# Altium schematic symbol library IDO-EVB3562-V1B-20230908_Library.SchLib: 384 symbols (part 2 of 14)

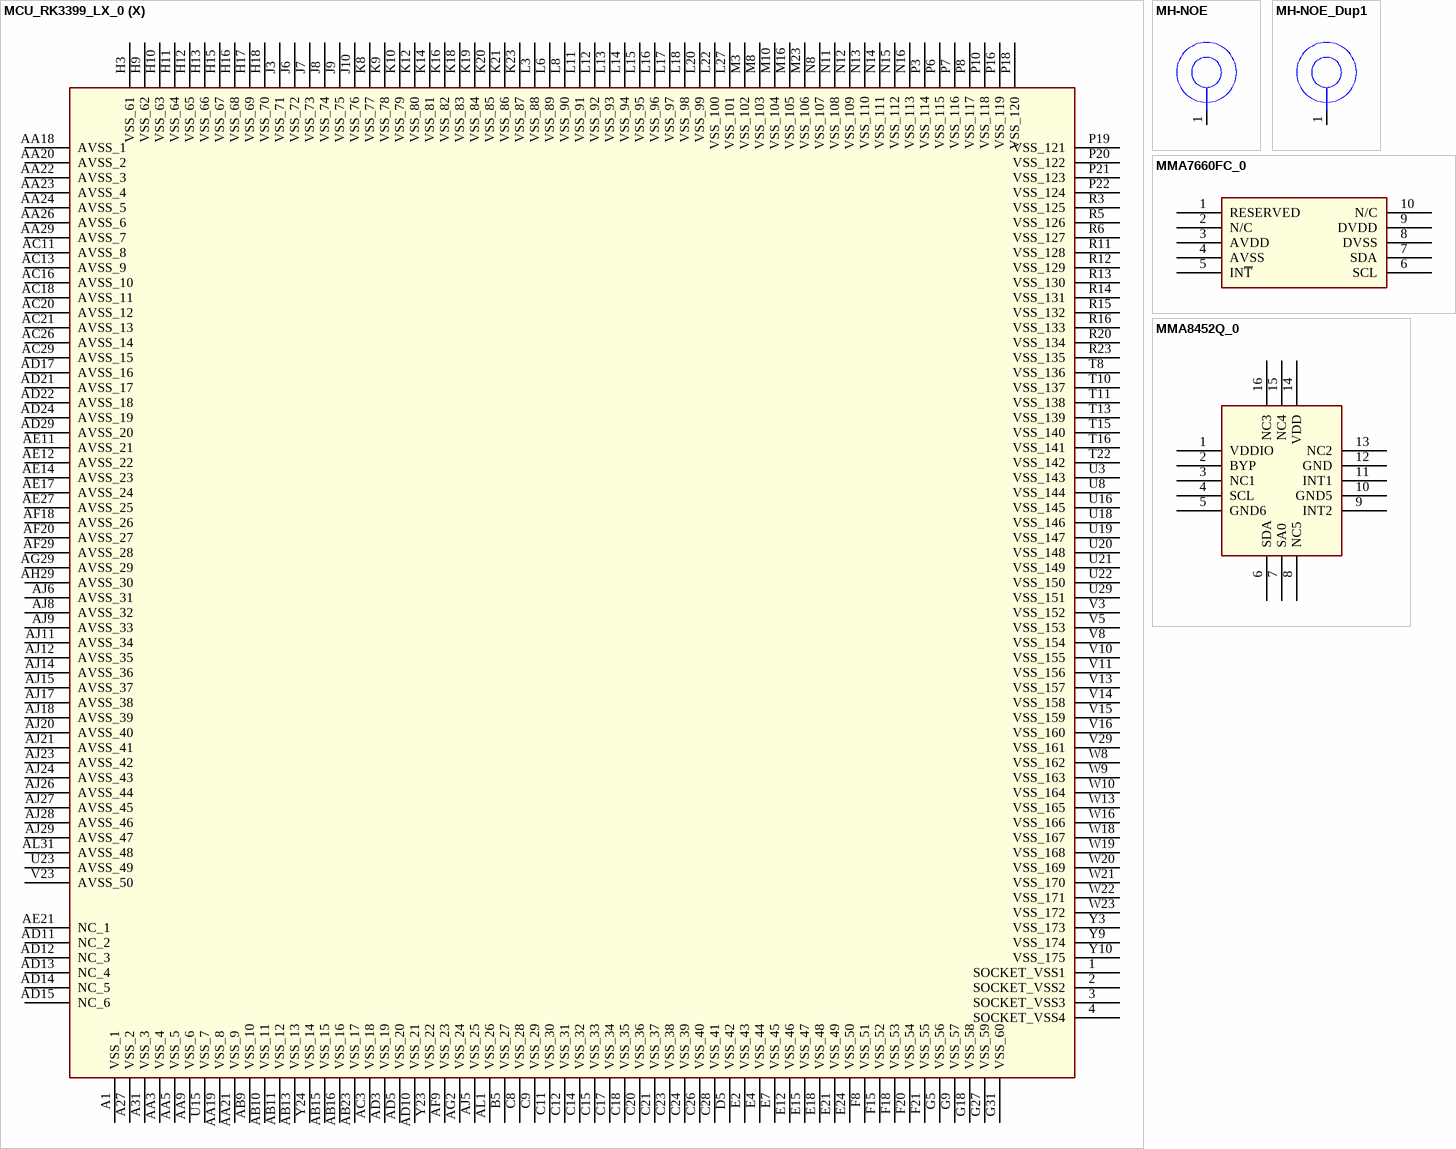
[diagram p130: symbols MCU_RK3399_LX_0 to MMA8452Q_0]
## MCU_RK3399_LX_0
designator U?
part A pins: A2 DDR0_CS1N, A3 DDR0_A12, A4 DDR0_A10, A5 DDR0_CKE0, A6 DDR0_A9, A7 DDR0_A7, A8 DDR0_A5, A9 DDR0_A3, A10 DDR0_A1, A11 DDR0_DQ10, A12 DDR0_DQ12, A13 DDR0_DQ13, A14 DDR0_DQ14, A15 DDR0_DQ1, A16 DDR0_DQ3, A17 DDR0_DQ5, A18 DDR0_DQ6, A19 DDR0_DQ16, A20 DDR0_DQ18, A21 DDR0_DQ20, A22 DDR0_DQ23, A23 DDR0_DQ24, A24 DDR0_DQ26, A25 DDR0_DQ27, A26 DDR0_DQ29, B2 DDR0_BA0, B3 DDR0_CS3N, B4 DDR0_A13, B6 DDR0_A8, B7 DDR0_A6, B8 DDR0_A4, B9 DDR0_A2, B10 DDR0_A0, B11 DDR0_DQ8, B12 DDR0_DQ9, B13 DDR0_DQ11, B14 DDR0_DQ15, B15 DDR0_DQ0, B16 DDR0_DQ2, B17 DDR0_DQ4, B18 DDR0_DQ7, B19 DDR0_DQ17, B20 DDR0_DQ19, B21 DDR0_DQ21, B22 DDR0_DQ22, B23 DDR0_DQ25, B24 DDR0_DQ28, B25 DDR0_DQ30, B26 DDR0_DQ31, C4 DDR0_A14, C5 DDR0_A11, C6 DDR0_RASN, D6 DDR0_BA1, D8 DDR0_CK0N, D9 DDR0_CK0P, D11 DDR0_ODT0, D12 DDR0_BA2, D14 DDR0_DQS1N, D15 DDR0_DQS1, D17 DDR0_DQS0N, D18 DDR0_DQS0, D20 DDR0_DQS2N, D21 DDR0_DQS2, D23 DDR0_DQS3N, D24 DDR0_DQS3, E6 DDR0_CKE1, E8 DDR0_CK1N, E9 DDR0_CK1P, E11 DDR0_ODT1, E14 DDR0_DM1, E17 DDR0_DM0, E20 DDR0_DM2, E23 DDR0_DM3, F7 DDR0_WEN, F9 DDR0_CASN, F11 DDR0_CS2N, F12 DDR0_CS0N, F14 DDR0_PLL_TESTOUT_P, F17 DDR0_ATB0, G8 DDR0_A15, G11 DDR0_RESET, G14 DDR0_PLL_TESTOUT_N, G15 DDR0_PZQ, G17 DDR0_ATB1, J11 DDR0_VDD_1, J12 DDR0_VDD_2, J13 DDR0_VDD_3, J14 DDR0_VDD_4, J15 DDR0_VDD_5, J16 DDR0_VDD_6, J17 DDR0_VDD_7, J18 DDR0_VDD_8, K11 DDR0_VDD_9, K13 DDR0_VDD_10, K15 DDR0_VDD_11, K17 DDR0_VDD_12, M7 DDR0_CLK_VDD, R8 DDR0PLL_AVDD_0V9
part B pins: AA1 DDR1_DQ3, AA2 DDR1_DQ2, AA4 DDR1_DQS0N, AB1 DDR1_DQ1, AB2 DDR1_DQ0, AC1 DDR1_DQ14, AC2 DDR1_DQ15, AC4 DDR1_DQS1, AC5 DDR1_DM1, AD1 DDR1_DQ13, AD2 DDR1_DQ11, AD4 DDR1_DQS1N, AE1 DDR1_DQ12, AE2 DDR1_DQ9, AF1 DDR1_DQ10, AF2 DDR1_DQ8, B1 DDR1_CS1N, C1 DDR1_A12, C2 DDR1_CSN3, C3 DDR1_BA0, D1 DDR1_A10, D2 DDR1_A13, D3 DDR1_A14, E1 DDR1_CKE0, E3 DDR1_A11, F1 DDR1_A1, F2 DDR1_A0, F3 DDR1_RASN, F4 DDR1_BA1, F5 DDR1_CKE1, G1 DDR1_A2, G2 DDR1_A3, G6 DDR1_WEN, G12 DDR1_CLK_VDD, H1 DDR1_A5, H2 DDR1_A4, H4 DDR1_CK0P, H5 DDR1_CK1P, H6 DDR1_CASN, H7 DDR1_A15, H14 DDR1PLL_AVDD_0V9, J1 DDR1_A6, J2 DDR1_A7, J4 DDR1_CK0N, J5 DDR1_CK1N, K1 DDR1_A9, K2 DDR1_A8, L1 DDR1_DQ29, L2 DDR1_DQ31, L4 DDR1_ODT0, L5 DDR1_ODT1, L7 DDR1_RESET, L9 DDR1_VDD_1, L10 DDR1_VDD_2, M1 DDR1_DQ27, M2 DDR1_DQ30, M4 DDR1_BA2, M5 DDR1_CSN2, M6 DDR1_CS0N, M9 DDR1_VDD_3, N1 DDR1_DQ26, N2 DDR1_DQ28, N9 DDR1_VDD_4, N10 DDR1_VDD_5, P1 DDR1_DQ24, P2 DDR1_DQ25, P4 DDR1_DQS3, P5 DDR1_DM3, P9 DDR1_VDD_6, R1 DDR1_DQ23, R2 DDR1_DQ22, R4 DDR1_DQS3N, R7 DDR1_PZQ, R9 DDR1_VDD_7, R10 DDR1_VDD_8, T1 DDR1_DQ20, T2 DDR1_DQ21, T9 DDR1_VDD_9, U1 DDR1_DQ18, U2 DDR1_DQ19, U4 DDR1_DQS2, U5 DDR1_DM2, U6 DDR1_ATB1, U7 DDR1_ATB0, U9 DDR1_VDD_10, U10 DDR1_VDD_11, V1 DDR1_DQ16, V2 DDR1_DQ17, V4 DDR1_DQS2N, V6 DDR1_PLL_TESTOUT_P, V7 DDR1_PLL_TESTOUT_N, V9 DDR1_VDD_12, W1 DDR1_DQ6, W2 DDR1_DQ7, Y1 DDR1_DQ5, Y2 DDR1_DQ4, Y4 DDR1_DQS0, Y5 DDR1_DM0
part C pins: AA16 PLL_AVDD_1V8, AA17 PLL_AVDD_0V9, AD23 EFUSE_VQPS, R24 PMUIO1_VDDPST, R25 GPIO0_B5/TCPD_VBUS_FDIS/TCPD_VBUS_SOURCE3_d, T24 PMU_VDD_0V9, T30 GPIO0_A2/WIFI_26MHZ_d, T31 GPIO0_A6/PWMA3_IR_d, U26 GPIO0_B0/SDMMC0_WRPRT/TEST_CLKOUT2_u, U27 GPIO0_A1/DDRIO_PWROFF/TCPD_CCDB_EN_u, U28 NPOR_u, U30 GPIO0_B3_d, U31 GPIO0_A0/TEST_CLKOUT0/CLK32K_IN_u, V24 PMU_VDD_1V8, V26 GPIO0_B4/TCPD_VBUS_BDIS_d, V27 GPIO0_A5/EMMC_PWRON_u, V28 GPIO0_A7/SDMMC0_DET_u, V30 GPIO0_B1/PMUIO2_VOLSEL_d, V31 GPIO0_A3/SDIO0_WRPT_d, W24 PMUIO1_VDD, W30 GPIO0_A4/SDIO0_INTN_d, W31 GPIO0_B2_d, Y16 PLL_AVSS, Y29 OSC_AVSS, Y30 XOUT_OSC, Y31 XIN_OSC
part D pins: AA25 USB_AVDD_3V3, AA30 TYPEC1_DP, AA31 TYPEC1_DM, AB30 HOST1_DP, AB31 HOST1_DM, AC25 USB_AVDD_0V9, AC30 TYPEC0_DP, AC31 TYPEC0_DM, AD25 USB_AVDD_1V8, AD26 TYPEC1_USB2.0_VBUSDET, AD30 HOST0_DP, AD31 HOST0_DM, AE26 TYPEC1_ID, AF25 TYPEC0_USB2.0_VBUSDET, AG26 USB1_RBIAS, AG28 TYPEC0_ID, AH27 USB0_RBIAS0
part E pins: L30 GPIO1_D0/TCPD_VBUS_SOURCE2_d, L31 GPIO1_C6/TCPD_VBUS_SOURCE0_d, M24 GPIO1_C1/SPI3_CLK_d, M25 GPIO1_C7/TCPD_VBUS_SOURCE1_d, M26 GPIO1_C5/I2C8_SCL_u, M27 GPIO1_C3/PWM2_d, M28 GPIO1_C4/I2C8_SDA_u, M29 GPIO1_C2/SPI3_CSN0_u, M30 GPIO1_B6/PWM3_IR_d, M31 GPIO1_C0/SPI3_TXD/I2C0_SCL_u, N23 PMUIO2_VDDPST, N24 GPIO1_B4/I2C4_SCL_u, N30 GPIO1_B5_d, N31 GPIO1_B7/SPI3_RXD/I2C0_SDA_u, P23 PMUIO2_VDD, P24 GPIO1_A1/ISP0_SHUTTER_TRIG/ISP1_SHUTTER_TRIG/TCPD_CC0_VCONN_EN_d, P25 GPIO1_A2/ISP0_FLASHTRIGIN/ISP1_FLASHTRIGIN/TCPD_CC1_VCONN_EN_d, P26 GPIO1_A5/AP_PWROFF_d, P27 GPIO1_A7/SPI1_RXD/UART4_RX_u, P28 GPIO1_B1/SPI1_CLK/PMCU_JTAG_TCK_u, P29 GPIO1_B0/SPI1_TXD/UART4_TX_u, P30 GPIO1_B2/SPI1_CSN0/PMCU_JTAG_TMS_u, P31 GPIO1_B3/I2C4_SDA_u, R26 DFTJTAG_TRSTN_d, R27 DFTJTAG_TMS_u, R28 GPIO1_A3/ISP0_FLASHTRIGOUT/ISP1_FLASHTRIGOUT_d, R29 GPIO1_A0/ISP0_SHUTTER_EN/ISP1_SHUTTER_EN/TCPD_VBUS_SINK_EN_d, R30 GPIO1_A4/ISP0_PRELIGHT_TRIG/ISP1_PRELIGHT_TRIG_d, R31 GPIO1_A6/TSADC_INT_d
part F pins: T23 SDMMC0_VDD, U24 SDMMC0_VDDPST, U25 GPIO4_B3/SDMMC0_D3_u, V25 GPIO4_B5/SDMMC0_CMD/MCUJTAG_TMS_u, Y25 GPIO4_B1/SDMMC0_D1/UART2A_TX_u, Y26 GPIO4_B0/SDMMC0_D0/UART2A_RX_u, Y27 GPIO4_B2/SDMMC0_D2_u, Y28 GPIO4_B4/SDMMC0_CLKO/MUCJTAG_TCK_d
part G pins: AB8 APIO3_VDDPST, AD7 GPIO2_C7/SDIO0_D3/SPI5_CSN0_u, AE6 GPIO2_C6/SDIO0_D2/SPI5_CLK_u, AG4 GPIO2_D2/SDIO0_DETN/PCIE_CLKREQN_u, AH3 GPIO2_D1/SDIO0_CLKOUT/TEST_CLKOUT1_u, AH5 GPIO2_C1/UART0_TX_u, AJ3 GPIO2_C3/UART0_RTSN_u, AJ4 GPIO2_D3/SDIO0_PWREN_d, AK1 GPIO2_D0/SDIO0_CMD_u, AK2 GPIO2_C5/SDIO0_D1/SPI5_TXD_u, AK3 GPIO2_C2/UART0_CTSN_u, AK4 GPIO2_C0/UART0_RX_u, AL2 GPIO2_C4/SDIO0_D0/SPI5_RXD_u, AL3 GPIO2_D4/SDIO0_BKPWR_d
part H pins: A28 EMMC_D0, A29 EMMC_D1, A30 EMMC_D2, B27 EMMC_D5, B28 EMMC_D4, B29 EMMC_D3, C27 EMMC_D7, D26 EMMC_CMD, D27 EMMC_D6, E25 EMMC_CALIO, E26 EMMC_CLK, F25 EMMC_STRB, G20 EMMC_TP, H19 EMMC_VDD_1V8_1, H20 EMMC_COREDLL_0V9, J19 EMMC_VDD_1V8_2
part I pins: H28 GPIO3_A4/MAC_TXD0/SPI0_RXD_d, H29 GPIO3_B1/MAC_RXDV_d, H30 GPIO3_A3/MAC_RXD3/SPI4_CSN0_u, H31 GPIO3_B7/MAC_CRS/CIF_CLKOUTB/UART3_RX_u, J23 APIO1_VDD, J24 APIO1_VDDPST, J26 GPIO3_B2/MAC_RXER/I2C5_SDA_u, J27 GPIO3_A6/MAC_RXD0/SPI0_CLK_u, J28 GPIO3_B6/MAC_RXCLK/UART3_RX_u, J29 GPIO3_A0/MAC_TXD2/SPI4_RXD_d, J30 GPIO3_A5/MAC_TXD1/SPI0_TXD_d, J31 GPIO3_B3/MAC_CLK/I2C5_SCL_u, K24 GPIO3_C0/MAC_COL/UART3_CTSN/SPDIF_TX_u, K30 GPIO3_B4/MAC_TXEN/UART1_RX_u, K31 GPIO3_C1/MAC_TXCLK/UART3_RTSN_u, L24 GPIO3_A1/MAC_TXD3/SPI4_TXD_d, L25 GPIO3_A7/MAC_RXD1/SPI0_CSN0_u, L26 GPIO3_B5/MAC_MDIO/UART1_TX_u, L28 GPIO3_B0/MAC_MDC/SPI0_CSN1_u, L29 GPIO3_A2/MAC_RXD2/SPI4_CLK_u
part J pins: AA6 GPIO3_D5/I2S0_SDI2SDO2_d, AA7 GPIO4_A4/I2S1_LRCK_RX_d, AA8 APIO5_VDDPST, AC6 GPIO4_A7/I2S1_SDO0_d, AC7 GPIO4_A0/I2S_CLK_d, AD6 GPIO4_A6/I2S1_SDI0_d, AE5 GPIO3_D4/I2S0_SDI1SDO3_d, AF3 GPIO4_A3/I2S1_SCLK_d, AF4 GPIO3_D1/I2S0_LRCK_RX_d, AG1 GPIO4_A1/I2C1_SDA_u, AG3 GPIO3_D0/I2S0_SCLK_d, AH1 GPIO3_D7/I2S0_SDO0_d, AH2 GPIO3_D6/I2S0_SDI3SDO1_d, AJ1 GPIO4_A5/I2S1_LRCK_TX_d, AJ2 GPIO3_D2/I2S0_LRCK_TX_d, Y6 GPIO4_A2/I2C1_SCL_u, Y7 GPIO3_D3/I2S0_SDI0_d, Y8 APIO5_VDD
part K pins: AC8 APIO4_VDDPST, AC9 APIO4_VDD, AD8 GPIO4_D3_d, AD9 GPIO4_D4_d, AE8 GPIO4_C4/UART2C_TX_u, AE9 GPIO4_C0/I2C3_SDA/UART2B_RX_u, AF5 GPIO4_D2_d, AF7 GPIO4_C7/HDMI_CECINOUT/EDP_HOTPLUG_u, AF8 GPIO4_C2/PWM0/VOP0_PWM/VOP1_PWM_d, AG6 GPIO4_C5/SPDIF_TX_d, AG7 GPIO4_C1/I2C3_SCL/UART2B_TX_u, AG8 GPIO4_C6/PWM1_d, AH6 GPIO4_D5_d, AH8 GPIO4_D1/DP_HOTPLUG_d, AK5 GPIO4_D6_d, AL4 GPIO4_D0/PCIE_CLKREQNB_u, AL5 GPIO4_C3/UART2C_RX_u
part L pins: E28 GPIO2_A0/VOP_D0/CIF_D0/I2C2_SDA_u, F27 GPIO2_A5/VOP_D5/CIF_D5_d, F28 GPIO2_A7/VOP_D7/CIF_D7/I2C7_SDA_u, G24 GPIO2_B4/SPI2_CSN0_u, G26 GPIO2_B3/SPI2_CLK/VOP_DEN/CIF_CLKOUT_u, G30 GPIO2_B2/SPI2_TXD/CIF_CLKIN/I2C6_SCL_u, H22 GPIO2_A3/VOP_D3/CIF_D3_d, H23 GPIO2_B1/SPI2_RXD/CIF_HREF/I2C6_SDA_u, H24 GPIO2_A2/VOP_D2/CIF_D2_d, H25 GPIO2_A4/VOP_D4/CIF_D4_d, H26 GPIO2_B0/VOP_CLK/CIF_VSYNC/I2C7_SCL_u, H27 GPIO2_A1/VOP_D1/CIF_D1/I2C2_SCL_u, J22 APIO2_VDDPST, J25 GPIO2_A6/VOP_D6/CIF_D6_d, L23 APIO2_VDD
part M pins: B30 EDP_AUXP, B31 EDP_AUXN, C29 EDP_AVSS_1, C30 EDP_TX0P, C31 EDP_TX0N, D29 EDP_AVSS_2, D30 EDP_TX1P, D31 EDP_TX1N, E29 EDP_AVSS_3, E30 EDP_TX2P, E31 EDP_TX2N, F23 EDP_REXT, F24 EDP_CLK24M_IN, F29 EDP_AVSS_4, F30 EDP_TX3P, F31 EDP_TX3N, G21 EDP_DC_TP, G23 EDP_AVDD_0V9, H21 EDP_AVDD_1V8_1, J20 EDP_AVDD_1V8_2, J21 EDP_AVSS_5, K22 EDP_AVSS_6
part N pins: AC15 HDMI_AVDD_0V9_1, AD16 HDMI_AVDD_0V9_2, AE15 HDMI_HPD, AF15 HDMI_REXT, AF17 HDMI_AVDD_1V8, AK16 HDMI_TCP, AK17 HDMI_TX0P, AK18 HDMI_TX1P, AK19 HDMI_TX2P, AL16 HDMI_TCN, AL17 HDMI_TX0N, AL18 HDMI_TX1N, AL19 HDMI_TX2N
part O pins: AA27 PCIE_RX0_P, AA28 PCIE_RX0_N, AB24 PCIE_AVDD_0V9, AC24 PCIE_AVDD_1V8, AC27 PCIE_RX1_P, AC28 PCIE_RX1_N, AD27 PCIE_RX2_P, AD28 PCIE_RX2_N, AE30 PCIE_RCLK_100M_N, AE31 PCIE_RCLK_100M_P, AF27 PCIE_RX3_P, AF28 PCIE_RX3_N, AF30 PCIE_TX0_P, AF31 PCIE_TX0_N, AG30 PCIE_TX1_P, AG31 PCIE_TX1_N, AH30 PCIE_TX2_P, AH31 PCIE_TX2_N, AJ30 PCIE_TX3_P, AJ31 PCIE_TX3_N
part P pins: AC10 MIPI_TX1/RX1_AVDD_1V8, AF11 MIPI_TX1/RX1_REXT, AK6 MIPI_TX1/RX1_D0P, AK7 MIPI_TX1/RX1_D1P, AK8 MIPI_TX1/RX1_CLKP, AK9 MIPI_TX1/RX1_D2P, AK10 MIPI_TX1/RX1_D3P, AL6 MIPI_TX1/RX1_D0N, AL7 MIPI_TX1/RX1_D1N, AL8 MIPI_TX1/RX1_CLKN, AL9 MIPI_TX1/RX1_D2N, AL10 MIPI_TX1/RX1_D3N
part Q pins: AC12 MIPI_TX0_AVDD_1V8, AF12 MIPI_TX0_REXT, AG9 MIPI_TX0_D3P, AG11 MIPI_TX0_D2P, AG12 MIPI_TX0_CLKP, AG14 MIPI_TX0_D1P, AG15 MIPI_TX0_D0P, AH9 MIPI_TX0_D3N, AH11 MIPI_TX0_D2N, AH12 MIPI_TX0_CLKN, AH14 MIPI_TX0_D1N, AH15 MIPI_TX0_D0N
part R pins: AC14 MIPI_RX0_AVDD_1V8, AF14 MIPI_RX0_REXT, AK11 MIPI_RX0_D3P, AK12 MIPI_RX0_D2P, AK13 MIPI_RX0_CLKP, AK14 MIPI_RX0_D1P, AK15 MIPI_RX0_D0P, AL11 MIPI_RX0_D3N, AL12 MIPI_RX0_D2N, AL13 MIPI_RX0_CLKN, AL14 MIPI_RX0_D1N, AL15 MIPI_RX0_D0N
part S pins: AB17 TYPEC0_PHY_0V9_2, AB18 TYPEC0_AVDD_1V8, AB19 TYPEC0_PHY_0V9_1, AC17 TYPEC0_AVDD_3V3, AD18 TYPEC0_RCLKM, AD19 TYPEC0_USB3.0_VBUSDET, AE18 TYPEC0_RCLKP, AG17 TYPEC0_AUXM/PU_PD, AG18 TYPEC0_REXT, AG20 TYPEC0_REXT_CC, AH17 TYPEC0_AUXP/PD_PU, AH18 TYPEC0_CC1, AH20 TYPEC0_CC2, AK20 TYPEC0_AUXP, AK21 TYPEC0_RX1P, AK22 TYPEC0_TX1M, AK23 TYPEC0_RX2P, AK24 TYPEC0_TX2M, AL20 TYPEC0_AUXM, AL21 TYPEC0_RX1M, AL22 TYPEC0_TX1P, AL23 TYPEC0_RX2M, AL24 TYPEC0_TX2P
part T pins: AB20 TYPEC1_AVDD_0V9_1, AB21 TYPEC1_AVDD_1V8, AB22 TYPEC1_AVDD_0V9_2, AC19 TYPEC1_USB3.0_VBUSDET, AC22 TYPEC1_AVDD_3V3, AD20 TYPEC1_RCLKM, AE20 TYPEC1_RCLKP, AF21 TYPEC1_CC2, AG21 TYPEC1_REXT_CC, AG23 TYPEC1_AUXP/PD_PU, AH21 TYPEC1_CC1, AH23 TYPEC1_REXT, AH24 TYPEC1_AUXM/PU_PD, AK25 TYPEC1_RX1P, AK26 TYPEC1_TX1M, AK27 TYPEC1_RX2P, AK28 TYPEC1_TX2M, AK29 TYPEC1_AUXP, AL25 TYPEC1_RX1M, AL26 TYPEC1_TX1P, AL27 TYPEC1_RX2M, AL28 TYPEC1_TX2P, AL29 TYPEC1_AUXM
part U pins: AE23 USIC_AVDD_0V9, AF23 USIC_AVDD_1V2, AK30 USIC_STROBE, AK31 USIC_DATA
part V pins: AC23 ADC_AVDD, AE24 ADC_IN0, AF24 ADC_IN2, AG24 ADC_IN1, AG25 ADC_IN5, AH26 ADC_IN4, AL30 ADC_IN3
part W pins: AA10 GPU_VDD_1, AA11 GPU_VDD_2, AA12 GPU_VDD_3, AA13 GPU_VDD_4, AA14 GPU_VDD_5, AA15 GPU_VDD_6, AB12 GPU_VDD_8, AB14 LOGIC_VDD_20, L19 BIGCPU_VDD_1, L21 BIGCPU_VDD_2, M11 CENTERLOGIC_VDD_1, M12 CENTERLOGIC_VDD_2, M13 CENTERLOGIC_VDD_3, M14 CENTERLOGIC_VDD_4, M15 CENTERLOGIC_VDD_5, M17 LOGIC_VDD_1, M18 BIGCPU_VDD_3, M19 BIGCPU_VDD_4, M20 BIGCPU_VDD_5, M21 BIGCPU_VDD_6, M22 BIGCPU_VDD_7, N17 LOGIC_VDD_2, N18 BIGCPU_VDD_COM, N19 BIGCPU_VDD_9, N20 BIGCPU_VDD_10, N21 BIGCPU_VDD_11, N22 BIGCPU_VDD_8, P11 CENTERLOGIC_VDD_6, P12 CENTERLOGIC_VDD_7, P13 CENTERLOGIC_VDD_8, P14 CENTERLOGIC_VDD_9, P15 CENTERLOGIC_VDD_10, P17 LOGIC_VDD_3, R17 LOGIC_VDD_4, R18 LITCPU_VDD_1, R19 LITCPU_VDD_2, R21 LITCPU_VDD_3, R22 LITCPU_VDD_4, T12 GPU_VDD_9, T14 GPU_VDD_COM, T17 LOGIC_VDD_5, T18 LITCPU_VDD_5, T19 LITCPU_VDD_6, T20 LITCPU_VDD_7, T21 LITCPU_VDD_8, U11 GPU_VDD_10, U12 GPU_VDD_11, U13 GPU_VDD_22, U14 GPU_VDD_7, U17 LOGIC_VDD_6, V12 GPU_VDD_13, V17 LOGIC_VDD_7, V18 LOGIC_VDD_8, V19 LOGIC_VDD_9, V20 LOGIC_VDD_10, V21 LOGIC_VDD_11, V22 LOGIC_VDD_12, W11 GPU_VDD_14, W12 GPU_VDD_15, W14 GPU_VDD_16, W15 GPU_VDD_17, W17 LOGIC_VDD_13, Y11 GPU_VDD_18, Y12 GPU_VDD_19, Y13 GPU_VDD_20, Y14 GPU_VDD_21, Y15 GPU_VDD_12, Y17 LOGIC_VDD_14, Y18 LOGIC_VDD_15, Y19 LOGIC_VDD_16, Y20 LOGIC_VDD_17, Y21 LOGIC_VDD_18, Y22 LOGIC_VDD_19
part X pins: 1 SOCKET_VSS1, 2 SOCKET_VSS2, 3 SOCKET_VSS3, 4 SOCKET_VSS4, A1 VSS_1, A27 VSS_2, A31 VSS_3, AA3 VSS_4, AA5 VSS_5, AA9 VSS_6, AA18 AVSS_1, AA19 VSS_8, AA20 AVSS_2, AA21 VSS_9, AA22 AVSS_3, AA23 AVSS_4, AA24 AVSS_5, AA26 AVSS_6, AA29 AVSS_7, AB9 VSS_10, AB10 VSS_11, AB11 VSS_12, AB13 VSS_13, AB15 VSS_15, AB16 VSS_16, AB23 VSS_17, AC3 VSS_18, AC11 AVSS_8, AC13 AVSS_9, AC16 AVSS_10, AC18 AVSS_11, AC20 AVSS_12, AC21 AVSS_13, AC26 AVSS_14, AC29 AVSS_15, AD3 VSS_19, AD5 VSS_20, AD10 VSS_21, AD11 NC_2, AD12 NC_3, AD13 NC_4, AD14 NC_5, AD15 NC_6, AD17 AVSS_16, AD21 AVSS_17, AD22 AVSS_18, AD24 AVSS_19, AD29 AVSS_20, AE11 AVSS_21, AE12 AVSS_22, AE14 AVSS_23, AE17 AVSS_24, AE21 NC_1, AE27 AVSS_25, AF9 VSS_23, AF18 AVSS_26, AF20 AVSS_27, AF29 AVSS_28, AG2 VSS_24, AG29 AVSS_29, AH29 AVSS_30, AJ5 VSS_25, AJ6 AVSS_31, AJ8 AVSS_32, AJ9 AVSS_33, AJ11 AVSS_34, AJ12 AVSS_35, AJ14 AVSS_36, AJ15 AVSS_37, AJ17 AVSS_38, AJ18 AVSS_39, AJ20 AVSS_40, AJ21 AVSS_41, AJ23 AVSS_42, AJ24 AVSS_43, AJ26 AVSS_44, AJ27 AVSS_45, AJ28 AVSS_46, AJ29 AVSS_47, AL1 VSS_26, AL31 AVSS_48, B5 VSS_27, C8 VSS_28, C9 VSS_29, C11 VSS_30, C12 VSS_31, C14 VSS_32, C15 VSS_33, C17 VSS_34, C18 VSS_35, C20 VSS_36, C21 VSS_37, C23 VSS_38, C24 VSS_39, C26 VSS_40, C28 VSS_41, D5 VSS_42, E2 VSS_43, E4 VSS_44, E7 VSS_45, E12 VSS_46, E15 VSS_47, E18 VSS_48, E21 VSS_49, E24 VSS_50, F8 VSS_51, F15 VSS_52, F18 VSS_53, F20 VSS_54, F21 VSS_55, G5 VSS_56, G9 VSS_57, G18 VSS_58, G27 VSS_59, G31 VSS_60, H3 VSS_61, H9 VSS_62, H10 VSS_63, H11 VSS_64, H12 VSS_65, H13 VSS_66, H15 VSS_67, H16 VSS_68, H17 VSS_69, H18 VSS_70, J3 VSS_71, J6 VSS_72, J7 VSS_73, J8 VSS_74, J9 VSS_75, J10 VSS_76, K8 VSS_77, K9 VSS_78, K10 VSS_79, K12 VSS_80, K14 VSS_81, K16 VSS_82, K18 VSS_83, K19 VSS_84, K20 VSS_85, K21 VSS_86, K23 VSS_87, L3 VSS_88, L6 VSS_89, L8 VSS_90, L11 VSS_91, L12 VSS_92, L13 VSS_93, L14 VSS_94, L15 VSS_95, L16 VSS_96, L17 VSS_97, L18 VSS_98, L20 VSS_99, L22 VSS_100, L27 VSS_101, M3 VSS_102, M8 VSS_103, M10 VSS_104, M16 VSS_105, M23 VSS_106, N8 VSS_107, N11 VSS_108, N12 VSS_109, N13 VSS_110, N14 VSS_111, N15 VSS_112, N16 VSS_113, P3 VSS_114, P6 VSS_115, P7 VSS_116, P8 VSS_117, P10 VSS_118, P16 VSS_119, P18 VSS_120, P19 VSS_121, P20 VSS_122, P21 VSS_123, P22 VSS_124, R3 VSS_125, R5 VSS_126, R6 VSS_127, R11 VSS_128, R12 VSS_129, R13 VSS_130, R14 VSS_131, R15 VSS_132, R16 VSS_133, R20 VSS_134, R23 VSS_135, T8 VSS_136, T10 VSS_137, T11 VSS_138, T13 VSS_139, T15 VSS_140, T16 VSS_141, T22 VSS_142, U3 VSS_143, U8 VSS_144, U15 VSS_7, U16 VSS_145, U18 VSS_146, U19 VSS_147, U20 VSS_148, U21 VSS_149, U22 VSS_150, U23 AVSS_49, U29 VSS_151, V3 VSS_152, V5 VSS_153, V8 VSS_154, V10 VSS_155, V11 VSS_156, V13 VSS_157, V14 VSS_158, V15 VSS_159, V16 VSS_160, V23 AVSS_50, V29 VSS_161, W8 VSS_162, W9 VSS_163, W10 VSS_164, W13 VSS_165, W16 VSS_166, W18 VSS_167, W19 VSS_168, W20 VSS_169, W21 VSS_170, W22 VSS_171, W23 VSS_172, Y3 VSS_173, Y9 VSS_174, Y10 VSS_175, Y23 VSS_22, Y24 VSS_14

## MH-NOE
designator MH?
Part Number: CAD
footprint MH276_091
pins: 1

## MH-NOE_Dup1
designator MH?
Part Number: CAD
footprint MH276_091
pins: 1

## MMA7660FC_0
designator U?
pins: 1 RESERVED, 2 N/C, 3 AVDD, 4 AVSS, 5 IN~{T}, 6 SCL, 7 SDA, 8 DVSS, 9 DVDD, 10 N/C

## MMA8452Q_0
designator U?
footprint QFN16_COL
pins: 1 VDDIO, 2 BYP, 3 NC1, 4 SCL, 5 GND6, 6 SDA, 7 SA0, 8 NC5, 9 INT2, 10 GND5, 11 INT1, 12 GND, 13 NC2, 14 VDD, 15 NC4, 16 NC3


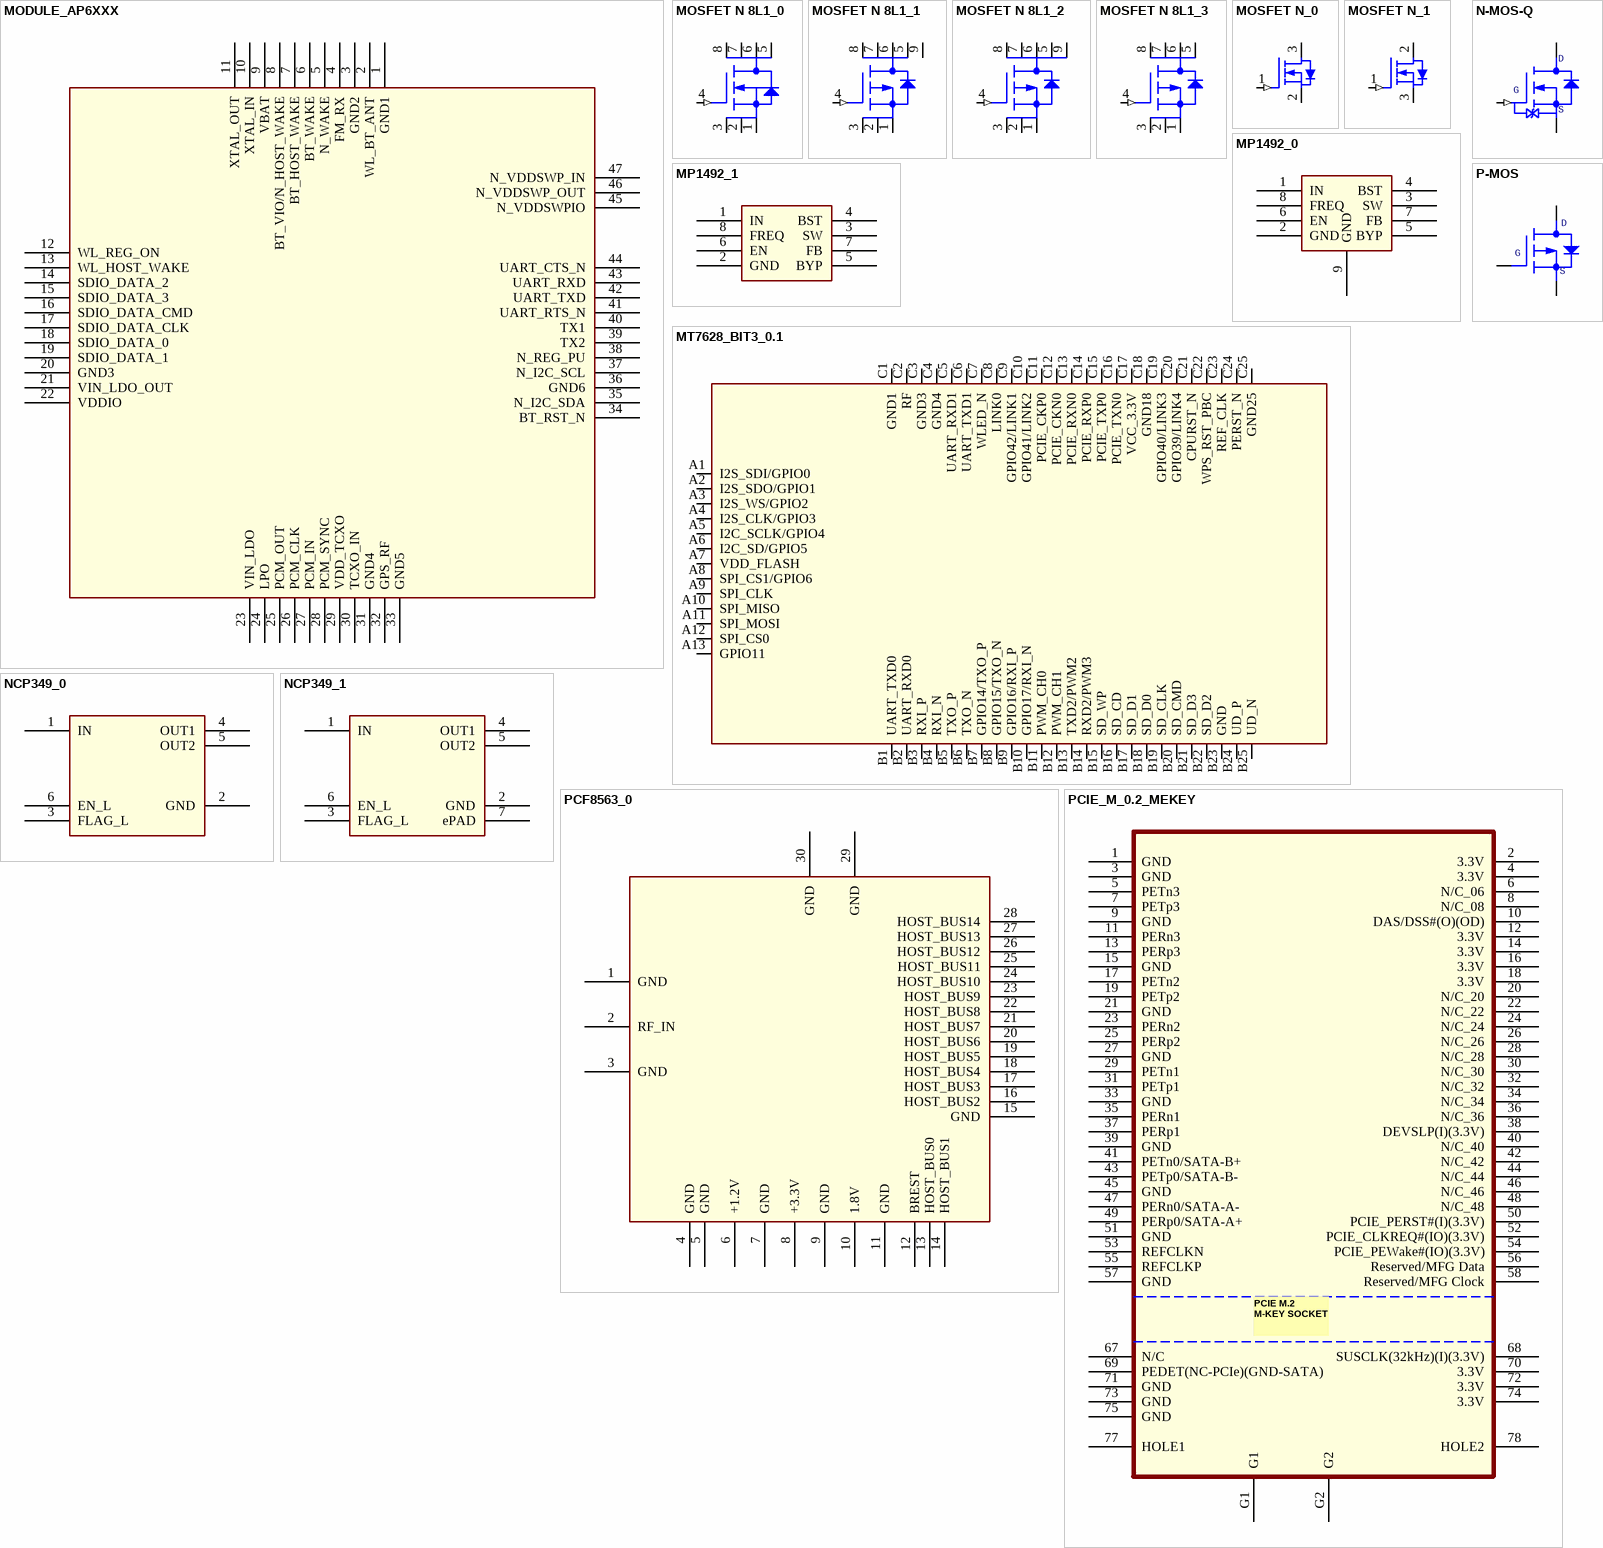
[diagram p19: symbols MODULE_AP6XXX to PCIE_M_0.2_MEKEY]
## MODULE_AP6XXX
designator U?
pins: 1 GND1, 2 WL_BT_ANT, 3 GND2, 4 FM_RX, 5 N_WAKE, 6 BT_WAKE, 7 BT_HOST_WAKE, 8 BT_VIO/N_HOST_WAKE, 9 VBAT, 10 XTAL_IN, 11 XTAL_OUT, 12 WL_REG_ON, 13 WL_HOST_WAKE, 14 SDIO_DATA_2, 15 SDIO_DATA_3, 16 SDIO_DATA_CMD, 17 SDIO_DATA_CLK, 18 SDIO_DATA_0, 19 SDIO_DATA_1, 20 GND3, 21 VIN_LDO_OUT, 22 VDDIO, 23 VIN_LDO, 24 LPO, 25 PCM_OUT, 26 PCM_CLK, 27 PCM_IN, 28 PCM_SYNC, 29 VDD_TCXO, 30 TCXO_IN, 31 GND4, 32 GPS_RF, 33 GND5, 34 BT_RST_N, 35 N_I2C_SDA, 36 GND6, 37 N_I2C_SCL, 38 N_REG_PU, 39 TX2, 40 TX1, 41 UART_RTS_N, 42 UART_TXD, 43 UART_RXD, 44 UART_CTS_N, 45 N_VDDSWPIO, 46 N_VDDSWP_OUT, 47 N_VDDSWP_IN

## MOSFET N 8L1_0
designator Q?
pins: 1 SOURCE1, 2 SOURCE2, 3 SOURCE3, 4 GATE (in), 5 DRAIN5, 6 DRAIN6, 7 DRAIN7, 8 DRAIN8

## MOSFET N 8L1_1
designator Q?
pins: 1 SOURCE1, 2 SOURCE2, 3 SOURCE3, 4 GATE (in), 5 DRAIN5, 6 DRAIN6, 7 DRAIN7, 8 DRAIN8, 9 DRAIN9

## MOSFET N 8L1_2
designator Q?
pins: 1 SOURCE1, 2 SOURCE2, 3 SOURCE3, 4 GATE (in), 5 DRAIN5, 6 DRAIN6, 7 DRAIN7, 8 DRAIN8, 9 DRAIN9

## MOSFET N 8L1_3
designator Q?
pins: 1 SOURCE1, 2 SOURCE2, 3 SOURCE3, 4 GATE (in), 5 DRAIN5, 6 DRAIN6, 7 DRAIN7, 8 DRAIN8

## MOSFET N_0
designator Q?
pins: 1 GATE (in), 2 SOURCE, 3 DRAIN

## MOSFET N_1
designator Q?
pins: 1 GATE (in), 2 DRAIN, 3 SOURCE

## MP1492_0
designator U?
footprint SOP8A
pins: 1 IN, 2 GND, 3 SW, 4 BST, 5 BYP, 6 EN, 7 FB, 8 FREQ, 9 GND

## MP1492_1
designator U?
footprint SOP8A
pins: 1 IN, 2 GND, 3 SW, 4 BST, 5 BYP, 6 EN, 7 FB, 8 FREQ

## MT7628_BIT3_0.1
designator U?
footprint MT7628_BIT3.1
pins: A1 I2S_SDI/GPIO0, A2 I2S_SDO/GPIO1, A3 I2S_WS/GPIO2, A4 I2S_CLK/GPIO3, A5 I2C_SCLK/GPIO4, A6 I2C_SD/GPIO5, A7 VDD_FLASH, A8 SPI_CS1/GPIO6, A9 SPI_CLK, A10 SPI_MISO, A11 SPI_MOSI, A12 SPI_CS0, A13 GPIO11, B1 UART_TXD0, B2 UART_RXD0, B3 RXI_P, B4 RXI_N, B5 TXO_P, B6 TXO_N, B7 GPIO14/TXO_P, B8 GPIO15/TXO_N, B9 GPIO16/RXI_P, B10 GPIO17/RXI_N, B11 PWM_CH0, B12 PWM_CH1, B13 TXD2/PWM2, B14 RXD2/PWM3, B15 SD_WP, B16 SD_CD, B17 SD_D1, B18 SD_D0, B19 SD_CLK, B20 SD_CMD, B21 SD_D3, B22 SD_D2, B23 GND, B24 UD_P, B25 UD_N, C1 GND1, C2 RF, C3 GND3, C4 GND4, C5 UART_RXD1, C6 UART_TXD1, C7 WLED_N, C8 LINK0, C9 GPIO42/LINK1, C10 GPIO41/LINK2, C11 PCIE_CKP0, C12 PCIE_CKN0, C13 PCIE_RXN0, C14 PCIE_RXP0, C15 PCIE_TXP0, C16 PCIE_TXN0, C17 VCC_3.3V, C18 GND18, C19 GPIO40/LINK3, C20 GPIO39/LINK4, C21 CPURST_N, C22 WPS_RST_PBC, C23 REF_CLK, C24 PERST_N, C25 GND25

## N-MOS-Q
designator Q?
pins: 1 GATE (in), 2 SOURCE, 3 DRAIN

## NCP349_0
designator U?
pins: 1 IN, 2 GND, 3 FLAG_L, 4 OUT1, 5 OUT2, 6 EN_L

## NCP349_1
designator U?
pins: 1 IN, 2 GND, 3 FLAG_L, 4 OUT1, 5 OUT2, 6 EN_L, 7 ePAD

## P-MOS
designator Q?
pins: 1 GATE, 2 SOURCE, 3 DRAIN

## PCF8563_0
designator U?
footprint SOP-8
pins: 1 GND, 2 RF_IN, 3 GND, 4 GND, 5 GND, 6 +1.2V, 7 GND, 8 +3.3V, 9 GND, 10 1.8V, 11 GND, 12 BREST, 13 HOST_BUS0, 14 HOST_BUS1, 15 GND, 16 HOST_BUS2, 17 HOST_BUS3, 18 HOST_BUS4, 19 HOST_BUS5, 20 HOST_BUS6, 21 HOST_BUS7, 22 HOST_BUS8, 23 HOST_BUS9, 24 HOST_BUS10, 25 HOST_BUS11, 26 HOST_BUS12, 27 HOST_BUS13, 28 HOST_BUS14, 29 GND, 30 GND
1 alternate drawing of the same symbol

## PCIE_M_0.2_MEKEY
designator J?
pins: 1 GND (power), 2 3.3V (power), 3 GND (power), 4 3.3V (power), 5 PETn3, 6 N/C_06, 7 PETp3, 8 N/C_08, 9 GND (power), 10 DAS/DSS#(O)(OD), 11 PERn3, 12 3.3V (power), 13 PERp3, 14 3.3V (power), 15 GND (power), 16 3.3V (power), 17 PETn2, 18 3.3V (power), 19 PETp2, 20 N/C_20, 21 GND (power), 22 N/C_22, 23 PERn2, 24 N/C_24, 25 PERp2, 26 N/C_26, 27 GND (power), 28 N/C_28, 29 PETn1, 30 N/C_30, 31 PETp1, 32 N/C_32, 33 GND (power), 34 N/C_34, 35 PERn1, 36 N/C_36, 37 PERp1, 38 DEVSLP(I)(3.3V), 39 GND (power), 40 N/C_40, 41 PETn0/SATA-B+, 42 N/C_42, 43 PETp0/SATA-B-, 44 N/C_44, 45 GND (power), 46 N/C_46, 47 PERn0/SATA-A-, 48 N/C_48, 49 PERp0/SATA-A+, 50 PCIE_PERST#(I)(3.3V), 51 GND (power), 52 PCIE_CLKREQ#(IO)(3.3V), 53 REFCLKN, 54 PCIE_PEWake#(IO)(3.3V), 55 REFCLKP, 56 Reserved/MFG Data, 57 GND (power), 58 Reserved/MFG Clock, 67 N/C, 68 SUSCLK(32kHz)(I)(3.3V), 69 PEDET(NC-PCIe)(GND-SATA), 70 3.3V (power), 71 GND (power), 72 3.3V (power), 73 GND (power), 74 3.3V (power), 75 GND (power), 77 HOLE1 (power), 78 HOLE2 (power), G1, G2


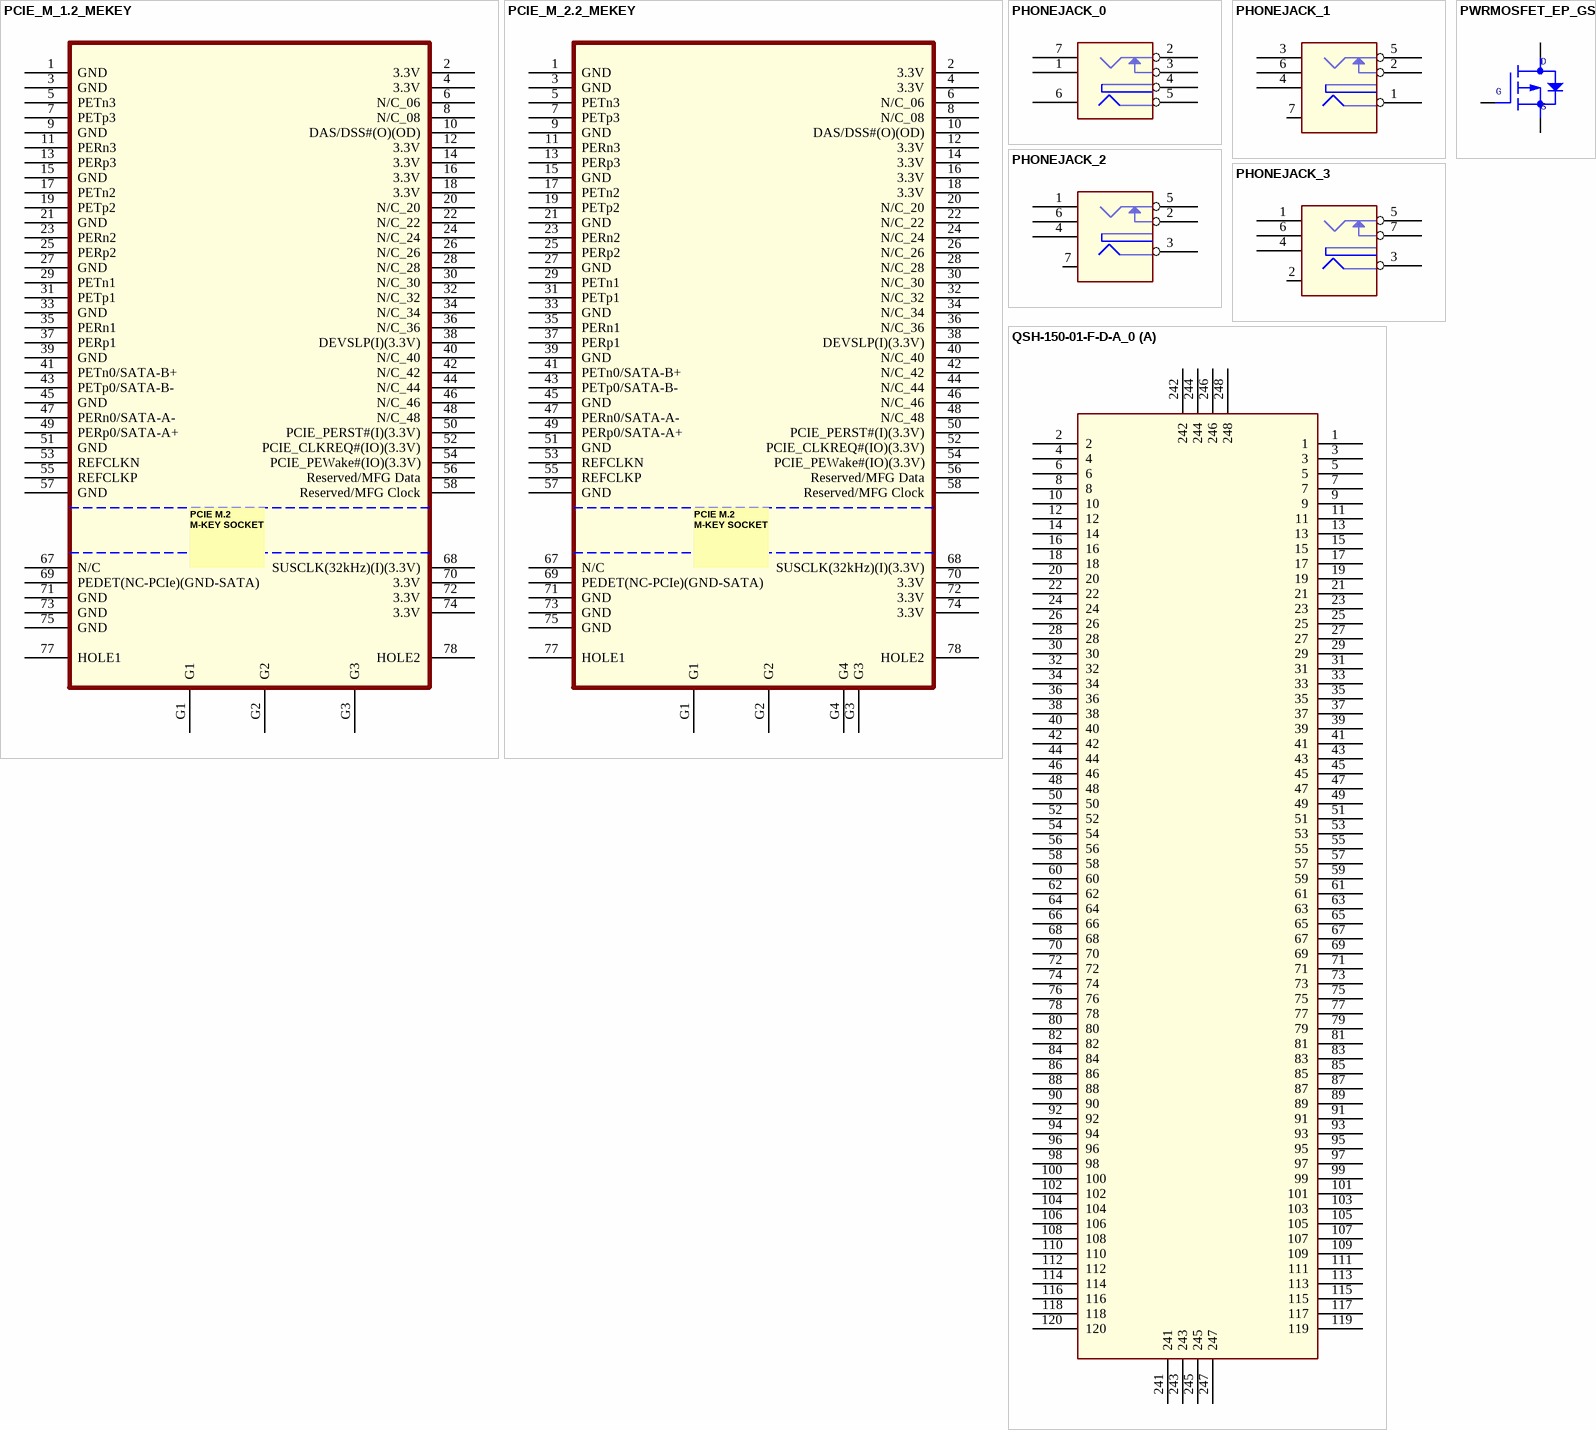
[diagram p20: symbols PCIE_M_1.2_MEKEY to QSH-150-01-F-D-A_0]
## PCIE_M_1.2_MEKEY
designator J?
pins: 1 GND (power), 2 3.3V (power), 3 GND (power), 4 3.3V (power), 5 PETn3, 6 N/C_06, 7 PETp3, 8 N/C_08, 9 GND (power), 10 DAS/DSS#(O)(OD), 11 PERn3, 12 3.3V (power), 13 PERp3, 14 3.3V (power), 15 GND (power), 16 3.3V (power), 17 PETn2, 18 3.3V (power), 19 PETp2, 20 N/C_20, 21 GND (power), 22 N/C_22, 23 PERn2, 24 N/C_24, 25 PERp2, 26 N/C_26, 27 GND (power), 28 N/C_28, 29 PETn1, 30 N/C_30, 31 PETp1, 32 N/C_32, 33 GND (power), 34 N/C_34, 35 PERn1, 36 N/C_36, 37 PERp1, 38 DEVSLP(I)(3.3V), 39 GND (power), 40 N/C_40, 41 PETn0/SATA-B+, 42 N/C_42, 43 PETp0/SATA-B-, 44 N/C_44, 45 GND (power), 46 N/C_46, 47 PERn0/SATA-A-, 48 N/C_48, 49 PERp0/SATA-A+, 50 PCIE_PERST#(I)(3.3V), 51 GND (power), 52 PCIE_CLKREQ#(IO)(3.3V), 53 REFCLKN, 54 PCIE_PEWake#(IO)(3.3V), 55 REFCLKP, 56 Reserved/MFG Data, 57 GND (power), 58 Reserved/MFG Clock, 67 N/C, 68 SUSCLK(32kHz)(I)(3.3V), 69 PEDET(NC-PCIe)(GND-SATA), 70 3.3V (power), 71 GND (power), 72 3.3V (power), 73 GND (power), 74 3.3V (power), 75 GND (power), 77 HOLE1 (power), 78 HOLE2 (power), G1, G2, G3

## PCIE_M_2.2_MEKEY
designator J?
pins: 1 GND (power), 2 3.3V (power), 3 GND (power), 4 3.3V (power), 5 PETn3, 6 N/C_06, 7 PETp3, 8 N/C_08, 9 GND (power), 10 DAS/DSS#(O)(OD), 11 PERn3, 12 3.3V (power), 13 PERp3, 14 3.3V (power), 15 GND (power), 16 3.3V (power), 17 PETn2, 18 3.3V (power), 19 PETp2, 20 N/C_20, 21 GND (power), 22 N/C_22, 23 PERn2, 24 N/C_24, 25 PERp2, 26 N/C_26, 27 GND (power), 28 N/C_28, 29 PETn1, 30 N/C_30, 31 PETp1, 32 N/C_32, 33 GND (power), 34 N/C_34, 35 PERn1, 36 N/C_36, 37 PERp1, 38 DEVSLP(I)(3.3V), 39 GND (power), 40 N/C_40, 41 PETn0/SATA-B+, 42 N/C_42, 43 PETp0/SATA-B-, 44 N/C_44, 45 GND (power), 46 N/C_46, 47 PERn0/SATA-A-, 48 N/C_48, 49 PERp0/SATA-A+, 50 PCIE_PERST#(I)(3.3V), 51 GND (power), 52 PCIE_CLKREQ#(IO)(3.3V), 53 REFCLKN, 54 PCIE_PEWake#(IO)(3.3V), 55 REFCLKP, 56 Reserved/MFG Data, 57 GND (power), 58 Reserved/MFG Clock, 67 N/C, 68 SUSCLK(32kHz)(I)(3.3V), 69 PEDET(NC-PCIe)(GND-SATA), 70 3.3V (power), 71 GND (power), 72 3.3V (power), 73 GND (power), 74 3.3V (power), 75 GND (power), 77 HOLE1 (power), 78 HOLE2 (power), G1, G2, G3, G4

## PHONEJACK_0
designator J?
pins: 1, 2, 3, 4, 5, 6, 7

## PHONEJACK_1
designator J?
pins: 1, 2, 3, 4, 5, 6, 7

## PHONEJACK_2
designator J?
pins: 1, 2, 3, 4, 5, 6, 7

## PHONEJACK_3
designator J?
pins: 1, 2, 3, 4, 5, 6, 7

## PWRMOSFET_EP_GSD_0
designator Q?
pins: 1 GATE, 2 SOURCE, 3 DRAIN


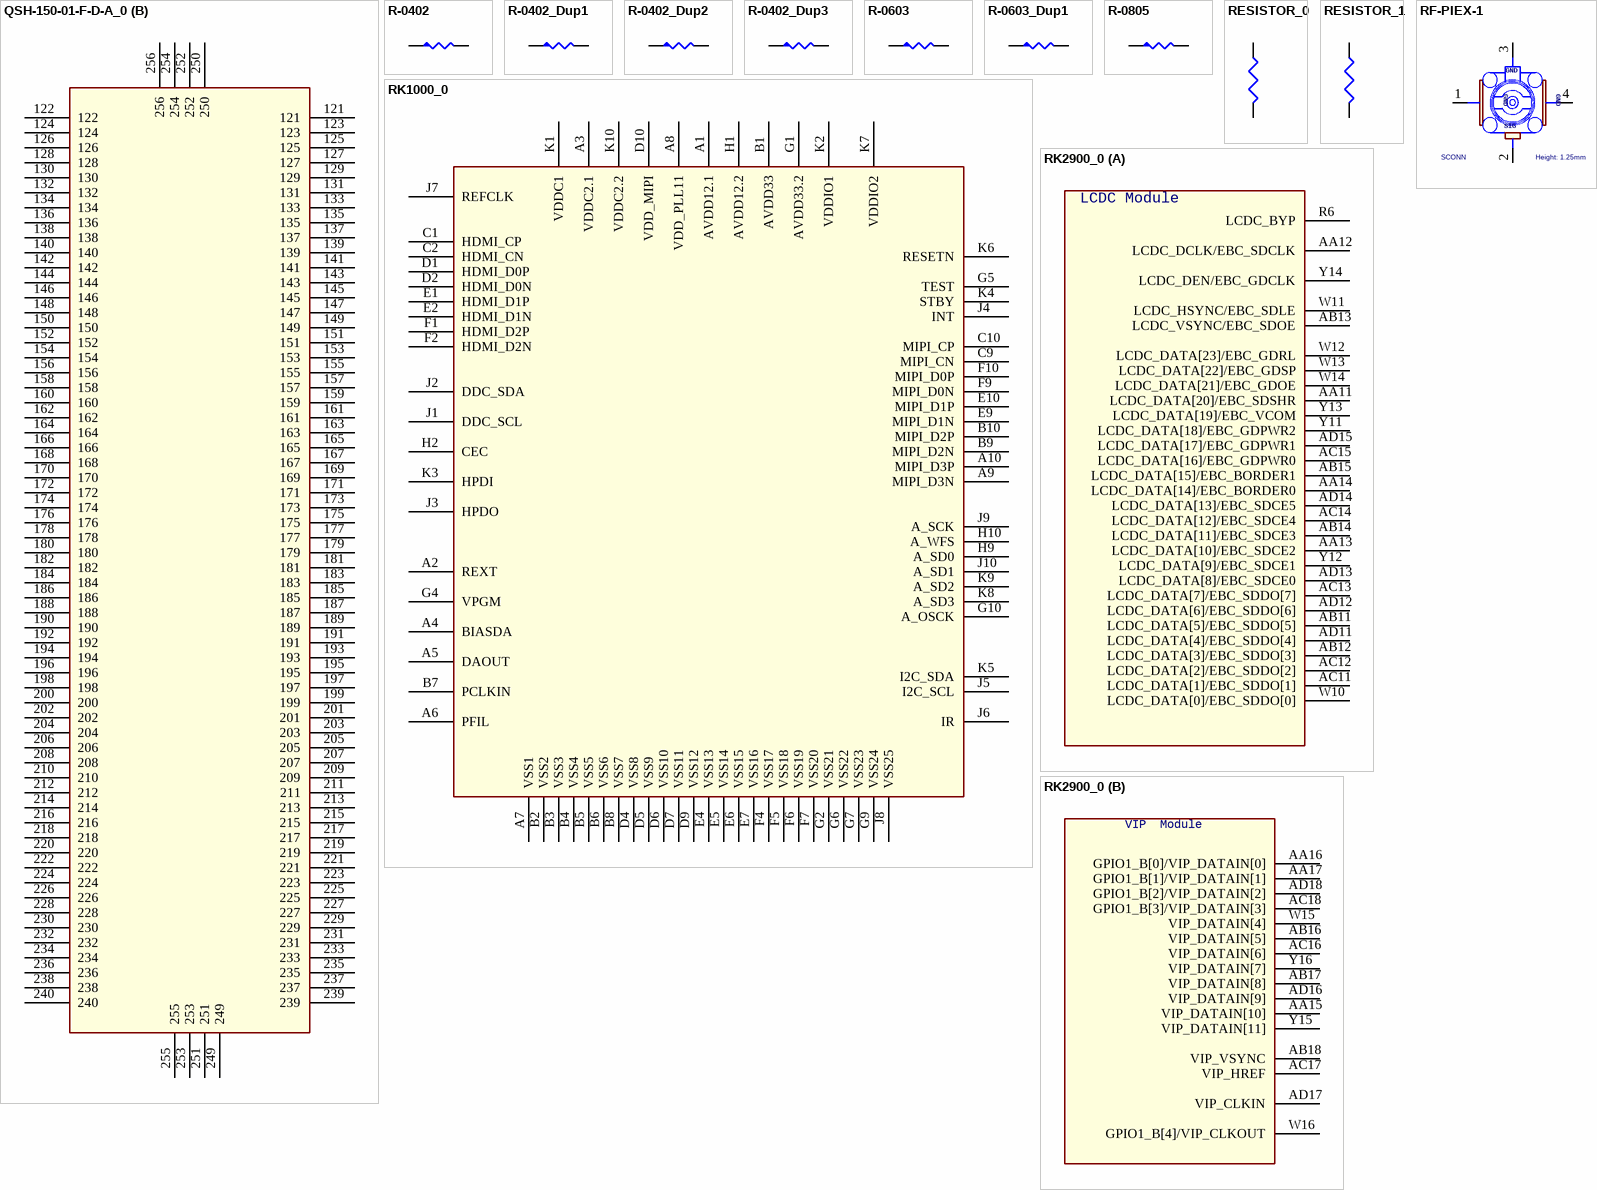
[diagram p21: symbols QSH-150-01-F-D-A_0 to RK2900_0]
## QSH-150-01-F-D-A_0
designator J?
footprint CON320
part A pins: 1, 2, 3, 4, 5, 6, 7, 8, 9, 10, 11, 12, 13, 14, 15, 16, 17, 18, 19, 20, 21, 22, 23, 24, 25, 26, 27, 28, 29, 30, 31, 32, 33, 34, 35, 36, 37, 38, 39, 40, 41, 42, 43, 44, 45, 46, 47, 48, 49, 50, 51, 52, 53, 54, 55, 56, 57, 58, 59, 60, 61, 62, 63, 64, 65, 66, 67, 68, 69, 70, 71, 72, 73, 74, 75, 76, 77, 78, 79, 80, 81, 82, 83, 84, 85, 86, 87, 88, 89, 90, 91, 92, 93, 94, 95, 96, 97, 98, 99, 100, 101, 102, 103, 104, 105, 106, 107, 108, 109, 110, 111, 112, 113, 114, 115, 116, 117, 118, 119, 120, 241, 242, 243, 244, 245, 246, 247, 248
part B pins: 121, 122, 123, 124, 125, 126, 127, 128, 129, 130, 131, 132, 133, 134, 135, 136, 137, 138, 139, 140, 141, 142, 143, 144, 145, 146, 147, 148, 149, 150, 151, 152, 153, 154, 155, 156, 157, 158, 159, 160, 161, 162, 163, 164, 165, 166, 167, 168, 169, 170, 171, 172, 173, 174, 175, 176, 177, 178, 179, 180, 181, 182, 183, 184, 185, 186, 187, 188, 189, 190, 191, 192, 193, 194, 195, 196, 197, 198, 199, 200, 201, 202, 203, 204, 205, 206, 207, 208, 209, 210, 211, 212, 213, 214, 215, 216, 217, 218, 219, 220, 221, 222, 223, 224, 225, 226, 227, 228, 229, 230, 231, 232, 233, 234, 235, 236, 237, 238, 239, 240, 249, 250, 251, 252, 253, 254, 255, 256

## R-0402
designator R?
pins: 1, 2

## R-0402_Dup1
designator R?
pins: 1, 2

## R-0402_Dup2
designator R?
pins: 1, 2

## R-0402_Dup3
designator R?
pins: 1, 2

## R-0603
designator R?
pins: 1, 2

## R-0603_Dup1
designator R?
pins: 1, 2

## R-0805
designator R?
pins: 1, 2

## RESISTOR_0
designator R?
pins: 1, 2

## RESISTOR_1
designator R?
pins: 1, 2

## RF-PIEX-1
designator IPEX?  Height: 1.25mm  Material: SCONN
SMD micro Coaxial Connector Receptacle vertial; Part_Name: MHF-20279
pins: 1 GND1, 2 SIG, 3 GND2, 4 GND3

## RK1000_0
designator U?
footprint LQFP128
pins: A1 AVDD12.1, A2 REXT, A3 VDDC2.1, A4 BIASDA, A5 DAOUT, A6 PFIL, A7 VSS1, A8 VDD_PLL11, A9 MIPI_D3N, A10 MIPI_D3P, B1 AVDD33, B2 VSS2, B3 VSS3, B4 VSS4, B5 VSS5, B6 VSS6, B7 PCLKIN, B8 VSS7, B9 MIPI_D2N, B10 MIPI_D2P, C1 HDMI_CP, C2 HDMI_CN, C9 MIPI_CN, C10 MIPI_CP, D1 HDMI_D0P, D2 HDMI_D0N, D4 VSS8, D5 VSS9, D6 VSS10, D7 VSS11, D9 VSS12, D10 VDD_MIPI, E1 HDMI_D1P, E2 HDMI_D1N, E4 VSS13, E5 VSS14, E6 VSS15, E7 VSS16, E9 MIPI_D1N, E10 MIPI_D1P, F1 HDMI_D2P, F2 HDMI_D2N, F4 VSS17, F5 VSS18, F6 VSS19, F7 VSS20, F9 MIPI_D0N, F10 MIPI_D0P, G1 AVDD33.2, G2 VSS21, G4 VPGM, G5 TEST, G6 VSS22, G7 VSS23, G9 VSS24, G10 A_OSCK, H1 AVDD12.2, H2 CEC, H9 A_SD0, H10 A_WFS, J1 DDC_SCL, J2 DDC_SDA, J3 HPDO, J4 INT, J5 I2C_SCL, J6 IR, J7 REFCLK, J8 VSS25, J9 A_SCK, J10 A_SD1, K1 VDDC1, K2 VDDIO1, K3 HPDI, K4 STBY, K5 I2C_SDA, K6 RESETN, K7 VDDIO2, K8 A_SD3, K9 A_SD2, K10 VDDC2.2




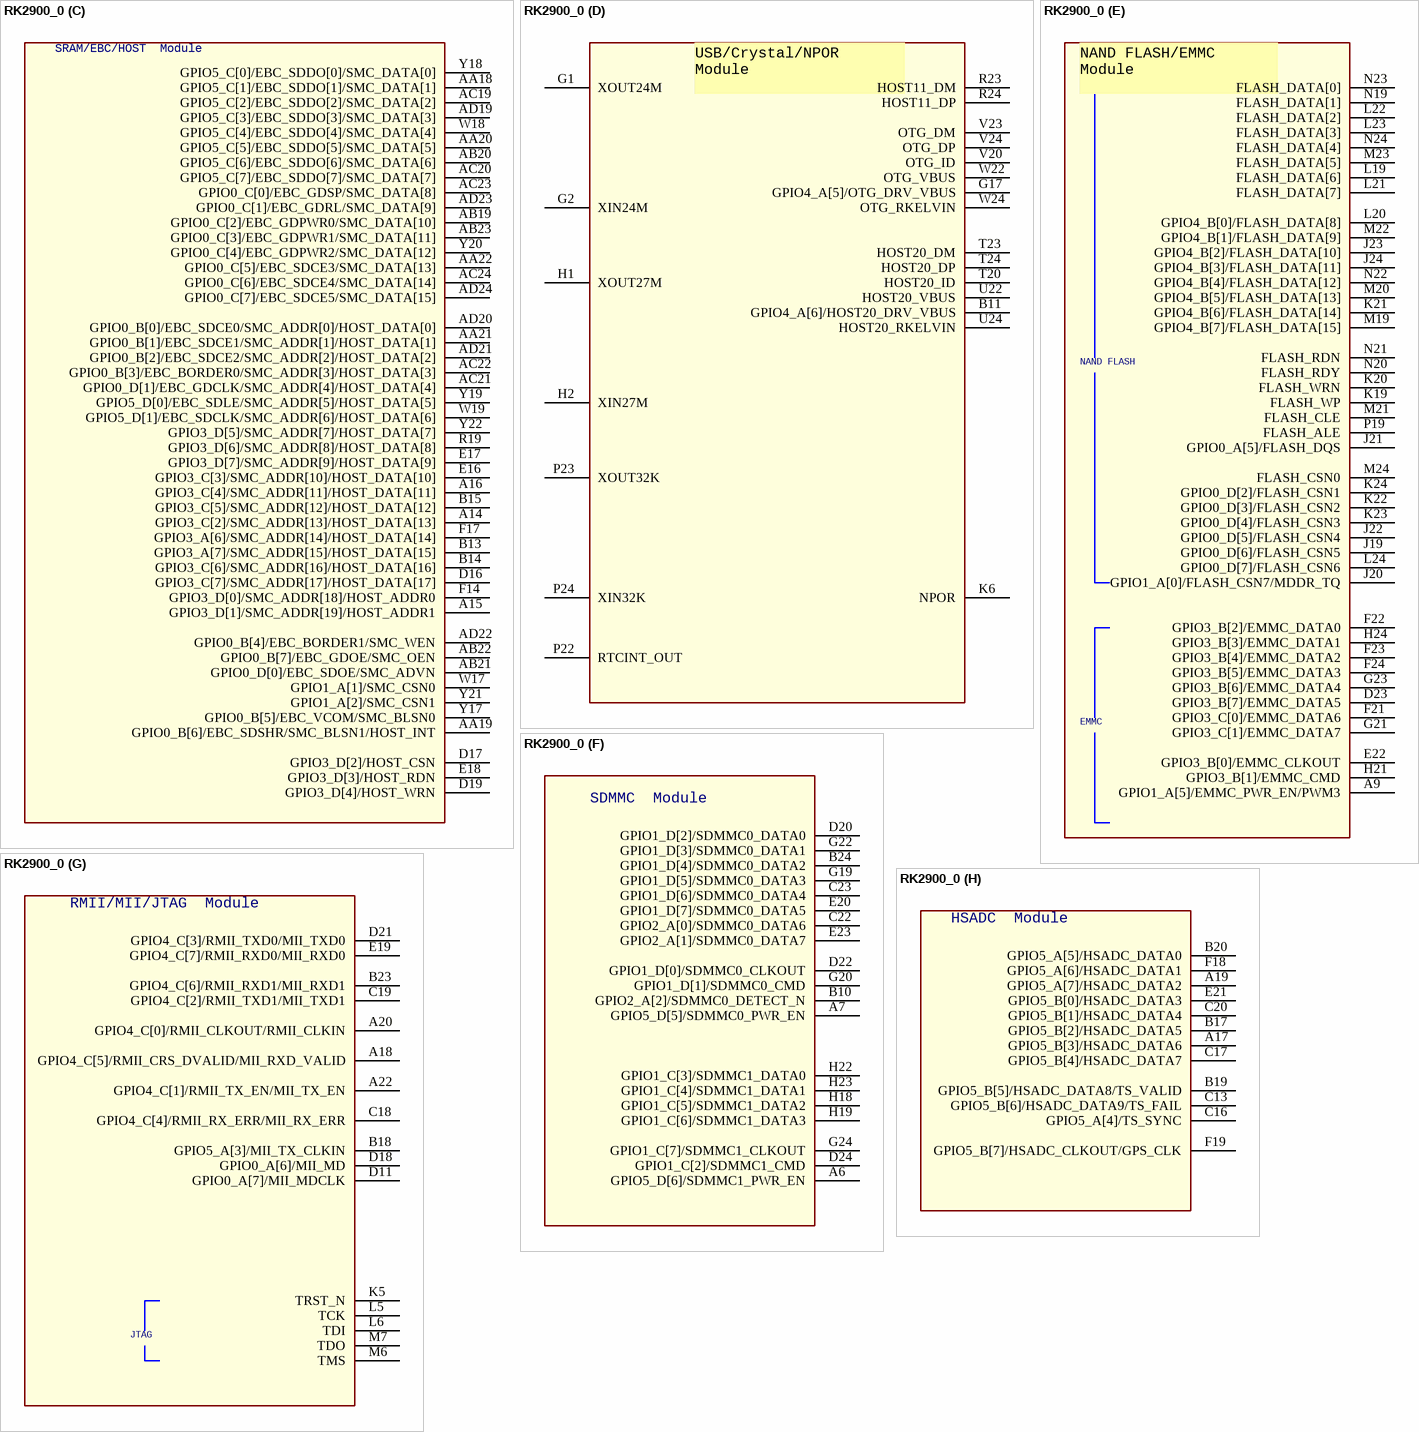
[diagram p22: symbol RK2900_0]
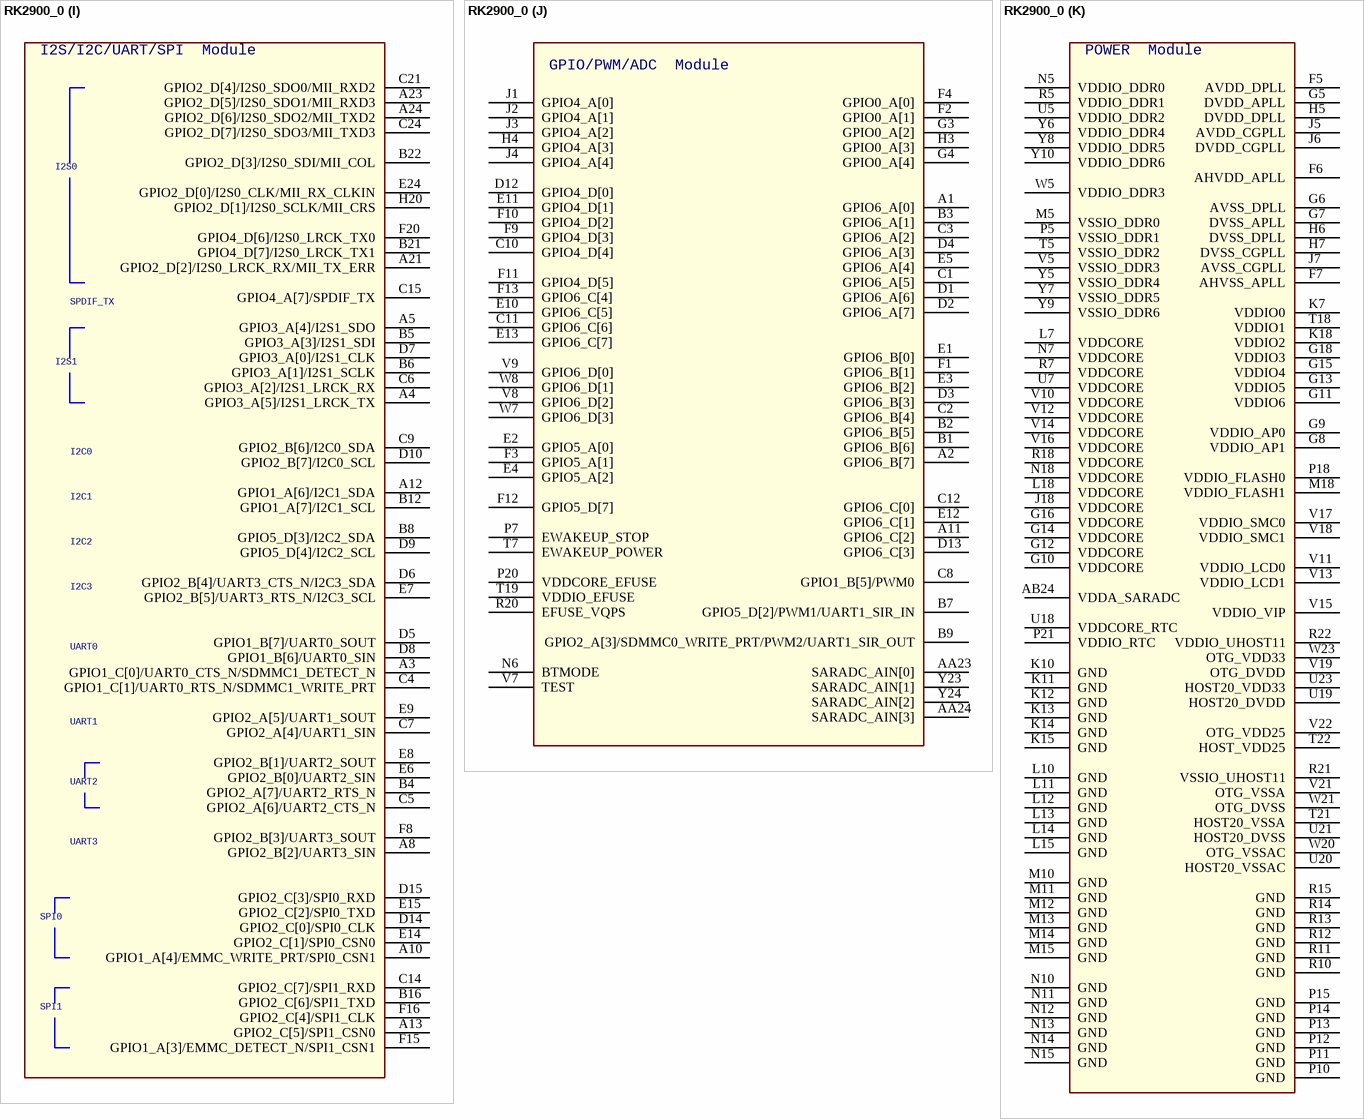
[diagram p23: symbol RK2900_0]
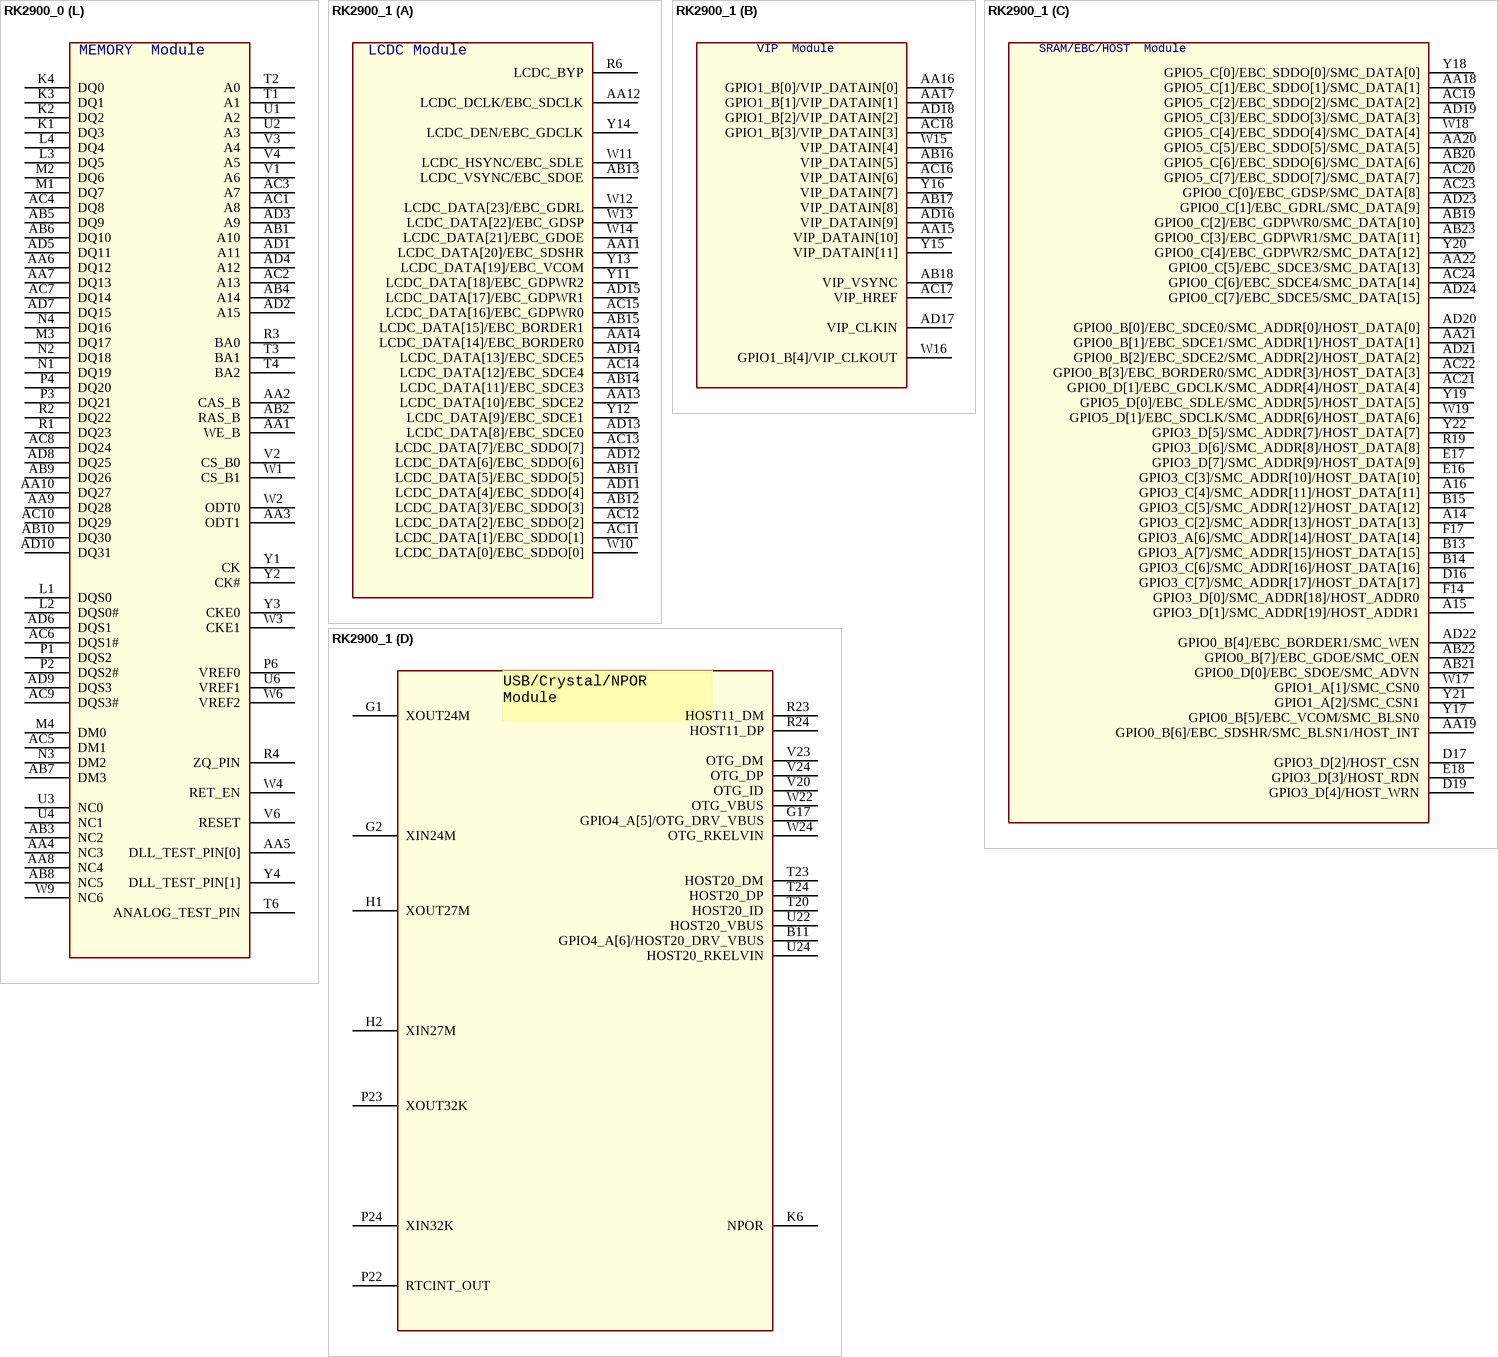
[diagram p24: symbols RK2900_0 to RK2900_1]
## RK2900_0
designator U?
footprint BGA512
part A pins: AA11 LCDC_DATA[20]/EBC_SDSHR, AA12 LCDC_DCLK/EBC_SDCLK, AA13 LCDC_DATA[10]/EBC_SDCE2, AA14 LCDC_DATA[14]/EBC_BORDER0, AB11 LCDC_DATA[5]/EBC_SDDO[5], AB12 LCDC_DATA[3]/EBC_SDDO[3], AB13 LCDC_VSYNC/EBC_SDOE, AB14 LCDC_DATA[11]/EBC_SDCE3, AB15 LCDC_DATA[15]/EBC_BORDER1, AC11 LCDC_DATA[1]/EBC_SDDO[1], AC12 LCDC_DATA[2]/EBC_SDDO[2], AC13 LCDC_DATA[7]/EBC_SDDO[7], AC14 LCDC_DATA[12]/EBC_SDCE4, AC15 LCDC_DATA[16]/EBC_GDPWR0, AD11 LCDC_DATA[4]/EBC_SDDO[4], AD12 LCDC_DATA[6]/EBC_SDDO[6], AD13 LCDC_DATA[8]/EBC_SDCE0, AD14 LCDC_DATA[13]/EBC_SDCE5, AD15 LCDC_DATA[17]/EBC_GDPWR1, R6 LCDC_BYP, W10 LCDC_DATA[0]/EBC_SDDO[0], W11 LCDC_HSYNC/EBC_SDLE, W12 LCDC_DATA[23]/EBC_GDRL, W13 LCDC_DATA[22]/EBC_GDSP, W14 LCDC_DATA[21]/EBC_GDOE, Y11 LCDC_DATA[18]/EBC_GDPWR2, Y12 LCDC_DATA[9]/EBC_SDCE1, Y13 LCDC_DATA[19]/EBC_VCOM, Y14 LCDC_DEN/EBC_GDCLK
part B pins: AA15 VIP_DATAIN[10], AA16 GPIO1_B[0]/VIP_DATAIN[0], AA17 GPIO1_B[1]/VIP_DATAIN[1], AB16 VIP_DATAIN[5], AB17 VIP_DATAIN[8], AB18 VIP_VSYNC, AC16 VIP_DATAIN[6], AC17 VIP_HREF, AC18 GPIO1_B[3]/VIP_DATAIN[3], AD16 VIP_DATAIN[9], AD17 VIP_CLKIN, AD18 GPIO1_B[2]/VIP_DATAIN[2], W15 VIP_DATAIN[4], W16 GPIO1_B[4]/VIP_CLKOUT, Y15 VIP_DATAIN[11], Y16 VIP_DATAIN[7]
part C pins: A14 GPIO3_C[2]/SMC_ADDR[13]/HOST_DATA[13], A15 GPIO3_D[1]/SMC_ADDR[19]/HOST_ADDR1, A16 GPIO3_C[4]/SMC_ADDR[11]/HOST_DATA[11], AA18 GPIO5_C[1]/EBC_SDDO[1]/SMC_DATA[1], AA19 GPIO0_B[6]/EBC_SDSHR/SMC_BLSN1/HOST_INT, AA20 GPIO5_C[5]/EBC_SDDO[5]/SMC_DATA[5], AA21 GPIO0_B[1]/EBC_SDCE1/SMC_ADDR[1]/HOST_DATA[1], AA22 GPIO0_C[5]/EBC_SDCE3/SMC_DATA[13], AB19 GPIO0_C[2]/EBC_GDPWR0/SMC_DATA[10], AB20 GPIO5_C[6]/EBC_SDDO[6]/SMC_DATA[6], AB21 GPIO0_D[0]/EBC_SDOE/SMC_ADVN, AB22 GPIO0_B[7]/EBC_GDOE/SMC_OEN, AB23 GPIO0_C[3]/EBC_GDPWR1/SMC_DATA[11], AC19 GPIO5_C[2]/EBC_SDDO[2]/SMC_DATA[2], AC20 GPIO5_C[7]/EBC_SDDO[7]/SMC_DATA[7], AC21 GPIO0_D[1]/EBC_GDCLK/SMC_ADDR[4]/HOST_DATA[4], AC22 GPIO0_B[3]/EBC_BORDER0/SMC_ADDR[3]/HOST_DATA[3], AC23 GPIO0_C[0]/EBC_GDSP/SMC_DATA[8], AC24 GPIO0_C[6]/EBC_SDCE4/SMC_DATA[14], AD19 GPIO5_C[3]/EBC_SDDO[3]/SMC_DATA[3], AD20 GPIO0_B[0]/EBC_SDCE0/SMC_ADDR[0]/HOST_DATA[0], AD21 GPIO0_B[2]/EBC_SDCE2/SMC_ADDR[2]/HOST_DATA[2], AD22 GPIO0_B[4]/EBC_BORDER1/SMC_WEN, AD23 GPIO0_C[1]/EBC_GDRL/SMC_DATA[9], AD24 GPIO0_C[7]/EBC_SDCE5/SMC_DATA[15], B13 GPIO3_A[7]/SMC_ADDR[15]/HOST_DATA[15], B14 GPIO3_C[6]/SMC_ADDR[16]/HOST_DATA[16], B15 GPIO3_C[5]/SMC_ADDR[12]/HOST_DATA[12], D16 GPIO3_C[7]/SMC_ADDR[17]/HOST_DATA[17], D17 GPIO3_D[2]/HOST_CSN, D19 GPIO3_D[4]/HOST_WRN, E16 GPIO3_C[3]/SMC_ADDR[10]/HOST_DATA[10], E17 GPIO3_D[7]/SMC_ADDR[9]/HOST_DATA[9], E18 GPIO3_D[3]/HOST_RDN, F14 GPIO3_D[0]/SMC_ADDR[18]/HOST_ADDR0, F17 GPIO3_A[6]/SMC_ADDR[14]/HOST_DATA[14], R19 GPIO3_D[6]/SMC_ADDR[8]/HOST_DATA[8], W17 GPIO1_A[1]/SMC_CSN0, W18 GPIO5_C[4]/EBC_SDDO[4]/SMC_DATA[4], W19 GPIO5_D[1]/EBC_SDCLK/SMC_ADDR[6]/HOST_DATA[6], Y17 GPIO0_B[5]/EBC_VCOM/SMC_BLSN0, Y18 GPIO5_C[0]/EBC_SDDO[0]/SMC_DATA[0], Y19 GPIO5_D[0]/EBC_SDLE/SMC_ADDR[5]/HOST_DATA[5], Y20 GPIO0_C[4]/EBC_GDPWR2/SMC_DATA[12], Y21 GPIO1_A[2]/SMC_CSN1, Y22 GPIO3_D[5]/SMC_ADDR[7]/HOST_DATA[7]
part D pins: B11 GPIO4_A[6]/HOST20_DRV_VBUS, G1 XOUT24M, G2 XIN24M, G17 GPIO4_A[5]/OTG_DRV_VBUS, H1 XOUT27M, H2 XIN27M, K6 NPOR, P22 RTCINT_OUT, P23 XOUT32K, P24 XIN32K, R23 HOST11_DM, R24 HOST11_DP, T20 HOST20_ID, T23 HOST20_DM, T24 HOST20_DP, U22 HOST20_VBUS, U24 HOST20_RKELVIN, V20 OTG_ID, V23 OTG_DM, V24 OTG_DP, W22 OTG_VBUS, W24 OTG_RKELVIN
part E pins: A9 GPIO1_A[5]/EMMC_PWR_EN/PWM3, D23 GPIO3_B[7]/EMMC_DATA5, E22 GPIO3_B[0]/EMMC_CLKOUT, F21 GPIO3_C[0]/EMMC_DATA6, F22 GPIO3_B[2]/EMMC_DATA0, F23 GPIO3_B[4]/EMMC_DATA2, F24 GPIO3_B[5]/EMMC_DATA3, G21 GPIO3_C[1]/EMMC_DATA7, G23 GPIO3_B[6]/EMMC_DATA4, H21 GPIO3_B[1]/EMMC_CMD, H24 GPIO3_B[3]/EMMC_DATA1, J19 GPIO0_D[6]/FLASH_CSN5, J20 GPIO1_A[0]/FLASH_CSN7/MDDR_TQ, J21 GPIO0_A[5]/FLASH_DQS, J22 GPIO0_D[5]/FLASH_CSN4, J23 GPIO4_B[2]/FLASH_DATA[10], J24 GPIO4_B[3]/FLASH_DATA[11], K19 FLASH_WP, K20 FLASH_WRN, K21 GPIO4_B[6]/FLASH_DATA[14], K22 GPIO0_D[3]/FLASH_CSN2, K23 GPIO0_D[4]/FLASH_CSN3, K24 GPIO0_D[2]/FLASH_CSN1, L19 FLASH_DATA[6], L20 GPIO4_B[0]/FLASH_DATA[8], L21 FLASH_DATA[7], L22 FLASH_DATA[2], L23 FLASH_DATA[3], L24 GPIO0_D[7]/FLASH_CSN6, M19 GPIO4_B[7]/FLASH_DATA[15], M20 GPIO4_B[5]/FLASH_DATA[13], M21 FLASH_CLE, M22 GPIO4_B[1]/FLASH_DATA[9], M23 FLASH_DATA[5], M24 FLASH_CSN0, N19 FLASH_DATA[1], N20 FLASH_RDY, N21 FLASH_RDN, N22 GPIO4_B[4]/FLASH_DATA[12], N23 FLASH_DATA[0], N24 FLASH_DATA[4], P19 FLASH_ALE
part F pins: A6 GPIO5_D[6]/SDMMC1_PWR_EN, A7 GPIO5_D[5]/SDMMC0_PWR_EN, B10 GPIO2_A[2]/SDMMC0_DETECT_N, B24 GPIO1_D[4]/SDMMC0_DATA2, C22 GPIO2_A[0]/SDMMC0_DATA6, C23 GPIO1_D[6]/SDMMC0_DATA4, D20 GPIO1_D[2]/SDMMC0_DATA0, D22 GPIO1_D[0]/SDMMC0_CLKOUT, D24 GPIO1_C[2]/SDMMC1_CMD, E20 GPIO1_D[7]/SDMMC0_DATA5, E23 GPIO2_A[1]/SDMMC0_DATA7, G19 GPIO1_D[5]/SDMMC0_DATA3, G20 GPIO1_D[1]/SDMMC0_CMD, G22 GPIO1_D[3]/SDMMC0_DATA1, G24 GPIO1_C[7]/SDMMC1_CLKOUT, H18 GPIO1_C[5]/SDMMC1_DATA2, H19 GPIO1_C[6]/SDMMC1_DATA3, H22 GPIO1_C[3]/SDMMC1_DATA0, H23 GPIO1_C[4]/SDMMC1_DATA1
part G pins: A18 GPIO4_C[5]/RMII_CRS_DVALID/MII_RXD_VALID, A20 GPIO4_C[0]/RMII_CLKOUT/RMII_CLKIN, A22 GPIO4_C[1]/RMII_TX_EN/MII_TX_EN, B18 GPIO5_A[3]/MII_TX_CLKIN, B23 GPIO4_C[6]/RMII_RXD1/MII_RXD1, C18 GPIO4_C[4]/RMII_RX_ERR/MII_RX_ERR, C19 GPIO4_C[2]/RMII_TXD1/MII_TXD1, D11 GPIO0_A[7]/MII_MDCLK, D18 GPIO0_A[6]/MII_MD, D21 GPIO4_C[3]/RMII_TXD0/MII_TXD0, E19 GPIO4_C[7]/RMII_RXD0/MII_RXD0, K5 TRST_N, L5 TCK, L6 TDI, M6 TMS, M7 TDO
part H pins: A17 GPIO5_B[3]/HSADC_DATA6, A19 GPIO5_A[7]/HSADC_DATA2, B17 GPIO5_B[2]/HSADC_DATA5, B19 GPIO5_B[5]/HSADC_DATA8/TS_VALID, B20 GPIO5_A[5]/HSADC_DATA0, C13 GPIO5_B[6]/HSADC_DATA9/TS_FAIL, C16 GPIO5_A[4]/TS_SYNC, C17 GPIO5_B[4]/HSADC_DATA7, C20 GPIO5_B[1]/HSADC_DATA4, E21 GPIO5_B[0]/HSADC_DATA3, F18 GPIO5_A[6]/HSADC_DATA1, F19 GPIO5_B[7]/HSADC_CLKOUT/GPS_CLK
part I pins: A3 GPIO1_C[0]/UART0_CTS_N/SDMMC1_DETECT_N, A4 GPIO3_A[5]/I2S1_LRCK_TX, A5 GPIO3_A[4]/I2S1_SDO, A8 GPIO2_B[2]/UART3_SIN, A10 GPIO1_A[4]/EMMC_WRITE_PRT/SPI0_CSN1, A12 GPIO1_A[6]/I2C1_SDA, A13 GPIO2_C[5]/SPI1_CSN0, A21 GPIO2_D[2]/I2S0_LRCK_RX/MII_TX_ERR, A23 GPIO2_D[5]/I2S0_SDO1/MII_RXD3, A24 GPIO2_D[6]/I2S0_SDO2/MII_TXD2, B4 GPIO2_A[7]/UART2_RTS_N, B5 GPIO3_A[3]/I2S1_SDI, B6 GPIO3_A[1]/I2S1_SCLK, B8 GPIO5_D[3]/I2C2_SDA, B12 GPIO1_A[7]/I2C1_SCL, B16 GPIO2_C[6]/SPI1_TXD, B21 GPIO4_D[7]/I2S0_LRCK_TX1, B22 GPIO2_D[3]/I2S0_SDI/MII_COL, C4 GPIO1_C[1]/UART0_RTS_N/SDMMC1_WRITE_PRT, C5 GPIO2_A[6]/UART2_CTS_N, C6 GPIO3_A[2]/I2S1_LRCK_RX, C7 GPIO2_A[4]/UART1_SIN, C9 GPIO2_B[6]/I2C0_SDA, C14 GPIO2_C[7]/SPI1_RXD, C15 GPIO4_A[7]/SPDIF_TX, C21 GPIO2_D[4]/I2S0_SDO0/MII_RXD2, C24 GPIO2_D[7]/I2S0_SDO3/MII_TXD3, D5 GPIO1_B[7]/UART0_SOUT, D6 GPIO2_B[4]/UART3_CTS_N/I2C3_SDA, D7 GPIO3_A[0]/I2S1_CLK, D8 GPIO1_B[6]/UART0_SIN, D9 GPIO5_D[4]/I2C2_SCL, D10 GPIO2_B[7]/I2C0_SCL, D14 GPIO2_C[0]/SPI0_CLK, D15 GPIO2_C[3]/SPI0_RXD, E6 GPIO2_B[0]/UART2_SIN, E7 GPIO2_B[5]/UART3_RTS_N/I2C3_SCL, E8 GPIO2_B[1]/UART2_SOUT, E9 GPIO2_A[5]/UART1_SOUT, E14 GPIO2_C[1]/SPI0_CSN0, E15 GPIO2_C[2]/SPI0_TXD, E24 GPIO2_D[0]/I2S0_CLK/MII_RX_CLKIN, F8 GPIO2_B[3]/UART3_SOUT, F15 GPIO1_A[3]/EMMC_DETECT_N/SPI1_CSN1, F16 GPIO2_C[4]/SPI1_CLK, F20 GPIO4_D[6]/I2S0_LRCK_TX0, H20 GPIO2_D[1]/I2S0_SCLK/MII_CRS
part J pins: A1 GPIO6_A[0], A2 GPIO6_B[7], A11 GPIO6_C[2], AA23 SARADC_AIN[0], AA24 SARADC_AIN[3], B1 GPIO6_B[6], B2 GPIO6_B[5], B3 GPIO6_A[1], B7 GPIO5_D[2]/PWM1/UART1_SIR_IN, B9 GPIO2_A[3]/SDMMC0_WRITE_PRT/PWM2/UART1_SIR_OUT, C1 GPIO6_A[5], C2 GPIO6_B[4], C3 GPIO6_A[2], C8 GPIO1_B[5]/PWM0, C10 GPIO4_D[4], C11 GPIO6_C[6], C12 GPIO6_C[0], D1 GPIO6_A[6], D2 GPIO6_A[7], D3 GPIO6_B[3], D4 GPIO6_A[3], D12 GPIO4_D[0], D13 GPIO6_C[3], E1 GPIO6_B[0], E2 GPIO5_A[0], E3 GPIO6_B[2], E4 GPIO5_A[2], E5 GPIO6_A[4], E10 GPIO6_C[5], E11 GPIO4_D[1], E12 GPIO6_C[1], E13 GPIO6_C[7], F1 GPIO6_B[1], F2 GPIO0_A[1], F3 GPIO5_A[1], F4 GPIO0_A[0], F9 GPIO4_D[3], F10 GPIO4_D[2], F11 GPIO4_D[5], F12 GPIO5_D[7], F13 GPIO6_C[4], G3 GPIO0_A[2], G4 GPIO0_A[4], H3 GPIO0_A[3], H4 GPIO4_A[3], J1 GPIO4_A[0], J2 GPIO4_A[1], J3 GPIO4_A[2], J4 GPIO4_A[4], N6 BTMODE, P7 EWAKEUP_STOP, P20 VDDCORE_EFUSE, R20 EFUSE_VQPS, T7 EWAKEUP_POWER, T19 VDDIO_EFUSE, V7 TEST, V8 GPIO6_D[2], V9 GPIO6_D[0], W7 GPIO6_D[3], W8 GPIO6_D[1], Y23 SARADC_AIN[1], Y24 SARADC_AIN[2]
part K pins: AB24 VDDA_SARADC, F5 AVDD_DPLL, F6 AHVDD_APLL, F7 AHVSS_APLL, G5 DVDD_APLL, G6 AVSS_DPLL, G7 DVSS_APLL, G8 VDDIO_AP1, G9 VDDIO_AP0, G10 VDDCORE, G11 VDDIO6, G12 VDDCORE, G13 VDDIO5, G14 VDDCORE, G15 VDDIO4, G16 VDDCORE, G18 VDDIO3, H5 DVDD_DPLL, H6 DVSS_DPLL, H7 DVSS_CGPLL, J5 AVDD_CGPLL, J6 DVDD_CGPLL, J7 AVSS_CGPLL, J18 VDDCORE, K7 VDDIO0, K10 GND, K11 GND, K12 GND, K13 GND, K14 GND, K15 GND, K18 VDDIO2, L7 VDDCORE, L10 GND, L11 GND, L12 GND, L13 GND, L14 GND, L15 GND, L18 VDDCORE, M5 VSSIO_DDR0, M10 GND, M11 GND, M12 GND, M13 GND, M14 GND, M15 GND, M18 VDDIO_FLASH1, N5 VDDIO_DDR0, N7 VDDCORE, N10 GND, N11 GND, N12 GND, N13 GND, N14 GND, N15 GND, N18 VDDCORE, P5 VSSIO_DDR1, P10 GND, P11 GND, P12 GND, P13 GND, P14 GND, P15 GND, P18 VDDIO_FLASH0, P21 VDDIO_RTC, R5 VDDIO_DDR1, R7 VDDCORE, R10 GND, R11 GND, R12 GND, R13 GND, R14 GND, R15 GND, R18 VDDCORE, R21 VSSIO_UHOST11, R22 VDDIO_UHOST11, T5 VSSIO_DDR2, T18 VDDIO1, T21 HOST20_VSSA, T22 HOST_VDD25, U5 VDDIO_DDR2, U7 VDDCORE, U18 VDDCORE_RTC, U19 HOST20_DVDD, U20 HOST20_VSSAC, U21 HOST20_DVSS, U23 HOST20_VDD33, V5 VSSIO_DDR3, V10 VDDCORE, V11 VDDIO_LCD0, V12 VDDCORE, V13 VDDIO_LCD1, V14 VDDCORE, V15 VDDIO_VIP, V16 VDDCORE, V17 VDDIO_SMC0, V18 VDDIO_SMC1, V19 OTG_DVDD, V21 OTG_VSSA, V22 OTG_VDD25, W5 VDDIO_DDR3, W20 OTG_VSSAC, W21 OTG_DVSS, W23 OTG_VDD33, Y5 VSSIO_DDR4, Y6 VDDIO_DDR4, Y7 VSSIO_DDR5, Y8 VDDIO_DDR5, Y9 VSSIO_DDR6, Y10 VDDIO_DDR6
part L pins: AA1 WE_B, AA2 CAS_B, AA3 ODT1, AA4 NC3, AA5 DLL_TEST_PIN[0], AA6 DQ12, AA7 DQ13, AA8 NC4, AA9 DQ28, AA10 DQ27, AB1 A10, AB2 RAS_B, AB3 NC2, AB4 A14, AB5 DQ9, AB6 DQ10, AB7 DM3, AB8 NC5, AB9 DQ26, AB10 DQ30, AC1 A8, AC2 A13, AC3 A7, AC4 DQ8, AC5 DM1, AC6 DQS1#, AC7 DQ14, AC8 DQ24, AC9 DQS3#, AC10 DQ29, AD1 A11, AD2 A15, AD3 A9, AD4 A12, AD5 DQ11, AD6 DQS1, AD7 DQ15, AD8 DQ25, AD9 DQS3, AD10 DQ31, K1 DQ3, K2 DQ2, K3 DQ1, K4 DQ0, L1 DQS0, L2 DQS0#, L3 DQ5, L4 DQ4, M1 DQ7, M2 DQ6, M3 DQ17, M4 DM0, N1 DQ19, N2 DQ18, N3 DM2, N4 DQ16, P1 DQS2, P2 DQS2#, P3 DQ21, P4 DQ20, P6 VREF0, R1 DQ23, R2 DQ22, R3 BA0, R4 ZQ_PIN, T1 A1, T2 A0, T3 BA1, T4 BA2, T6 ANALOG_TEST_PIN, U1 A2, U2 A3, U3 NC0, U4 NC1, U6 VREF1, V1 A6, V2 CS_B0, V3 A4, V4 A5, V6 RESET, W1 CS_B1, W2 ODT0, W3 CKE1, W4 RET_EN, W6 VREF2, W9 NC6, Y1 CK, Y2 CK#, Y3 CKE0, Y4 DLL_TEST_PIN[1]




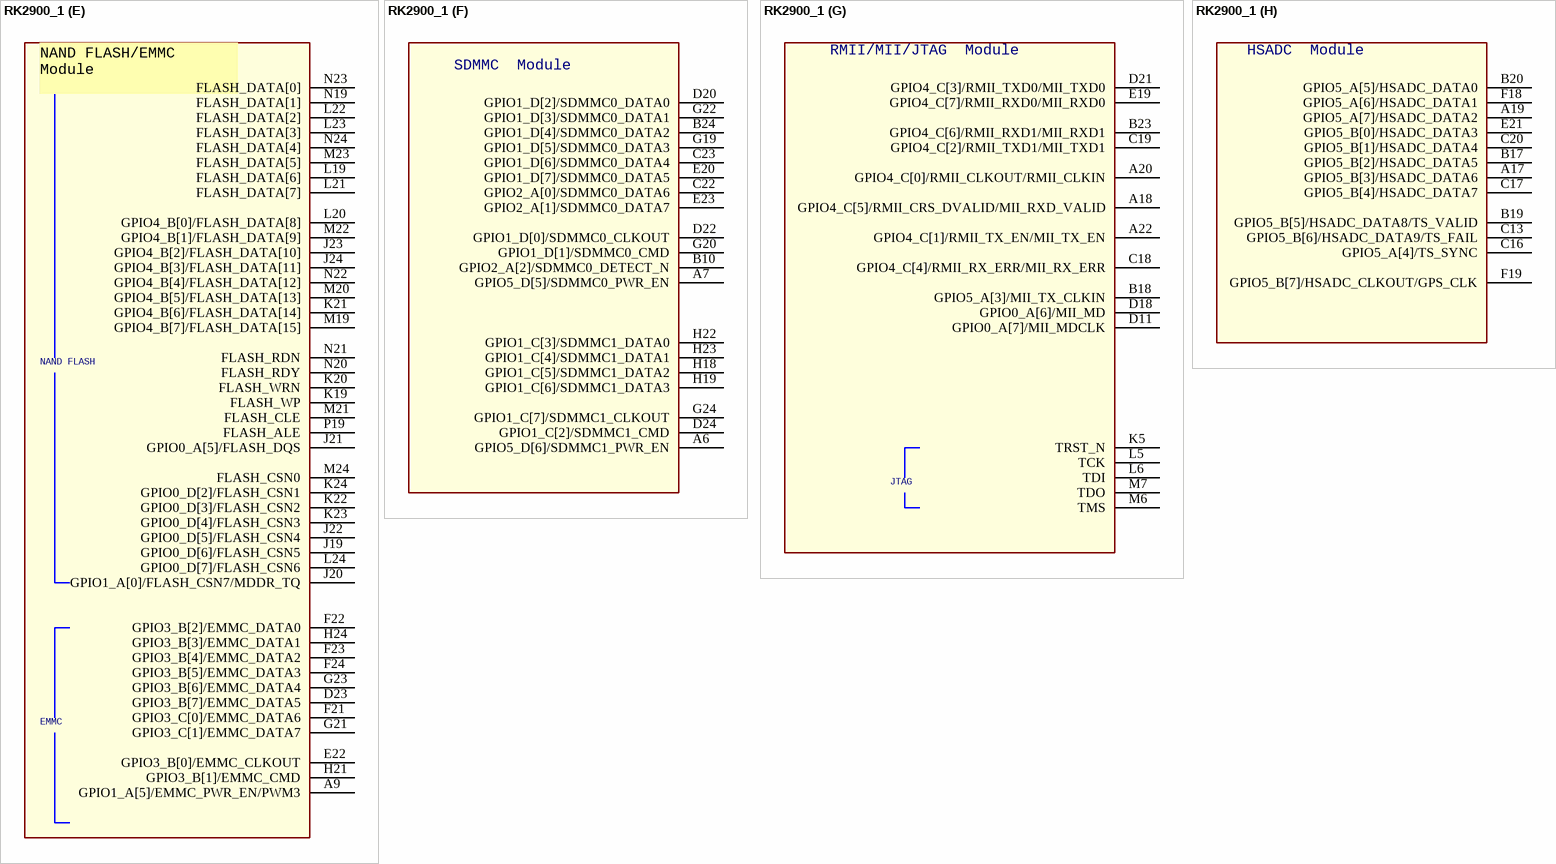
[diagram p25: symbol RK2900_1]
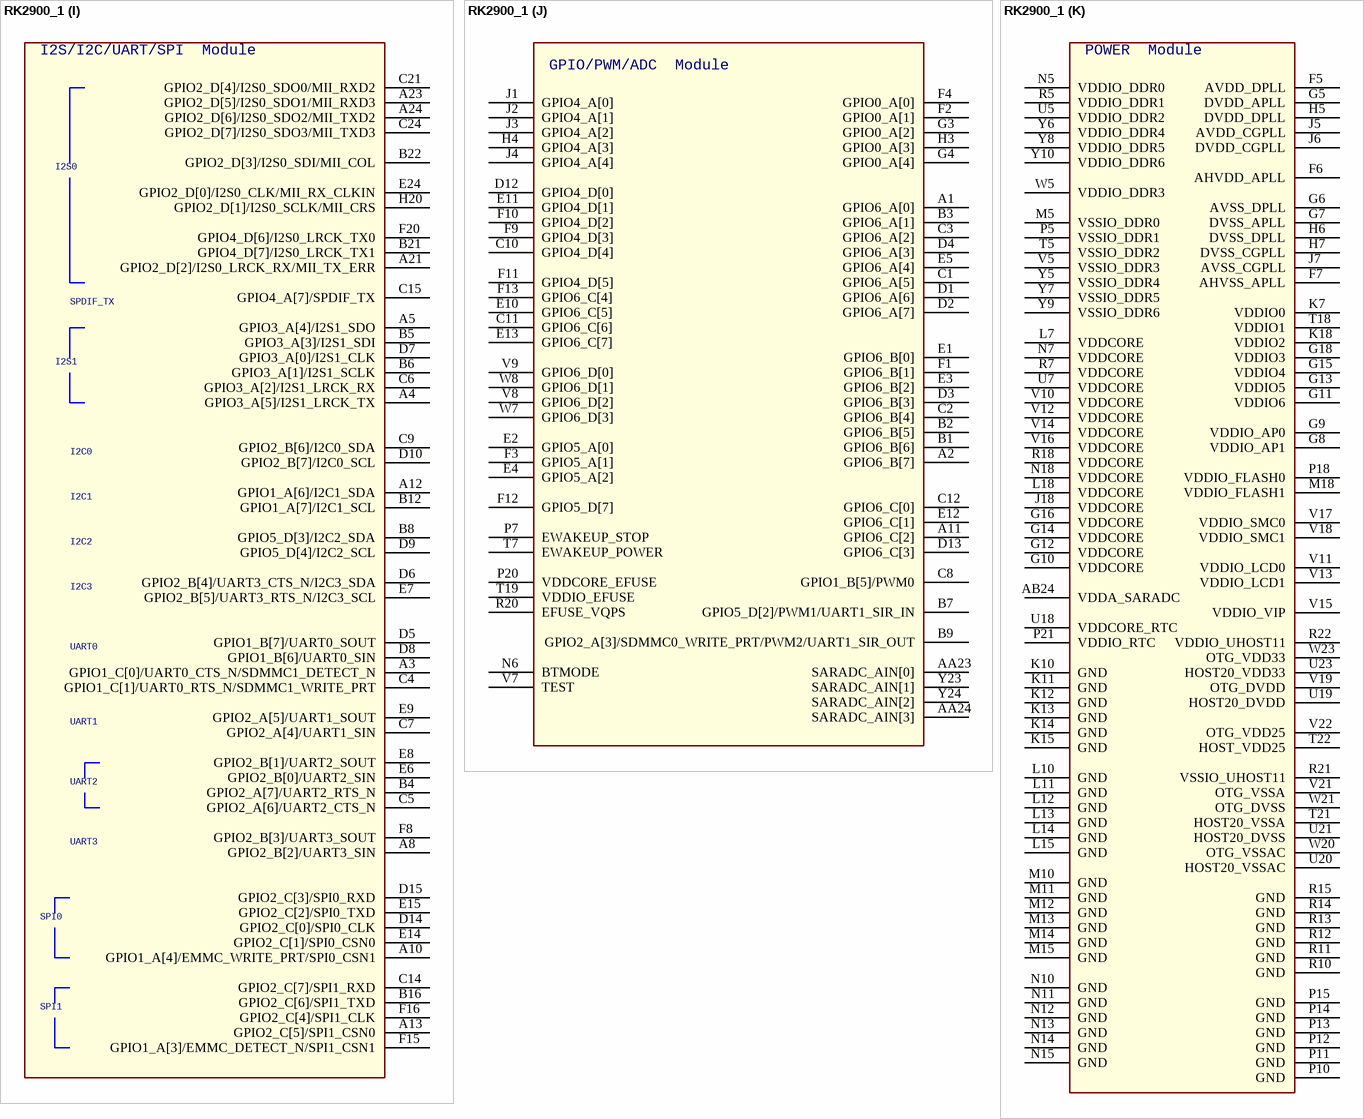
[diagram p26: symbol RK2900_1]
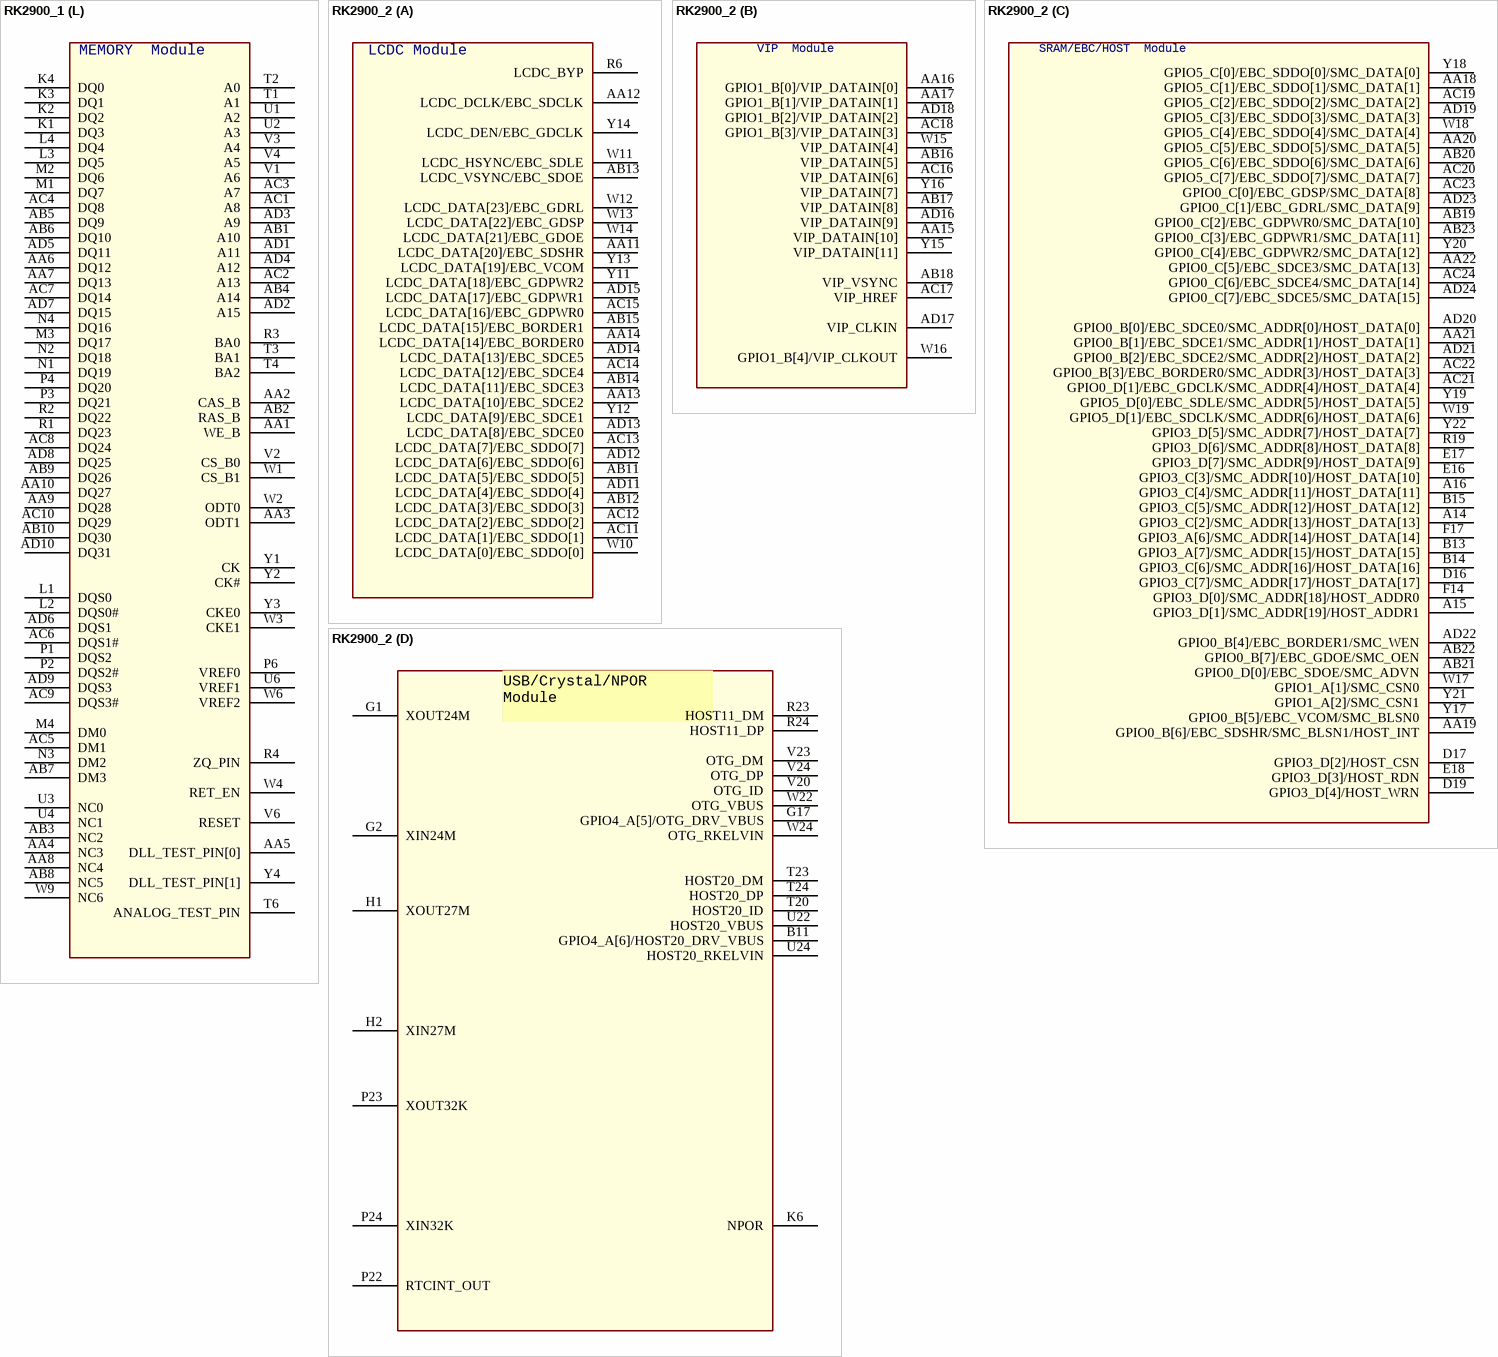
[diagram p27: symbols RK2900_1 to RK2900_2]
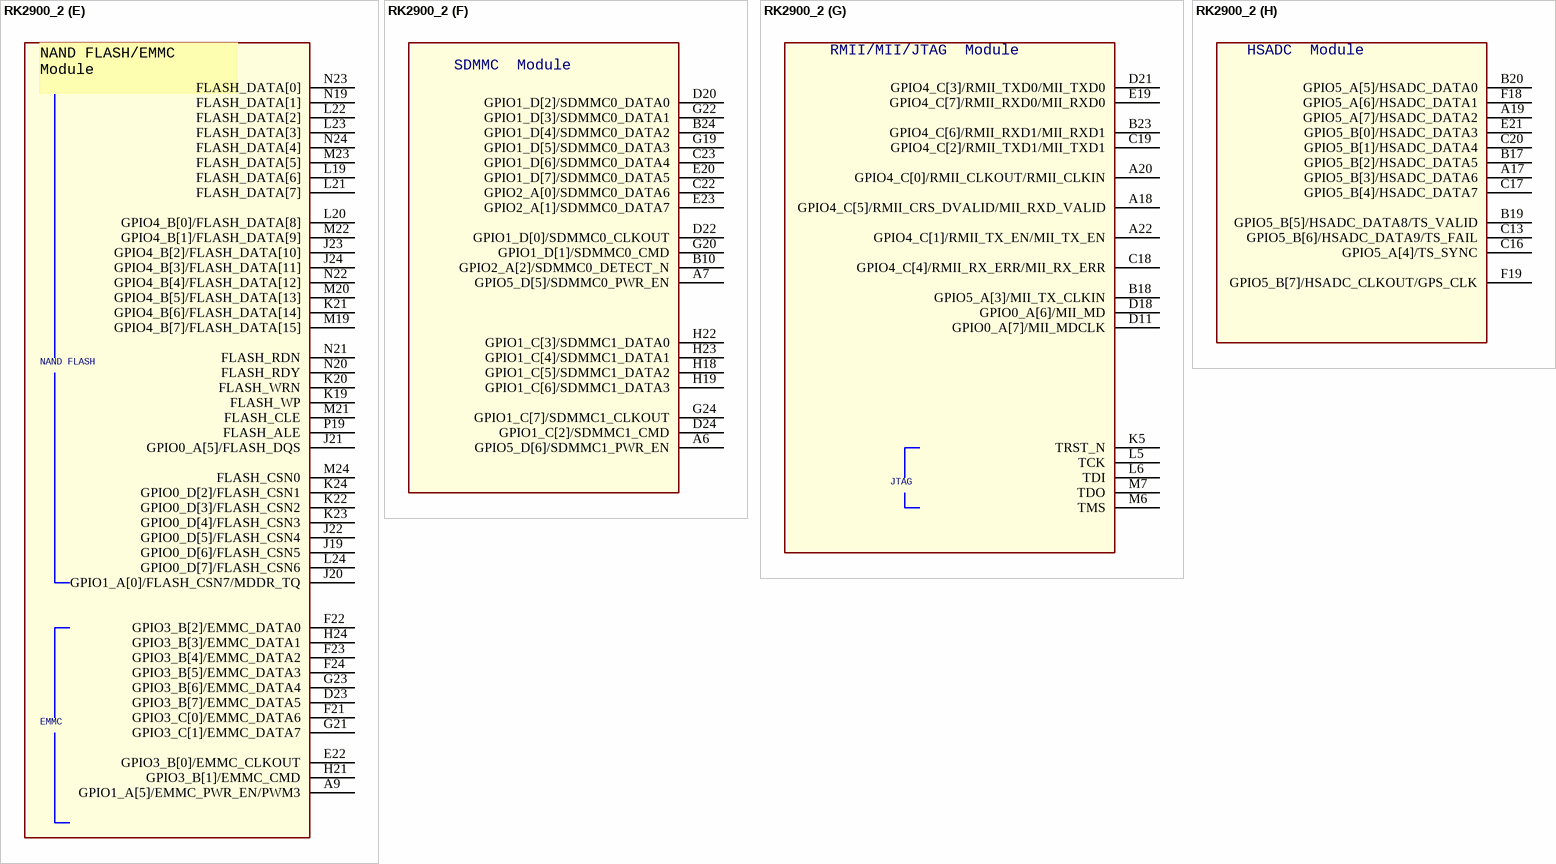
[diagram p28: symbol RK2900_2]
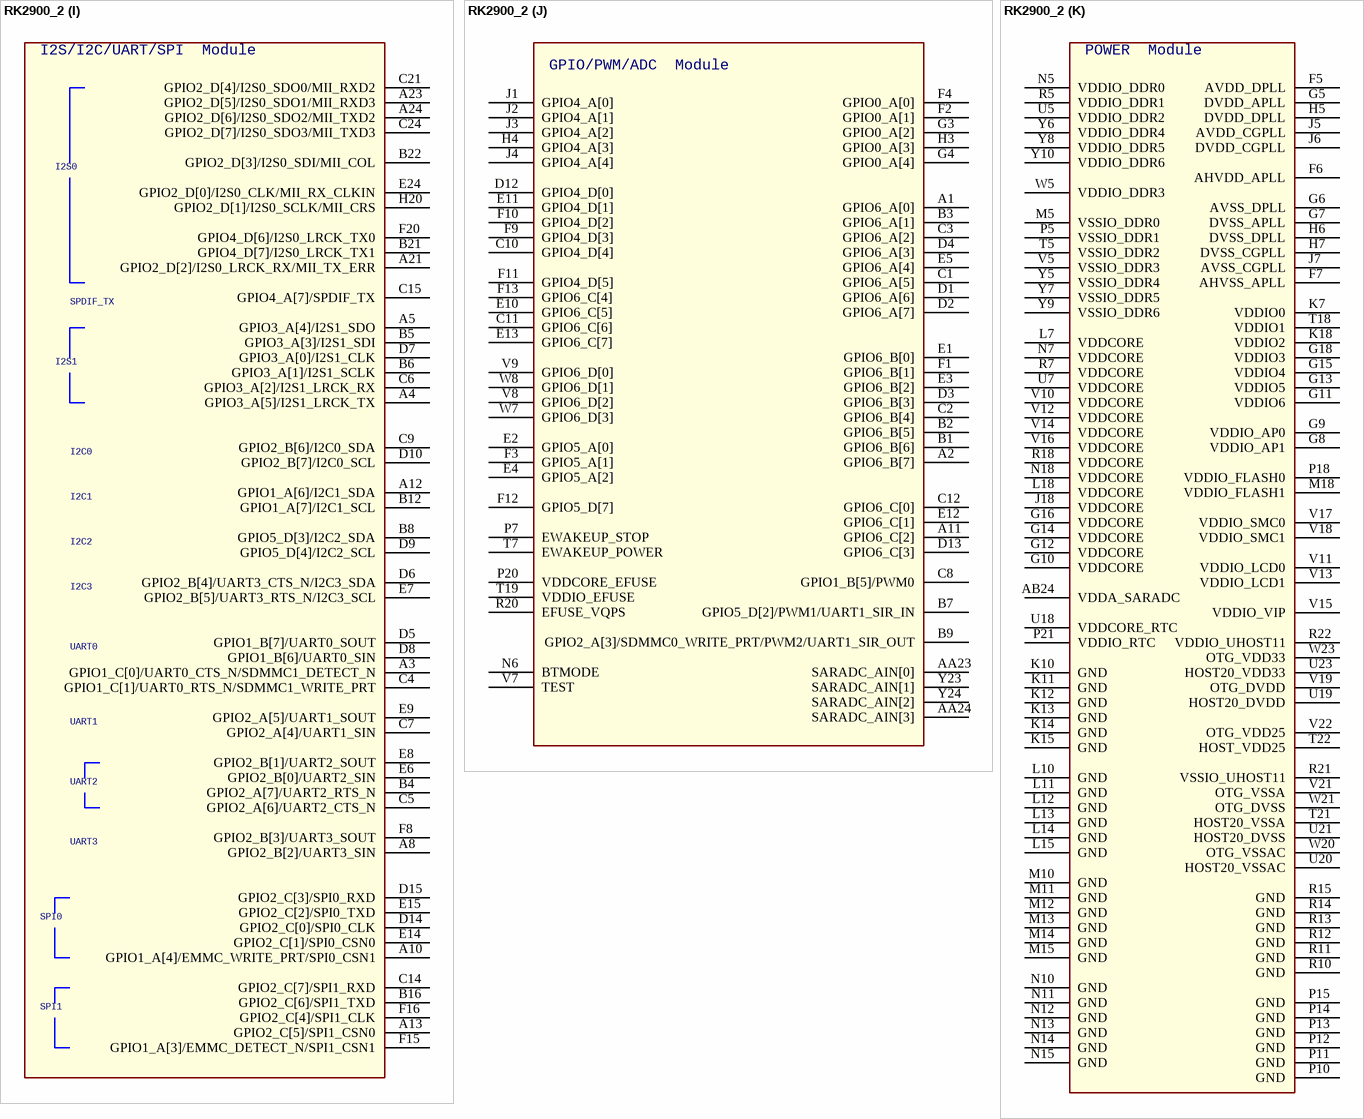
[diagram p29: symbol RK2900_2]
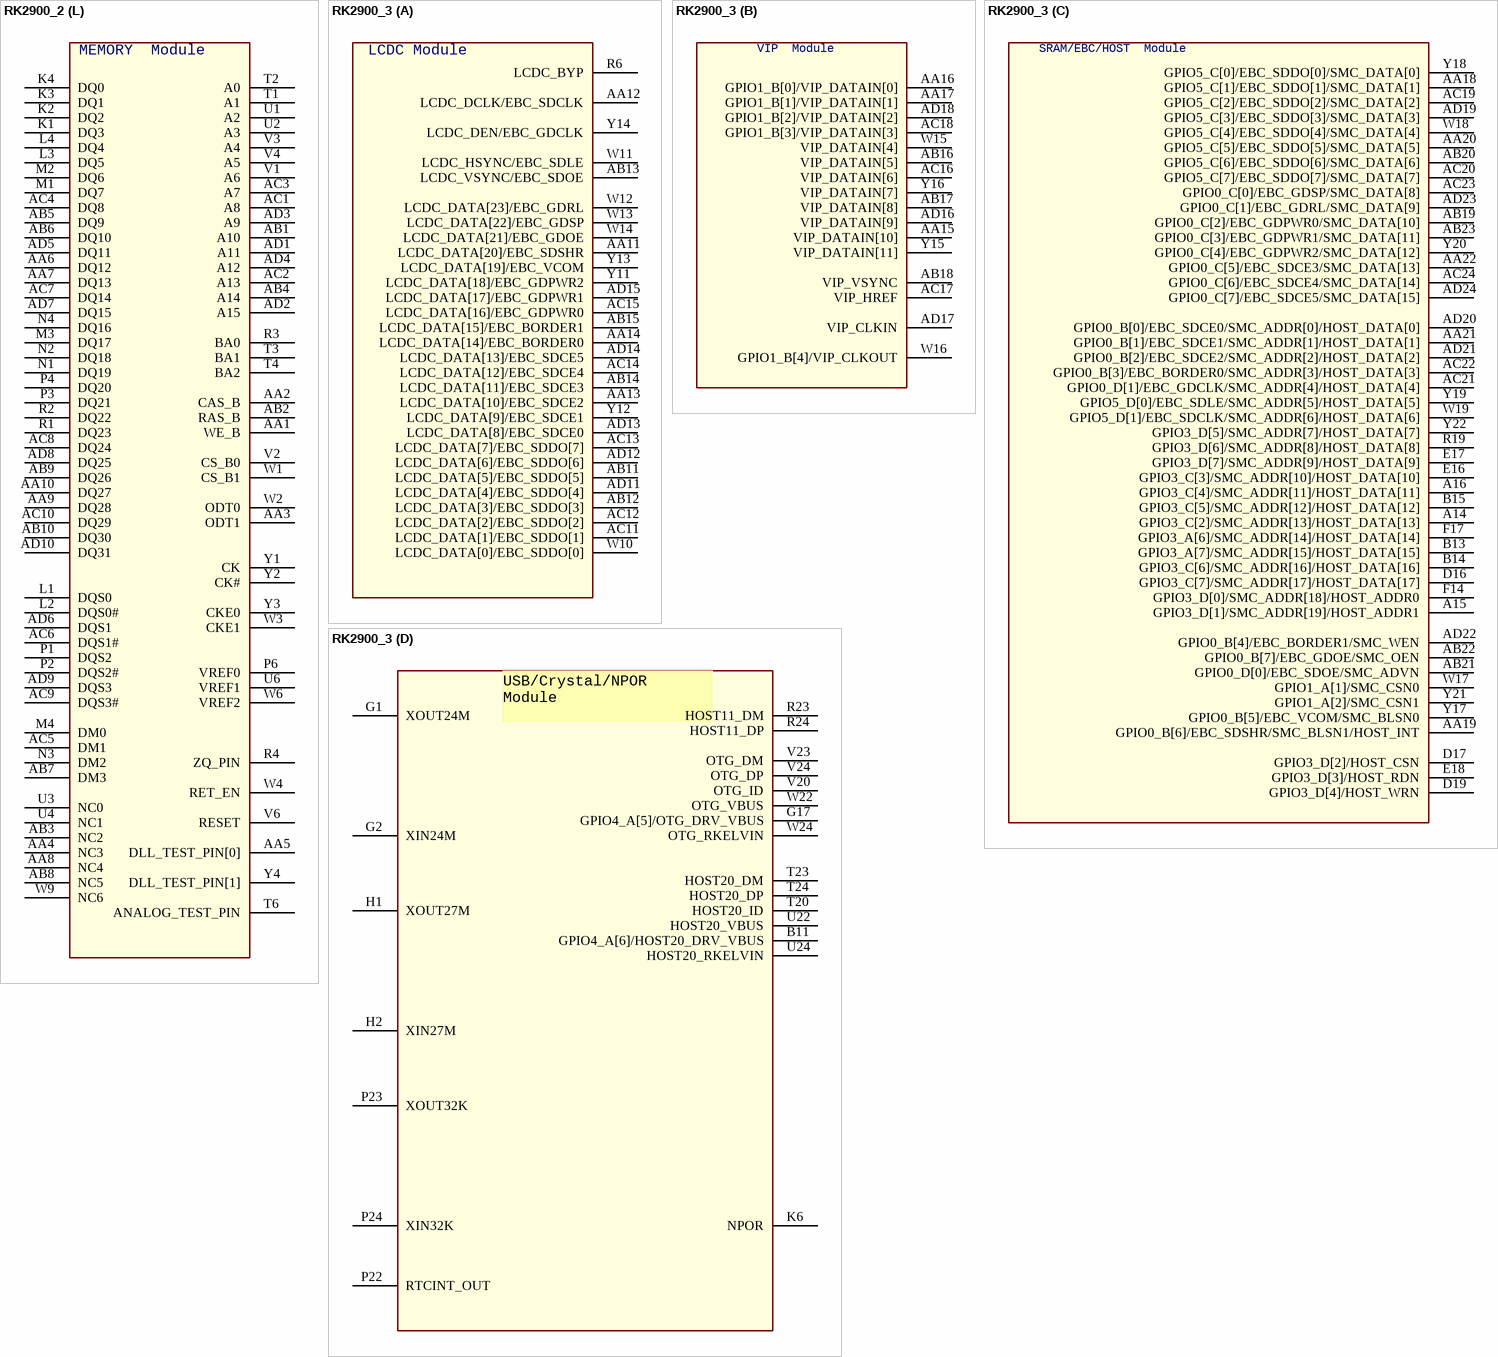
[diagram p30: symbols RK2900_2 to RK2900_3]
## RK2900_1
designator U?
footprint BGA512
part A pins: AA11 LCDC_DATA[20]/EBC_SDSHR, AA12 LCDC_DCLK/EBC_SDCLK, AA13 LCDC_DATA[10]/EBC_SDCE2, AA14 LCDC_DATA[14]/EBC_BORDER0, AB11 LCDC_DATA[5]/EBC_SDDO[5], AB12 LCDC_DATA[3]/EBC_SDDO[3], AB13 LCDC_VSYNC/EBC_SDOE, AB14 LCDC_DATA[11]/EBC_SDCE3, AB15 LCDC_DATA[15]/EBC_BORDER1, AC11 LCDC_DATA[1]/EBC_SDDO[1], AC12 LCDC_DATA[2]/EBC_SDDO[2], AC13 LCDC_DATA[7]/EBC_SDDO[7], AC14 LCDC_DATA[12]/EBC_SDCE4, AC15 LCDC_DATA[16]/EBC_GDPWR0, AD11 LCDC_DATA[4]/EBC_SDDO[4], AD12 LCDC_DATA[6]/EBC_SDDO[6], AD13 LCDC_DATA[8]/EBC_SDCE0, AD14 LCDC_DATA[13]/EBC_SDCE5, AD15 LCDC_DATA[17]/EBC_GDPWR1, R6 LCDC_BYP, W10 LCDC_DATA[0]/EBC_SDDO[0], W11 LCDC_HSYNC/EBC_SDLE, W12 LCDC_DATA[23]/EBC_GDRL, W13 LCDC_DATA[22]/EBC_GDSP, W14 LCDC_DATA[21]/EBC_GDOE, Y11 LCDC_DATA[18]/EBC_GDPWR2, Y12 LCDC_DATA[9]/EBC_SDCE1, Y13 LCDC_DATA[19]/EBC_VCOM, Y14 LCDC_DEN/EBC_GDCLK
part B pins: AA15 VIP_DATAIN[10], AA16 GPIO1_B[0]/VIP_DATAIN[0], AA17 GPIO1_B[1]/VIP_DATAIN[1], AB16 VIP_DATAIN[5], AB17 VIP_DATAIN[8], AB18 VIP_VSYNC, AC16 VIP_DATAIN[6], AC17 VIP_HREF, AC18 GPIO1_B[3]/VIP_DATAIN[3], AD16 VIP_DATAIN[9], AD17 VIP_CLKIN, AD18 GPIO1_B[2]/VIP_DATAIN[2], W15 VIP_DATAIN[4], W16 GPIO1_B[4]/VIP_CLKOUT, Y15 VIP_DATAIN[11], Y16 VIP_DATAIN[7]
part C pins: A14 GPIO3_C[2]/SMC_ADDR[13]/HOST_DATA[13], A15 GPIO3_D[1]/SMC_ADDR[19]/HOST_ADDR1, A16 GPIO3_C[4]/SMC_ADDR[11]/HOST_DATA[11], AA18 GPIO5_C[1]/EBC_SDDO[1]/SMC_DATA[1], AA19 GPIO0_B[6]/EBC_SDSHR/SMC_BLSN1/HOST_INT, AA20 GPIO5_C[5]/EBC_SDDO[5]/SMC_DATA[5], AA21 GPIO0_B[1]/EBC_SDCE1/SMC_ADDR[1]/HOST_DATA[1], AA22 GPIO0_C[5]/EBC_SDCE3/SMC_DATA[13], AB19 GPIO0_C[2]/EBC_GDPWR0/SMC_DATA[10], AB20 GPIO5_C[6]/EBC_SDDO[6]/SMC_DATA[6], AB21 GPIO0_D[0]/EBC_SDOE/SMC_ADVN, AB22 GPIO0_B[7]/EBC_GDOE/SMC_OEN, AB23 GPIO0_C[3]/EBC_GDPWR1/SMC_DATA[11], AC19 GPIO5_C[2]/EBC_SDDO[2]/SMC_DATA[2], AC20 GPIO5_C[7]/EBC_SDDO[7]/SMC_DATA[7], AC21 GPIO0_D[1]/EBC_GDCLK/SMC_ADDR[4]/HOST_DATA[4], AC22 GPIO0_B[3]/EBC_BORDER0/SMC_ADDR[3]/HOST_DATA[3], AC23 GPIO0_C[0]/EBC_GDSP/SMC_DATA[8], AC24 GPIO0_C[6]/EBC_SDCE4/SMC_DATA[14], AD19 GPIO5_C[3]/EBC_SDDO[3]/SMC_DATA[3], AD20 GPIO0_B[0]/EBC_SDCE0/SMC_ADDR[0]/HOST_DATA[0], AD21 GPIO0_B[2]/EBC_SDCE2/SMC_ADDR[2]/HOST_DATA[2], AD22 GPIO0_B[4]/EBC_BORDER1/SMC_WEN, AD23 GPIO0_C[1]/EBC_GDRL/SMC_DATA[9], AD24 GPIO0_C[7]/EBC_SDCE5/SMC_DATA[15], B13 GPIO3_A[7]/SMC_ADDR[15]/HOST_DATA[15], B14 GPIO3_C[6]/SMC_ADDR[16]/HOST_DATA[16], B15 GPIO3_C[5]/SMC_ADDR[12]/HOST_DATA[12], D16 GPIO3_C[7]/SMC_ADDR[17]/HOST_DATA[17], D17 GPIO3_D[2]/HOST_CSN, D19 GPIO3_D[4]/HOST_WRN, E16 GPIO3_C[3]/SMC_ADDR[10]/HOST_DATA[10], E17 GPIO3_D[7]/SMC_ADDR[9]/HOST_DATA[9], E18 GPIO3_D[3]/HOST_RDN, F14 GPIO3_D[0]/SMC_ADDR[18]/HOST_ADDR0, F17 GPIO3_A[6]/SMC_ADDR[14]/HOST_DATA[14], R19 GPIO3_D[6]/SMC_ADDR[8]/HOST_DATA[8], W17 GPIO1_A[1]/SMC_CSN0, W18 GPIO5_C[4]/EBC_SDDO[4]/SMC_DATA[4], W19 GPIO5_D[1]/EBC_SDCLK/SMC_ADDR[6]/HOST_DATA[6], Y17 GPIO0_B[5]/EBC_VCOM/SMC_BLSN0, Y18 GPIO5_C[0]/EBC_SDDO[0]/SMC_DATA[0], Y19 GPIO5_D[0]/EBC_SDLE/SMC_ADDR[5]/HOST_DATA[5], Y20 GPIO0_C[4]/EBC_GDPWR2/SMC_DATA[12], Y21 GPIO1_A[2]/SMC_CSN1, Y22 GPIO3_D[5]/SMC_ADDR[7]/HOST_DATA[7]
part D pins: B11 GPIO4_A[6]/HOST20_DRV_VBUS, G1 XOUT24M, G2 XIN24M, G17 GPIO4_A[5]/OTG_DRV_VBUS, H1 XOUT27M, H2 XIN27M, K6 NPOR, P22 RTCINT_OUT, P23 XOUT32K, P24 XIN32K, R23 HOST11_DM, R24 HOST11_DP, T20 HOST20_ID, T23 HOST20_DM, T24 HOST20_DP, U22 HOST20_VBUS, U24 HOST20_RKELVIN, V20 OTG_ID, V23 OTG_DM, V24 OTG_DP, W22 OTG_VBUS, W24 OTG_RKELVIN
part E pins: A9 GPIO1_A[5]/EMMC_PWR_EN/PWM3, D23 GPIO3_B[7]/EMMC_DATA5, E22 GPIO3_B[0]/EMMC_CLKOUT, F21 GPIO3_C[0]/EMMC_DATA6, F22 GPIO3_B[2]/EMMC_DATA0, F23 GPIO3_B[4]/EMMC_DATA2, F24 GPIO3_B[5]/EMMC_DATA3, G21 GPIO3_C[1]/EMMC_DATA7, G23 GPIO3_B[6]/EMMC_DATA4, H21 GPIO3_B[1]/EMMC_CMD, H24 GPIO3_B[3]/EMMC_DATA1, J19 GPIO0_D[6]/FLASH_CSN5, J20 GPIO1_A[0]/FLASH_CSN7/MDDR_TQ, J21 GPIO0_A[5]/FLASH_DQS, J22 GPIO0_D[5]/FLASH_CSN4, J23 GPIO4_B[2]/FLASH_DATA[10], J24 GPIO4_B[3]/FLASH_DATA[11], K19 FLASH_WP, K20 FLASH_WRN, K21 GPIO4_B[6]/FLASH_DATA[14], K22 GPIO0_D[3]/FLASH_CSN2, K23 GPIO0_D[4]/FLASH_CSN3, K24 GPIO0_D[2]/FLASH_CSN1, L19 FLASH_DATA[6], L20 GPIO4_B[0]/FLASH_DATA[8], L21 FLASH_DATA[7], L22 FLASH_DATA[2], L23 FLASH_DATA[3], L24 GPIO0_D[7]/FLASH_CSN6, M19 GPIO4_B[7]/FLASH_DATA[15], M20 GPIO4_B[5]/FLASH_DATA[13], M21 FLASH_CLE, M22 GPIO4_B[1]/FLASH_DATA[9], M23 FLASH_DATA[5], M24 FLASH_CSN0, N19 FLASH_DATA[1], N20 FLASH_RDY, N21 FLASH_RDN, N22 GPIO4_B[4]/FLASH_DATA[12], N23 FLASH_DATA[0], N24 FLASH_DATA[4], P19 FLASH_ALE
part F pins: A6 GPIO5_D[6]/SDMMC1_PWR_EN, A7 GPIO5_D[5]/SDMMC0_PWR_EN, B10 GPIO2_A[2]/SDMMC0_DETECT_N, B24 GPIO1_D[4]/SDMMC0_DATA2, C22 GPIO2_A[0]/SDMMC0_DATA6, C23 GPIO1_D[6]/SDMMC0_DATA4, D20 GPIO1_D[2]/SDMMC0_DATA0, D22 GPIO1_D[0]/SDMMC0_CLKOUT, D24 GPIO1_C[2]/SDMMC1_CMD, E20 GPIO1_D[7]/SDMMC0_DATA5, E23 GPIO2_A[1]/SDMMC0_DATA7, G19 GPIO1_D[5]/SDMMC0_DATA3, G20 GPIO1_D[1]/SDMMC0_CMD, G22 GPIO1_D[3]/SDMMC0_DATA1, G24 GPIO1_C[7]/SDMMC1_CLKOUT, H18 GPIO1_C[5]/SDMMC1_DATA2, H19 GPIO1_C[6]/SDMMC1_DATA3, H22 GPIO1_C[3]/SDMMC1_DATA0, H23 GPIO1_C[4]/SDMMC1_DATA1
part G pins: A18 GPIO4_C[5]/RMII_CRS_DVALID/MII_RXD_VALID, A20 GPIO4_C[0]/RMII_CLKOUT/RMII_CLKIN, A22 GPIO4_C[1]/RMII_TX_EN/MII_TX_EN, B18 GPIO5_A[3]/MII_TX_CLKIN, B23 GPIO4_C[6]/RMII_RXD1/MII_RXD1, C18 GPIO4_C[4]/RMII_RX_ERR/MII_RX_ERR, C19 GPIO4_C[2]/RMII_TXD1/MII_TXD1, D11 GPIO0_A[7]/MII_MDCLK, D18 GPIO0_A[6]/MII_MD, D21 GPIO4_C[3]/RMII_TXD0/MII_TXD0, E19 GPIO4_C[7]/RMII_RXD0/MII_RXD0, K5 TRST_N, L5 TCK, L6 TDI, M6 TMS, M7 TDO
part H pins: A17 GPIO5_B[3]/HSADC_DATA6, A19 GPIO5_A[7]/HSADC_DATA2, B17 GPIO5_B[2]/HSADC_DATA5, B19 GPIO5_B[5]/HSADC_DATA8/TS_VALID, B20 GPIO5_A[5]/HSADC_DATA0, C13 GPIO5_B[6]/HSADC_DATA9/TS_FAIL, C16 GPIO5_A[4]/TS_SYNC, C17 GPIO5_B[4]/HSADC_DATA7, C20 GPIO5_B[1]/HSADC_DATA4, E21 GPIO5_B[0]/HSADC_DATA3, F18 GPIO5_A[6]/HSADC_DATA1, F19 GPIO5_B[7]/HSADC_CLKOUT/GPS_CLK
part I pins: A3 GPIO1_C[0]/UART0_CTS_N/SDMMC1_DETECT_N, A4 GPIO3_A[5]/I2S1_LRCK_TX, A5 GPIO3_A[4]/I2S1_SDO, A8 GPIO2_B[2]/UART3_SIN, A10 GPIO1_A[4]/EMMC_WRITE_PRT/SPI0_CSN1, A12 GPIO1_A[6]/I2C1_SDA, A13 GPIO2_C[5]/SPI1_CSN0, A21 GPIO2_D[2]/I2S0_LRCK_RX/MII_TX_ERR, A23 GPIO2_D[5]/I2S0_SDO1/MII_RXD3, A24 GPIO2_D[6]/I2S0_SDO2/MII_TXD2, B4 GPIO2_A[7]/UART2_RTS_N, B5 GPIO3_A[3]/I2S1_SDI, B6 GPIO3_A[1]/I2S1_SCLK, B8 GPIO5_D[3]/I2C2_SDA, B12 GPIO1_A[7]/I2C1_SCL, B16 GPIO2_C[6]/SPI1_TXD, B21 GPIO4_D[7]/I2S0_LRCK_TX1, B22 GPIO2_D[3]/I2S0_SDI/MII_COL, C4 GPIO1_C[1]/UART0_RTS_N/SDMMC1_WRITE_PRT, C5 GPIO2_A[6]/UART2_CTS_N, C6 GPIO3_A[2]/I2S1_LRCK_RX, C7 GPIO2_A[4]/UART1_SIN, C9 GPIO2_B[6]/I2C0_SDA, C14 GPIO2_C[7]/SPI1_RXD, C15 GPIO4_A[7]/SPDIF_TX, C21 GPIO2_D[4]/I2S0_SDO0/MII_RXD2, C24 GPIO2_D[7]/I2S0_SDO3/MII_TXD3, D5 GPIO1_B[7]/UART0_SOUT, D6 GPIO2_B[4]/UART3_CTS_N/I2C3_SDA, D7 GPIO3_A[0]/I2S1_CLK, D8 GPIO1_B[6]/UART0_SIN, D9 GPIO5_D[4]/I2C2_SCL, D10 GPIO2_B[7]/I2C0_SCL, D14 GPIO2_C[0]/SPI0_CLK, D15 GPIO2_C[3]/SPI0_RXD, E6 GPIO2_B[0]/UART2_SIN, E7 GPIO2_B[5]/UART3_RTS_N/I2C3_SCL, E8 GPIO2_B[1]/UART2_SOUT, E9 GPIO2_A[5]/UART1_SOUT, E14 GPIO2_C[1]/SPI0_CSN0, E15 GPIO2_C[2]/SPI0_TXD, E24 GPIO2_D[0]/I2S0_CLK/MII_RX_CLKIN, F8 GPIO2_B[3]/UART3_SOUT, F15 GPIO1_A[3]/EMMC_DETECT_N/SPI1_CSN1, F16 GPIO2_C[4]/SPI1_CLK, F20 GPIO4_D[6]/I2S0_LRCK_TX0, H20 GPIO2_D[1]/I2S0_SCLK/MII_CRS
part J pins: A1 GPIO6_A[0], A2 GPIO6_B[7], A11 GPIO6_C[2], AA23 SARADC_AIN[0], AA24 SARADC_AIN[3], B1 GPIO6_B[6], B2 GPIO6_B[5], B3 GPIO6_A[1], B7 GPIO5_D[2]/PWM1/UART1_SIR_IN, B9 GPIO2_A[3]/SDMMC0_WRITE_PRT/PWM2/UART1_SIR_OUT, C1 GPIO6_A[5], C2 GPIO6_B[4], C3 GPIO6_A[2], C8 GPIO1_B[5]/PWM0, C10 GPIO4_D[4], C11 GPIO6_C[6], C12 GPIO6_C[0], D1 GPIO6_A[6], D2 GPIO6_A[7], D3 GPIO6_B[3], D4 GPIO6_A[3], D12 GPIO4_D[0], D13 GPIO6_C[3], E1 GPIO6_B[0], E2 GPIO5_A[0], E3 GPIO6_B[2], E4 GPIO5_A[2], E5 GPIO6_A[4], E10 GPIO6_C[5], E11 GPIO4_D[1], E12 GPIO6_C[1], E13 GPIO6_C[7], F1 GPIO6_B[1], F2 GPIO0_A[1], F3 GPIO5_A[1], F4 GPIO0_A[0], F9 GPIO4_D[3], F10 GPIO4_D[2], F11 GPIO4_D[5], F12 GPIO5_D[7], F13 GPIO6_C[4], G3 GPIO0_A[2], G4 GPIO0_A[4], H3 GPIO0_A[3], H4 GPIO4_A[3], J1 GPIO4_A[0], J2 GPIO4_A[1], J3 GPIO4_A[2], J4 GPIO4_A[4], N6 BTMODE, P7 EWAKEUP_STOP, P20 VDDCORE_EFUSE, R20 EFUSE_VQPS, T7 EWAKEUP_POWER, T19 VDDIO_EFUSE, V7 TEST, V8 GPIO6_D[2], V9 GPIO6_D[0], W7 GPIO6_D[3], W8 GPIO6_D[1], Y23 SARADC_AIN[1], Y24 SARADC_AIN[2]
part K pins: AB24 VDDA_SARADC, F5 AVDD_DPLL, F6 AHVDD_APLL, F7 AHVSS_APLL, G5 DVDD_APLL, G6 AVSS_DPLL, G7 DVSS_APLL, G8 VDDIO_AP1, G9 VDDIO_AP0, G10 VDDCORE, G11 VDDIO6, G12 VDDCORE, G13 VDDIO5, G14 VDDCORE, G15 VDDIO4, G16 VDDCORE, G18 VDDIO3, H5 DVDD_DPLL, H6 DVSS_DPLL, H7 DVSS_CGPLL, J5 AVDD_CGPLL, J6 DVDD_CGPLL, J7 AVSS_CGPLL, J18 VDDCORE, K7 VDDIO0, K10 GND, K11 GND, K12 GND, K13 GND, K14 GND, K15 GND, K18 VDDIO2, L7 VDDCORE, L10 GND, L11 GND, L12 GND, L13 GND, L14 GND, L15 GND, L18 VDDCORE, M5 VSSIO_DDR0, M10 GND, M11 GND, M12 GND, M13 GND, M14 GND, M15 GND, M18 VDDIO_FLASH1, N5 VDDIO_DDR0, N7 VDDCORE, N10 GND, N11 GND, N12 GND, N13 GND, N14 GND, N15 GND, N18 VDDCORE, P5 VSSIO_DDR1, P10 GND, P11 GND, P12 GND, P13 GND, P14 GND, P15 GND, P18 VDDIO_FLASH0, P21 VDDIO_RTC, R5 VDDIO_DDR1, R7 VDDCORE, R10 GND, R11 GND, R12 GND, R13 GND, R14 GND, R15 GND, R18 VDDCORE, R21 VSSIO_UHOST11, R22 VDDIO_UHOST11, T5 VSSIO_DDR2, T18 VDDIO1, T21 HOST20_VSSA, T22 HOST_VDD25, U5 VDDIO_DDR2, U7 VDDCORE, U18 VDDCORE_RTC, U19 HOST20_DVDD, U20 HOST20_VSSAC, U21 HOST20_DVSS, U23 HOST20_VDD33, V5 VSSIO_DDR3, V10 VDDCORE, V11 VDDIO_LCD0, V12 VDDCORE, V13 VDDIO_LCD1, V14 VDDCORE, V15 VDDIO_VIP, V16 VDDCORE, V17 VDDIO_SMC0, V18 VDDIO_SMC1, V19 OTG_DVDD, V21 OTG_VSSA, V22 OTG_VDD25, W5 VDDIO_DDR3, W20 OTG_VSSAC, W21 OTG_DVSS, W23 OTG_VDD33, Y5 VSSIO_DDR4, Y6 VDDIO_DDR4, Y7 VSSIO_DDR5, Y8 VDDIO_DDR5, Y9 VSSIO_DDR6, Y10 VDDIO_DDR6
part L pins: AA1 WE_B, AA2 CAS_B, AA3 ODT1, AA4 NC3, AA5 DLL_TEST_PIN[0], AA6 DQ12, AA7 DQ13, AA8 NC4, AA9 DQ28, AA10 DQ27, AB1 A10, AB2 RAS_B, AB3 NC2, AB4 A14, AB5 DQ9, AB6 DQ10, AB7 DM3, AB8 NC5, AB9 DQ26, AB10 DQ30, AC1 A8, AC2 A13, AC3 A7, AC4 DQ8, AC5 DM1, AC6 DQS1#, AC7 DQ14, AC8 DQ24, AC9 DQS3#, AC10 DQ29, AD1 A11, AD2 A15, AD3 A9, AD4 A12, AD5 DQ11, AD6 DQS1, AD7 DQ15, AD8 DQ25, AD9 DQS3, AD10 DQ31, K1 DQ3, K2 DQ2, K3 DQ1, K4 DQ0, L1 DQS0, L2 DQS0#, L3 DQ5, L4 DQ4, M1 DQ7, M2 DQ6, M3 DQ17, M4 DM0, N1 DQ19, N2 DQ18, N3 DM2, N4 DQ16, P1 DQS2, P2 DQS2#, P3 DQ21, P4 DQ20, P6 VREF0, R1 DQ23, R2 DQ22, R3 BA0, R4 ZQ_PIN, T1 A1, T2 A0, T3 BA1, T4 BA2, T6 ANALOG_TEST_PIN, U1 A2, U2 A3, U3 NC0, U4 NC1, U6 VREF1, V1 A6, V2 CS_B0, V3 A4, V4 A5, V6 RESET, W1 CS_B1, W2 ODT0, W3 CKE1, W4 RET_EN, W6 VREF2, W9 NC6, Y1 CK, Y2 CK#, Y3 CKE0, Y4 DLL_TEST_PIN[1]



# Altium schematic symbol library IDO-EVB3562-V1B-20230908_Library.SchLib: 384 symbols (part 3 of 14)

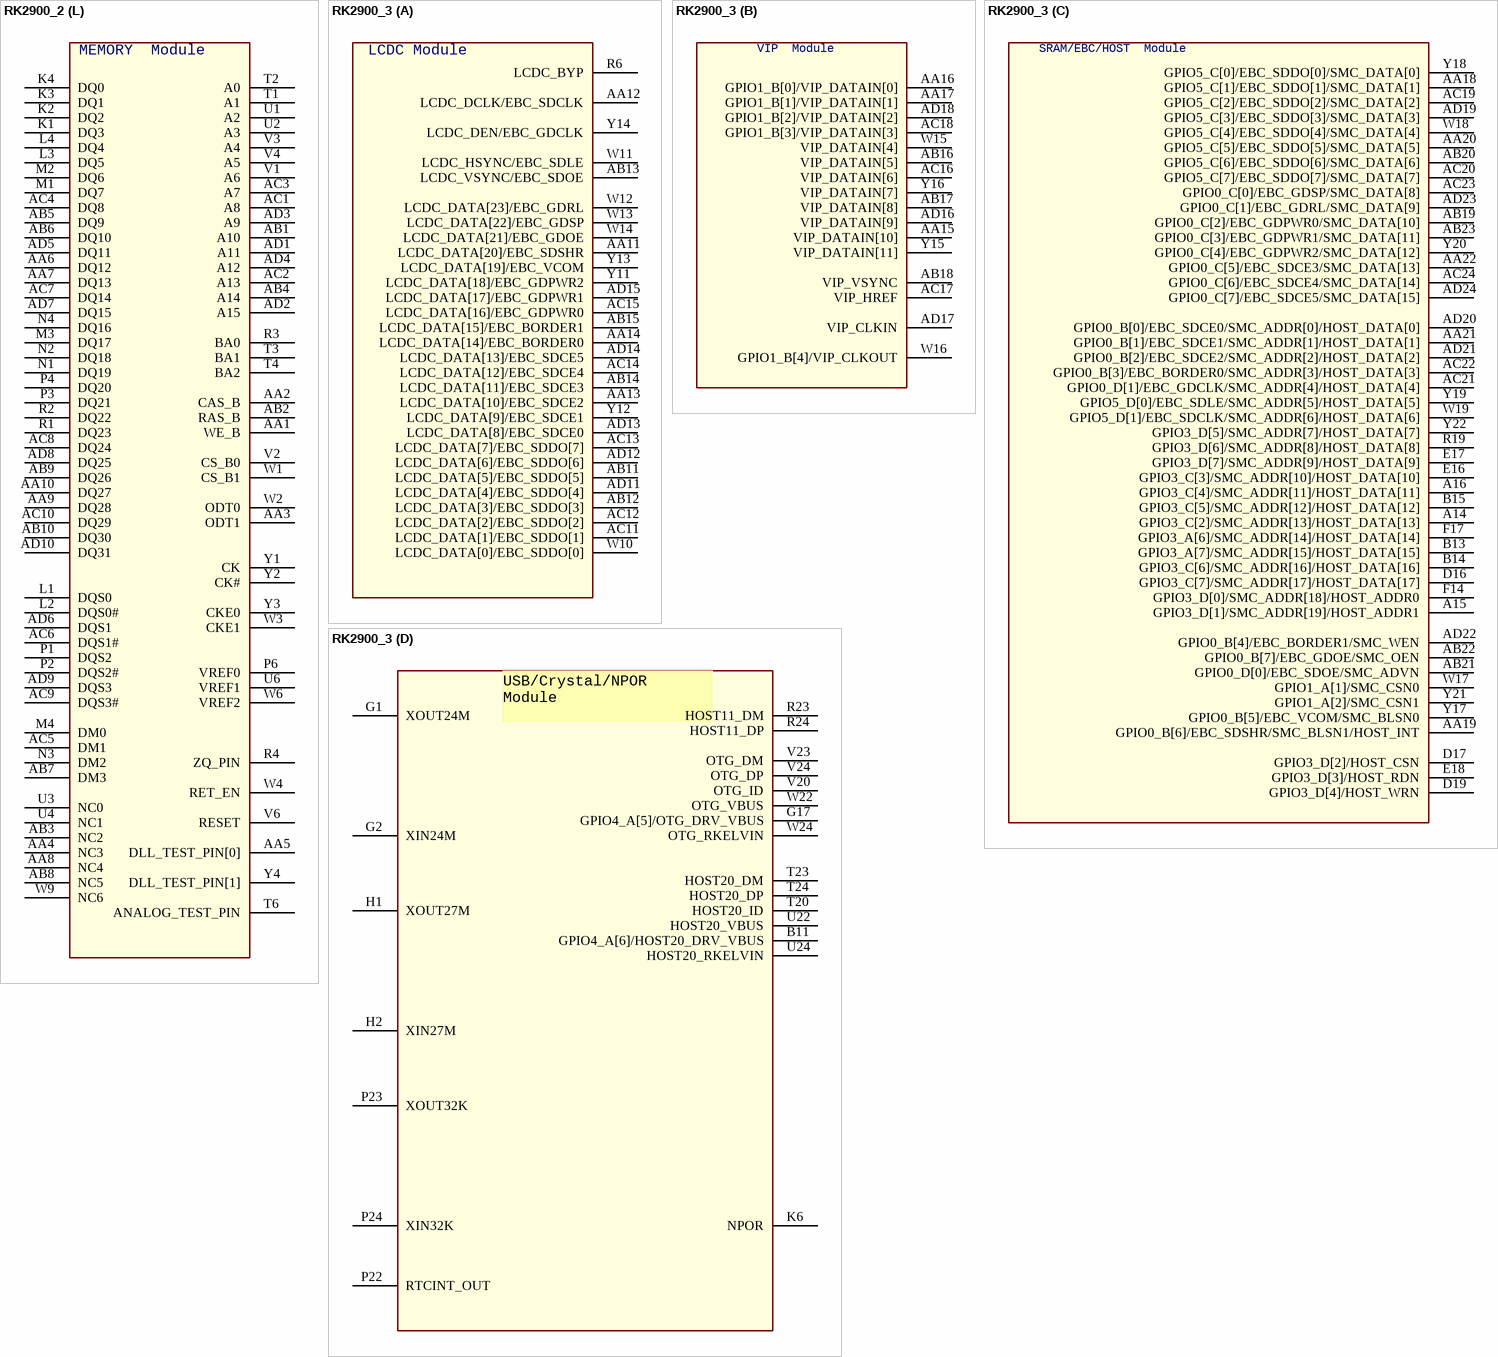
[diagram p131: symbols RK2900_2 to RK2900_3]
## RK2900_2
designator U?
footprint BGA512
part A pins: AA11 LCDC_DATA[20]/EBC_SDSHR, AA12 LCDC_DCLK/EBC_SDCLK, AA13 LCDC_DATA[10]/EBC_SDCE2, AA14 LCDC_DATA[14]/EBC_BORDER0, AB11 LCDC_DATA[5]/EBC_SDDO[5], AB12 LCDC_DATA[3]/EBC_SDDO[3], AB13 LCDC_VSYNC/EBC_SDOE, AB14 LCDC_DATA[11]/EBC_SDCE3, AB15 LCDC_DATA[15]/EBC_BORDER1, AC11 LCDC_DATA[1]/EBC_SDDO[1], AC12 LCDC_DATA[2]/EBC_SDDO[2], AC13 LCDC_DATA[7]/EBC_SDDO[7], AC14 LCDC_DATA[12]/EBC_SDCE4, AC15 LCDC_DATA[16]/EBC_GDPWR0, AD11 LCDC_DATA[4]/EBC_SDDO[4], AD12 LCDC_DATA[6]/EBC_SDDO[6], AD13 LCDC_DATA[8]/EBC_SDCE0, AD14 LCDC_DATA[13]/EBC_SDCE5, AD15 LCDC_DATA[17]/EBC_GDPWR1, R6 LCDC_BYP, W10 LCDC_DATA[0]/EBC_SDDO[0], W11 LCDC_HSYNC/EBC_SDLE, W12 LCDC_DATA[23]/EBC_GDRL, W13 LCDC_DATA[22]/EBC_GDSP, W14 LCDC_DATA[21]/EBC_GDOE, Y11 LCDC_DATA[18]/EBC_GDPWR2, Y12 LCDC_DATA[9]/EBC_SDCE1, Y13 LCDC_DATA[19]/EBC_VCOM, Y14 LCDC_DEN/EBC_GDCLK
part B pins: AA15 VIP_DATAIN[10], AA16 GPIO1_B[0]/VIP_DATAIN[0], AA17 GPIO1_B[1]/VIP_DATAIN[1], AB16 VIP_DATAIN[5], AB17 VIP_DATAIN[8], AB18 VIP_VSYNC, AC16 VIP_DATAIN[6], AC17 VIP_HREF, AC18 GPIO1_B[3]/VIP_DATAIN[3], AD16 VIP_DATAIN[9], AD17 VIP_CLKIN, AD18 GPIO1_B[2]/VIP_DATAIN[2], W15 VIP_DATAIN[4], W16 GPIO1_B[4]/VIP_CLKOUT, Y15 VIP_DATAIN[11], Y16 VIP_DATAIN[7]
part C pins: A14 GPIO3_C[2]/SMC_ADDR[13]/HOST_DATA[13], A15 GPIO3_D[1]/SMC_ADDR[19]/HOST_ADDR1, A16 GPIO3_C[4]/SMC_ADDR[11]/HOST_DATA[11], AA18 GPIO5_C[1]/EBC_SDDO[1]/SMC_DATA[1], AA19 GPIO0_B[6]/EBC_SDSHR/SMC_BLSN1/HOST_INT, AA20 GPIO5_C[5]/EBC_SDDO[5]/SMC_DATA[5], AA21 GPIO0_B[1]/EBC_SDCE1/SMC_ADDR[1]/HOST_DATA[1], AA22 GPIO0_C[5]/EBC_SDCE3/SMC_DATA[13], AB19 GPIO0_C[2]/EBC_GDPWR0/SMC_DATA[10], AB20 GPIO5_C[6]/EBC_SDDO[6]/SMC_DATA[6], AB21 GPIO0_D[0]/EBC_SDOE/SMC_ADVN, AB22 GPIO0_B[7]/EBC_GDOE/SMC_OEN, AB23 GPIO0_C[3]/EBC_GDPWR1/SMC_DATA[11], AC19 GPIO5_C[2]/EBC_SDDO[2]/SMC_DATA[2], AC20 GPIO5_C[7]/EBC_SDDO[7]/SMC_DATA[7], AC21 GPIO0_D[1]/EBC_GDCLK/SMC_ADDR[4]/HOST_DATA[4], AC22 GPIO0_B[3]/EBC_BORDER0/SMC_ADDR[3]/HOST_DATA[3], AC23 GPIO0_C[0]/EBC_GDSP/SMC_DATA[8], AC24 GPIO0_C[6]/EBC_SDCE4/SMC_DATA[14], AD19 GPIO5_C[3]/EBC_SDDO[3]/SMC_DATA[3], AD20 GPIO0_B[0]/EBC_SDCE0/SMC_ADDR[0]/HOST_DATA[0], AD21 GPIO0_B[2]/EBC_SDCE2/SMC_ADDR[2]/HOST_DATA[2], AD22 GPIO0_B[4]/EBC_BORDER1/SMC_WEN, AD23 GPIO0_C[1]/EBC_GDRL/SMC_DATA[9], AD24 GPIO0_C[7]/EBC_SDCE5/SMC_DATA[15], B13 GPIO3_A[7]/SMC_ADDR[15]/HOST_DATA[15], B14 GPIO3_C[6]/SMC_ADDR[16]/HOST_DATA[16], B15 GPIO3_C[5]/SMC_ADDR[12]/HOST_DATA[12], D16 GPIO3_C[7]/SMC_ADDR[17]/HOST_DATA[17], D17 GPIO3_D[2]/HOST_CSN, D19 GPIO3_D[4]/HOST_WRN, E16 GPIO3_C[3]/SMC_ADDR[10]/HOST_DATA[10], E17 GPIO3_D[7]/SMC_ADDR[9]/HOST_DATA[9], E18 GPIO3_D[3]/HOST_RDN, F14 GPIO3_D[0]/SMC_ADDR[18]/HOST_ADDR0, F17 GPIO3_A[6]/SMC_ADDR[14]/HOST_DATA[14], R19 GPIO3_D[6]/SMC_ADDR[8]/HOST_DATA[8], W17 GPIO1_A[1]/SMC_CSN0, W18 GPIO5_C[4]/EBC_SDDO[4]/SMC_DATA[4], W19 GPIO5_D[1]/EBC_SDCLK/SMC_ADDR[6]/HOST_DATA[6], Y17 GPIO0_B[5]/EBC_VCOM/SMC_BLSN0, Y18 GPIO5_C[0]/EBC_SDDO[0]/SMC_DATA[0], Y19 GPIO5_D[0]/EBC_SDLE/SMC_ADDR[5]/HOST_DATA[5], Y20 GPIO0_C[4]/EBC_GDPWR2/SMC_DATA[12], Y21 GPIO1_A[2]/SMC_CSN1, Y22 GPIO3_D[5]/SMC_ADDR[7]/HOST_DATA[7]
part D pins: B11 GPIO4_A[6]/HOST20_DRV_VBUS, G1 XOUT24M, G2 XIN24M, G17 GPIO4_A[5]/OTG_DRV_VBUS, H1 XOUT27M, H2 XIN27M, K6 NPOR, P22 RTCINT_OUT, P23 XOUT32K, P24 XIN32K, R23 HOST11_DM, R24 HOST11_DP, T20 HOST20_ID, T23 HOST20_DM, T24 HOST20_DP, U22 HOST20_VBUS, U24 HOST20_RKELVIN, V20 OTG_ID, V23 OTG_DM, V24 OTG_DP, W22 OTG_VBUS, W24 OTG_RKELVIN
part E pins: A9 GPIO1_A[5]/EMMC_PWR_EN/PWM3, D23 GPIO3_B[7]/EMMC_DATA5, E22 GPIO3_B[0]/EMMC_CLKOUT, F21 GPIO3_C[0]/EMMC_DATA6, F22 GPIO3_B[2]/EMMC_DATA0, F23 GPIO3_B[4]/EMMC_DATA2, F24 GPIO3_B[5]/EMMC_DATA3, G21 GPIO3_C[1]/EMMC_DATA7, G23 GPIO3_B[6]/EMMC_DATA4, H21 GPIO3_B[1]/EMMC_CMD, H24 GPIO3_B[3]/EMMC_DATA1, J19 GPIO0_D[6]/FLASH_CSN5, J20 GPIO1_A[0]/FLASH_CSN7/MDDR_TQ, J21 GPIO0_A[5]/FLASH_DQS, J22 GPIO0_D[5]/FLASH_CSN4, J23 GPIO4_B[2]/FLASH_DATA[10], J24 GPIO4_B[3]/FLASH_DATA[11], K19 FLASH_WP, K20 FLASH_WRN, K21 GPIO4_B[6]/FLASH_DATA[14], K22 GPIO0_D[3]/FLASH_CSN2, K23 GPIO0_D[4]/FLASH_CSN3, K24 GPIO0_D[2]/FLASH_CSN1, L19 FLASH_DATA[6], L20 GPIO4_B[0]/FLASH_DATA[8], L21 FLASH_DATA[7], L22 FLASH_DATA[2], L23 FLASH_DATA[3], L24 GPIO0_D[7]/FLASH_CSN6, M19 GPIO4_B[7]/FLASH_DATA[15], M20 GPIO4_B[5]/FLASH_DATA[13], M21 FLASH_CLE, M22 GPIO4_B[1]/FLASH_DATA[9], M23 FLASH_DATA[5], M24 FLASH_CSN0, N19 FLASH_DATA[1], N20 FLASH_RDY, N21 FLASH_RDN, N22 GPIO4_B[4]/FLASH_DATA[12], N23 FLASH_DATA[0], N24 FLASH_DATA[4], P19 FLASH_ALE
part F pins: A6 GPIO5_D[6]/SDMMC1_PWR_EN, A7 GPIO5_D[5]/SDMMC0_PWR_EN, B10 GPIO2_A[2]/SDMMC0_DETECT_N, B24 GPIO1_D[4]/SDMMC0_DATA2, C22 GPIO2_A[0]/SDMMC0_DATA6, C23 GPIO1_D[6]/SDMMC0_DATA4, D20 GPIO1_D[2]/SDMMC0_DATA0, D22 GPIO1_D[0]/SDMMC0_CLKOUT, D24 GPIO1_C[2]/SDMMC1_CMD, E20 GPIO1_D[7]/SDMMC0_DATA5, E23 GPIO2_A[1]/SDMMC0_DATA7, G19 GPIO1_D[5]/SDMMC0_DATA3, G20 GPIO1_D[1]/SDMMC0_CMD, G22 GPIO1_D[3]/SDMMC0_DATA1, G24 GPIO1_C[7]/SDMMC1_CLKOUT, H18 GPIO1_C[5]/SDMMC1_DATA2, H19 GPIO1_C[6]/SDMMC1_DATA3, H22 GPIO1_C[3]/SDMMC1_DATA0, H23 GPIO1_C[4]/SDMMC1_DATA1
part G pins: A18 GPIO4_C[5]/RMII_CRS_DVALID/MII_RXD_VALID, A20 GPIO4_C[0]/RMII_CLKOUT/RMII_CLKIN, A22 GPIO4_C[1]/RMII_TX_EN/MII_TX_EN, B18 GPIO5_A[3]/MII_TX_CLKIN, B23 GPIO4_C[6]/RMII_RXD1/MII_RXD1, C18 GPIO4_C[4]/RMII_RX_ERR/MII_RX_ERR, C19 GPIO4_C[2]/RMII_TXD1/MII_TXD1, D11 GPIO0_A[7]/MII_MDCLK, D18 GPIO0_A[6]/MII_MD, D21 GPIO4_C[3]/RMII_TXD0/MII_TXD0, E19 GPIO4_C[7]/RMII_RXD0/MII_RXD0, K5 TRST_N, L5 TCK, L6 TDI, M6 TMS, M7 TDO
part H pins: A17 GPIO5_B[3]/HSADC_DATA6, A19 GPIO5_A[7]/HSADC_DATA2, B17 GPIO5_B[2]/HSADC_DATA5, B19 GPIO5_B[5]/HSADC_DATA8/TS_VALID, B20 GPIO5_A[5]/HSADC_DATA0, C13 GPIO5_B[6]/HSADC_DATA9/TS_FAIL, C16 GPIO5_A[4]/TS_SYNC, C17 GPIO5_B[4]/HSADC_DATA7, C20 GPIO5_B[1]/HSADC_DATA4, E21 GPIO5_B[0]/HSADC_DATA3, F18 GPIO5_A[6]/HSADC_DATA1, F19 GPIO5_B[7]/HSADC_CLKOUT/GPS_CLK
part I pins: A3 GPIO1_C[0]/UART0_CTS_N/SDMMC1_DETECT_N, A4 GPIO3_A[5]/I2S1_LRCK_TX, A5 GPIO3_A[4]/I2S1_SDO, A8 GPIO2_B[2]/UART3_SIN, A10 GPIO1_A[4]/EMMC_WRITE_PRT/SPI0_CSN1, A12 GPIO1_A[6]/I2C1_SDA, A13 GPIO2_C[5]/SPI1_CSN0, A21 GPIO2_D[2]/I2S0_LRCK_RX/MII_TX_ERR, A23 GPIO2_D[5]/I2S0_SDO1/MII_RXD3, A24 GPIO2_D[6]/I2S0_SDO2/MII_TXD2, B4 GPIO2_A[7]/UART2_RTS_N, B5 GPIO3_A[3]/I2S1_SDI, B6 GPIO3_A[1]/I2S1_SCLK, B8 GPIO5_D[3]/I2C2_SDA, B12 GPIO1_A[7]/I2C1_SCL, B16 GPIO2_C[6]/SPI1_TXD, B21 GPIO4_D[7]/I2S0_LRCK_TX1, B22 GPIO2_D[3]/I2S0_SDI/MII_COL, C4 GPIO1_C[1]/UART0_RTS_N/SDMMC1_WRITE_PRT, C5 GPIO2_A[6]/UART2_CTS_N, C6 GPIO3_A[2]/I2S1_LRCK_RX, C7 GPIO2_A[4]/UART1_SIN, C9 GPIO2_B[6]/I2C0_SDA, C14 GPIO2_C[7]/SPI1_RXD, C15 GPIO4_A[7]/SPDIF_TX, C21 GPIO2_D[4]/I2S0_SDO0/MII_RXD2, C24 GPIO2_D[7]/I2S0_SDO3/MII_TXD3, D5 GPIO1_B[7]/UART0_SOUT, D6 GPIO2_B[4]/UART3_CTS_N/I2C3_SDA, D7 GPIO3_A[0]/I2S1_CLK, D8 GPIO1_B[6]/UART0_SIN, D9 GPIO5_D[4]/I2C2_SCL, D10 GPIO2_B[7]/I2C0_SCL, D14 GPIO2_C[0]/SPI0_CLK, D15 GPIO2_C[3]/SPI0_RXD, E6 GPIO2_B[0]/UART2_SIN, E7 GPIO2_B[5]/UART3_RTS_N/I2C3_SCL, E8 GPIO2_B[1]/UART2_SOUT, E9 GPIO2_A[5]/UART1_SOUT, E14 GPIO2_C[1]/SPI0_CSN0, E15 GPIO2_C[2]/SPI0_TXD, E24 GPIO2_D[0]/I2S0_CLK/MII_RX_CLKIN, F8 GPIO2_B[3]/UART3_SOUT, F15 GPIO1_A[3]/EMMC_DETECT_N/SPI1_CSN1, F16 GPIO2_C[4]/SPI1_CLK, F20 GPIO4_D[6]/I2S0_LRCK_TX0, H20 GPIO2_D[1]/I2S0_SCLK/MII_CRS
part J pins: A1 GPIO6_A[0], A2 GPIO6_B[7], A11 GPIO6_C[2], AA23 SARADC_AIN[0], AA24 SARADC_AIN[3], B1 GPIO6_B[6], B2 GPIO6_B[5], B3 GPIO6_A[1], B7 GPIO5_D[2]/PWM1/UART1_SIR_IN, B9 GPIO2_A[3]/SDMMC0_WRITE_PRT/PWM2/UART1_SIR_OUT, C1 GPIO6_A[5], C2 GPIO6_B[4], C3 GPIO6_A[2], C8 GPIO1_B[5]/PWM0, C10 GPIO4_D[4], C11 GPIO6_C[6], C12 GPIO6_C[0], D1 GPIO6_A[6], D2 GPIO6_A[7], D3 GPIO6_B[3], D4 GPIO6_A[3], D12 GPIO4_D[0], D13 GPIO6_C[3], E1 GPIO6_B[0], E2 GPIO5_A[0], E3 GPIO6_B[2], E4 GPIO5_A[2], E5 GPIO6_A[4], E10 GPIO6_C[5], E11 GPIO4_D[1], E12 GPIO6_C[1], E13 GPIO6_C[7], F1 GPIO6_B[1], F2 GPIO0_A[1], F3 GPIO5_A[1], F4 GPIO0_A[0], F9 GPIO4_D[3], F10 GPIO4_D[2], F11 GPIO4_D[5], F12 GPIO5_D[7], F13 GPIO6_C[4], G3 GPIO0_A[2], G4 GPIO0_A[4], H3 GPIO0_A[3], H4 GPIO4_A[3], J1 GPIO4_A[0], J2 GPIO4_A[1], J3 GPIO4_A[2], J4 GPIO4_A[4], N6 BTMODE, P7 EWAKEUP_STOP, P20 VDDCORE_EFUSE, R20 EFUSE_VQPS, T7 EWAKEUP_POWER, T19 VDDIO_EFUSE, V7 TEST, V8 GPIO6_D[2], V9 GPIO6_D[0], W7 GPIO6_D[3], W8 GPIO6_D[1], Y23 SARADC_AIN[1], Y24 SARADC_AIN[2]
part K pins: AB24 VDDA_SARADC, F5 AVDD_DPLL, F6 AHVDD_APLL, F7 AHVSS_APLL, G5 DVDD_APLL, G6 AVSS_DPLL, G7 DVSS_APLL, G8 VDDIO_AP1, G9 VDDIO_AP0, G10 VDDCORE, G11 VDDIO6, G12 VDDCORE, G13 VDDIO5, G14 VDDCORE, G15 VDDIO4, G16 VDDCORE, G18 VDDIO3, H5 DVDD_DPLL, H6 DVSS_DPLL, H7 DVSS_CGPLL, J5 AVDD_CGPLL, J6 DVDD_CGPLL, J7 AVSS_CGPLL, J18 VDDCORE, K7 VDDIO0, K10 GND, K11 GND, K12 GND, K13 GND, K14 GND, K15 GND, K18 VDDIO2, L7 VDDCORE, L10 GND, L11 GND, L12 GND, L13 GND, L14 GND, L15 GND, L18 VDDCORE, M5 VSSIO_DDR0, M10 GND, M11 GND, M12 GND, M13 GND, M14 GND, M15 GND, M18 VDDIO_FLASH1, N5 VDDIO_DDR0, N7 VDDCORE, N10 GND, N11 GND, N12 GND, N13 GND, N14 GND, N15 GND, N18 VDDCORE, P5 VSSIO_DDR1, P10 GND, P11 GND, P12 GND, P13 GND, P14 GND, P15 GND, P18 VDDIO_FLASH0, P21 VDDIO_RTC, R5 VDDIO_DDR1, R7 VDDCORE, R10 GND, R11 GND, R12 GND, R13 GND, R14 GND, R15 GND, R18 VDDCORE, R21 VSSIO_UHOST11, R22 VDDIO_UHOST11, T5 VSSIO_DDR2, T18 VDDIO1, T21 HOST20_VSSA, T22 HOST_VDD25, U5 VDDIO_DDR2, U7 VDDCORE, U18 VDDCORE_RTC, U19 HOST20_DVDD, U20 HOST20_VSSAC, U21 HOST20_DVSS, U23 HOST20_VDD33, V5 VSSIO_DDR3, V10 VDDCORE, V11 VDDIO_LCD0, V12 VDDCORE, V13 VDDIO_LCD1, V14 VDDCORE, V15 VDDIO_VIP, V16 VDDCORE, V17 VDDIO_SMC0, V18 VDDIO_SMC1, V19 OTG_DVDD, V21 OTG_VSSA, V22 OTG_VDD25, W5 VDDIO_DDR3, W20 OTG_VSSAC, W21 OTG_DVSS, W23 OTG_VDD33, Y5 VSSIO_DDR4, Y6 VDDIO_DDR4, Y7 VSSIO_DDR5, Y8 VDDIO_DDR5, Y9 VSSIO_DDR6, Y10 VDDIO_DDR6
part L pins: AA1 WE_B, AA2 CAS_B, AA3 ODT1, AA4 NC3, AA5 DLL_TEST_PIN[0], AA6 DQ12, AA7 DQ13, AA8 NC4, AA9 DQ28, AA10 DQ27, AB1 A10, AB2 RAS_B, AB3 NC2, AB4 A14, AB5 DQ9, AB6 DQ10, AB7 DM3, AB8 NC5, AB9 DQ26, AB10 DQ30, AC1 A8, AC2 A13, AC3 A7, AC4 DQ8, AC5 DM1, AC6 DQS1#, AC7 DQ14, AC8 DQ24, AC9 DQS3#, AC10 DQ29, AD1 A11, AD2 A15, AD3 A9, AD4 A12, AD5 DQ11, AD6 DQS1, AD7 DQ15, AD8 DQ25, AD9 DQS3, AD10 DQ31, K1 DQ3, K2 DQ2, K3 DQ1, K4 DQ0, L1 DQS0, L2 DQS0#, L3 DQ5, L4 DQ4, M1 DQ7, M2 DQ6, M3 DQ17, M4 DM0, N1 DQ19, N2 DQ18, N3 DM2, N4 DQ16, P1 DQS2, P2 DQS2#, P3 DQ21, P4 DQ20, P6 VREF0, R1 DQ23, R2 DQ22, R3 BA0, R4 ZQ_PIN, T1 A1, T2 A0, T3 BA1, T4 BA2, T6 ANALOG_TEST_PIN, U1 A2, U2 A3, U3 NC0, U4 NC1, U6 VREF1, V1 A6, V2 CS_B0, V3 A4, V4 A5, V6 RESET, W1 CS_B1, W2 ODT0, W3 CKE1, W4 RET_EN, W6 VREF2, W9 NC6, Y1 CK, Y2 CK#, Y3 CKE0, Y4 DLL_TEST_PIN[1]




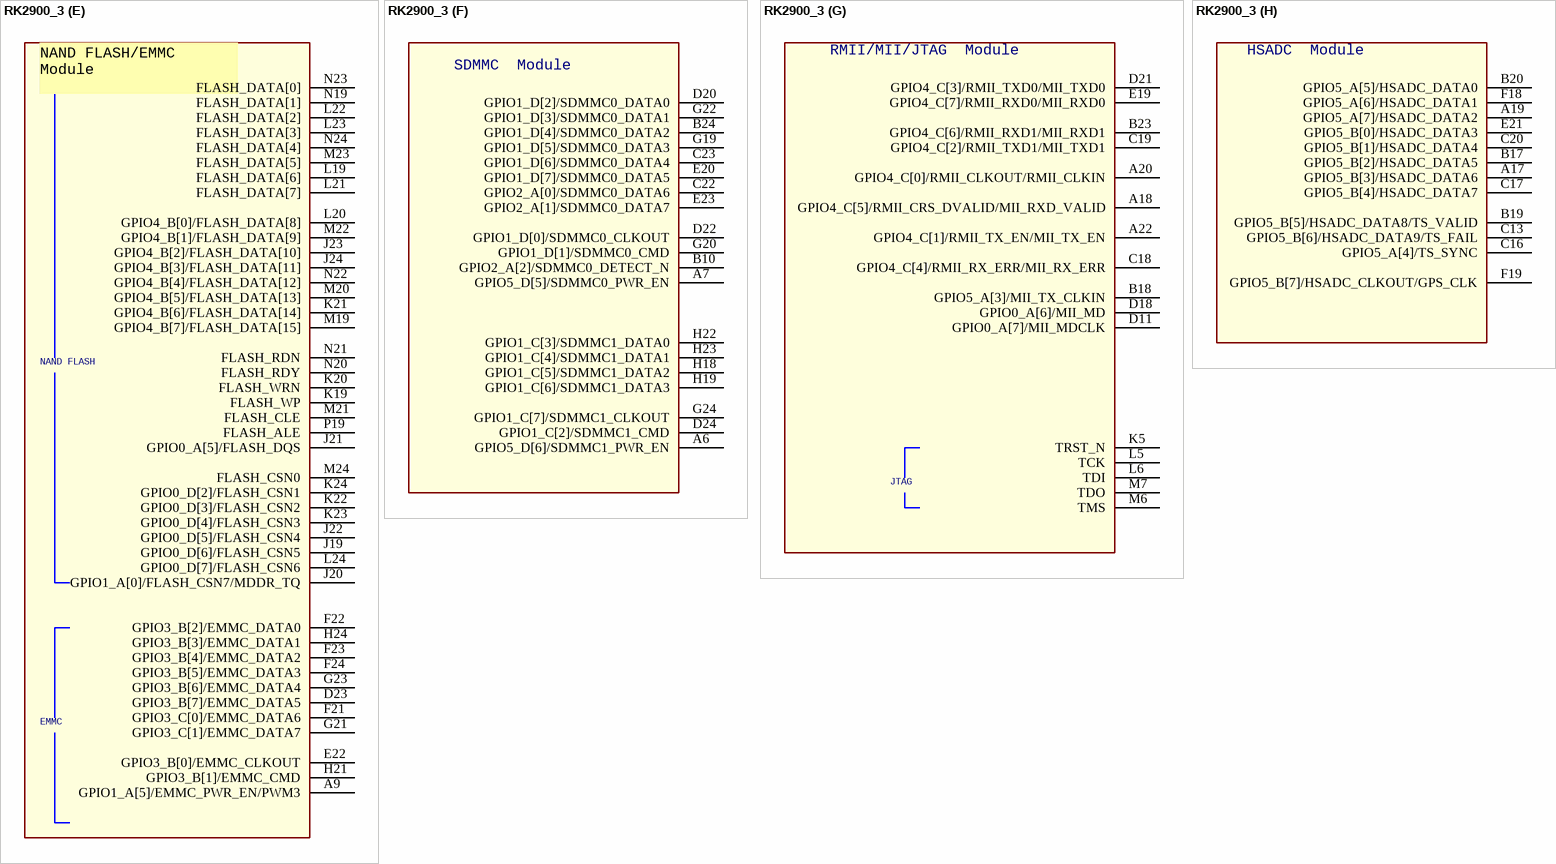
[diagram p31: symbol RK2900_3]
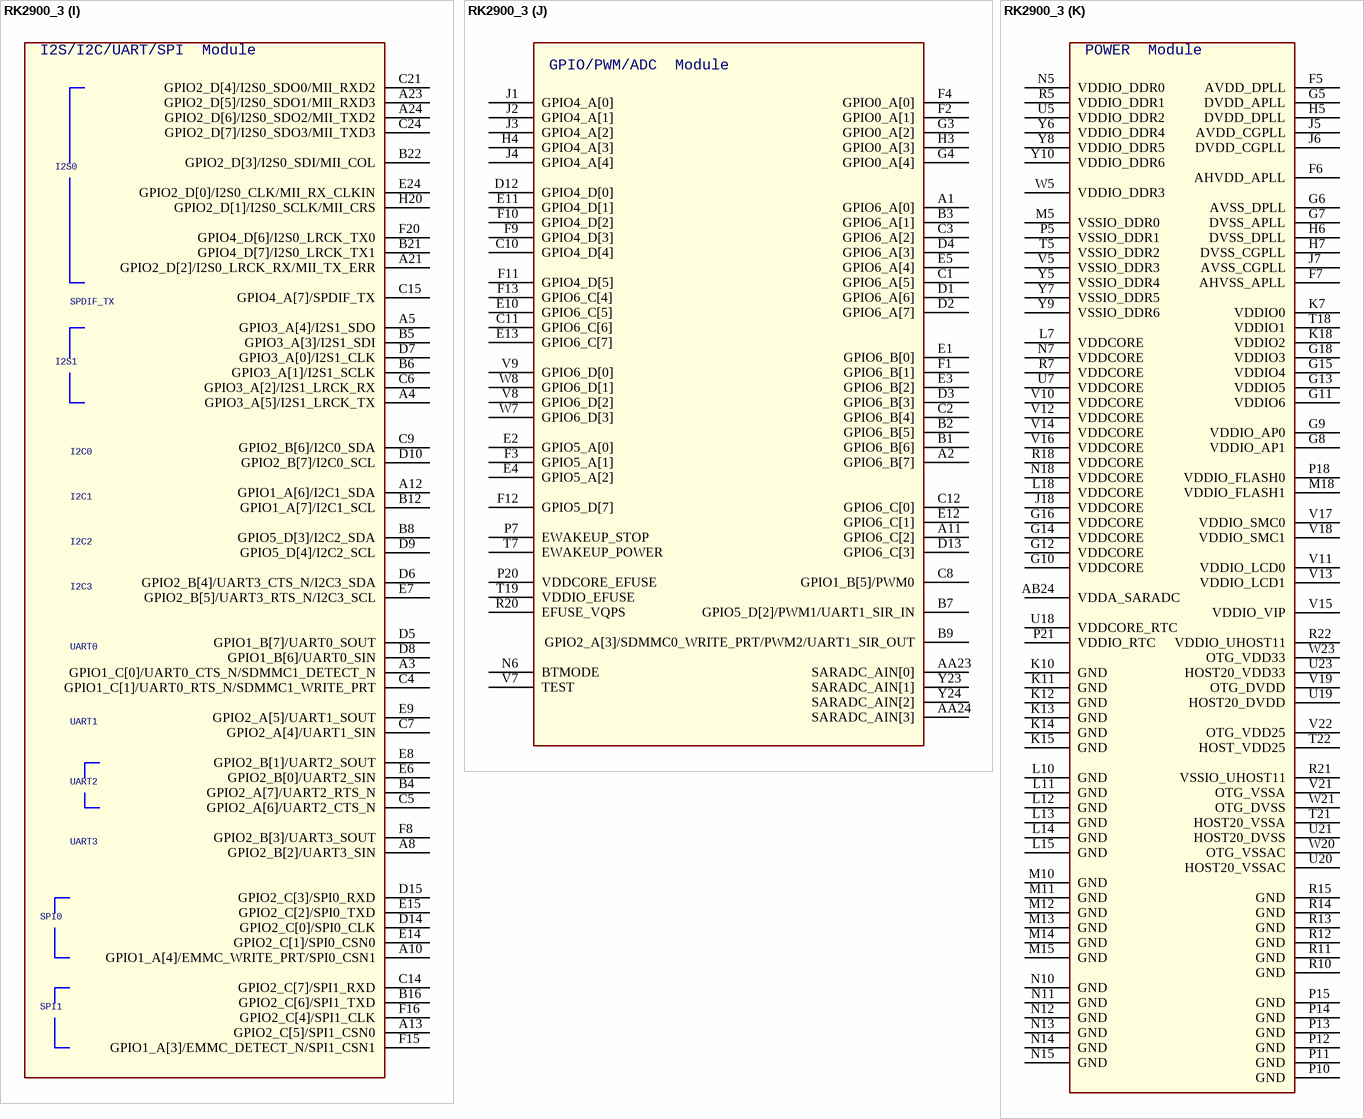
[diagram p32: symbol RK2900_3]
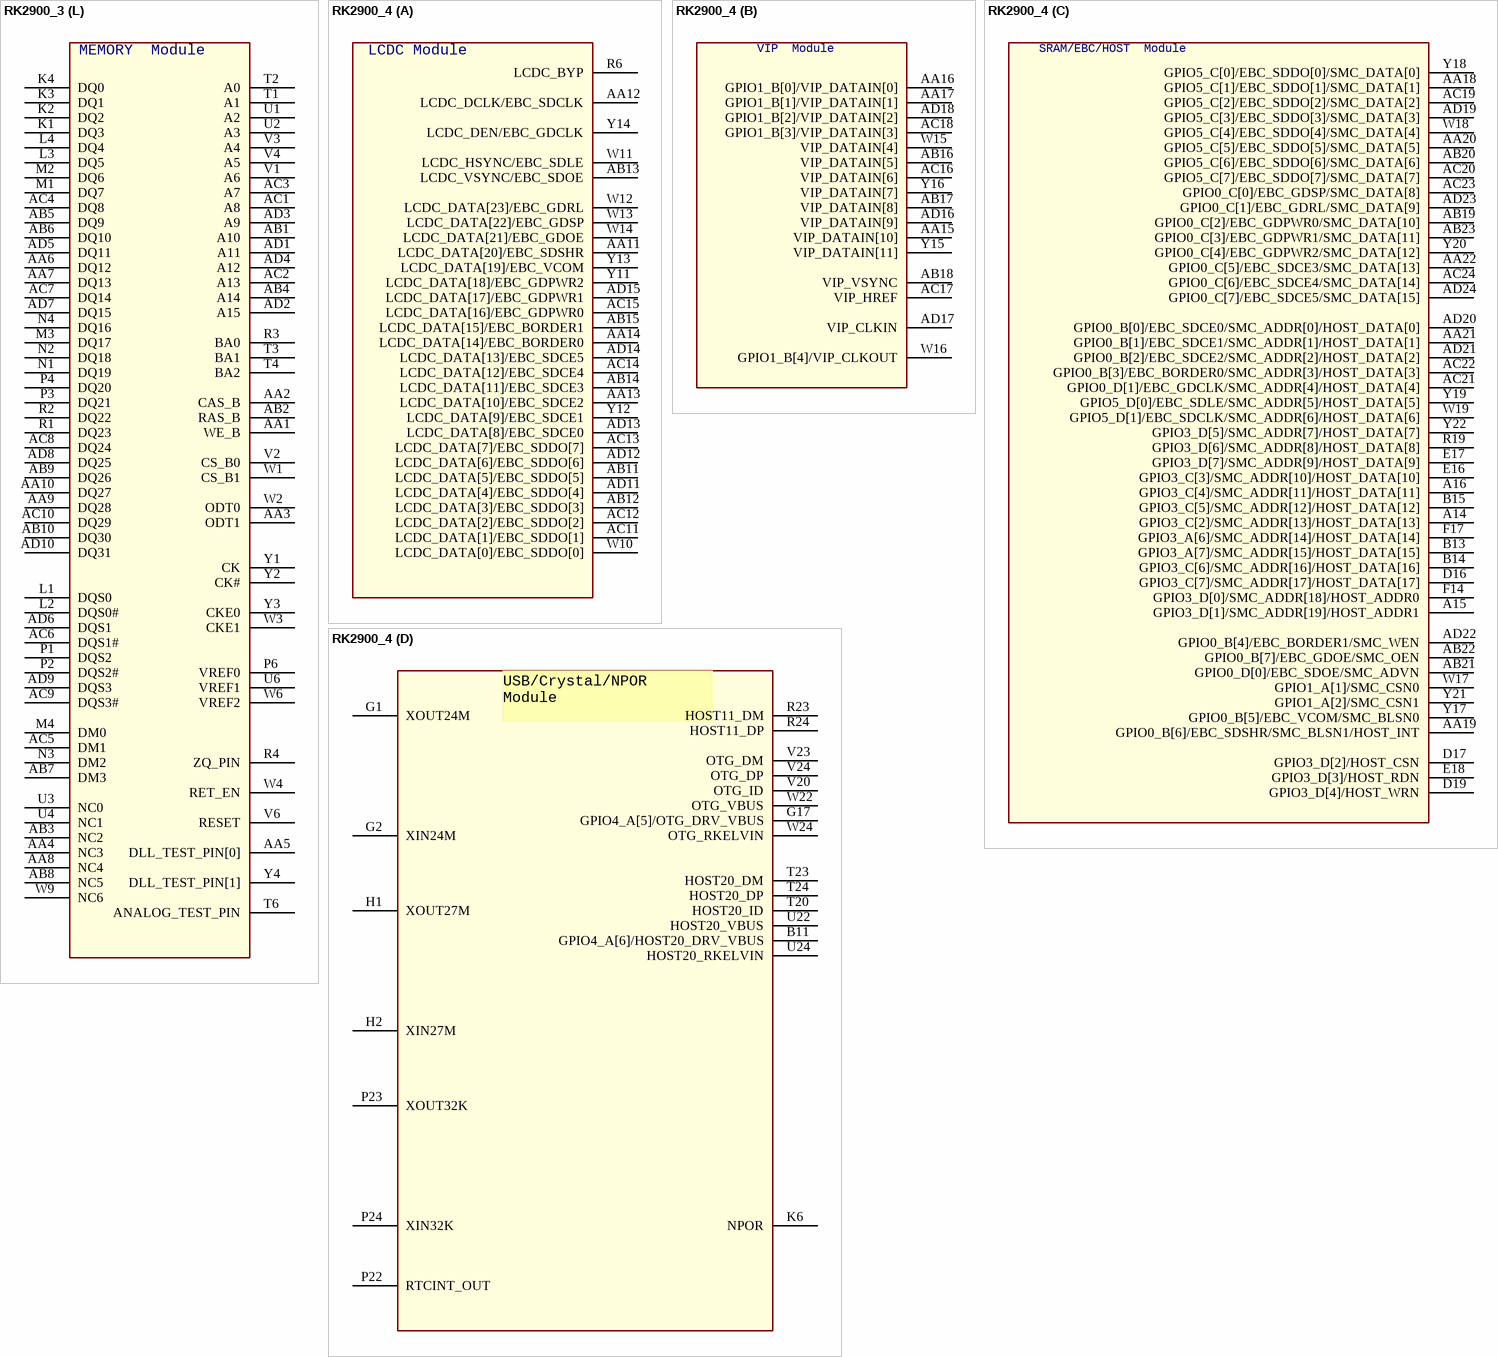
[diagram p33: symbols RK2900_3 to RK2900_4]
## RK2900_3
designator U?
footprint BGA512
part A pins: AA11 LCDC_DATA[20]/EBC_SDSHR, AA12 LCDC_DCLK/EBC_SDCLK, AA13 LCDC_DATA[10]/EBC_SDCE2, AA14 LCDC_DATA[14]/EBC_BORDER0, AB11 LCDC_DATA[5]/EBC_SDDO[5], AB12 LCDC_DATA[3]/EBC_SDDO[3], AB13 LCDC_VSYNC/EBC_SDOE, AB14 LCDC_DATA[11]/EBC_SDCE3, AB15 LCDC_DATA[15]/EBC_BORDER1, AC11 LCDC_DATA[1]/EBC_SDDO[1], AC12 LCDC_DATA[2]/EBC_SDDO[2], AC13 LCDC_DATA[7]/EBC_SDDO[7], AC14 LCDC_DATA[12]/EBC_SDCE4, AC15 LCDC_DATA[16]/EBC_GDPWR0, AD11 LCDC_DATA[4]/EBC_SDDO[4], AD12 LCDC_DATA[6]/EBC_SDDO[6], AD13 LCDC_DATA[8]/EBC_SDCE0, AD14 LCDC_DATA[13]/EBC_SDCE5, AD15 LCDC_DATA[17]/EBC_GDPWR1, R6 LCDC_BYP, W10 LCDC_DATA[0]/EBC_SDDO[0], W11 LCDC_HSYNC/EBC_SDLE, W12 LCDC_DATA[23]/EBC_GDRL, W13 LCDC_DATA[22]/EBC_GDSP, W14 LCDC_DATA[21]/EBC_GDOE, Y11 LCDC_DATA[18]/EBC_GDPWR2, Y12 LCDC_DATA[9]/EBC_SDCE1, Y13 LCDC_DATA[19]/EBC_VCOM, Y14 LCDC_DEN/EBC_GDCLK
part B pins: AA15 VIP_DATAIN[10], AA16 GPIO1_B[0]/VIP_DATAIN[0], AA17 GPIO1_B[1]/VIP_DATAIN[1], AB16 VIP_DATAIN[5], AB17 VIP_DATAIN[8], AB18 VIP_VSYNC, AC16 VIP_DATAIN[6], AC17 VIP_HREF, AC18 GPIO1_B[3]/VIP_DATAIN[3], AD16 VIP_DATAIN[9], AD17 VIP_CLKIN, AD18 GPIO1_B[2]/VIP_DATAIN[2], W15 VIP_DATAIN[4], W16 GPIO1_B[4]/VIP_CLKOUT, Y15 VIP_DATAIN[11], Y16 VIP_DATAIN[7]
part C pins: A14 GPIO3_C[2]/SMC_ADDR[13]/HOST_DATA[13], A15 GPIO3_D[1]/SMC_ADDR[19]/HOST_ADDR1, A16 GPIO3_C[4]/SMC_ADDR[11]/HOST_DATA[11], AA18 GPIO5_C[1]/EBC_SDDO[1]/SMC_DATA[1], AA19 GPIO0_B[6]/EBC_SDSHR/SMC_BLSN1/HOST_INT, AA20 GPIO5_C[5]/EBC_SDDO[5]/SMC_DATA[5], AA21 GPIO0_B[1]/EBC_SDCE1/SMC_ADDR[1]/HOST_DATA[1], AA22 GPIO0_C[5]/EBC_SDCE3/SMC_DATA[13], AB19 GPIO0_C[2]/EBC_GDPWR0/SMC_DATA[10], AB20 GPIO5_C[6]/EBC_SDDO[6]/SMC_DATA[6], AB21 GPIO0_D[0]/EBC_SDOE/SMC_ADVN, AB22 GPIO0_B[7]/EBC_GDOE/SMC_OEN, AB23 GPIO0_C[3]/EBC_GDPWR1/SMC_DATA[11], AC19 GPIO5_C[2]/EBC_SDDO[2]/SMC_DATA[2], AC20 GPIO5_C[7]/EBC_SDDO[7]/SMC_DATA[7], AC21 GPIO0_D[1]/EBC_GDCLK/SMC_ADDR[4]/HOST_DATA[4], AC22 GPIO0_B[3]/EBC_BORDER0/SMC_ADDR[3]/HOST_DATA[3], AC23 GPIO0_C[0]/EBC_GDSP/SMC_DATA[8], AC24 GPIO0_C[6]/EBC_SDCE4/SMC_DATA[14], AD19 GPIO5_C[3]/EBC_SDDO[3]/SMC_DATA[3], AD20 GPIO0_B[0]/EBC_SDCE0/SMC_ADDR[0]/HOST_DATA[0], AD21 GPIO0_B[2]/EBC_SDCE2/SMC_ADDR[2]/HOST_DATA[2], AD22 GPIO0_B[4]/EBC_BORDER1/SMC_WEN, AD23 GPIO0_C[1]/EBC_GDRL/SMC_DATA[9], AD24 GPIO0_C[7]/EBC_SDCE5/SMC_DATA[15], B13 GPIO3_A[7]/SMC_ADDR[15]/HOST_DATA[15], B14 GPIO3_C[6]/SMC_ADDR[16]/HOST_DATA[16], B15 GPIO3_C[5]/SMC_ADDR[12]/HOST_DATA[12], D16 GPIO3_C[7]/SMC_ADDR[17]/HOST_DATA[17], D17 GPIO3_D[2]/HOST_CSN, D19 GPIO3_D[4]/HOST_WRN, E16 GPIO3_C[3]/SMC_ADDR[10]/HOST_DATA[10], E17 GPIO3_D[7]/SMC_ADDR[9]/HOST_DATA[9], E18 GPIO3_D[3]/HOST_RDN, F14 GPIO3_D[0]/SMC_ADDR[18]/HOST_ADDR0, F17 GPIO3_A[6]/SMC_ADDR[14]/HOST_DATA[14], R19 GPIO3_D[6]/SMC_ADDR[8]/HOST_DATA[8], W17 GPIO1_A[1]/SMC_CSN0, W18 GPIO5_C[4]/EBC_SDDO[4]/SMC_DATA[4], W19 GPIO5_D[1]/EBC_SDCLK/SMC_ADDR[6]/HOST_DATA[6], Y17 GPIO0_B[5]/EBC_VCOM/SMC_BLSN0, Y18 GPIO5_C[0]/EBC_SDDO[0]/SMC_DATA[0], Y19 GPIO5_D[0]/EBC_SDLE/SMC_ADDR[5]/HOST_DATA[5], Y20 GPIO0_C[4]/EBC_GDPWR2/SMC_DATA[12], Y21 GPIO1_A[2]/SMC_CSN1, Y22 GPIO3_D[5]/SMC_ADDR[7]/HOST_DATA[7]
part D pins: B11 GPIO4_A[6]/HOST20_DRV_VBUS, G1 XOUT24M, G2 XIN24M, G17 GPIO4_A[5]/OTG_DRV_VBUS, H1 XOUT27M, H2 XIN27M, K6 NPOR, P22 RTCINT_OUT, P23 XOUT32K, P24 XIN32K, R23 HOST11_DM, R24 HOST11_DP, T20 HOST20_ID, T23 HOST20_DM, T24 HOST20_DP, U22 HOST20_VBUS, U24 HOST20_RKELVIN, V20 OTG_ID, V23 OTG_DM, V24 OTG_DP, W22 OTG_VBUS, W24 OTG_RKELVIN
part E pins: A9 GPIO1_A[5]/EMMC_PWR_EN/PWM3, D23 GPIO3_B[7]/EMMC_DATA5, E22 GPIO3_B[0]/EMMC_CLKOUT, F21 GPIO3_C[0]/EMMC_DATA6, F22 GPIO3_B[2]/EMMC_DATA0, F23 GPIO3_B[4]/EMMC_DATA2, F24 GPIO3_B[5]/EMMC_DATA3, G21 GPIO3_C[1]/EMMC_DATA7, G23 GPIO3_B[6]/EMMC_DATA4, H21 GPIO3_B[1]/EMMC_CMD, H24 GPIO3_B[3]/EMMC_DATA1, J19 GPIO0_D[6]/FLASH_CSN5, J20 GPIO1_A[0]/FLASH_CSN7/MDDR_TQ, J21 GPIO0_A[5]/FLASH_DQS, J22 GPIO0_D[5]/FLASH_CSN4, J23 GPIO4_B[2]/FLASH_DATA[10], J24 GPIO4_B[3]/FLASH_DATA[11], K19 FLASH_WP, K20 FLASH_WRN, K21 GPIO4_B[6]/FLASH_DATA[14], K22 GPIO0_D[3]/FLASH_CSN2, K23 GPIO0_D[4]/FLASH_CSN3, K24 GPIO0_D[2]/FLASH_CSN1, L19 FLASH_DATA[6], L20 GPIO4_B[0]/FLASH_DATA[8], L21 FLASH_DATA[7], L22 FLASH_DATA[2], L23 FLASH_DATA[3], L24 GPIO0_D[7]/FLASH_CSN6, M19 GPIO4_B[7]/FLASH_DATA[15], M20 GPIO4_B[5]/FLASH_DATA[13], M21 FLASH_CLE, M22 GPIO4_B[1]/FLASH_DATA[9], M23 FLASH_DATA[5], M24 FLASH_CSN0, N19 FLASH_DATA[1], N20 FLASH_RDY, N21 FLASH_RDN, N22 GPIO4_B[4]/FLASH_DATA[12], N23 FLASH_DATA[0], N24 FLASH_DATA[4], P19 FLASH_ALE
part F pins: A6 GPIO5_D[6]/SDMMC1_PWR_EN, A7 GPIO5_D[5]/SDMMC0_PWR_EN, B10 GPIO2_A[2]/SDMMC0_DETECT_N, B24 GPIO1_D[4]/SDMMC0_DATA2, C22 GPIO2_A[0]/SDMMC0_DATA6, C23 GPIO1_D[6]/SDMMC0_DATA4, D20 GPIO1_D[2]/SDMMC0_DATA0, D22 GPIO1_D[0]/SDMMC0_CLKOUT, D24 GPIO1_C[2]/SDMMC1_CMD, E20 GPIO1_D[7]/SDMMC0_DATA5, E23 GPIO2_A[1]/SDMMC0_DATA7, G19 GPIO1_D[5]/SDMMC0_DATA3, G20 GPIO1_D[1]/SDMMC0_CMD, G22 GPIO1_D[3]/SDMMC0_DATA1, G24 GPIO1_C[7]/SDMMC1_CLKOUT, H18 GPIO1_C[5]/SDMMC1_DATA2, H19 GPIO1_C[6]/SDMMC1_DATA3, H22 GPIO1_C[3]/SDMMC1_DATA0, H23 GPIO1_C[4]/SDMMC1_DATA1
part G pins: A18 GPIO4_C[5]/RMII_CRS_DVALID/MII_RXD_VALID, A20 GPIO4_C[0]/RMII_CLKOUT/RMII_CLKIN, A22 GPIO4_C[1]/RMII_TX_EN/MII_TX_EN, B18 GPIO5_A[3]/MII_TX_CLKIN, B23 GPIO4_C[6]/RMII_RXD1/MII_RXD1, C18 GPIO4_C[4]/RMII_RX_ERR/MII_RX_ERR, C19 GPIO4_C[2]/RMII_TXD1/MII_TXD1, D11 GPIO0_A[7]/MII_MDCLK, D18 GPIO0_A[6]/MII_MD, D21 GPIO4_C[3]/RMII_TXD0/MII_TXD0, E19 GPIO4_C[7]/RMII_RXD0/MII_RXD0, K5 TRST_N, L5 TCK, L6 TDI, M6 TMS, M7 TDO
part H pins: A17 GPIO5_B[3]/HSADC_DATA6, A19 GPIO5_A[7]/HSADC_DATA2, B17 GPIO5_B[2]/HSADC_DATA5, B19 GPIO5_B[5]/HSADC_DATA8/TS_VALID, B20 GPIO5_A[5]/HSADC_DATA0, C13 GPIO5_B[6]/HSADC_DATA9/TS_FAIL, C16 GPIO5_A[4]/TS_SYNC, C17 GPIO5_B[4]/HSADC_DATA7, C20 GPIO5_B[1]/HSADC_DATA4, E21 GPIO5_B[0]/HSADC_DATA3, F18 GPIO5_A[6]/HSADC_DATA1, F19 GPIO5_B[7]/HSADC_CLKOUT/GPS_CLK
part I pins: A3 GPIO1_C[0]/UART0_CTS_N/SDMMC1_DETECT_N, A4 GPIO3_A[5]/I2S1_LRCK_TX, A5 GPIO3_A[4]/I2S1_SDO, A8 GPIO2_B[2]/UART3_SIN, A10 GPIO1_A[4]/EMMC_WRITE_PRT/SPI0_CSN1, A12 GPIO1_A[6]/I2C1_SDA, A13 GPIO2_C[5]/SPI1_CSN0, A21 GPIO2_D[2]/I2S0_LRCK_RX/MII_TX_ERR, A23 GPIO2_D[5]/I2S0_SDO1/MII_RXD3, A24 GPIO2_D[6]/I2S0_SDO2/MII_TXD2, B4 GPIO2_A[7]/UART2_RTS_N, B5 GPIO3_A[3]/I2S1_SDI, B6 GPIO3_A[1]/I2S1_SCLK, B8 GPIO5_D[3]/I2C2_SDA, B12 GPIO1_A[7]/I2C1_SCL, B16 GPIO2_C[6]/SPI1_TXD, B21 GPIO4_D[7]/I2S0_LRCK_TX1, B22 GPIO2_D[3]/I2S0_SDI/MII_COL, C4 GPIO1_C[1]/UART0_RTS_N/SDMMC1_WRITE_PRT, C5 GPIO2_A[6]/UART2_CTS_N, C6 GPIO3_A[2]/I2S1_LRCK_RX, C7 GPIO2_A[4]/UART1_SIN, C9 GPIO2_B[6]/I2C0_SDA, C14 GPIO2_C[7]/SPI1_RXD, C15 GPIO4_A[7]/SPDIF_TX, C21 GPIO2_D[4]/I2S0_SDO0/MII_RXD2, C24 GPIO2_D[7]/I2S0_SDO3/MII_TXD3, D5 GPIO1_B[7]/UART0_SOUT, D6 GPIO2_B[4]/UART3_CTS_N/I2C3_SDA, D7 GPIO3_A[0]/I2S1_CLK, D8 GPIO1_B[6]/UART0_SIN, D9 GPIO5_D[4]/I2C2_SCL, D10 GPIO2_B[7]/I2C0_SCL, D14 GPIO2_C[0]/SPI0_CLK, D15 GPIO2_C[3]/SPI0_RXD, E6 GPIO2_B[0]/UART2_SIN, E7 GPIO2_B[5]/UART3_RTS_N/I2C3_SCL, E8 GPIO2_B[1]/UART2_SOUT, E9 GPIO2_A[5]/UART1_SOUT, E14 GPIO2_C[1]/SPI0_CSN0, E15 GPIO2_C[2]/SPI0_TXD, E24 GPIO2_D[0]/I2S0_CLK/MII_RX_CLKIN, F8 GPIO2_B[3]/UART3_SOUT, F15 GPIO1_A[3]/EMMC_DETECT_N/SPI1_CSN1, F16 GPIO2_C[4]/SPI1_CLK, F20 GPIO4_D[6]/I2S0_LRCK_TX0, H20 GPIO2_D[1]/I2S0_SCLK/MII_CRS
part J pins: A1 GPIO6_A[0], A2 GPIO6_B[7], A11 GPIO6_C[2], AA23 SARADC_AIN[0], AA24 SARADC_AIN[3], B1 GPIO6_B[6], B2 GPIO6_B[5], B3 GPIO6_A[1], B7 GPIO5_D[2]/PWM1/UART1_SIR_IN, B9 GPIO2_A[3]/SDMMC0_WRITE_PRT/PWM2/UART1_SIR_OUT, C1 GPIO6_A[5], C2 GPIO6_B[4], C3 GPIO6_A[2], C8 GPIO1_B[5]/PWM0, C10 GPIO4_D[4], C11 GPIO6_C[6], C12 GPIO6_C[0], D1 GPIO6_A[6], D2 GPIO6_A[7], D3 GPIO6_B[3], D4 GPIO6_A[3], D12 GPIO4_D[0], D13 GPIO6_C[3], E1 GPIO6_B[0], E2 GPIO5_A[0], E3 GPIO6_B[2], E4 GPIO5_A[2], E5 GPIO6_A[4], E10 GPIO6_C[5], E11 GPIO4_D[1], E12 GPIO6_C[1], E13 GPIO6_C[7], F1 GPIO6_B[1], F2 GPIO0_A[1], F3 GPIO5_A[1], F4 GPIO0_A[0], F9 GPIO4_D[3], F10 GPIO4_D[2], F11 GPIO4_D[5], F12 GPIO5_D[7], F13 GPIO6_C[4], G3 GPIO0_A[2], G4 GPIO0_A[4], H3 GPIO0_A[3], H4 GPIO4_A[3], J1 GPIO4_A[0], J2 GPIO4_A[1], J3 GPIO4_A[2], J4 GPIO4_A[4], N6 BTMODE, P7 EWAKEUP_STOP, P20 VDDCORE_EFUSE, R20 EFUSE_VQPS, T7 EWAKEUP_POWER, T19 VDDIO_EFUSE, V7 TEST, V8 GPIO6_D[2], V9 GPIO6_D[0], W7 GPIO6_D[3], W8 GPIO6_D[1], Y23 SARADC_AIN[1], Y24 SARADC_AIN[2]
part K pins: AB24 VDDA_SARADC, F5 AVDD_DPLL, F6 AHVDD_APLL, F7 AHVSS_APLL, G5 DVDD_APLL, G6 AVSS_DPLL, G7 DVSS_APLL, G8 VDDIO_AP1, G9 VDDIO_AP0, G10 VDDCORE, G11 VDDIO6, G12 VDDCORE, G13 VDDIO5, G14 VDDCORE, G15 VDDIO4, G16 VDDCORE, G18 VDDIO3, H5 DVDD_DPLL, H6 DVSS_DPLL, H7 DVSS_CGPLL, J5 AVDD_CGPLL, J6 DVDD_CGPLL, J7 AVSS_CGPLL, J18 VDDCORE, K7 VDDIO0, K10 GND, K11 GND, K12 GND, K13 GND, K14 GND, K15 GND, K18 VDDIO2, L7 VDDCORE, L10 GND, L11 GND, L12 GND, L13 GND, L14 GND, L15 GND, L18 VDDCORE, M5 VSSIO_DDR0, M10 GND, M11 GND, M12 GND, M13 GND, M14 GND, M15 GND, M18 VDDIO_FLASH1, N5 VDDIO_DDR0, N7 VDDCORE, N10 GND, N11 GND, N12 GND, N13 GND, N14 GND, N15 GND, N18 VDDCORE, P5 VSSIO_DDR1, P10 GND, P11 GND, P12 GND, P13 GND, P14 GND, P15 GND, P18 VDDIO_FLASH0, P21 VDDIO_RTC, R5 VDDIO_DDR1, R7 VDDCORE, R10 GND, R11 GND, R12 GND, R13 GND, R14 GND, R15 GND, R18 VDDCORE, R21 VSSIO_UHOST11, R22 VDDIO_UHOST11, T5 VSSIO_DDR2, T18 VDDIO1, T21 HOST20_VSSA, T22 HOST_VDD25, U5 VDDIO_DDR2, U7 VDDCORE, U18 VDDCORE_RTC, U19 HOST20_DVDD, U20 HOST20_VSSAC, U21 HOST20_DVSS, U23 HOST20_VDD33, V5 VSSIO_DDR3, V10 VDDCORE, V11 VDDIO_LCD0, V12 VDDCORE, V13 VDDIO_LCD1, V14 VDDCORE, V15 VDDIO_VIP, V16 VDDCORE, V17 VDDIO_SMC0, V18 VDDIO_SMC1, V19 OTG_DVDD, V21 OTG_VSSA, V22 OTG_VDD25, W5 VDDIO_DDR3, W20 OTG_VSSAC, W21 OTG_DVSS, W23 OTG_VDD33, Y5 VSSIO_DDR4, Y6 VDDIO_DDR4, Y7 VSSIO_DDR5, Y8 VDDIO_DDR5, Y9 VSSIO_DDR6, Y10 VDDIO_DDR6
part L pins: AA1 WE_B, AA2 CAS_B, AA3 ODT1, AA4 NC3, AA5 DLL_TEST_PIN[0], AA6 DQ12, AA7 DQ13, AA8 NC4, AA9 DQ28, AA10 DQ27, AB1 A10, AB2 RAS_B, AB3 NC2, AB4 A14, AB5 DQ9, AB6 DQ10, AB7 DM3, AB8 NC5, AB9 DQ26, AB10 DQ30, AC1 A8, AC2 A13, AC3 A7, AC4 DQ8, AC5 DM1, AC6 DQS1#, AC7 DQ14, AC8 DQ24, AC9 DQS3#, AC10 DQ29, AD1 A11, AD2 A15, AD3 A9, AD4 A12, AD5 DQ11, AD6 DQS1, AD7 DQ15, AD8 DQ25, AD9 DQS3, AD10 DQ31, K1 DQ3, K2 DQ2, K3 DQ1, K4 DQ0, L1 DQS0, L2 DQS0#, L3 DQ5, L4 DQ4, M1 DQ7, M2 DQ6, M3 DQ17, M4 DM0, N1 DQ19, N2 DQ18, N3 DM2, N4 DQ16, P1 DQS2, P2 DQS2#, P3 DQ21, P4 DQ20, P6 VREF0, R1 DQ23, R2 DQ22, R3 BA0, R4 ZQ_PIN, T1 A1, T2 A0, T3 BA1, T4 BA2, T6 ANALOG_TEST_PIN, U1 A2, U2 A3, U3 NC0, U4 NC1, U6 VREF1, V1 A6, V2 CS_B0, V3 A4, V4 A5, V6 RESET, W1 CS_B1, W2 ODT0, W3 CKE1, W4 RET_EN, W6 VREF2, W9 NC6, Y1 CK, Y2 CK#, Y3 CKE0, Y4 DLL_TEST_PIN[1]




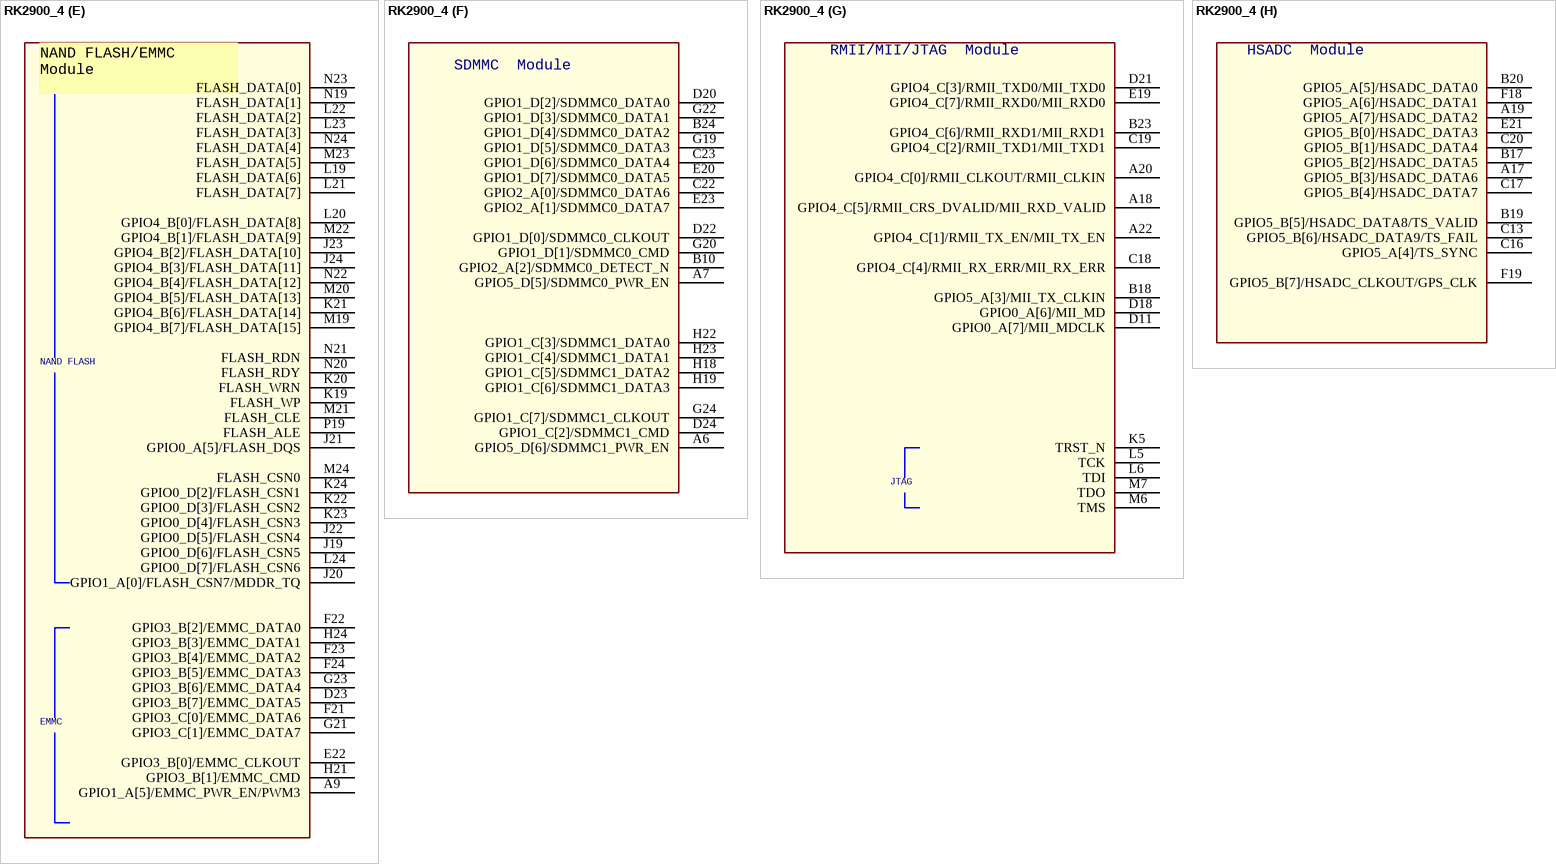
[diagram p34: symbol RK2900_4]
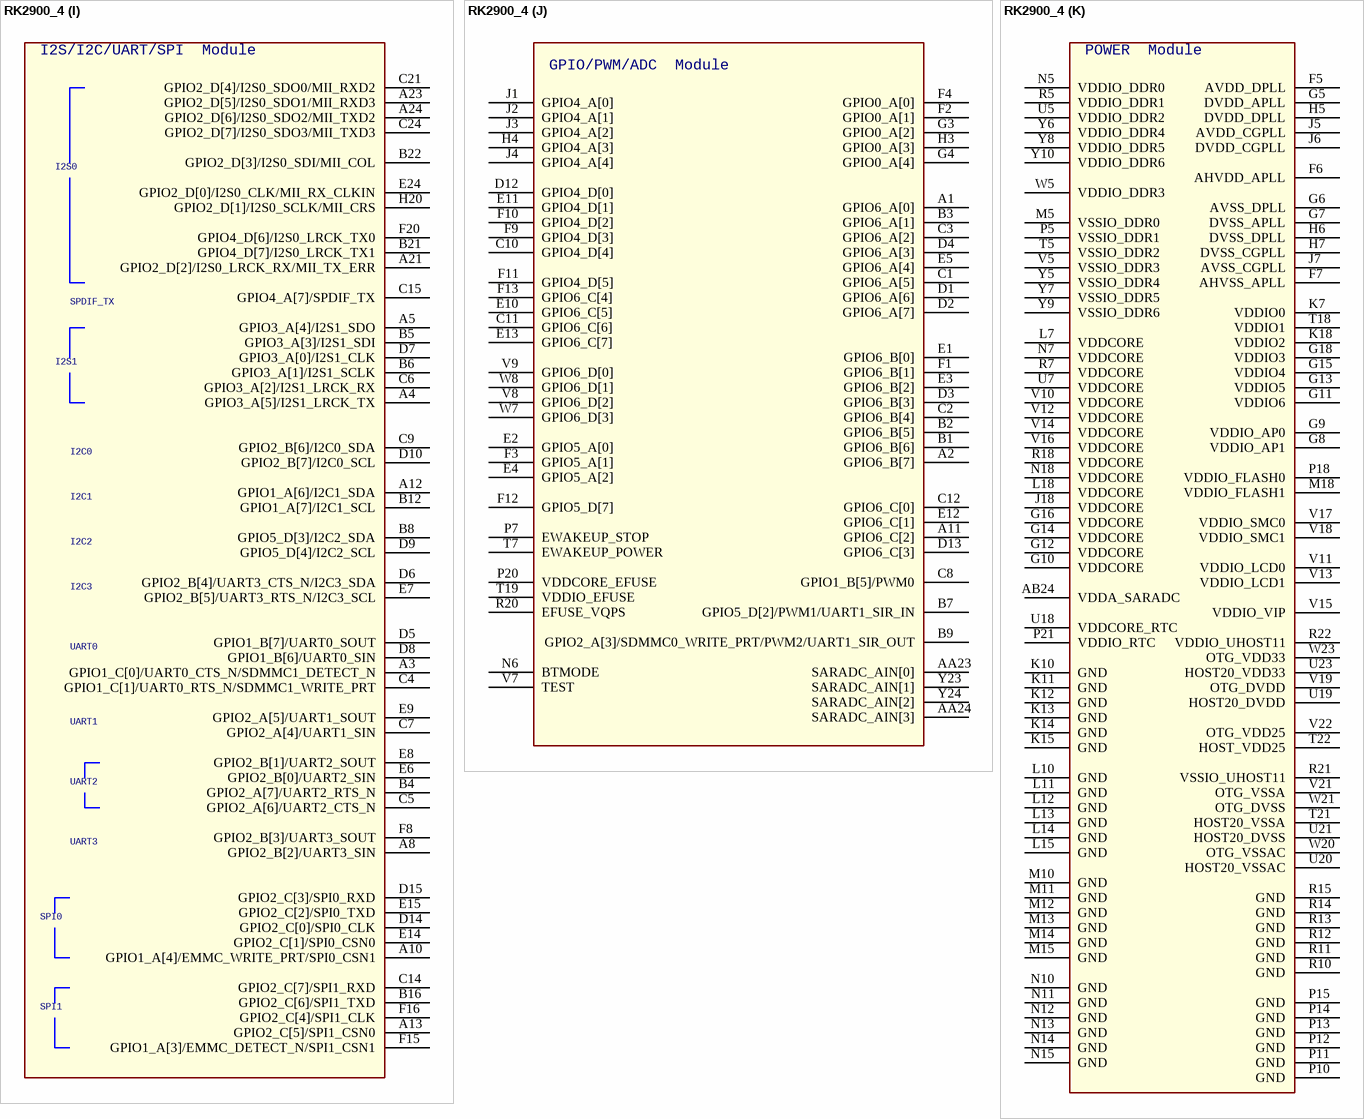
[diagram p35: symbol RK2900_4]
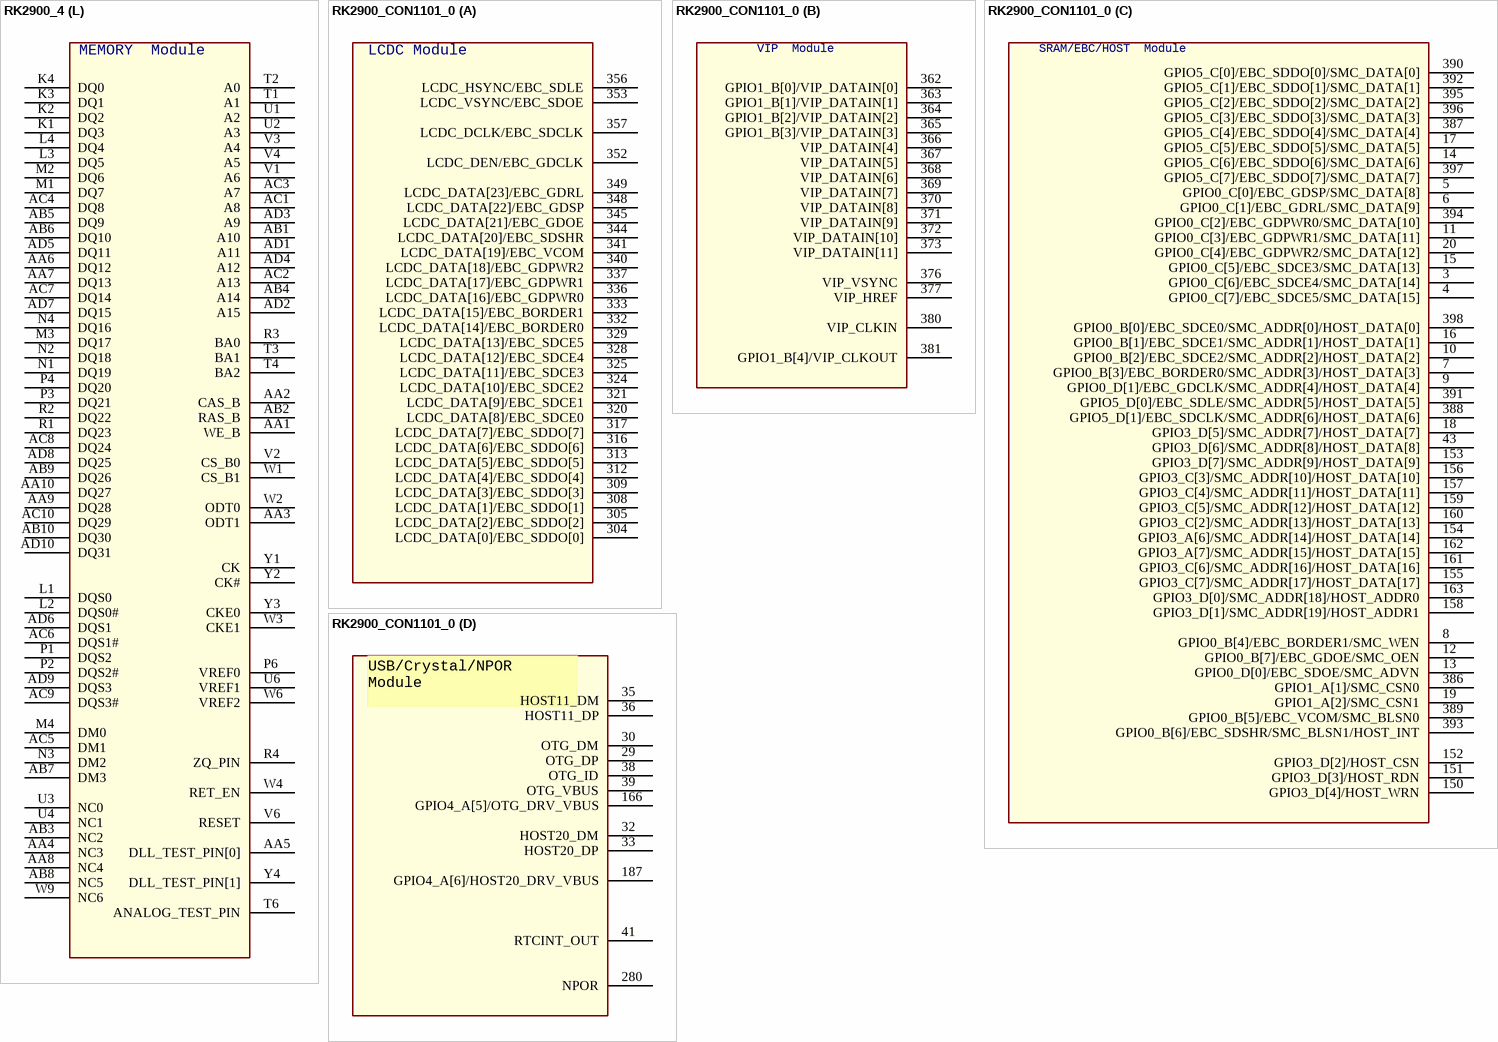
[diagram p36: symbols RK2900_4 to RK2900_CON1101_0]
## RK2900_4
designator U?
footprint BGA512
part A pins: AA11 LCDC_DATA[20]/EBC_SDSHR, AA12 LCDC_DCLK/EBC_SDCLK, AA13 LCDC_DATA[10]/EBC_SDCE2, AA14 LCDC_DATA[14]/EBC_BORDER0, AB11 LCDC_DATA[5]/EBC_SDDO[5], AB12 LCDC_DATA[3]/EBC_SDDO[3], AB13 LCDC_VSYNC/EBC_SDOE, AB14 LCDC_DATA[11]/EBC_SDCE3, AB15 LCDC_DATA[15]/EBC_BORDER1, AC11 LCDC_DATA[1]/EBC_SDDO[1], AC12 LCDC_DATA[2]/EBC_SDDO[2], AC13 LCDC_DATA[7]/EBC_SDDO[7], AC14 LCDC_DATA[12]/EBC_SDCE4, AC15 LCDC_DATA[16]/EBC_GDPWR0, AD11 LCDC_DATA[4]/EBC_SDDO[4], AD12 LCDC_DATA[6]/EBC_SDDO[6], AD13 LCDC_DATA[8]/EBC_SDCE0, AD14 LCDC_DATA[13]/EBC_SDCE5, AD15 LCDC_DATA[17]/EBC_GDPWR1, R6 LCDC_BYP, W10 LCDC_DATA[0]/EBC_SDDO[0], W11 LCDC_HSYNC/EBC_SDLE, W12 LCDC_DATA[23]/EBC_GDRL, W13 LCDC_DATA[22]/EBC_GDSP, W14 LCDC_DATA[21]/EBC_GDOE, Y11 LCDC_DATA[18]/EBC_GDPWR2, Y12 LCDC_DATA[9]/EBC_SDCE1, Y13 LCDC_DATA[19]/EBC_VCOM, Y14 LCDC_DEN/EBC_GDCLK
part B pins: AA15 VIP_DATAIN[10], AA16 GPIO1_B[0]/VIP_DATAIN[0], AA17 GPIO1_B[1]/VIP_DATAIN[1], AB16 VIP_DATAIN[5], AB17 VIP_DATAIN[8], AB18 VIP_VSYNC, AC16 VIP_DATAIN[6], AC17 VIP_HREF, AC18 GPIO1_B[3]/VIP_DATAIN[3], AD16 VIP_DATAIN[9], AD17 VIP_CLKIN, AD18 GPIO1_B[2]/VIP_DATAIN[2], W15 VIP_DATAIN[4], W16 GPIO1_B[4]/VIP_CLKOUT, Y15 VIP_DATAIN[11], Y16 VIP_DATAIN[7]
part C pins: A14 GPIO3_C[2]/SMC_ADDR[13]/HOST_DATA[13], A15 GPIO3_D[1]/SMC_ADDR[19]/HOST_ADDR1, A16 GPIO3_C[4]/SMC_ADDR[11]/HOST_DATA[11], AA18 GPIO5_C[1]/EBC_SDDO[1]/SMC_DATA[1], AA19 GPIO0_B[6]/EBC_SDSHR/SMC_BLSN1/HOST_INT, AA20 GPIO5_C[5]/EBC_SDDO[5]/SMC_DATA[5], AA21 GPIO0_B[1]/EBC_SDCE1/SMC_ADDR[1]/HOST_DATA[1], AA22 GPIO0_C[5]/EBC_SDCE3/SMC_DATA[13], AB19 GPIO0_C[2]/EBC_GDPWR0/SMC_DATA[10], AB20 GPIO5_C[6]/EBC_SDDO[6]/SMC_DATA[6], AB21 GPIO0_D[0]/EBC_SDOE/SMC_ADVN, AB22 GPIO0_B[7]/EBC_GDOE/SMC_OEN, AB23 GPIO0_C[3]/EBC_GDPWR1/SMC_DATA[11], AC19 GPIO5_C[2]/EBC_SDDO[2]/SMC_DATA[2], AC20 GPIO5_C[7]/EBC_SDDO[7]/SMC_DATA[7], AC21 GPIO0_D[1]/EBC_GDCLK/SMC_ADDR[4]/HOST_DATA[4], AC22 GPIO0_B[3]/EBC_BORDER0/SMC_ADDR[3]/HOST_DATA[3], AC23 GPIO0_C[0]/EBC_GDSP/SMC_DATA[8], AC24 GPIO0_C[6]/EBC_SDCE4/SMC_DATA[14], AD19 GPIO5_C[3]/EBC_SDDO[3]/SMC_DATA[3], AD20 GPIO0_B[0]/EBC_SDCE0/SMC_ADDR[0]/HOST_DATA[0], AD21 GPIO0_B[2]/EBC_SDCE2/SMC_ADDR[2]/HOST_DATA[2], AD22 GPIO0_B[4]/EBC_BORDER1/SMC_WEN, AD23 GPIO0_C[1]/EBC_GDRL/SMC_DATA[9], AD24 GPIO0_C[7]/EBC_SDCE5/SMC_DATA[15], B13 GPIO3_A[7]/SMC_ADDR[15]/HOST_DATA[15], B14 GPIO3_C[6]/SMC_ADDR[16]/HOST_DATA[16], B15 GPIO3_C[5]/SMC_ADDR[12]/HOST_DATA[12], D16 GPIO3_C[7]/SMC_ADDR[17]/HOST_DATA[17], D17 GPIO3_D[2]/HOST_CSN, D19 GPIO3_D[4]/HOST_WRN, E16 GPIO3_C[3]/SMC_ADDR[10]/HOST_DATA[10], E17 GPIO3_D[7]/SMC_ADDR[9]/HOST_DATA[9], E18 GPIO3_D[3]/HOST_RDN, F14 GPIO3_D[0]/SMC_ADDR[18]/HOST_ADDR0, F17 GPIO3_A[6]/SMC_ADDR[14]/HOST_DATA[14], R19 GPIO3_D[6]/SMC_ADDR[8]/HOST_DATA[8], W17 GPIO1_A[1]/SMC_CSN0, W18 GPIO5_C[4]/EBC_SDDO[4]/SMC_DATA[4], W19 GPIO5_D[1]/EBC_SDCLK/SMC_ADDR[6]/HOST_DATA[6], Y17 GPIO0_B[5]/EBC_VCOM/SMC_BLSN0, Y18 GPIO5_C[0]/EBC_SDDO[0]/SMC_DATA[0], Y19 GPIO5_D[0]/EBC_SDLE/SMC_ADDR[5]/HOST_DATA[5], Y20 GPIO0_C[4]/EBC_GDPWR2/SMC_DATA[12], Y21 GPIO1_A[2]/SMC_CSN1, Y22 GPIO3_D[5]/SMC_ADDR[7]/HOST_DATA[7]
part D pins: B11 GPIO4_A[6]/HOST20_DRV_VBUS, G1 XOUT24M, G2 XIN24M, G17 GPIO4_A[5]/OTG_DRV_VBUS, H1 XOUT27M, H2 XIN27M, K6 NPOR, P22 RTCINT_OUT, P23 XOUT32K, P24 XIN32K, R23 HOST11_DM, R24 HOST11_DP, T20 HOST20_ID, T23 HOST20_DM, T24 HOST20_DP, U22 HOST20_VBUS, U24 HOST20_RKELVIN, V20 OTG_ID, V23 OTG_DM, V24 OTG_DP, W22 OTG_VBUS, W24 OTG_RKELVIN
part E pins: A9 GPIO1_A[5]/EMMC_PWR_EN/PWM3, D23 GPIO3_B[7]/EMMC_DATA5, E22 GPIO3_B[0]/EMMC_CLKOUT, F21 GPIO3_C[0]/EMMC_DATA6, F22 GPIO3_B[2]/EMMC_DATA0, F23 GPIO3_B[4]/EMMC_DATA2, F24 GPIO3_B[5]/EMMC_DATA3, G21 GPIO3_C[1]/EMMC_DATA7, G23 GPIO3_B[6]/EMMC_DATA4, H21 GPIO3_B[1]/EMMC_CMD, H24 GPIO3_B[3]/EMMC_DATA1, J19 GPIO0_D[6]/FLASH_CSN5, J20 GPIO1_A[0]/FLASH_CSN7/MDDR_TQ, J21 GPIO0_A[5]/FLASH_DQS, J22 GPIO0_D[5]/FLASH_CSN4, J23 GPIO4_B[2]/FLASH_DATA[10], J24 GPIO4_B[3]/FLASH_DATA[11], K19 FLASH_WP, K20 FLASH_WRN, K21 GPIO4_B[6]/FLASH_DATA[14], K22 GPIO0_D[3]/FLASH_CSN2, K23 GPIO0_D[4]/FLASH_CSN3, K24 GPIO0_D[2]/FLASH_CSN1, L19 FLASH_DATA[6], L20 GPIO4_B[0]/FLASH_DATA[8], L21 FLASH_DATA[7], L22 FLASH_DATA[2], L23 FLASH_DATA[3], L24 GPIO0_D[7]/FLASH_CSN6, M19 GPIO4_B[7]/FLASH_DATA[15], M20 GPIO4_B[5]/FLASH_DATA[13], M21 FLASH_CLE, M22 GPIO4_B[1]/FLASH_DATA[9], M23 FLASH_DATA[5], M24 FLASH_CSN0, N19 FLASH_DATA[1], N20 FLASH_RDY, N21 FLASH_RDN, N22 GPIO4_B[4]/FLASH_DATA[12], N23 FLASH_DATA[0], N24 FLASH_DATA[4], P19 FLASH_ALE
part F pins: A6 GPIO5_D[6]/SDMMC1_PWR_EN, A7 GPIO5_D[5]/SDMMC0_PWR_EN, B10 GPIO2_A[2]/SDMMC0_DETECT_N, B24 GPIO1_D[4]/SDMMC0_DATA2, C22 GPIO2_A[0]/SDMMC0_DATA6, C23 GPIO1_D[6]/SDMMC0_DATA4, D20 GPIO1_D[2]/SDMMC0_DATA0, D22 GPIO1_D[0]/SDMMC0_CLKOUT, D24 GPIO1_C[2]/SDMMC1_CMD, E20 GPIO1_D[7]/SDMMC0_DATA5, E23 GPIO2_A[1]/SDMMC0_DATA7, G19 GPIO1_D[5]/SDMMC0_DATA3, G20 GPIO1_D[1]/SDMMC0_CMD, G22 GPIO1_D[3]/SDMMC0_DATA1, G24 GPIO1_C[7]/SDMMC1_CLKOUT, H18 GPIO1_C[5]/SDMMC1_DATA2, H19 GPIO1_C[6]/SDMMC1_DATA3, H22 GPIO1_C[3]/SDMMC1_DATA0, H23 GPIO1_C[4]/SDMMC1_DATA1
part G pins: A18 GPIO4_C[5]/RMII_CRS_DVALID/MII_RXD_VALID, A20 GPIO4_C[0]/RMII_CLKOUT/RMII_CLKIN, A22 GPIO4_C[1]/RMII_TX_EN/MII_TX_EN, B18 GPIO5_A[3]/MII_TX_CLKIN, B23 GPIO4_C[6]/RMII_RXD1/MII_RXD1, C18 GPIO4_C[4]/RMII_RX_ERR/MII_RX_ERR, C19 GPIO4_C[2]/RMII_TXD1/MII_TXD1, D11 GPIO0_A[7]/MII_MDCLK, D18 GPIO0_A[6]/MII_MD, D21 GPIO4_C[3]/RMII_TXD0/MII_TXD0, E19 GPIO4_C[7]/RMII_RXD0/MII_RXD0, K5 TRST_N, L5 TCK, L6 TDI, M6 TMS, M7 TDO
part H pins: A17 GPIO5_B[3]/HSADC_DATA6, A19 GPIO5_A[7]/HSADC_DATA2, B17 GPIO5_B[2]/HSADC_DATA5, B19 GPIO5_B[5]/HSADC_DATA8/TS_VALID, B20 GPIO5_A[5]/HSADC_DATA0, C13 GPIO5_B[6]/HSADC_DATA9/TS_FAIL, C16 GPIO5_A[4]/TS_SYNC, C17 GPIO5_B[4]/HSADC_DATA7, C20 GPIO5_B[1]/HSADC_DATA4, E21 GPIO5_B[0]/HSADC_DATA3, F18 GPIO5_A[6]/HSADC_DATA1, F19 GPIO5_B[7]/HSADC_CLKOUT/GPS_CLK
part I pins: A3 GPIO1_C[0]/UART0_CTS_N/SDMMC1_DETECT_N, A4 GPIO3_A[5]/I2S1_LRCK_TX, A5 GPIO3_A[4]/I2S1_SDO, A8 GPIO2_B[2]/UART3_SIN, A10 GPIO1_A[4]/EMMC_WRITE_PRT/SPI0_CSN1, A12 GPIO1_A[6]/I2C1_SDA, A13 GPIO2_C[5]/SPI1_CSN0, A21 GPIO2_D[2]/I2S0_LRCK_RX/MII_TX_ERR, A23 GPIO2_D[5]/I2S0_SDO1/MII_RXD3, A24 GPIO2_D[6]/I2S0_SDO2/MII_TXD2, B4 GPIO2_A[7]/UART2_RTS_N, B5 GPIO3_A[3]/I2S1_SDI, B6 GPIO3_A[1]/I2S1_SCLK, B8 GPIO5_D[3]/I2C2_SDA, B12 GPIO1_A[7]/I2C1_SCL, B16 GPIO2_C[6]/SPI1_TXD, B21 GPIO4_D[7]/I2S0_LRCK_TX1, B22 GPIO2_D[3]/I2S0_SDI/MII_COL, C4 GPIO1_C[1]/UART0_RTS_N/SDMMC1_WRITE_PRT, C5 GPIO2_A[6]/UART2_CTS_N, C6 GPIO3_A[2]/I2S1_LRCK_RX, C7 GPIO2_A[4]/UART1_SIN, C9 GPIO2_B[6]/I2C0_SDA, C14 GPIO2_C[7]/SPI1_RXD, C15 GPIO4_A[7]/SPDIF_TX, C21 GPIO2_D[4]/I2S0_SDO0/MII_RXD2, C24 GPIO2_D[7]/I2S0_SDO3/MII_TXD3, D5 GPIO1_B[7]/UART0_SOUT, D6 GPIO2_B[4]/UART3_CTS_N/I2C3_SDA, D7 GPIO3_A[0]/I2S1_CLK, D8 GPIO1_B[6]/UART0_SIN, D9 GPIO5_D[4]/I2C2_SCL, D10 GPIO2_B[7]/I2C0_SCL, D14 GPIO2_C[0]/SPI0_CLK, D15 GPIO2_C[3]/SPI0_RXD, E6 GPIO2_B[0]/UART2_SIN, E7 GPIO2_B[5]/UART3_RTS_N/I2C3_SCL, E8 GPIO2_B[1]/UART2_SOUT, E9 GPIO2_A[5]/UART1_SOUT, E14 GPIO2_C[1]/SPI0_CSN0, E15 GPIO2_C[2]/SPI0_TXD, E24 GPIO2_D[0]/I2S0_CLK/MII_RX_CLKIN, F8 GPIO2_B[3]/UART3_SOUT, F15 GPIO1_A[3]/EMMC_DETECT_N/SPI1_CSN1, F16 GPIO2_C[4]/SPI1_CLK, F20 GPIO4_D[6]/I2S0_LRCK_TX0, H20 GPIO2_D[1]/I2S0_SCLK/MII_CRS
part J pins: A1 GPIO6_A[0], A2 GPIO6_B[7], A11 GPIO6_C[2], AA23 SARADC_AIN[0], AA24 SARADC_AIN[3], B1 GPIO6_B[6], B2 GPIO6_B[5], B3 GPIO6_A[1], B7 GPIO5_D[2]/PWM1/UART1_SIR_IN, B9 GPIO2_A[3]/SDMMC0_WRITE_PRT/PWM2/UART1_SIR_OUT, C1 GPIO6_A[5], C2 GPIO6_B[4], C3 GPIO6_A[2], C8 GPIO1_B[5]/PWM0, C10 GPIO4_D[4], C11 GPIO6_C[6], C12 GPIO6_C[0], D1 GPIO6_A[6], D2 GPIO6_A[7], D3 GPIO6_B[3], D4 GPIO6_A[3], D12 GPIO4_D[0], D13 GPIO6_C[3], E1 GPIO6_B[0], E2 GPIO5_A[0], E3 GPIO6_B[2], E4 GPIO5_A[2], E5 GPIO6_A[4], E10 GPIO6_C[5], E11 GPIO4_D[1], E12 GPIO6_C[1], E13 GPIO6_C[7], F1 GPIO6_B[1], F2 GPIO0_A[1], F3 GPIO5_A[1], F4 GPIO0_A[0], F9 GPIO4_D[3], F10 GPIO4_D[2], F11 GPIO4_D[5], F12 GPIO5_D[7], F13 GPIO6_C[4], G3 GPIO0_A[2], G4 GPIO0_A[4], H3 GPIO0_A[3], H4 GPIO4_A[3], J1 GPIO4_A[0], J2 GPIO4_A[1], J3 GPIO4_A[2], J4 GPIO4_A[4], N6 BTMODE, P7 EWAKEUP_STOP, P20 VDDCORE_EFUSE, R20 EFUSE_VQPS, T7 EWAKEUP_POWER, T19 VDDIO_EFUSE, V7 TEST, V8 GPIO6_D[2], V9 GPIO6_D[0], W7 GPIO6_D[3], W8 GPIO6_D[1], Y23 SARADC_AIN[1], Y24 SARADC_AIN[2]
part K pins: AB24 VDDA_SARADC, F5 AVDD_DPLL, F6 AHVDD_APLL, F7 AHVSS_APLL, G5 DVDD_APLL, G6 AVSS_DPLL, G7 DVSS_APLL, G8 VDDIO_AP1, G9 VDDIO_AP0, G10 VDDCORE, G11 VDDIO6, G12 VDDCORE, G13 VDDIO5, G14 VDDCORE, G15 VDDIO4, G16 VDDCORE, G18 VDDIO3, H5 DVDD_DPLL, H6 DVSS_DPLL, H7 DVSS_CGPLL, J5 AVDD_CGPLL, J6 DVDD_CGPLL, J7 AVSS_CGPLL, J18 VDDCORE, K7 VDDIO0, K10 GND, K11 GND, K12 GND, K13 GND, K14 GND, K15 GND, K18 VDDIO2, L7 VDDCORE, L10 GND, L11 GND, L12 GND, L13 GND, L14 GND, L15 GND, L18 VDDCORE, M5 VSSIO_DDR0, M10 GND, M11 GND, M12 GND, M13 GND, M14 GND, M15 GND, M18 VDDIO_FLASH1, N5 VDDIO_DDR0, N7 VDDCORE, N10 GND, N11 GND, N12 GND, N13 GND, N14 GND, N15 GND, N18 VDDCORE, P5 VSSIO_DDR1, P10 GND, P11 GND, P12 GND, P13 GND, P14 GND, P15 GND, P18 VDDIO_FLASH0, P21 VDDIO_RTC, R5 VDDIO_DDR1, R7 VDDCORE, R10 GND, R11 GND, R12 GND, R13 GND, R14 GND, R15 GND, R18 VDDCORE, R21 VSSIO_UHOST11, R22 VDDIO_UHOST11, T5 VSSIO_DDR2, T18 VDDIO1, T21 HOST20_VSSA, T22 HOST_VDD25, U5 VDDIO_DDR2, U7 VDDCORE, U18 VDDCORE_RTC, U19 HOST20_DVDD, U20 HOST20_VSSAC, U21 HOST20_DVSS, U23 HOST20_VDD33, V5 VSSIO_DDR3, V10 VDDCORE, V11 VDDIO_LCD0, V12 VDDCORE, V13 VDDIO_LCD1, V14 VDDCORE, V15 VDDIO_VIP, V16 VDDCORE, V17 VDDIO_SMC0, V18 VDDIO_SMC1, V19 OTG_DVDD, V21 OTG_VSSA, V22 OTG_VDD25, W5 VDDIO_DDR3, W20 OTG_VSSAC, W21 OTG_DVSS, W23 OTG_VDD33, Y5 VSSIO_DDR4, Y6 VDDIO_DDR4, Y7 VSSIO_DDR5, Y8 VDDIO_DDR5, Y9 VSSIO_DDR6, Y10 VDDIO_DDR6
part L pins: AA1 WE_B, AA2 CAS_B, AA3 ODT1, AA4 NC3, AA5 DLL_TEST_PIN[0], AA6 DQ12, AA7 DQ13, AA8 NC4, AA9 DQ28, AA10 DQ27, AB1 A10, AB2 RAS_B, AB3 NC2, AB4 A14, AB5 DQ9, AB6 DQ10, AB7 DM3, AB8 NC5, AB9 DQ26, AB10 DQ30, AC1 A8, AC2 A13, AC3 A7, AC4 DQ8, AC5 DM1, AC6 DQS1#, AC7 DQ14, AC8 DQ24, AC9 DQS3#, AC10 DQ29, AD1 A11, AD2 A15, AD3 A9, AD4 A12, AD5 DQ11, AD6 DQS1, AD7 DQ15, AD8 DQ25, AD9 DQS3, AD10 DQ31, K1 DQ3, K2 DQ2, K3 DQ1, K4 DQ0, L1 DQS0, L2 DQS0#, L3 DQ5, L4 DQ4, M1 DQ7, M2 DQ6, M3 DQ17, M4 DM0, N1 DQ19, N2 DQ18, N3 DM2, N4 DQ16, P1 DQS2, P2 DQS2#, P3 DQ21, P4 DQ20, P6 VREF0, R1 DQ23, R2 DQ22, R3 BA0, R4 ZQ_PIN, T1 A1, T2 A0, T3 BA1, T4 BA2, T6 ANALOG_TEST_PIN, U1 A2, U2 A3, U3 NC0, U4 NC1, U6 VREF1, V1 A6, V2 CS_B0, V3 A4, V4 A5, V6 RESET, W1 CS_B1, W2 ODT0, W3 CKE1, W4 RET_EN, W6 VREF2, W9 NC6, Y1 CK, Y2 CK#, Y3 CKE0, Y4 DLL_TEST_PIN[1]



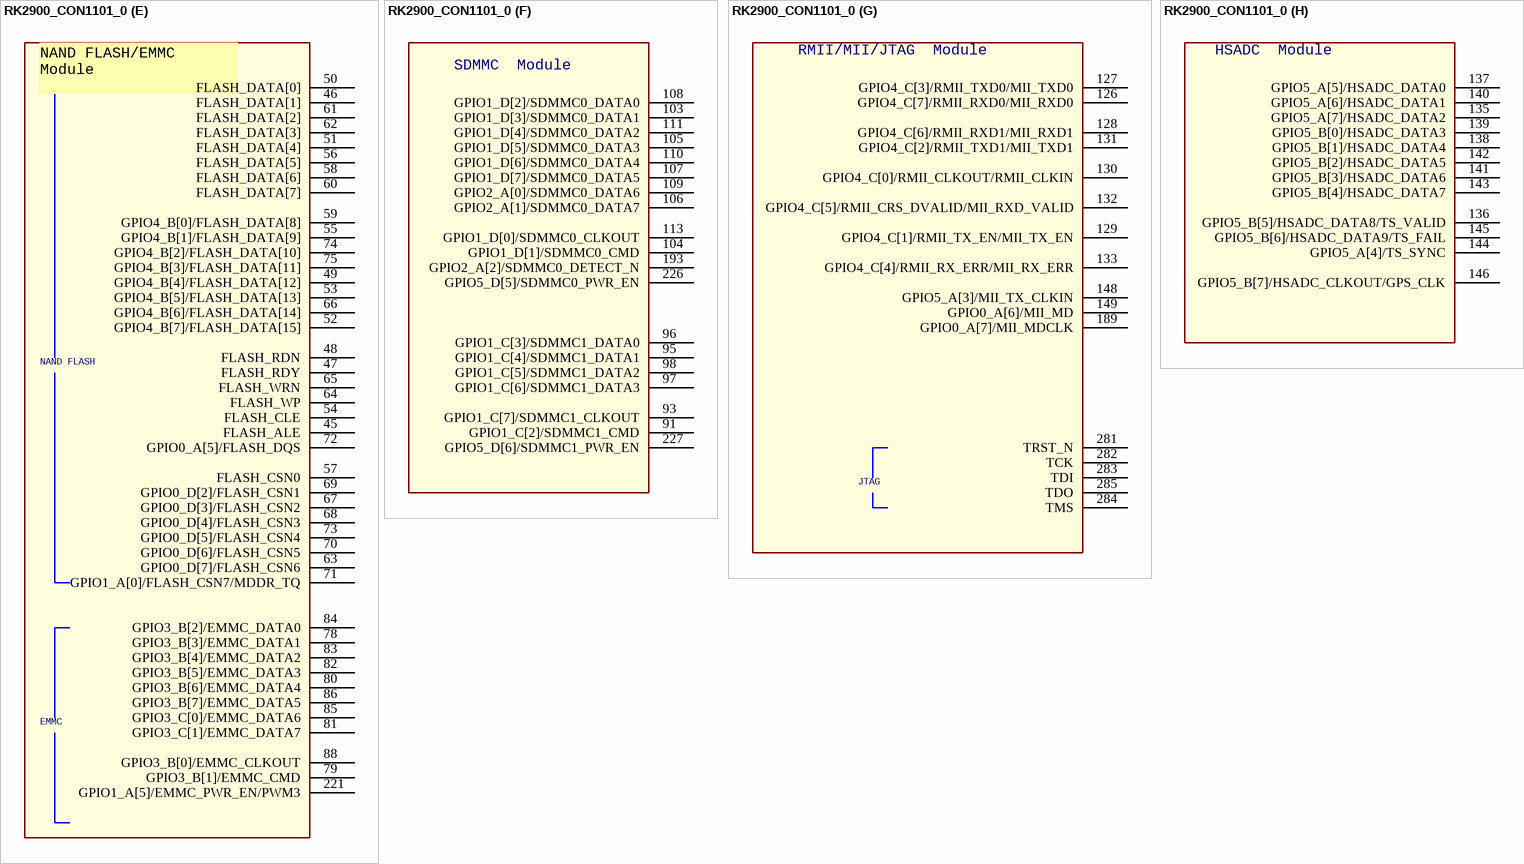
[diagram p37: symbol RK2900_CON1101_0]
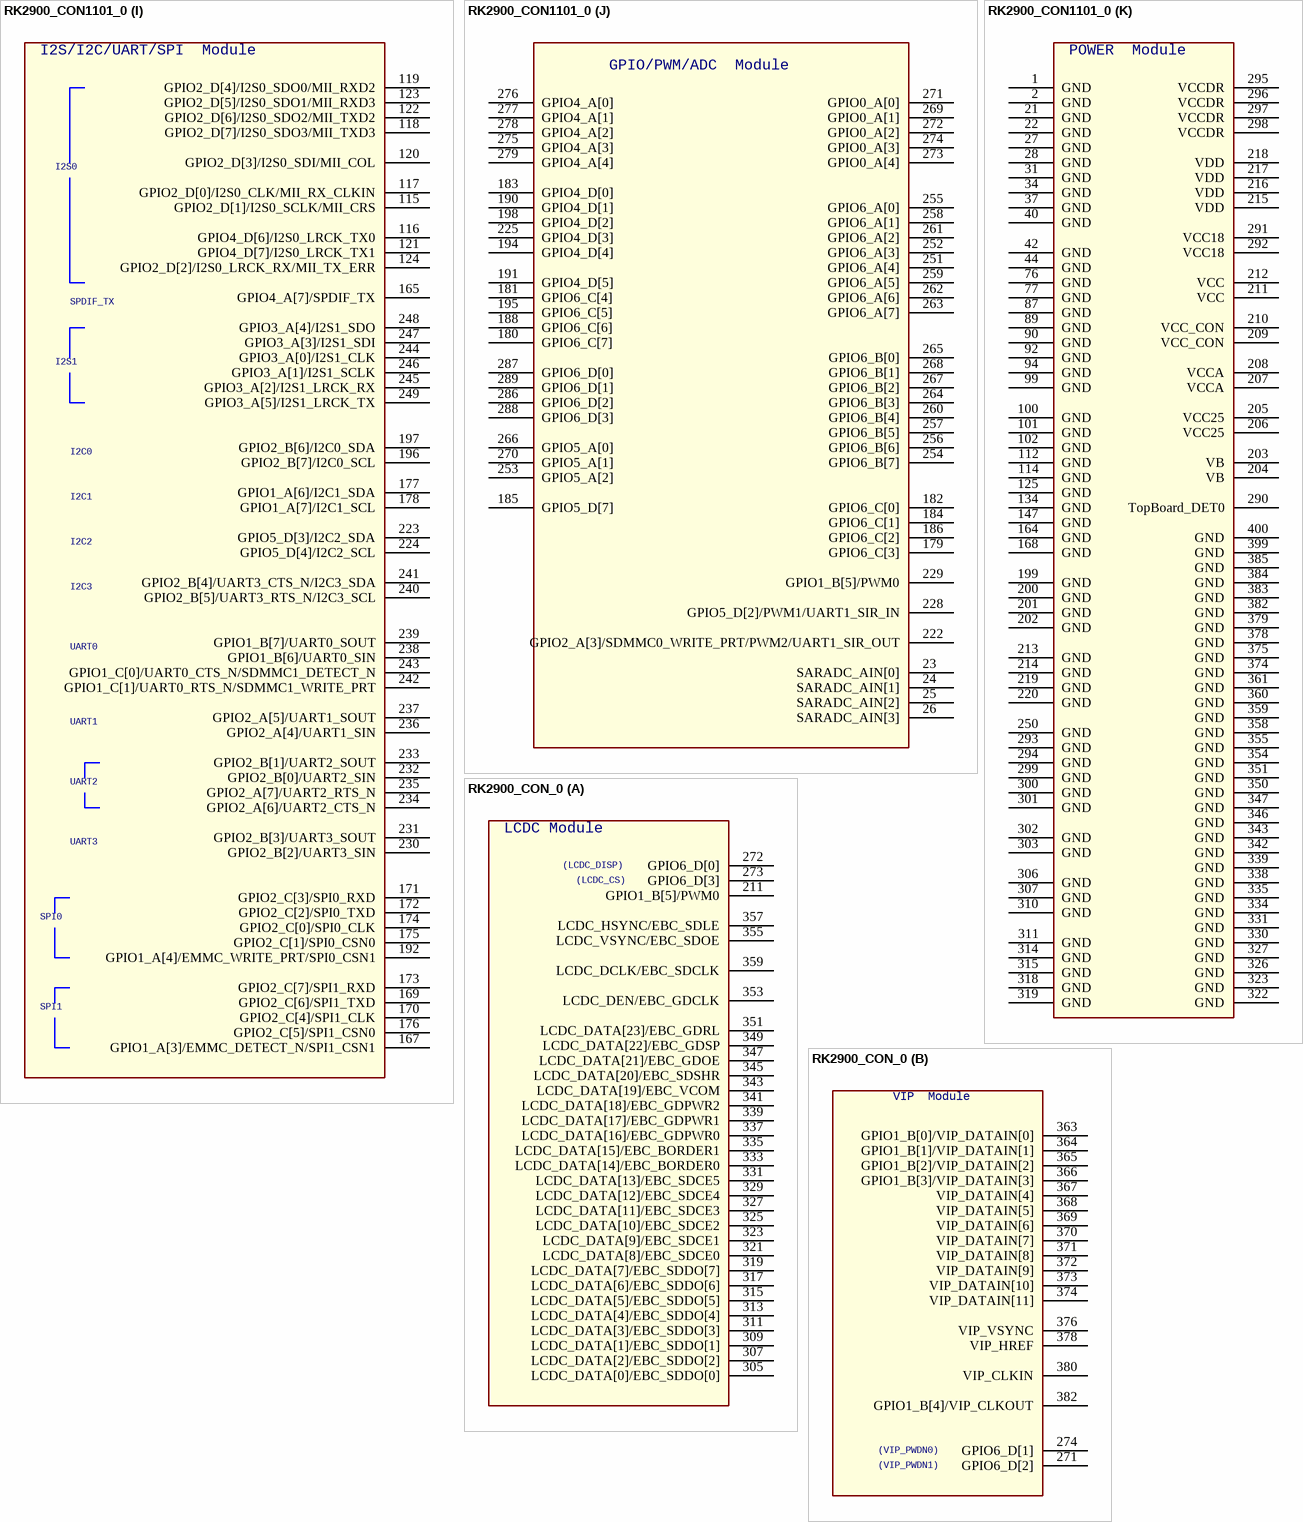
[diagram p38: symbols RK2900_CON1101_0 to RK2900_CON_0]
## RK2900_CON1101_0
designator U?
footprint RK2900_TOP
part A pins: 304 LCDC_DATA[0]/EBC_SDDO[0], 305 LCDC_DATA[2]/EBC_SDDO[2], 308 LCDC_DATA[1]/EBC_SDDO[1], 309 LCDC_DATA[3]/EBC_SDDO[3], 312 LCDC_DATA[4]/EBC_SDDO[4], 313 LCDC_DATA[5]/EBC_SDDO[5], 316 LCDC_DATA[6]/EBC_SDDO[6], 317 LCDC_DATA[7]/EBC_SDDO[7], 320 LCDC_DATA[8]/EBC_SDCE0, 321 LCDC_DATA[9]/EBC_SDCE1, 324 LCDC_DATA[10]/EBC_SDCE2, 325 LCDC_DATA[11]/EBC_SDCE3, 328 LCDC_DATA[12]/EBC_SDCE4, 329 LCDC_DATA[13]/EBC_SDCE5, 332 LCDC_DATA[14]/EBC_BORDER0, 333 LCDC_DATA[15]/EBC_BORDER1, 336 LCDC_DATA[16]/EBC_GDPWR0, 337 LCDC_DATA[17]/EBC_GDPWR1, 340 LCDC_DATA[18]/EBC_GDPWR2, 341 LCDC_DATA[19]/EBC_VCOM, 344 LCDC_DATA[20]/EBC_SDSHR, 345 LCDC_DATA[21]/EBC_GDOE, 348 LCDC_DATA[22]/EBC_GDSP, 349 LCDC_DATA[23]/EBC_GDRL, 352 LCDC_DEN/EBC_GDCLK, 353 LCDC_VSYNC/EBC_SDOE, 356 LCDC_HSYNC/EBC_SDLE, 357 LCDC_DCLK/EBC_SDCLK
part B pins: 362 GPIO1_B[0]/VIP_DATAIN[0], 363 GPIO1_B[1]/VIP_DATAIN[1], 364 GPIO1_B[2]/VIP_DATAIN[2], 365 GPIO1_B[3]/VIP_DATAIN[3], 366 VIP_DATAIN[4], 367 VIP_DATAIN[5], 368 VIP_DATAIN[6], 369 VIP_DATAIN[7], 370 VIP_DATAIN[8], 371 VIP_DATAIN[9], 372 VIP_DATAIN[10], 373 VIP_DATAIN[11], 376 VIP_VSYNC, 377 VIP_HREF, 380 VIP_CLKIN, 381 GPIO1_B[4]/VIP_CLKOUT
part C pins: 3 GPIO0_C[6]/EBC_SDCE4/SMC_DATA[14], 4 GPIO0_C[7]/EBC_SDCE5/SMC_DATA[15], 5 GPIO0_C[0]/EBC_GDSP/SMC_DATA[8], 6 GPIO0_C[1]/EBC_GDRL/SMC_DATA[9], 7 GPIO0_B[3]/EBC_BORDER0/SMC_ADDR[3]/HOST_DATA[3], 8 GPIO0_B[4]/EBC_BORDER1/SMC_WEN, 9 GPIO0_D[1]/EBC_GDCLK/SMC_ADDR[4]/HOST_DATA[4], 10 GPIO0_B[2]/EBC_SDCE2/SMC_ADDR[2]/HOST_DATA[2], 11 GPIO0_C[3]/EBC_GDPWR1/SMC_DATA[11], 12 GPIO0_B[7]/EBC_GDOE/SMC_OEN, 13 GPIO0_D[0]/EBC_SDOE/SMC_ADVN, 14 GPIO5_C[6]/EBC_SDDO[6]/SMC_DATA[6], 15 GPIO0_C[5]/EBC_SDCE3/SMC_DATA[13], 16 GPIO0_B[1]/EBC_SDCE1/SMC_ADDR[1]/HOST_DATA[1], 17 GPIO5_C[5]/EBC_SDDO[5]/SMC_DATA[5], 18 GPIO3_D[5]/SMC_ADDR[7]/HOST_DATA[7], 19 GPIO1_A[2]/SMC_CSN1, 20 GPIO0_C[4]/EBC_GDPWR2/SMC_DATA[12], 43 GPIO3_D[6]/SMC_ADDR[8]/HOST_DATA[8], 150 GPIO3_D[4]/HOST_WRN, 151 GPIO3_D[3]/HOST_RDN, 152 GPIO3_D[2]/HOST_CSN, 153 GPIO3_D[7]/SMC_ADDR[9]/HOST_DATA[9], 154 GPIO3_A[6]/SMC_ADDR[14]/HOST_DATA[14], 155 GPIO3_C[7]/SMC_ADDR[17]/HOST_DATA[17], 156 GPIO3_C[3]/SMC_ADDR[10]/HOST_DATA[10], 157 GPIO3_C[4]/SMC_ADDR[11]/HOST_DATA[11], 158 GPIO3_D[1]/SMC_ADDR[19]/HOST_ADDR1, 159 GPIO3_C[5]/SMC_ADDR[12]/HOST_DATA[12], 160 GPIO3_C[2]/SMC_ADDR[13]/HOST_DATA[13], 161 GPIO3_C[6]/SMC_ADDR[16]/HOST_DATA[16], 162 GPIO3_A[7]/SMC_ADDR[15]/HOST_DATA[15], 163 GPIO3_D[0]/SMC_ADDR[18]/HOST_ADDR0, 386 GPIO1_A[1]/SMC_CSN0, 387 GPIO5_C[4]/EBC_SDDO[4]/SMC_DATA[4], 388 GPIO5_D[1]/EBC_SDCLK/SMC_ADDR[6]/HOST_DATA[6], 389 GPIO0_B[5]/EBC_VCOM/SMC_BLSN0, 390 GPIO5_C[0]/EBC_SDDO[0]/SMC_DATA[0], 391 GPIO5_D[0]/EBC_SDLE/SMC_ADDR[5]/HOST_DATA[5], 392 GPIO5_C[1]/EBC_SDDO[1]/SMC_DATA[1], 393 GPIO0_B[6]/EBC_SDSHR/SMC_BLSN1/HOST_INT, 394 GPIO0_C[2]/EBC_GDPWR0/SMC_DATA[10], 395 GPIO5_C[2]/EBC_SDDO[2]/SMC_DATA[2], 396 GPIO5_C[3]/EBC_SDDO[3]/SMC_DATA[3], 397 GPIO5_C[7]/EBC_SDDO[7]/SMC_DATA[7], 398 GPIO0_B[0]/EBC_SDCE0/SMC_ADDR[0]/HOST_DATA[0]
part D pins: 29 OTG_DP, 30 OTG_DM, 32 HOST20_DM, 33 HOST20_DP, 35 HOST11_DM, 36 HOST11_DP, 38 OTG_ID, 39 OTG_VBUS, 41 RTCINT_OUT, 166 GPIO4_A[5]/OTG_DRV_VBUS, 187 GPIO4_A[6]/HOST20_DRV_VBUS, 280 NPOR
part E pins: 45 FLASH_ALE, 46 FLASH_DATA[1], 47 FLASH_RDY, 48 FLASH_RDN, 49 GPIO4_B[4]/FLASH_DATA[12], 50 FLASH_DATA[0], 51 FLASH_DATA[4], 52 GPIO4_B[7]/FLASH_DATA[15], 53 GPIO4_B[5]/FLASH_DATA[13], 54 FLASH_CLE, 55 GPIO4_B[1]/FLASH_DATA[9], 56 FLASH_DATA[5], 57 FLASH_CSN0, 58 FLASH_DATA[6], 59 GPIO4_B[0]/FLASH_DATA[8], 60 FLASH_DATA[7], 61 FLASH_DATA[2], 62 FLASH_DATA[3], 63 GPIO0_D[7]/FLASH_CSN6, 64 FLASH_WP, 65 FLASH_WRN, 66 GPIO4_B[6]/FLASH_DATA[14], 67 GPIO0_D[3]/FLASH_CSN2, 68 GPIO0_D[4]/FLASH_CSN3, 69 GPIO0_D[2]/FLASH_CSN1, 70 GPIO0_D[6]/FLASH_CSN5, 71 GPIO1_A[0]/FLASH_CSN7/MDDR_TQ, 72 GPIO0_A[5]/FLASH_DQS, 73 GPIO0_D[5]/FLASH_CSN4, 74 GPIO4_B[2]/FLASH_DATA[10], 75 GPIO4_B[3]/FLASH_DATA[11], 78 GPIO3_B[3]/EMMC_DATA1, 79 GPIO3_B[1]/EMMC_CMD, 80 GPIO3_B[6]/EMMC_DATA4, 81 GPIO3_C[1]/EMMC_DATA7, 82 GPIO3_B[5]/EMMC_DATA3, 83 GPIO3_B[4]/EMMC_DATA2, 84 GPIO3_B[2]/EMMC_DATA0, 85 GPIO3_C[0]/EMMC_DATA6, 86 GPIO3_B[7]/EMMC_DATA5, 88 GPIO3_B[0]/EMMC_CLKOUT, 221 GPIO1_A[5]/EMMC_PWR_EN/PWM3
part F pins: 91 GPIO1_C[2]/SDMMC1_CMD, 93 GPIO1_C[7]/SDMMC1_CLKOUT, 95 GPIO1_C[4]/SDMMC1_DATA1, 96 GPIO1_C[3]/SDMMC1_DATA0, 97 GPIO1_C[6]/SDMMC1_DATA3, 98 GPIO1_C[5]/SDMMC1_DATA2, 103 GPIO1_D[3]/SDMMC0_DATA1, 104 GPIO1_D[1]/SDMMC0_CMD, 105 GPIO1_D[5]/SDMMC0_DATA3, 106 GPIO2_A[1]/SDMMC0_DATA7, 107 GPIO1_D[7]/SDMMC0_DATA5, 108 GPIO1_D[2]/SDMMC0_DATA0, 109 GPIO2_A[0]/SDMMC0_DATA6, 110 GPIO1_D[6]/SDMMC0_DATA4, 111 GPIO1_D[4]/SDMMC0_DATA2, 113 GPIO1_D[0]/SDMMC0_CLKOUT, 193 GPIO2_A[2]/SDMMC0_DETECT_N, 226 GPIO5_D[5]/SDMMC0_PWR_EN, 227 GPIO5_D[6]/SDMMC1_PWR_EN
part G pins: 126 GPIO4_C[7]/RMII_RXD0/MII_RXD0, 127 GPIO4_C[3]/RMII_TXD0/MII_TXD0, 128 GPIO4_C[6]/RMII_RXD1/MII_RXD1, 129 GPIO4_C[1]/RMII_TX_EN/MII_TX_EN, 130 GPIO4_C[0]/RMII_CLKOUT/RMII_CLKIN, 131 GPIO4_C[2]/RMII_TXD1/MII_TXD1, 132 GPIO4_C[5]/RMII_CRS_DVALID/MII_RXD_VALID, 133 GPIO4_C[4]/RMII_RX_ERR/MII_RX_ERR, 148 GPIO5_A[3]/MII_TX_CLKIN, 149 GPIO0_A[6]/MII_MD, 189 GPIO0_A[7]/MII_MDCLK, 281 TRST_N, 282 TCK, 283 TDI, 284 TMS, 285 TDO
part H pins: 135 GPIO5_A[7]/HSADC_DATA2, 136 GPIO5_B[5]/HSADC_DATA8/TS_VALID, 137 GPIO5_A[5]/HSADC_DATA0, 138 GPIO5_B[1]/HSADC_DATA4, 139 GPIO5_B[0]/HSADC_DATA3, 140 GPIO5_A[6]/HSADC_DATA1, 141 GPIO5_B[3]/HSADC_DATA6, 142 GPIO5_B[2]/HSADC_DATA5, 143 GPIO5_B[4]/HSADC_DATA7, 144 GPIO5_A[4]/TS_SYNC, 145 GPIO5_B[6]/HSADC_DATA9/TS_FAIL, 146 GPIO5_B[7]/HSADC_CLKOUT/GPS_CLK
part I pins: 115 GPIO2_D[1]/I2S0_SCLK/MII_CRS, 116 GPIO4_D[6]/I2S0_LRCK_TX0, 117 GPIO2_D[0]/I2S0_CLK/MII_RX_CLKIN, 118 GPIO2_D[7]/I2S0_SDO3/MII_TXD3, 119 GPIO2_D[4]/I2S0_SDO0/MII_RXD2, 120 GPIO2_D[3]/I2S0_SDI/MII_COL, 121 GPIO4_D[7]/I2S0_LRCK_TX1, 122 GPIO2_D[6]/I2S0_SDO2/MII_TXD2, 123 GPIO2_D[5]/I2S0_SDO1/MII_RXD3, 124 GPIO2_D[2]/I2S0_LRCK_RX/MII_TX_ERR, 165 GPIO4_A[7]/SPDIF_TX, 167 GPIO1_A[3]/EMMC_DETECT_N/SPI1_CSN1, 169 GPIO2_C[6]/SPI1_TXD, 170 GPIO2_C[4]/SPI1_CLK, 171 GPIO2_C[3]/SPI0_RXD, 172 GPIO2_C[2]/SPI0_TXD, 173 GPIO2_C[7]/SPI1_RXD, 174 GPIO2_C[0]/SPI0_CLK, 175 GPIO2_C[1]/SPI0_CSN0, 176 GPIO2_C[5]/SPI1_CSN0, 177 GPIO1_A[6]/I2C1_SDA, 178 GPIO1_A[7]/I2C1_SCL, 192 GPIO1_A[4]/EMMC_WRITE_PRT/SPI0_CSN1, 196 GPIO2_B[7]/I2C0_SCL, 197 GPIO2_B[6]/I2C0_SDA, 223 GPIO5_D[3]/I2C2_SDA, 224 GPIO5_D[4]/I2C2_SCL, 230 GPIO2_B[2]/UART3_SIN, 231 GPIO2_B[3]/UART3_SOUT, 232 GPIO2_B[0]/UART2_SIN, 233 GPIO2_B[1]/UART2_SOUT, 234 GPIO2_A[6]/UART2_CTS_N, 235 GPIO2_A[7]/UART2_RTS_N, 236 GPIO2_A[4]/UART1_SIN, 237 GPIO2_A[5]/UART1_SOUT, 238 GPIO1_B[6]/UART0_SIN, 239 GPIO1_B[7]/UART0_SOUT, 240 GPIO2_B[5]/UART3_RTS_N/I2C3_SCL, 241 GPIO2_B[4]/UART3_CTS_N/I2C3_SDA, 242 GPIO1_C[1]/UART0_RTS_N/SDMMC1_WRITE_PRT, 243 GPIO1_C[0]/UART0_CTS_N/SDMMC1_DETECT_N, 244 GPIO3_A[0]/I2S1_CLK, 245 GPIO3_A[2]/I2S1_LRCK_RX, 246 GPIO3_A[1]/I2S1_SCLK, 247 GPIO3_A[3]/I2S1_SDI, 248 GPIO3_A[4]/I2S1_SDO, 249 GPIO3_A[5]/I2S1_LRCK_TX
part J pins: 23 SARADC_AIN[0], 24 SARADC_AIN[1], 25 SARADC_AIN[2], 26 SARADC_AIN[3], 179 GPIO6_C[3], 180 GPIO6_C[7], 181 GPIO6_C[4], 182 GPIO6_C[0], 183 GPIO4_D[0], 184 GPIO6_C[1], 185 GPIO5_D[7], 186 GPIO6_C[2], 188 GPIO6_C[6], 190 GPIO4_D[1], 191 GPIO4_D[5], 194 GPIO4_D[4], 195 GPIO6_C[5], 198 GPIO4_D[2], 222 GPIO2_A[3]/SDMMC0_WRITE_PRT/PWM2/UART1_SIR_OUT, 225 GPIO4_D[3], 228 GPIO5_D[2]/PWM1/UART1_SIR_IN, 229 GPIO1_B[5]/PWM0, 251 GPIO6_A[4], 252 GPIO6_A[3], 253 GPIO5_A[2], 254 GPIO6_B[7], 255 GPIO6_A[0], 256 GPIO6_B[6], 257 GPIO6_B[5], 258 GPIO6_A[1], 259 GPIO6_A[5], 260 GPIO6_B[4], 261 GPIO6_A[2], 262 GPIO6_A[6], 263 GPIO6_A[7], 264 GPIO6_B[3], 265 GPIO6_B[0], 266 GPIO5_A[0], 267 GPIO6_B[2], 268 GPIO6_B[1], 269 GPIO0_A[1], 270 GPIO5_A[1], 271 GPIO0_A[0], 272 GPIO0_A[2], 273 GPIO0_A[4], 274 GPIO0_A[3], 275 GPIO4_A[3], 276 GPIO4_A[0], 277 GPIO4_A[1], 278 GPIO4_A[2], 279 GPIO4_A[4], 286 GPIO6_D[2], 287 GPIO6_D[0], 288 GPIO6_D[3], 289 GPIO6_D[1]
part K pins: 1 GND, 2 GND, 21 GND, 22 GND, 27 GND, 28 GND, 31 GND, 34 GND, 37 GND, 40 GND, 42 GND, 44 GND, 76 GND, 77 GND, 87 GND, 89 GND, 90 GND, 92 GND, 94 GND, 99 GND, 100 GND, 101 GND, 102 GND, 112 GND, 114 GND, 125 GND, 134 GND, 147 GND, 164 GND, 168 GND, 199 GND, 200 GND, 201 GND, 202 GND, 203 VB, 204 VB, 205 VCC25, 206 VCC25, 207 VCCA, 208 VCCA, 209 VCC_CON, 210 VCC_CON, 211 VCC, 212 VCC, 213 GND, 214 GND, 215 VDD, 216 VDD, 217 VDD, 218 VDD, 219 GND, 220 GND, 250 GND, 290 TopBoard_DET0, 291 VCC18, 292 VCC18, 293 GND, 294 GND, 295 VCCDR, 296 VCCDR, 297 VCCDR, 298 VCCDR, 299 GND, 300 GND, 301 GND, 302 GND, 303 GND, 306 GND, 307 GND, 310 GND, 311 GND, 314 GND, 315 GND, 318 GND, 319 GND, 322 GND, 323 GND, 326 GND, 327 GND, 330 GND, 331 GND, 334 GND, 335 GND, 338 GND, 339 GND, 342 GND, 343 GND, 346 GND, 347 GND, 350 GND, 351 GND, 354 GND, 355 GND, 358 GND, 359 GND, 360 GND, 361 GND, 374 GND, 375 GND, 378 GND, 379 GND, 382 GND, 383 GND, 384 GND, 385 GND, 399 GND, 400 GND



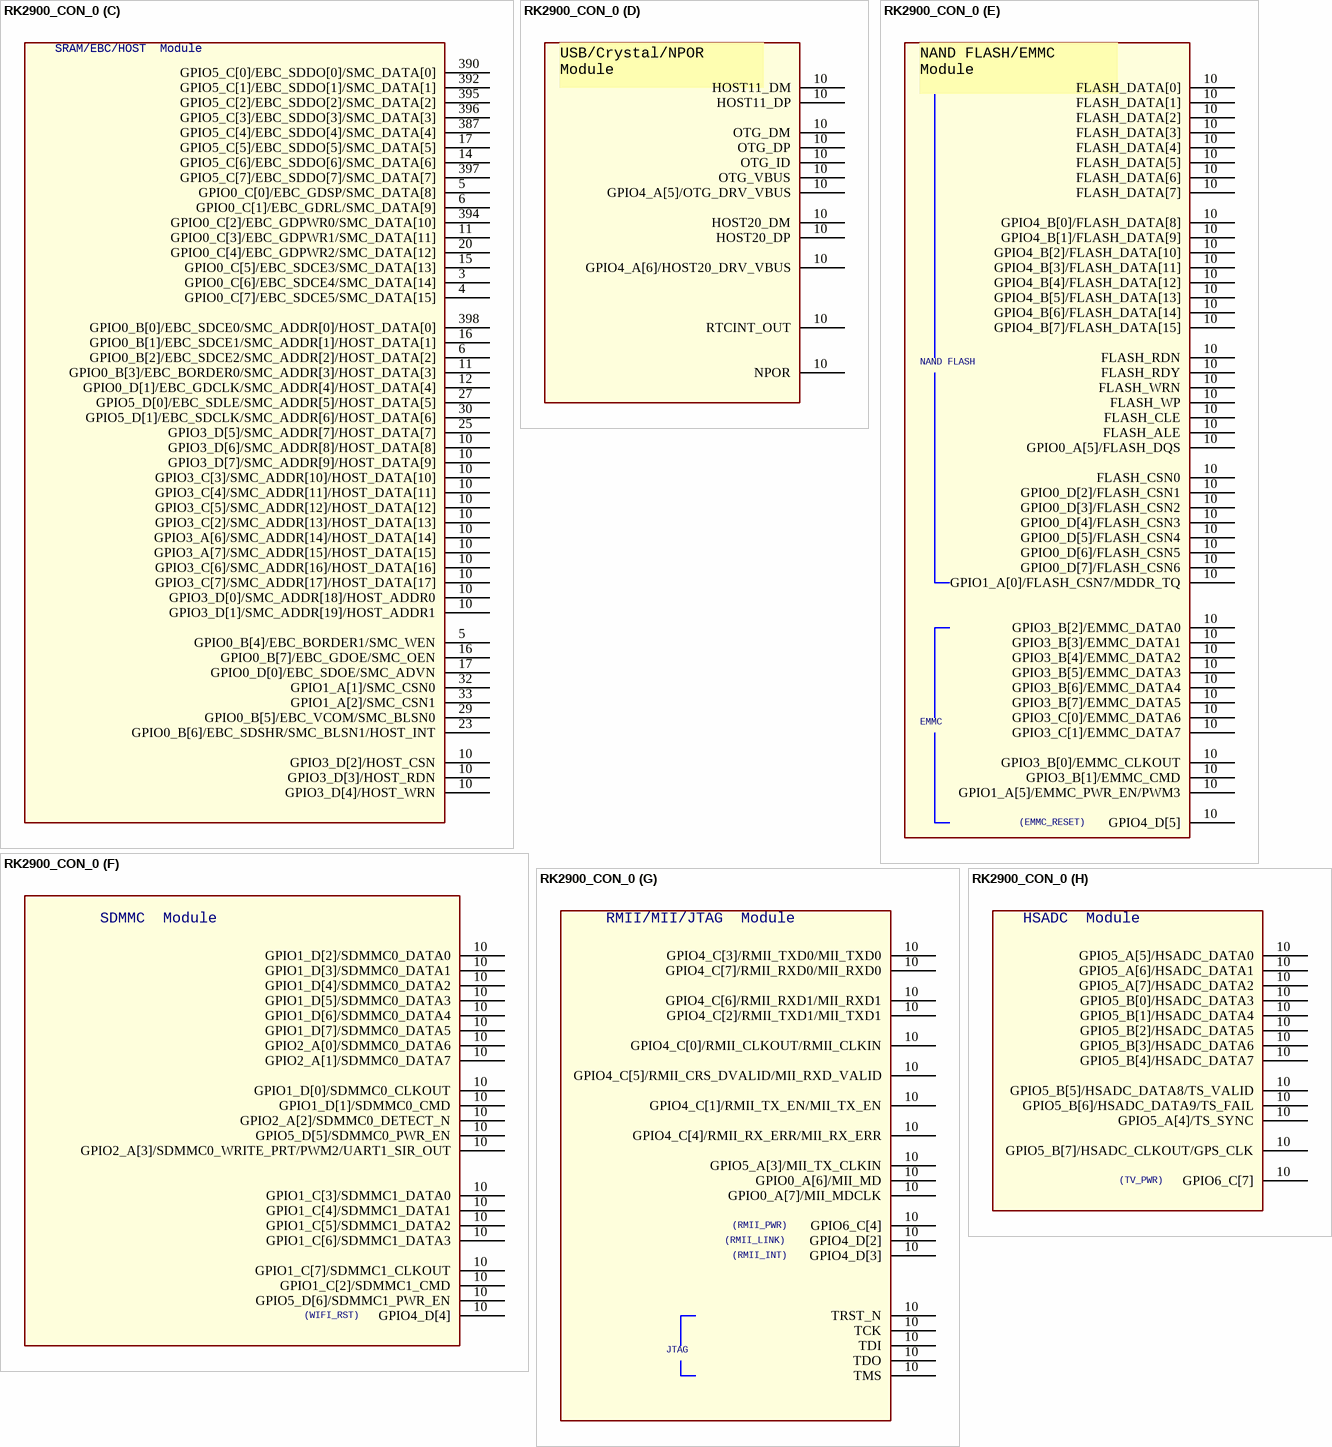
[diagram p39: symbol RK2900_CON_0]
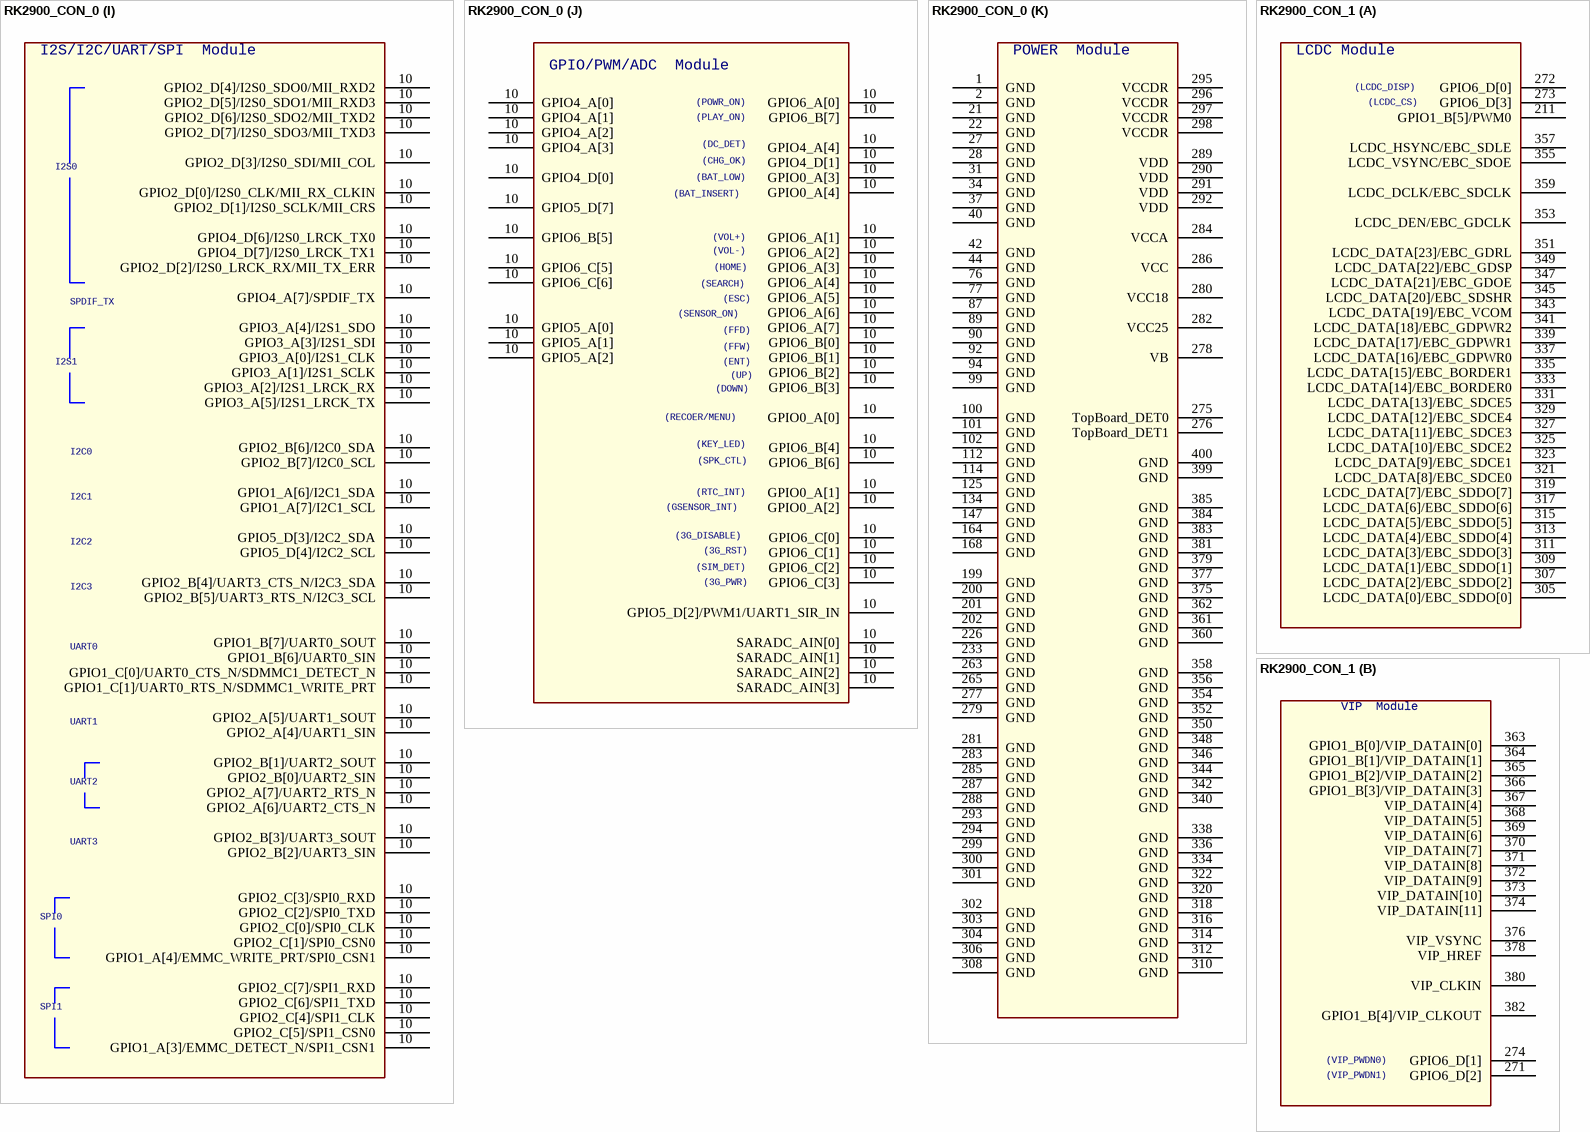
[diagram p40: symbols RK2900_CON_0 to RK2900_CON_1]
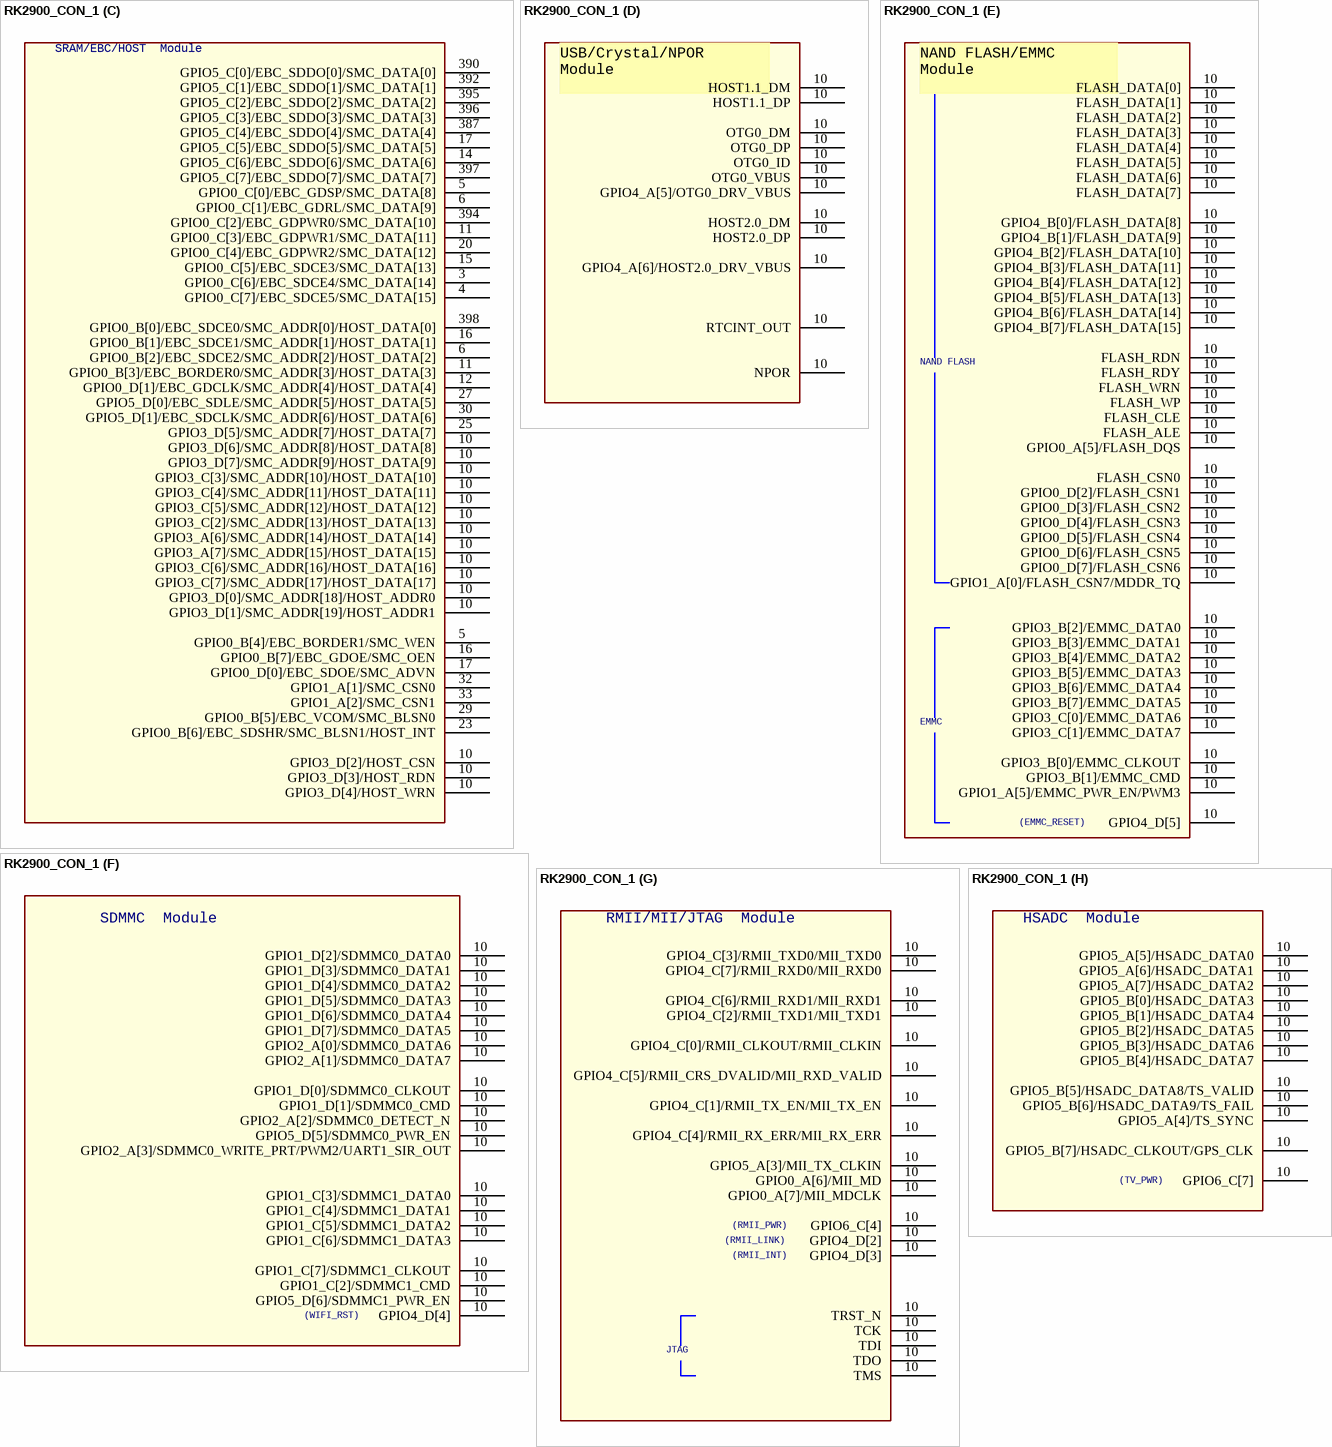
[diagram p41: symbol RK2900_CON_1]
## RK2900_CON_0
designator U?
part A pins: 211 GPIO1_B[5]/PWM0, 272 GPIO6_D[0], 273 GPIO6_D[3], 305 LCDC_DATA[0]/EBC_SDDO[0], 307 LCDC_DATA[2]/EBC_SDDO[2], 309 LCDC_DATA[1]/EBC_SDDO[1], 311 LCDC_DATA[3]/EBC_SDDO[3], 313 LCDC_DATA[4]/EBC_SDDO[4], 315 LCDC_DATA[5]/EBC_SDDO[5], 317 LCDC_DATA[6]/EBC_SDDO[6], 319 LCDC_DATA[7]/EBC_SDDO[7], 321 LCDC_DATA[8]/EBC_SDCE0, 323 LCDC_DATA[9]/EBC_SDCE1, 325 LCDC_DATA[10]/EBC_SDCE2, 327 LCDC_DATA[11]/EBC_SDCE3, 329 LCDC_DATA[12]/EBC_SDCE4, 331 LCDC_DATA[13]/EBC_SDCE5, 333 LCDC_DATA[14]/EBC_BORDER0, 335 LCDC_DATA[15]/EBC_BORDER1, 337 LCDC_DATA[16]/EBC_GDPWR0, 339 LCDC_DATA[17]/EBC_GDPWR1, 341 LCDC_DATA[18]/EBC_GDPWR2, 343 LCDC_DATA[19]/EBC_VCOM, 345 LCDC_DATA[20]/EBC_SDSHR, 347 LCDC_DATA[21]/EBC_GDOE, 349 LCDC_DATA[22]/EBC_GDSP, 351 LCDC_DATA[23]/EBC_GDRL, 353 LCDC_DEN/EBC_GDCLK, 355 LCDC_VSYNC/EBC_SDOE, 357 LCDC_HSYNC/EBC_SDLE, 359 LCDC_DCLK/EBC_SDCLK
part B pins: 271 GPIO6_D[2], 274 GPIO6_D[1], 363 GPIO1_B[0]/VIP_DATAIN[0], 364 GPIO1_B[1]/VIP_DATAIN[1], 365 GPIO1_B[2]/VIP_DATAIN[2], 366 GPIO1_B[3]/VIP_DATAIN[3], 367 VIP_DATAIN[4], 368 VIP_DATAIN[5], 369 VIP_DATAIN[6], 370 VIP_DATAIN[7], 371 VIP_DATAIN[8], 372 VIP_DATAIN[9], 373 VIP_DATAIN[10], 374 VIP_DATAIN[11], 376 VIP_VSYNC, 378 VIP_HREF, 380 VIP_CLKIN, 382 GPIO1_B[4]/VIP_CLKOUT
part C pins: 3 GPIO0_C[6]/EBC_SDCE4/SMC_DATA[14], 4 GPIO0_C[7]/EBC_SDCE5/SMC_DATA[15], 5 GPIO0_B[4]/EBC_BORDER1/SMC_WEN, 5 GPIO0_C[0]/EBC_GDSP/SMC_DATA[8], 6 GPIO0_C[1]/EBC_GDRL/SMC_DATA[9], 6 GPIO0_B[2]/EBC_SDCE2/SMC_ADDR[2]/HOST_DATA[2], 10 GPIO3_D[6]/SMC_ADDR[8]/HOST_DATA[8], 10 GPIO3_D[7]/SMC_ADDR[9]/HOST_DATA[9], 10 GPIO3_C[3]/SMC_ADDR[10]/HOST_DATA[10], 10 GPIO3_C[4]/SMC_ADDR[11]/HOST_DATA[11], 10 GPIO3_C[5]/SMC_ADDR[12]/HOST_DATA[12], 10 GPIO3_C[2]/SMC_ADDR[13]/HOST_DATA[13], 10 GPIO3_A[6]/SMC_ADDR[14]/HOST_DATA[14], 10 GPIO3_A[7]/SMC_ADDR[15]/HOST_DATA[15], 10 GPIO3_C[6]/SMC_ADDR[16]/HOST_DATA[16], 10 GPIO3_C[7]/SMC_ADDR[17]/HOST_DATA[17], 10 GPIO3_D[0]/SMC_ADDR[18]/HOST_ADDR0, 10 GPIO3_D[1]/SMC_ADDR[19]/HOST_ADDR1, 10 GPIO3_D[2]/HOST_CSN, 10 GPIO3_D[4]/HOST_WRN, 10 GPIO3_D[3]/HOST_RDN, 11 GPIO0_B[3]/EBC_BORDER0/SMC_ADDR[3]/HOST_DATA[3], 11 GPIO0_C[3]/EBC_GDPWR1/SMC_DATA[11], 12 GPIO0_D[1]/EBC_GDCLK/SMC_ADDR[4]/HOST_DATA[4], 14 GPIO5_C[6]/EBC_SDDO[6]/SMC_DATA[6], 15 GPIO0_C[5]/EBC_SDCE3/SMC_DATA[13], 16 GPIO0_B[7]/EBC_GDOE/SMC_OEN, 16 GPIO0_B[1]/EBC_SDCE1/SMC_ADDR[1]/HOST_DATA[1], 17 GPIO0_D[0]/EBC_SDOE/SMC_ADVN, 17 GPIO5_C[5]/EBC_SDDO[5]/SMC_DATA[5], 20 GPIO0_C[4]/EBC_GDPWR2/SMC_DATA[12], 23 GPIO0_B[6]/EBC_SDSHR/SMC_BLSN1/HOST_INT, 25 GPIO3_D[5]/SMC_ADDR[7]/HOST_DATA[7], 27 GPIO5_D[0]/EBC_SDLE/SMC_ADDR[5]/HOST_DATA[5], 29 GPIO0_B[5]/EBC_VCOM/SMC_BLSN0, 30 GPIO5_D[1]/EBC_SDCLK/SMC_ADDR[6]/HOST_DATA[6], 32 GPIO1_A[1]/SMC_CSN0, 33 GPIO1_A[2]/SMC_CSN1, 387 GPIO5_C[4]/EBC_SDDO[4]/SMC_DATA[4], 390 GPIO5_C[0]/EBC_SDDO[0]/SMC_DATA[0], 392 GPIO5_C[1]/EBC_SDDO[1]/SMC_DATA[1], 394 GPIO0_C[2]/EBC_GDPWR0/SMC_DATA[10], 395 GPIO5_C[2]/EBC_SDDO[2]/SMC_DATA[2], 396 GPIO5_C[3]/EBC_SDDO[3]/SMC_DATA[3], 397 GPIO5_C[7]/EBC_SDDO[7]/SMC_DATA[7], 398 GPIO0_B[0]/EBC_SDCE0/SMC_ADDR[0]/HOST_DATA[0]
part D pins: 10 HOST11_DM, 10 HOST11_DP, 10 HOST20_DM, 10 HOST20_DP, 10 OTG_DM, 10 OTG_DP, 10 OTG_ID, 10 OTG_VBUS, 10 GPIO4_A[5]/OTG_DRV_VBUS, 10 GPIO4_A[6]/HOST20_DRV_VBUS, 10 RTCINT_OUT, 10 NPOR
part E pins: 10 GPIO0_D[6]/FLASH_CSN5, 10 GPIO1_A[0]/FLASH_CSN7/MDDR_TQ, 10 GPIO0_A[5]/FLASH_DQS, 10 GPIO0_D[5]/FLASH_CSN4, 10 GPIO4_B[2]/FLASH_DATA[10], 10 GPIO4_B[3]/FLASH_DATA[11], 10 FLASH_WP, 10 FLASH_WRN, 10 GPIO4_B[6]/FLASH_DATA[14], 10 GPIO0_D[3]/FLASH_CSN2, 10 GPIO0_D[4]/FLASH_CSN3, 10 GPIO0_D[2]/FLASH_CSN1, 10 FLASH_DATA[6], 10 GPIO4_B[0]/FLASH_DATA[8], 10 FLASH_DATA[7], 10 FLASH_DATA[2], 10 FLASH_DATA[3], 10 GPIO0_D[7]/FLASH_CSN6, 10 GPIO4_B[7]/FLASH_DATA[15], 10 GPIO4_B[5]/FLASH_DATA[13], 10 FLASH_CLE, 10 GPIO4_B[1]/FLASH_DATA[9], 10 FLASH_DATA[5], 10 FLASH_CSN0, 10 FLASH_DATA[1], 10 FLASH_RDY, 10 FLASH_RDN, 10 GPIO4_B[4]/FLASH_DATA[12], 10 FLASH_DATA[0], 10 FLASH_DATA[4], 10 FLASH_ALE, 10 GPIO3_B[2]/EMMC_DATA0, 10 GPIO3_B[3]/EMMC_DATA1, 10 GPIO3_B[4]/EMMC_DATA2, 10 GPIO3_B[5]/EMMC_DATA3, 10 GPIO3_B[6]/EMMC_DATA4, 10 GPIO3_B[7]/EMMC_DATA5, 10 GPIO3_C[0]/EMMC_DATA6, 10 GPIO3_C[1]/EMMC_DATA7, 10 GPIO3_B[0]/EMMC_CLKOUT, 10 GPIO3_B[1]/EMMC_CMD, 10 GPIO1_A[5]/EMMC_PWR_EN/PWM3, 10 GPIO4_D[5]
part F pins: 10 GPIO1_D[2]/SDMMC0_DATA0, 10 GPIO1_D[7]/SDMMC0_DATA5, 10 GPIO2_A[0]/SDMMC0_DATA6, 10 GPIO1_D[6]/SDMMC0_DATA4, 10 GPIO1_D[0]/SDMMC0_CLKOUT, 10 GPIO1_C[2]/SDMMC1_CMD, 10 GPIO2_A[1]/SDMMC0_DATA7, 10 GPIO1_D[5]/SDMMC0_DATA3, 10 GPIO1_C[5]/SDMMC1_DATA2, 10 GPIO1_C[6]/SDMMC1_DATA3, 10 GPIO1_D[1]/SDMMC0_CMD, 10 GPIO1_D[3]/SDMMC0_DATA1, 10 GPIO1_C[3]/SDMMC1_DATA0, 10 GPIO1_C[4]/SDMMC1_DATA1, 10 GPIO1_C[7]/SDMMC1_CLKOUT, 10 GPIO5_D[5]/SDMMC0_PWR_EN, 10 GPIO2_A[3]/SDMMC0_WRITE_PRT/PWM2/UART1_SIR_OUT, 10 GPIO2_A[2]/SDMMC0_DETECT_N, 10 GPIO1_D[4]/SDMMC0_DATA2, 10 GPIO5_D[6]/SDMMC1_PWR_EN, 10 GPIO4_D[4]
part G pins: 10 GPIO4_C[5]/RMII_CRS_DVALID/MII_RXD_VALID, 10 GPIO4_C[0]/RMII_CLKOUT/RMII_CLKIN, 10 GPIO4_C[1]/RMII_TX_EN/MII_TX_EN, 10 GPIO4_C[6]/RMII_RXD1/MII_RXD1, 10 GPIO4_C[4]/RMII_RX_ERR/MII_RX_ERR, 10 GPIO4_C[2]/RMII_TXD1/MII_TXD1, 10 GPIO4_C[3]/RMII_TXD0/MII_TXD0, 10 GPIO4_C[7]/RMII_RXD0/MII_RXD0, 10 GPIO5_A[3]/MII_TX_CLKIN, 10 GPIO0_A[6]/MII_MD, 10 GPIO0_A[7]/MII_MDCLK, 10 TRST_N, 10 TCK, 10 TDI, 10 TMS, 10 TDO, 10 GPIO6_C[4], 10 GPIO4_D[3], 10 GPIO4_D[2]
part H pins: 10 GPIO5_B[6]/HSADC_DATA9/TS_FAIL, 10 GPIO5_B[3]/HSADC_DATA6, 10 GPIO5_A[7]/HSADC_DATA2, 10 GPIO5_B[2]/HSADC_DATA5, 10 GPIO5_B[5]/HSADC_DATA8/TS_VALID, 10 GPIO5_A[5]/HSADC_DATA0, 10 GPIO5_B[4]/HSADC_DATA7, 10 GPIO5_B[1]/HSADC_DATA4, 10 GPIO5_B[0]/HSADC_DATA3, 10 GPIO5_A[6]/HSADC_DATA1, 10 GPIO5_B[7]/HSADC_CLKOUT/GPS_CLK, 10 GPIO5_A[4]/TS_SYNC, 10 GPIO6_C[7]
part I pins: 10 GPIO2_D[4]/I2S0_SDO0/MII_RXD2, 10 GPIO2_D[7]/I2S0_SDO3/MII_TXD3, 10 GPIO2_D[0]/I2S0_CLK/MII_RX_CLKIN, 10 GPIO4_D[6]/I2S0_LRCK_TX0, 10 GPIO2_D[1]/I2S0_SCLK/MII_CRS, 10 GPIO2_D[2]/I2S0_LRCK_RX/MII_TX_ERR, 10 GPIO2_D[5]/I2S0_SDO1/MII_RXD3, 10 GPIO2_D[6]/I2S0_SDO2/MII_TXD2, 10 GPIO4_D[7]/I2S0_LRCK_TX1, 10 GPIO2_D[3]/I2S0_SDI/MII_COL, 10 GPIO3_A[5]/I2S1_LRCK_TX, 10 GPIO3_A[4]/I2S1_SDO, 10 GPIO3_A[3]/I2S1_SDI, 10 GPIO3_A[1]/I2S1_SCLK, 10 GPIO3_A[2]/I2S1_LRCK_RX, 10 GPIO3_A[0]/I2S1_CLK, 10 GPIO2_B[6]/I2C0_SDA, 10 GPIO2_B[7]/I2C0_SCL, 10 GPIO1_A[6]/I2C1_SDA, 10 GPIO1_A[7]/I2C1_SCL, 10 GPIO5_D[3]/I2C2_SDA, 10 GPIO5_D[4]/I2C2_SCL, 10 GPIO2_B[4]/UART3_CTS_N/I2C3_SDA, 10 GPIO2_B[5]/UART3_RTS_N/I2C3_SCL, 10 GPIO1_B[7]/UART0_SOUT, 10 GPIO1_B[6]/UART0_SIN, 10 GPIO2_A[4]/UART1_SIN, 10 GPIO2_A[5]/UART1_SOUT, 10 GPIO2_A[7]/UART2_RTS_N, 10 GPIO2_A[6]/UART2_CTS_N, 10 GPIO2_B[0]/UART2_SIN, 10 GPIO2_B[1]/UART2_SOUT, 10 GPIO2_B[3]/UART3_SOUT, 10 GPIO2_B[2]/UART3_SIN, 10 GPIO1_C[0]/UART0_CTS_N/SDMMC1_DETECT_N, 10 GPIO1_C[1]/UART0_RTS_N/SDMMC1_WRITE_PRT, 10 GPIO2_C[0]/SPI0_CLK, 10 GPIO2_C[3]/SPI0_RXD, 10 GPIO2_C[1]/SPI0_CSN0, 10 GPIO2_C[2]/SPI0_TXD, 10 GPIO2_C[5]/SPI1_CSN0, 10 GPIO2_C[6]/SPI1_TXD, 10 GPIO2_C[7]/SPI1_RXD, 10 GPIO2_C[4]/SPI1_CLK, 10 GPIO1_A[3]/EMMC_DETECT_N/SPI1_CSN1, 10 GPIO1_A[4]/EMMC_WRITE_PRT/SPI0_CSN1, 10 GPIO4_A[7]/SPDIF_TX
part J pins: 10 GPIO6_A[0], 10 GPIO6_B[7], 10 GPIO6_B[6], 10 GPIO6_B[5], 10 GPIO6_A[1], 10 GPIO6_A[5], 10 GPIO6_B[4], 10 GPIO6_A[2], 10 GPIO6_A[6], 10 GPIO6_A[7], 10 GPIO6_B[3], 10 GPIO6_A[3], 10 GPIO6_B[0], 10 GPIO5_A[0], 10 GPIO6_B[2], 10 GPIO5_A[2], 10 GPIO6_A[4], 10 GPIO6_B[1], 10 GPIO0_A[1], 10 GPIO5_A[1], 10 GPIO0_A[0], 10 GPIO0_A[2], 10 GPIO0_A[4], 10 GPIO0_A[3], 10 GPIO4_A[3], 10 GPIO4_A[0], 10 GPIO4_A[1], 10 GPIO4_A[2], 10 GPIO4_A[4], 10 GPIO5_D[2]/PWM1/UART1_SIR_IN, 10 GPIO6_C[2], 10 GPIO6_C[6], 10 GPIO6_C[0], 10 GPIO4_D[0], 10 GPIO6_C[3], 10 GPIO6_C[5], 10 GPIO4_D[1], 10 GPIO6_C[1], 10 GPIO5_D[7], 10 SARADC_AIN[1], 10 SARADC_AIN[2], 10 SARADC_AIN[0], 10 SARADC_AIN[3]
part K pins: 1 GND, 2 GND, 21 GND, 22 GND, 27 GND, 28 GND, 31 GND, 34 GND, 37 GND, 40 GND, 42 GND, 44 GND, 76 GND, 77 GND, 87 GND, 89 GND, 90 GND, 92 GND, 94 GND, 99 GND, 100 GND, 101 GND, 102 GND, 112 GND, 114 GND, 125 GND, 134 GND, 147 GND, 164 GND, 168 GND, 199 GND, 200 GND, 201 GND, 202 GND, 226 GND, 233 GND, 263 GND, 265 GND, 275 TopBoard_DET0, 276 TopBoard_DET1, 277 GND, 278 VB, 279 GND, 280 VCC18, 281 GND, 282 VCC25, 283 GND, 284 VCCA, 285 GND, 286 VCC, 287 GND, 288 GND, 289 VDD, 290 VDD, 291 VDD, 292 VDD, 293 GND, 294 GND, 295 VCCDR, 296 VCCDR, 297 VCCDR, 298 VCCDR, 299 GND, 300 GND, 301 GND, 302 GND, 303 GND, 304 GND, 306 GND, 308 GND, 310 GND, 312 GND, 314 GND, 316 GND, 318 GND, 320 GND, 322 GND, 334 GND, 336 GND, 338 GND, 340 GND, 342 GND, 344 GND, 346 GND, 348 GND, 350 GND, 352 GND, 354 GND, 356 GND, 358 GND, 360 GND, 361 GND, 362 GND, 375 GND, 377 GND, 379 GND, 381 GND, 383 GND, 384 GND, 385 GND, 399 GND, 400 GND

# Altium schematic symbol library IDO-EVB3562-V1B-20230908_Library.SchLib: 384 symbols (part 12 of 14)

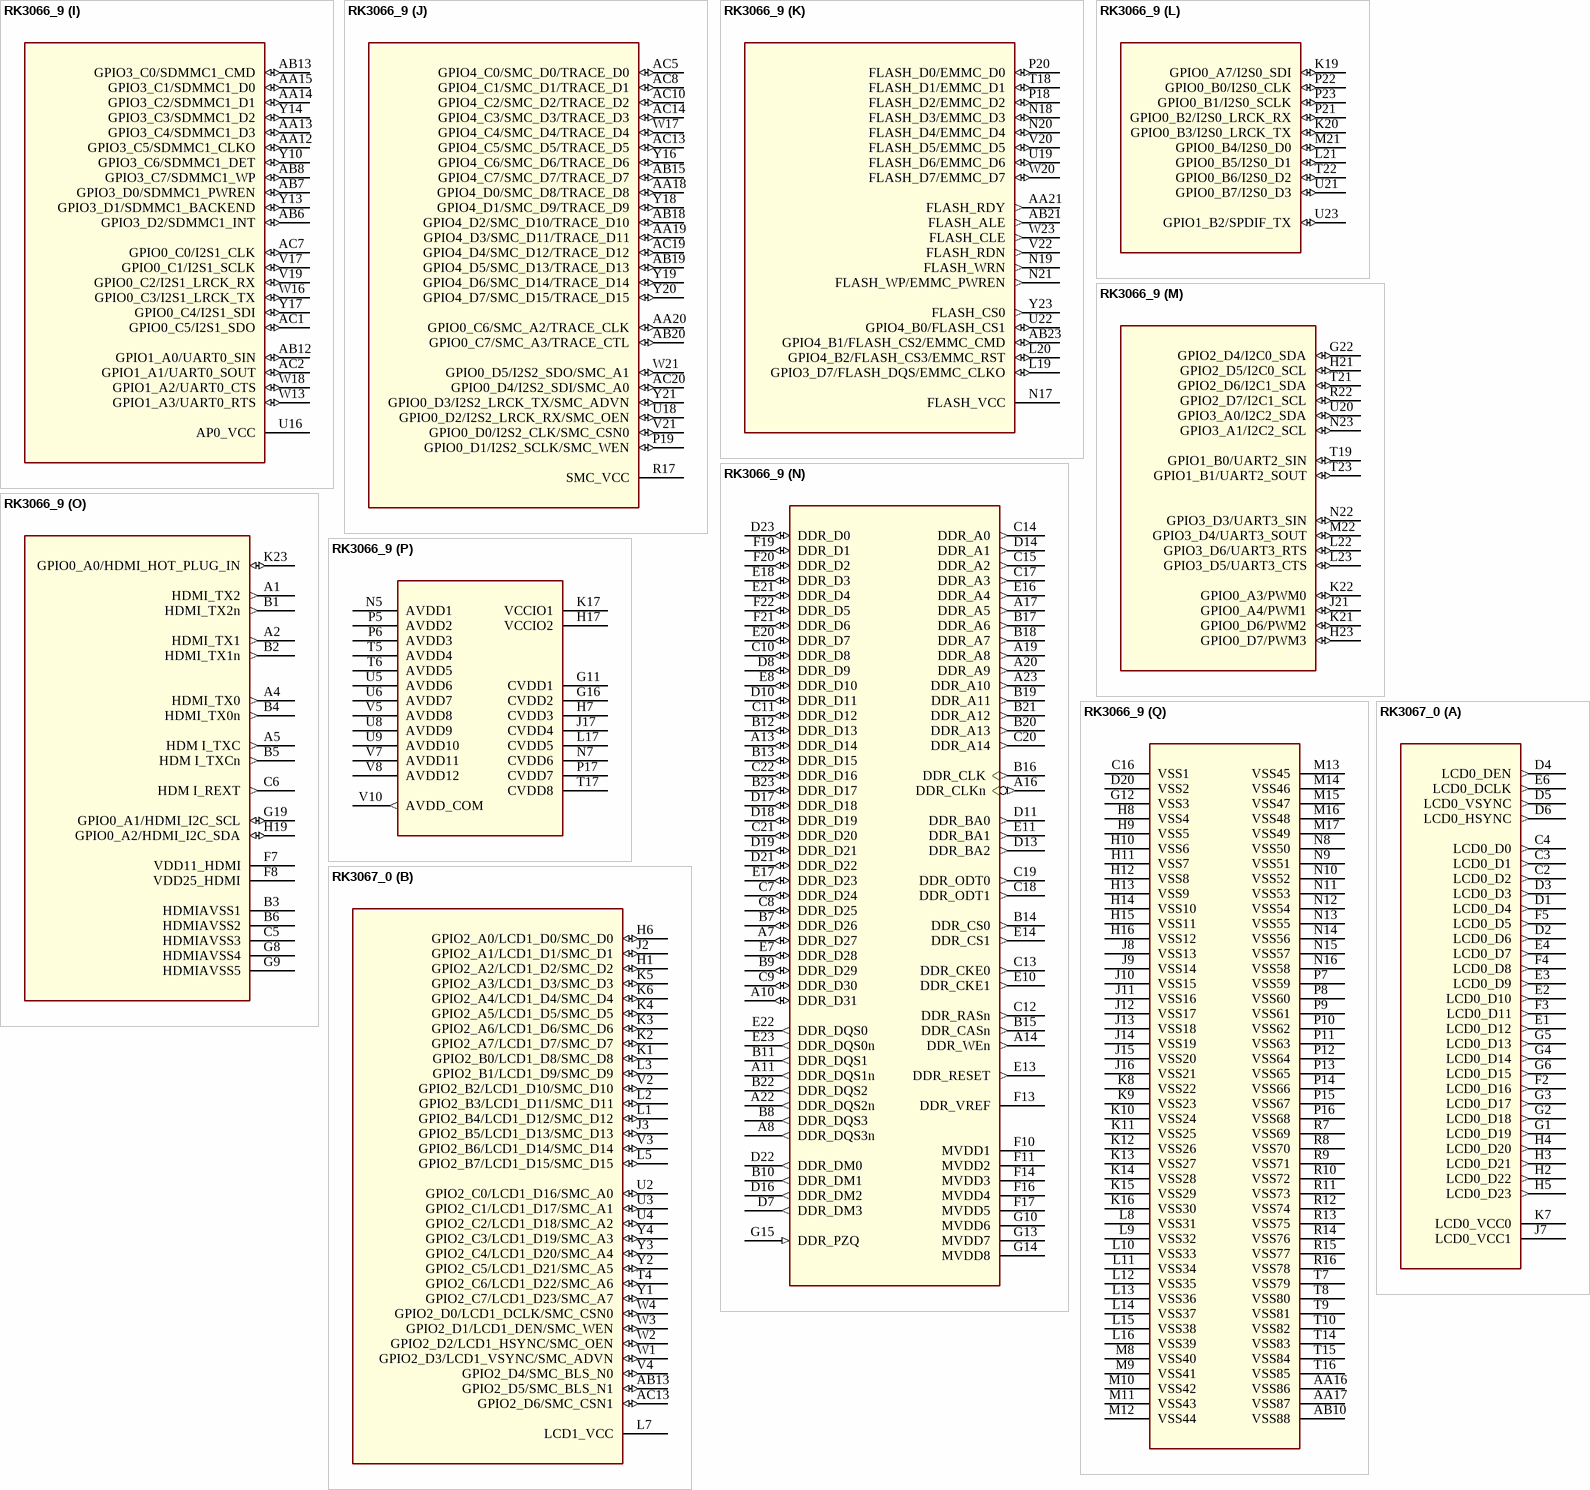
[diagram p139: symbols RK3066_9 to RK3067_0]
## RK3066_9
designator U?
footprint BGA453-19X19
part A pins: C2 LCD0_D2 (out), C3 LCD0_DEN (out), C4 LCD0_VSYNC (out), D1 LCD0_D5 (out), D2 LCD0_D4 (out), D3 LCD0_D3 (out), D4 LCD0_D0 (out), D5 LCD0_DCLK (out), D6 LCD0_HSYNC (out), E1 LCD0_D18 (out), E2 LCD0_D6 (out), E3 LCD0_D16 (out), E4 LCD0_D1 (out), E6 LCD0_D9 (out), F2 LCD0_D17 (out), F3 LCD0_D15 (out), F4 LCD0_D7 (out), F5 LCD0_D11 (out), G1 LCD0_D21 (out), G2 LCD0_D19 (out), G3 LCD0_D14 (out), G4 LCD0_D8 (out), G5 LCD0_D22 (out), G6 LCD0_D10 (out), H3 LCD0_D20 (out), H4 LCD0_D13 (out), H5 LCD0_D12 (out), H6 LCD0_D23 (out), J7 LCD0_VCC1 (power), K7 LCD0_VCC0 (power)
part B pins: H1 GPIO2_A0/LCD1_D0/SMC_A4 (io), H2 GPIO2_A2/LCD1_D2/SMC_A6 (io), J2 GPIO2_A1/LCD1_D1/SMC_A5 (io), J3 GPIO2_C0/LCD1_D16/GPS_CLK/TS_CLKO (io), K1 GPIO2_C3/LCD1_D19/SPI1_CLK/TS_D0 (io), K2 GPIO2_B7/LCD1_D14/SMC_A19/TS_D7 (io), K3 GPIO2_C1/LCD1_D17/SMC_BIS_N0/TS_D6 (io), K4 GPIO2_C2/LCD1_D18/SMC_BIS_N1/TS_D5 (io), K5 GPIO2_B5/LCD1_D13/SMC_A17/TS_VALID (io), K6 GPIO2_B6/LCD1_D14/SMC_A18/TS_SYNC (io), L2 GPIO2_C7/LCD1_D23/SPI1_CSN1/TS_D4 (io), L3 GPIO2_C4/LCD1_D20/SPI1_CSN0/TS_D1 (io), L5 GPIO2_C6/LCD1_D22/SPI1_RXD/TS_D3 (io), L6 GPIO2_C5/LCD1_D21/SPI1_RXD/TS_D2 (io), L7 LCD1_VCC (power)
part C pins: L1 CIF0_D5 (in), L4 CIF0_D2 (in), M2 CIF0_D4 (in), M3 CIF0_CLKIN (in), M7 CIF0_VCC (power), N1 CIF0_D7 (in), N2 CIF0_D3 (in), N3 CIF0_D8 (in), N4 CIF0_VSYNC (in), P1 CIF0_D9 (in), P4 GPIO3_A3/I2C3_SCL (io), R2 CIF0_HREF (in), T2 GPIO1_B6/CIF0_D10 (io), T3 GPIO1_B7/CIF0_D11 (io), T4 GPIO1_B3/CIF0_CLKO (io), U1 GPIO3_A2/I2C3_SDA (io), U2 GPIO1_B4/CIF0_D0 (io), U4 CIF0_D6 (in), V4 GPIO1_B5/CIF0_D1 (io)
part D pins: N6 CIF1_VCC (power), P2 GPIO1_C2/CIF1_D4/RMII_TXD1 (io), P3 GPIO1_C7/CIF1_D9/RMII_RXD0 (io), R3 GPIO1_D2/CIF1_CLKIN (io), T1 GPIO1_D6/CIF1_D11 (io), U3 GPIO1_C4/CIF1_D6/RMII_RX_ERR (io), V2 GPIO1_C1/CIF1_D3/RMII_TX_EN (io), V3 GPIO1_D0/CIF1_VSYNC/MII_MD (io), W1 GPIO1_C3/CIF1_D5/RMII_TXD0 (io), W2 GPIO1_C6/CIF1_D8/RMII_RXD1 (io), W3 GPIO1_D7/CIF1_CLKO (io), W4 GPIO3_A5/I2C4_SCL (io), W6 GPIO3_A4/I2C4_SDA (io), Y1 GPIO1_C0/CIF1_D2/RMII_CLKO (io), Y3 GPIO1_C5/CIF1_D7/RMII_CRS_DVALID (io), Y4 GPIO1_D1/CIF1_HREF/MII_MDCLK (io)
part E pins: AA3 CLKIN_32K (in), AA4 CPU_PWROFF (out), AA5 GPIO6_B2, AA6 GPIO6_A4, AA7 GPIO6_A6, AA8 GPIO6_A5, AA9 GPIO6_A7, AA10 GPIO6_B0, AB4 GPIO6_A0, AB9 GPIO6_A3, AB11 XOUT24M (out), AC11 XIN24M (in), T11 AVSS_APLL (power), T12 AVSS_DPLL (power), T13 AVSS_C/GPLL (power), U10 APLL_1V1 (power), U11 DPLL_1V1 (power), U12 C/GPLL_1V1 (power), U13 PVDD_1V1 (power), V13 PVCC_3V3 (power), W7 CORE_PWROFF (out), W8 GPIO6_B1, W14 EFUSE (in), Y5 NPOR (in), Y6 GPIO6_B3, Y7 GPIO6_A1, Y8 GPIO6_A2
part F pins: AA2 SARADC_ANI0 (in), AB1 SARADC_ANI2 (in), AB2 OTG_ID (in), AB14 OTG_RKELVIN (out), AB16 OTG_DM (io), AB17 HOST_DM (io), AC16 OTG_DP (io), AC17 HOST_DP (io), G18 TDI/CPR_BYPASS (in), G20 RECOVER (in), G21 TMS/PLL_BYPASS (io), G23 TCK/HSSCAN_SHIFT_CLOCK (in), H18 GPIO0_A6/HOST_DRV (io), H20 TRSTN (in), H22 TDO (out), J22 GPIO0_A5/OTG_DRV (io), U14 USBVDD_1V1 (power), U15 USBVDD_2V5 (power), V11 ADCVDD_2V5 (power), V14 USBVDD_3V3 (power), W11 OTG_VBUS (in), Y2 SARADC_ANI1 (in), Y11 HOST_RKELVIN (out)
part G pins: AA11 GPIO1_A4/UART1_RX/SPI0_CSN0 (io), AB3 GPIO1_A5/UART1_TX/SPI0_CLK (io), AB5 GPIO1_A7/UART1_RTSN/SPI0_TXD (io), AC4 GPIO1_A6/UART1_CTSN/SPI0_RXD (io), V16 AP1_VCC (power), W10 GPIO4_B7/SPI0_CSN1 (io)
part H pins: AA22 GPIO3_B0/SDMMC0_CLKOUT (io), AB22 GPIO3_B1/SDMMC0_CMD (io), AC22 GPIO3_B2/SDMMC0_D0 (io), AC23 GPIO3_B3/SDMMC0_D1 (io), K18 GPIO3_B5/SDMMC0_D3 (io), L18 GPIO3_B6/SDMMC0_DET (io), R21 GPIO3_B4/SDMMC0_D2 (io), T20 GPIO3_A6/SDMMC0_RSTNO (io), W22 GPIO3_B7/SDMMC0_WP (io), Y22 GPIO3_A7/SDMMC0_PWREN (io)
part I pins: AA12 GPIO3_C5/SDMMC1_CLKO (io), AA13 GPIO3_C4/SDMMC1_D3 (io), AA14 GPIO3_C2/SDMMC1_D1 (io), AA15 GPIO3_C1/SDMMC1_D0 (io), AB6 GPIO3_D2/SDMMC1_INT (io), AB7 GPIO3_D0/SDMMC1_PWREN (io), AB8 GPIO3_C7/SDMMC1_WP (io), AB12 GPIO1_A0/UART0_SIN (io), AB13 GPIO3_C0/SDMMC1_CMD (io), AC1 GPIO0_C5/I2S1_SDO (io), AC2 GPIO1_A1/UART0_SOUT (io), AC7 GPIO0_C0/I2S1_CLK (io), U16 AP0_VCC (power), V17 GPIO0_C1/I2S1_SCLK (io), V19 GPIO0_C2/I2S1_LRCK_RX (io), W13 GPIO1_A3/UART0_RTS (io), W16 GPIO0_C3/I2S1_LRCK_TX (io), W18 GPIO1_A2/UART0_CTS (io), Y10 GPIO3_C6/SDMMC1_DET (io), Y13 GPIO3_D1/SDMMC1_BACKEND (io), Y14 GPIO3_C3/SDMMC1_D2 (io), Y17 GPIO0_C4/I2S1_SDI (io)
part J pins: AA18 GPIO4_D0/SMC_D8/TRACE_D8 (io), AA19 GPIO4_D3/SMC_D11/TRACE_D11 (io), AA20 GPIO0_C6/SMC_A2/TRACE_CLK (io), AB15 GPIO4_C7/SMC_D7/TRACE_D7 (io), AB18 GPIO4_D2/SMC_D10/TRACE_D10 (io), AB19 GPIO4_D5/SMC_D13/TRACE_D13 (io), AB20 GPIO0_C7/SMC_A3/TRACE_CTL (io), AC5 GPIO4_C0/SMC_D0/TRACE_D0 (io), AC8 GPIO4_C1/SMC_D1/TRACE_D1 (io), AC10 GPIO4_C2/SMC_D2/TRACE_D2 (io), AC13 GPIO4_C5/SMC_D5/TRACE_D5 (io), AC14 GPIO4_C3/SMC_D3/TRACE_D3 (io), AC19 GPIO4_D4/SMC_D12/TRACE_D12 (io), AC20 GPIO0_D4/I2S2_SDI/SMC_A0 (io), P19 GPIO0_D1/I2S2_SCLK/SMC_WEN (io), R17 SMC_VCC (power), U18 GPIO0_D2/I2S2_LRCK_RX/SMC_OEN (io), V21 GPIO0_D0/I2S2_CLK/SMC_CSN0 (io), W17 GPIO4_C4/SMC_D4/TRACE_D4 (io), W21 GPIO0_D5/I2S2_SDO/SMC_A1 (io), Y16 GPIO4_C6/SMC_D6/TRACE_D6 (io), Y18 GPIO4_D1/SMC_D9/TRACE_D9 (io), Y19 GPIO4_D6/SMC_D14/TRACE_D14 (io), Y20 GPIO4_D7/SMC_D15/TRACE_D15 (io), Y21 GPIO0_D3/I2S2_LRCK_TX/SMC_ADVN (io)
part K pins: AA21 FLASH_RDY (out), AB21 FLASH_ALE (out), AB23 GPIO4_B1/FLASH_CS2/EMMC_CMD (io), L19 GPIO3_D7/FLASH_DQS/EMMC_CLKO (io), L20 GPIO4_B2/FLASH_CS3/EMMC_RST (io), N17 FLASH_VCC (power), N18 FLASH_D3/EMMC_D3 (io), N19 FLASH_WRN (out), N20 FLASH_D4/EMMC_D4 (io), N21 FLASH_WP/EMMC_PWREN (out), P18 FLASH_D2/EMMC_D2 (io), P20 FLASH_D0/EMMC_D0 (io), T18 FLASH_D1/EMMC_D1 (io), U19 FLASH_D6/EMMC_D6 (io), U22 GPIO4_B0/FLASH_CS1 (io), V20 FLASH_D5/EMMC_D5 (io), V22 FLASH_RDN (out), W20 FLASH_D7/EMMC_D7 (io), W23 FLASH_CLE (out), Y23 FLASH_CS0 (out)
part L pins: K19 GPIO0_A7/I2S0_SDI (io), K20 GPIO0_B3/I2S0_LRCK_TX (io), L21 GPIO0_B5/I2S0_D1 (io), M21 GPIO0_B4/I2S0_D0 (io), P21 GPIO0_B2/I2S0_LRCK_RX (io), P22 GPIO0_B0/I2S0_CLK (io), P23 GPIO0_B1/I2S0_SCLK (io), T22 GPIO0_B6/I2S0_D2 (io), U21 GPIO0_B7/I2S0_D3 (io), U23 GPIO1_B2/SPDIF_TX (io)
part M pins: G22 GPIO2_D4/I2C0_SDA (io), H21 GPIO2_D5/I2C0_SCL (io), H23 GPIO0_D7/PWM3 (io), J21 GPIO0_A4/PWM1 (io), K21 GPIO0_D6/PWM2 (io), K22 GPIO0_A3/PWM0 (io), L22 GPIO3_D6/UART3_RTS (io), L23 GPIO3_D5/UART3_CTS (io), M22 GPIO3_D4/UART3_SOUT (io), N22 GPIO3_D3/UART3_SIN (io), N23 GPIO3_A1/I2C2_SCL (io), R22 GPIO2_D7/I2C1_SCL (io), T19 GPIO1_B0/UART2_SIN (io), T21 GPIO2_D6/I2C1_SDA (io), T23 GPIO1_B1/UART2_SOUT (io), U20 GPIO3_A0/I2C2_SDA (io)
part N pins: A7 DDR_D27 (io), A8 DDR_DQS3n (out), A10 DDR_D31 (io), A11 DDR_DQS1n (out), A13 DDR_D14 (io), A14 DDR_WEn (out), A16 DDR_CLKn (out), A17 DDR_A5 (out), A19 DDR_A8 (out), A20 DDR_A9 (out), A22 DDR_DQS2n (out), A23 DDR_A10 (out), B7 DDR_D26 (io), B8 DDR_DQS3 (out), B9 DDR_D29 (io), B10 DDR_DM1 (out), B11 DDR_DQS1 (out), B12 DDR_D13 (io), B13 DDR_D15 (io), B14 DDR_CS0 (out), B15 DDR_CASn (out), B16 DDR_CLK (out), B17 DDR_A6 (out), B18 DDR_A7 (out), B19 DDR_A11 (out), B20 DDR_A13 (out), B21 DDR_A12 (out), B22 DDR_DQS2 (out), B23 DDR_D17 (io), C7 DDR_D24 (io), C8 DDR_D25 (io), C9 DDR_D30 (io), C10 DDR_D8 (io), C11 DDR_D12 (io), C12 DDR_RASn (out), C13 DDR_CKE0 (out), C14 DDR_A0 (out), C15 DDR_A2 (out), C17 DDR_A3 (out), C18 DDR_ODT1 (out), C19 DDR_ODT0 (out), C20 DDR_A14 (out), C21 DDR_D20 (io), C22 DDR_D16 (io), D7 DDR_DM3 (out), D8 DDR_D9 (io), D10 DDR_D11 (io), D11 DDR_BA0 (out), D13 DDR_BA2 (out), D14 DDR_A1 (out), D16 DDR_DM2 (out), D17 DDR_D18 (io), D18 DDR_D19 (io), D19 DDR_D21 (io), D21 DDR_D22 (io), D22 DDR_DM0 (out), D23 DDR_D0 (io), E7 DDR_D28 (io), E8 DDR_D10 (io), E10 DDR_CKE1 (out), E11 DDR_BA1 (out), E13 DDR_RESET (out), E14 DDR_CS1 (out), E16 DDR_A4 (out), E17 DDR_D23 (io), E18 DDR_D3 (io), E20 DDR_D7 (io), E21 DDR_D4 (io), E22 DDR_DQS0 (out), E23 DDR_DQS0n (out), F10 MVDD1 (power), F11 MVDD2 (power), F13 DDR_VREF (power), F14 MVDD3 (power), F16 MVDD4 (power), F17 MVDD5 (power), F19 DDR_D1 (io), F20 DDR_D2 (io), F21 DDR_D6 (io), F22 DDR_D5 (io), G10 MVDD6 (power), G13 MVDD7 (power), G14 MVDD8 (power), G15 DDR_PZQ (in)
part O pins: A1 HDMI_TX2 (out), A2 HDMI_TX1 (out), A4 HDMI_TX0 (out), A5 HDM I_TXC (out), B1 HDMI_TX2n (out), B2 HDMI_TX1n (out), B3 HDMIAVSS1 (power), B4 HDMI_TX0n (out), B5 HDM I_TXCn (out), B6 HDMIAVSS2 (power), C5 HDMIAVSS3 (power), C6 HDM I_REXT (out), F7 VDD11_HDMI (power), F8 VDD25_HDMI (power), G8 HDMIAVSS4 (power), G9 HDMIAVSS5 (power), G19 GPIO0_A1/HDMI_I2C_SCL (io), H19 GPIO0_A2/HDMI_I2C_SDA (io), K23 GPIO0_A0/HDMI_HOT_PLUG_IN (io)
part P pins: G11 CVDD1 (power), G16 CVDD2 (power), H7 CVDD3 (power), H17 VCCIO2 (power), J17 CVDD4 (power), K17 VCCIO1 (power), L17 CVDD5 (power), N5 AVDD1 (power), N7 CVDD6 (power), P5 AVDD2 (power), P6 AVDD3 (power), P17 CVDD7 (power), T5 AVDD4 (power), T6 AVDD5 (power), T17 CVDD8 (power), U5 AVDD6 (power), U6 AVDD7 (power), U8 AVDD9 (power), U9 AVDD10 (power), V5 AVDD8 (power), V7 AVDD11 (power), V8 AVDD12 (power), V10 AVDD_COM (out)
part Q pins: AA16 VSS86 (power), AA17 VSS87 (power), AB10 VSS88 (power), C16 VSS1 (power), D20 VSS2 (power), G12 VSS3 (power), H8 VSS4 (power), H9 VSS5 (power), H10 VSS6 (power), H11 VSS7 (power), H12 VSS8 (power), H13 VSS9 (power), H14 VSS10 (power), H15 VSS11 (power), H16 VSS12 (power), J8 VSS13 (power), J9 VSS14 (power), J10 VSS15 (power), J11 VSS16 (power), J12 VSS17 (power), J13 VSS18 (power), J14 VSS19 (power), J15 VSS20 (power), J16 VSS21 (power), K8 VSS22 (power), K9 VSS23 (power), K10 VSS24 (power), K11 VSS25 (power), K12 VSS26 (power), K13 VSS27 (power), K14 VSS28 (power), K15 VSS29 (power), K16 VSS30 (power), L8 VSS31 (power), L9 VSS32 (power), L10 VSS33 (power), L11 VSS34 (power), L12 VSS35 (power), L13 VSS36 (power), L14 VSS37 (power), L15 VSS38 (power), L16 VSS39 (power), M8 VSS40 (power), M9 VSS41 (power), M10 VSS42 (power), M11 VSS43 (power), M12 VSS44 (power), M13 VSS45 (power), M14 VSS46 (power), M15 VSS47 (power), M16 VSS48 (power), M17 VSS49 (power), N8 VSS50 (power), N9 VSS51 (power), N10 VSS52 (power), N11 VSS53 (power), N12 VSS54 (power), N13 VSS55 (power), N14 VSS56 (power), N15 VSS57 (power), N16 VSS58 (power), P7 VSS59 (power), P8 VSS60 (power), P9 VSS61 (power), P10 VSS62 (power), P11 VSS63 (power), P12 VSS64 (power), P13 VSS65 (power), P14 VSS66 (power), P15 VSS67 (power), P16 VSS68 (power), R7 VSS69 (power), R8 VSS70 (power), R9 VSS71 (power), R10 VSS72 (power), R11 VSS73 (power), R12 VSS74 (power), R13 VSS75 (power), R14 VSS76 (power), R15 VSS77 (power), R16 VSS78 (power), T7 VSS79 (power), T8 VSS80 (power), T9 VSS81 (power), T10 VSS82 (power), T14 VSS83 (power), T15 VSS84 (power), T16 VSS85 (power)



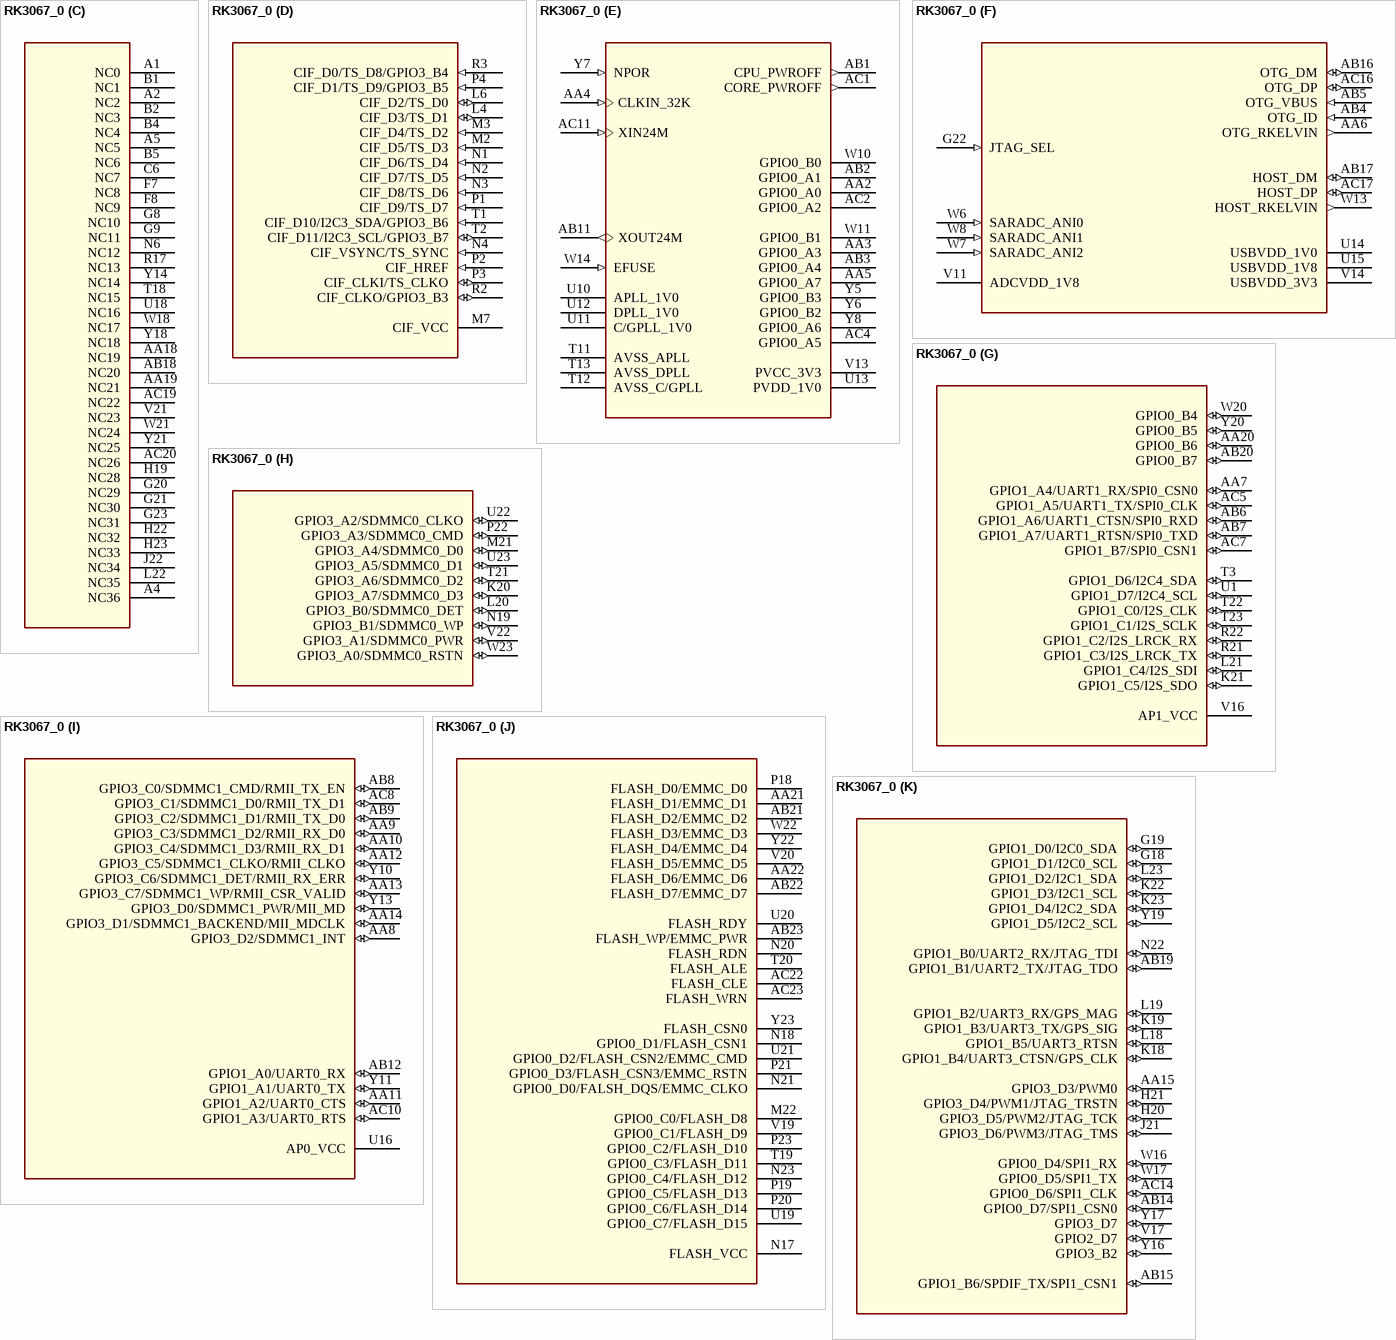
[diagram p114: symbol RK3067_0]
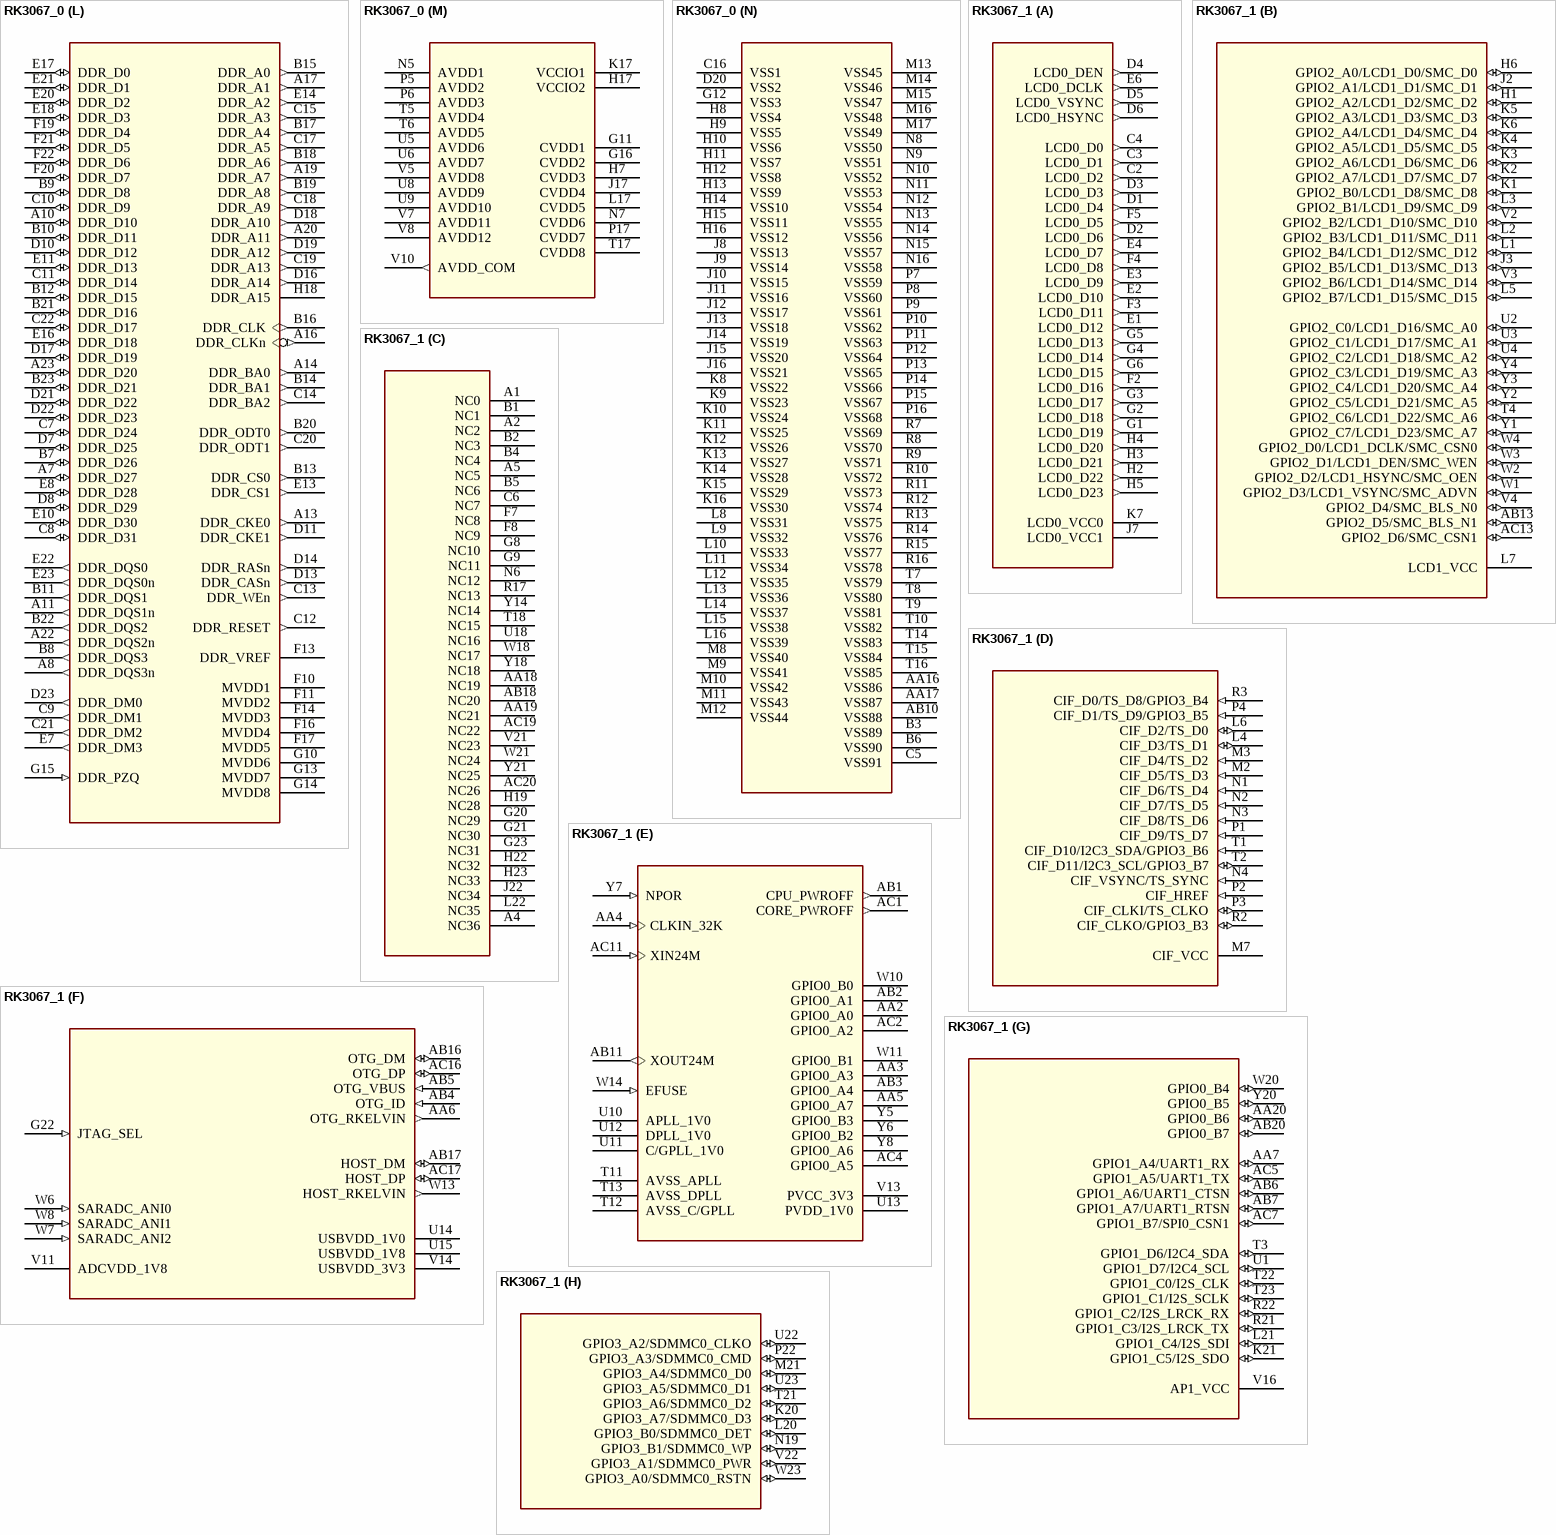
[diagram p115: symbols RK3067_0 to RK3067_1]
## RK3067_0
designator U?
footprint BGA453-19X19
part A pins: C2 LCD0_D2 (out), C3 LCD0_D1 (out), C4 LCD0_D0 (out), D1 LCD0_D4 (out), D2 LCD0_D6 (out), D3 LCD0_D3 (out), D4 LCD0_DEN (out), D5 LCD0_VSYNC (out), D6 LCD0_HSYNC (out), E1 LCD0_D12 (out), E2 LCD0_D10 (out), E3 LCD0_D9 (out), E4 LCD0_D7 (out), E6 LCD0_DCLK (out), F2 LCD0_D16 (out), F3 LCD0_D11 (out), F4 LCD0_D8 (out), F5 LCD0_D5 (out), G1 LCD0_D19 (out), G2 LCD0_D18 (out), G3 LCD0_D17 (out), G4 LCD0_D14 (out), G5 LCD0_D13 (out), G6 LCD0_D15 (out), H2 LCD0_D22 (out), H3 LCD0_D21 (out), H4 LCD0_D20 (out), H5 LCD0_D23 (out), J7 LCD0_VCC1 (power), K7 LCD0_VCC0 (power)
part B pins: AB13 GPIO2_D5/SMC_BLS_N1 (io), AC13 GPIO2_D6/SMC_CSN1 (io), H1 GPIO2_A2/LCD1_D2/SMC_D2 (io), H6 GPIO2_A0/LCD1_D0/SMC_D0 (io), J2 GPIO2_A1/LCD1_D1/SMC_D1 (io), J3 GPIO2_B5/LCD1_D13/SMC_D13 (io), K1 GPIO2_B0/LCD1_D8/SMC_D8 (io), K2 GPIO2_A7/LCD1_D7/SMC_D7 (io), K3 GPIO2_A6/LCD1_D6/SMC_D6 (io), K4 GPIO2_A5/LCD1_D5/SMC_D5 (io), K5 GPIO2_A3/LCD1_D3/SMC_D3 (io), K6 GPIO2_A4/LCD1_D4/SMC_D4 (io), L1 GPIO2_B4/LCD1_D12/SMC_D12 (io), L2 GPIO2_B3/LCD1_D11/SMC_D11 (io), L3 GPIO2_B1/LCD1_D9/SMC_D9 (io), L5 GPIO2_B7/LCD1_D15/SMC_D15 (io), L7 LCD1_VCC (power), T4 GPIO2_C6/LCD1_D22/SMC_A6 (io), U2 GPIO2_C0/LCD1_D16/SMC_A0 (io), U3 GPIO2_C1/LCD1_D17/SMC_A1 (io), U4 GPIO2_C2/LCD1_D18/SMC_A2 (io), V2 GPIO2_B2/LCD1_D10/SMC_D10 (io), V3 GPIO2_B6/LCD1_D14/SMC_D14 (io), V4 GPIO2_D4/SMC_BLS_N0 (io), W1 GPIO2_D3/LCD1_VSYNC/SMC_ADVN (io), W2 GPIO2_D2/LCD1_HSYNC/SMC_OEN (io), W3 GPIO2_D1/LCD1_DEN/SMC_WEN (io), W4 GPIO2_D0/LCD1_DCLK/SMC_CSN0 (io), Y1 GPIO2_C7/LCD1_D23/SMC_A7 (io), Y2 GPIO2_C5/LCD1_D21/SMC_A5 (io), Y3 GPIO2_C4/LCD1_D20/SMC_A4 (io), Y4 GPIO2_C3/LCD1_D19/SMC_A3 (io)
part C pins: A1 NC0, A2 NC2, A4 NC36, A5 NC5, AA18 NC19, AA19 NC21, AB18 NC20, AC19 NC22, AC20 NC26, B1 NC1, B2 NC3, B4 NC4, B5 NC6, C6 NC7, F7 NC8, F8 NC9, G8 NC10, G9 NC11, G20 NC29, G21 NC30, G23 NC31, H19 NC28, H22 NC32, H23 NC33, J22 NC34, L22 NC35, N6 NC12, R17 NC13, T18 NC15, U18 NC16, V21 NC23, W18 NC17, W21 NC24, Y14 NC14, Y18 NC18, Y21 NC25
part D pins: L4 CIF_D3/TS_D1 (io), L6 CIF_D2/TS_D0 (io), M2 CIF_D5/TS_D3 (in), M3 CIF_D4/TS_D2 (in), M7 CIF_VCC (power), N1 CIF_D6/TS_D4 (in), N2 CIF_D7/TS_D5 (in), N3 CIF_D8/TS_D6 (in), N4 CIF_VSYNC/TS_SYNC (in), P1 CIF_D9/TS_D7 (in), P2 CIF_HREF (in), P3 CIF_CLKI/TS_CLKO (io), P4 CIF_D1/TS_D9/GPIO3_B5 (in), R2 CIF_CLKO/GPIO3_B3 (io), R3 CIF_D0/TS_D8/GPIO3_B4 (in), T1 CIF_D10/I2C3_SDA/GPIO3_B6 (in), T2 CIF_D11/I2C3_SCL/GPIO3_B7 (io)
part E pins: AA2 GPIO0_A0, AA3 GPIO0_A3, AA4 CLKIN_32K (in), AA5 GPIO0_A7, AB1 CPU_PWROFF (out), AB2 GPIO0_A1, AB3 GPIO0_A4, AB11 XOUT24M (out), AC1 CORE_PWROFF (out), AC2 GPIO0_A2, AC4 GPIO0_A5, AC11 XIN24M (in), T11 AVSS_APLL (power), T12 AVSS_C/GPLL (power), T13 AVSS_DPLL (power), U10 APLL_1V0 (power), U11 C/GPLL_1V0 (power), U12 DPLL_1V0 (power), U13 PVDD_1V0 (power), V13 PVCC_3V3 (power), W10 GPIO0_B0, W11 GPIO0_B1, W14 EFUSE (in), Y5 GPIO0_B3, Y6 GPIO0_B2, Y7 NPOR (in), Y8 GPIO0_A6
part F pins: AA6 OTG_RKELVIN (out), AB4 OTG_ID (in), AB5 OTG_VBUS (in), AB16 OTG_DM (io), AB17 HOST_DM (io), AC16 OTG_DP (io), AC17 HOST_DP (io), G22 JTAG_SEL (in), U14 USBVDD_1V0 (power), U15 USBVDD_1V8 (power), V11 ADCVDD_1V8 (power), V14 USBVDD_3V3 (power), W6 SARADC_ANI0 (in), W7 SARADC_ANI2 (in), W8 SARADC_ANI1 (in), W13 HOST_RKELVIN (out)
part G pins: AA7 GPIO1_A4/UART1_RX/SPI0_CSN0 (io), AA20 GPIO0_B6 (io), AB6 GPIO1_A6/UART1_CTSN/SPI0_RXD (io), AB7 GPIO1_A7/UART1_RTSN/SPI0_TXD (io), AB20 GPIO0_B7 (io), AC5 GPIO1_A5/UART1_TX/SPI0_CLK (io), AC7 GPIO1_B7/SPI0_CSN1 (io), K21 GPIO1_C5/I2S_SDO (io), L21 GPIO1_C4/I2S_SDI (io), R21 GPIO1_C3/I2S_LRCK_TX (io), R22 GPIO1_C2/I2S_LRCK_RX (io), T3 GPIO1_D6/I2C4_SDA (io), T22 GPIO1_C0/I2S_CLK (io), T23 GPIO1_C1/I2S_SCLK (io), U1 GPIO1_D7/I2C4_SCL (io), V16 AP1_VCC (power), W20 GPIO0_B4 (io), Y20 GPIO0_B5 (io)
part H pins: K20 GPIO3_A7/SDMMC0_D3 (io), L20 GPIO3_B0/SDMMC0_DET (io), M21 GPIO3_A4/SDMMC0_D0 (io), N19 GPIO3_B1/SDMMC0_WP (io), P22 GPIO3_A3/SDMMC0_CMD (io), T21 GPIO3_A6/SDMMC0_D2 (io), U22 GPIO3_A2/SDMMC0_CLKO (io), U23 GPIO3_A5/SDMMC0_D1 (io), V22 GPIO3_A1/SDMMC0_PWR (io), W23 GPIO3_A0/SDMMC0_RSTN (io)
part I pins: AA8 GPIO3_D2/SDMMC1_INT (io), AA9 GPIO3_C3/SDMMC1_D2/RMII_RX_D0 (io), AA10 GPIO3_C4/SDMMC1_D3/RMII_RX_D1 (io), AA11 GPIO1_A2/UART0_CTS (io), AA12 GPIO3_C5/SDMMC1_CLKO/RMII_CLKO (io), AA13 GPIO3_C7/SDMMC1_WP/RMII_CSR_VALID (io), AA14 GPIO3_D1/SDMMC1_BACKEND/MII_MDCLK (io), AB8 GPIO3_C0/SDMMC1_CMD/RMII_TX_EN (io), AB9 GPIO3_C2/SDMMC1_D1/RMII_TX_D0 (io), AB12 GPIO1_A0/UART0_RX (io), AC8 GPIO3_C1/SDMMC1_D0/RMII_TX_D1 (io), AC10 GPIO1_A3/UART0_RTS (io), U16 AP0_VCC (power), Y10 GPIO3_C6/SDMMC1_DET/RMII_RX_ERR (io), Y11 GPIO1_A1/UART0_TX (io), Y13 GPIO3_D0/SDMMC1_PWR/MII_MD (io)
part J pins: AA21 FLASH_D1/EMMC_D1, AA22 FLASH_D6/EMMC_D6, AB21 FLASH_D2/EMMC_D2, AB22 FLASH_D7/EMMC_D7, AB23 FLASH_WP/EMMC_PWR, AC22 FLASH_CLE, AC23 FLASH_WRN, M22 GPIO0_C0/FLASH_D8, N17 FLASH_VCC, N18 GPIO0_D1/FLASH_CSN1, N20 FLASH_RDN, N21 GPIO0_D0/FALSH_DQS/EMMC_CLKO, N23 GPIO0_C4/FLASH_D12, P18 FLASH_D0/EMMC_D0, P19 GPIO0_C5/FLASH_D13, P20 GPIO0_C6/FLASH_D14, P21 GPIO0_D3/FLASH_CSN3/EMMC_RSTN, P23 GPIO0_C2/FLASH_D10, T19 GPIO0_C3/FLASH_D11, T20 FLASH_ALE, U19 GPIO0_C7/FLASH_D15, U20 FLASH_RDY, U21 GPIO0_D2/FLASH_CSN2/EMMC_CMD, V19 GPIO0_C1/FLASH_D9, V20 FLASH_D5/EMMC_D5, W22 FLASH_D3/EMMC_D3, Y22 FLASH_D4/EMMC_D4, Y23 FLASH_CSN0
part K pins: AA15 GPIO3_D3/PWM0 (io), AB14 GPIO0_D7/SPI1_CSN0 (io), AB15 GPIO1_B6/SPDIF_TX/SPI1_CSN1 (io), AB19 GPIO1_B1/UART2_TX/JTAG_TDO (io), AC14 GPIO0_D6/SPI1_CLK (io), G18 GPIO1_D1/I2C0_SCL (io), G19 GPIO1_D0/I2C0_SDA (io), H20 GPIO3_D5/PWM2/JTAG_TCK (io), H21 GPIO3_D4/PWM1/JTAG_TRSTN (io), J21 GPIO3_D6/PWM3/JTAG_TMS (io), K18 GPIO1_B4/UART3_CTSN/GPS_CLK (io), K19 GPIO1_B3/UART3_TX/GPS_SIG (io), K22 GPIO1_D3/I2C1_SCL (io), K23 GPIO1_D4/I2C2_SDA (io), L18 GPIO1_B5/UART3_RTSN (io), L19 GPIO1_B2/UART3_RX/GPS_MAG (io), L23 GPIO1_D2/I2C1_SDA (io), N22 GPIO1_B0/UART2_RX/JTAG_TDI (io), V17 GPIO2_D7 (io), W16 GPIO0_D4/SPI1_RX (io), W17 GPIO0_D5/SPI1_TX (io), Y16 GPIO3_B2 (io), Y17 GPIO3_D7 (io), Y19 GPIO1_D5/I2C2_SCL (io)
part L pins: A7 DDR_D27 (io), A8 DDR_DQS3n (out), A10 DDR_D10 (io), A11 DDR_DQS1n (out), A13 DDR_CKE0 (out), A14 DDR_BA0 (out), A16 DDR_CLKn (out), A17 DDR_A1 (out), A19 DDR_A7 (out), A20 DDR_A11 (out), A22 DDR_DQS2n (out), A23 DDR_D20 (io), B7 DDR_D26 (io), B8 DDR_DQS3 (out), B9 DDR_D8 (io), B10 DDR_D11 (io), B11 DDR_DQS1 (out), B12 DDR_D15 (io), B13 DDR_CS0 (out), B14 DDR_BA1 (out), B15 DDR_A0 (out), B16 DDR_CLK (out), B17 DDR_A4 (out), B18 DDR_A6 (out), B19 DDR_A8 (out), B20 DDR_ODT0 (out), B21 DDR_D16 (io), B22 DDR_DQS2 (out), B23 DDR_D21 (io), C7 DDR_D24 (io), C8 DDR_D31 (io), C9 DDR_DM1 (out), C10 DDR_D9 (io), C11 DDR_D14 (io), C12 DDR_RESET (out), C13 DDR_WEn (out), C14 DDR_BA2 (out), C15 DDR_A3 (out), C17 DDR_A5 (out), C18 DDR_A9 (out), C19 DDR_A13 (out), C20 DDR_ODT1 (out), C21 DDR_DM2 (out), C22 DDR_D17 (io), D7 DDR_D25 (io), D8 DDR_D29 (io), D10 DDR_D12 (io), D11 DDR_CKE1 (out), D13 DDR_CASn (out), D14 DDR_RASn (out), D16 DDR_A14 (out), D17 DDR_D19 (io), D18 DDR_A10 (out), D19 DDR_A12 (out), D21 DDR_D22 (io), D22 DDR_D23 (io), D23 DDR_DM0 (out), E7 DDR_DM3 (out), E8 DDR_D28 (io), E10 DDR_D30 (io), E11 DDR_D13 (io), E13 DDR_CS1 (out), E14 DDR_A2 (out), E16 DDR_D18 (io), E17 DDR_D0 (io), E18 DDR_D3 (io), E20 DDR_D2 (io), E21 DDR_D1 (io), E22 DDR_DQS0 (out), E23 DDR_DQS0n (out), F10 MVDD1 (power), F11 MVDD2 (power), F13 DDR_VREF (power), F14 MVDD3 (power), F16 MVDD4 (power), F17 MVDD5 (power), F19 DDR_D4 (io), F20 DDR_D7 (io), F21 DDR_D5 (io), F22 DDR_D6 (io), G10 MVDD6 (power), G13 MVDD7 (power), G14 MVDD8 (power), G15 DDR_PZQ (in), H18 DDR_A15
part M pins: G11 CVDD1 (power), G16 CVDD2 (power), H7 CVDD3 (power), H17 VCCIO2 (power), J17 CVDD4 (power), K17 VCCIO1 (power), L17 CVDD5 (power), N5 AVDD1 (power), N7 CVDD6 (power), P5 AVDD2 (power), P6 AVDD3 (power), P17 CVDD7 (power), T5 AVDD4 (power), T6 AVDD5 (power), T17 CVDD8 (power), U5 AVDD6 (power), U6 AVDD7 (power), U8 AVDD9 (power), U9 AVDD10 (power), V5 AVDD8 (power), V7 AVDD11 (power), V8 AVDD12 (power), V10 AVDD_COM (out)
part N pins: AA16 VSS86 (power), AA17 VSS87 (power), AB10 VSS88 (power), B3 VSS89 (power), B6 VSS90 (power), C5 VSS91 (power), C16 VSS1 (power), D20 VSS2 (power), G12 VSS3 (power), H8 VSS4 (power), H9 VSS5 (power), H10 VSS6 (power), H11 VSS7 (power), H12 VSS8 (power), H13 VSS9 (power), H14 VSS10 (power), H15 VSS11 (power), H16 VSS12 (power), J8 VSS13 (power), J9 VSS14 (power), J10 VSS15 (power), J11 VSS16 (power), J12 VSS17 (power), J13 VSS18 (power), J14 VSS19 (power), J15 VSS20 (power), J16 VSS21 (power), K8 VSS22 (power), K9 VSS23 (power), K10 VSS24 (power), K11 VSS25 (power), K12 VSS26 (power), K13 VSS27 (power), K14 VSS28 (power), K15 VSS29 (power), K16 VSS30 (power), L8 VSS31 (power), L9 VSS32 (power), L10 VSS33 (power), L11 VSS34 (power), L12 VSS35 (power), L13 VSS36 (power), L14 VSS37 (power), L15 VSS38 (power), L16 VSS39 (power), M8 VSS40 (power), M9 VSS41 (power), M10 VSS42 (power), M11 VSS43 (power), M12 VSS44 (power), M13 VSS45 (power), M14 VSS46 (power), M15 VSS47 (power), M16 VSS48 (power), M17 VSS49 (power), N8 VSS50 (power), N9 VSS51 (power), N10 VSS52 (power), N11 VSS53 (power), N12 VSS54 (power), N13 VSS55 (power), N14 VSS56 (power), N15 VSS57 (power), N16 VSS58 (power), P7 VSS59 (power), P8 VSS60 (power), P9 VSS61 (power), P10 VSS62 (power), P11 VSS63 (power), P12 VSS64 (power), P13 VSS65 (power), P14 VSS66 (power), P15 VSS67 (power), P16 VSS68 (power), R7 VSS69 (power), R8 VSS70 (power), R9 VSS71 (power), R10 VSS72 (power), R11 VSS73 (power), R12 VSS74 (power), R13 VSS75 (power), R14 VSS76 (power), R15 VSS77 (power), R16 VSS78 (power), T7 VSS79 (power), T8 VSS80 (power), T9 VSS81 (power), T10 VSS82 (power), T14 VSS83 (power), T15 VSS84 (power), T16 VSS85 (power)


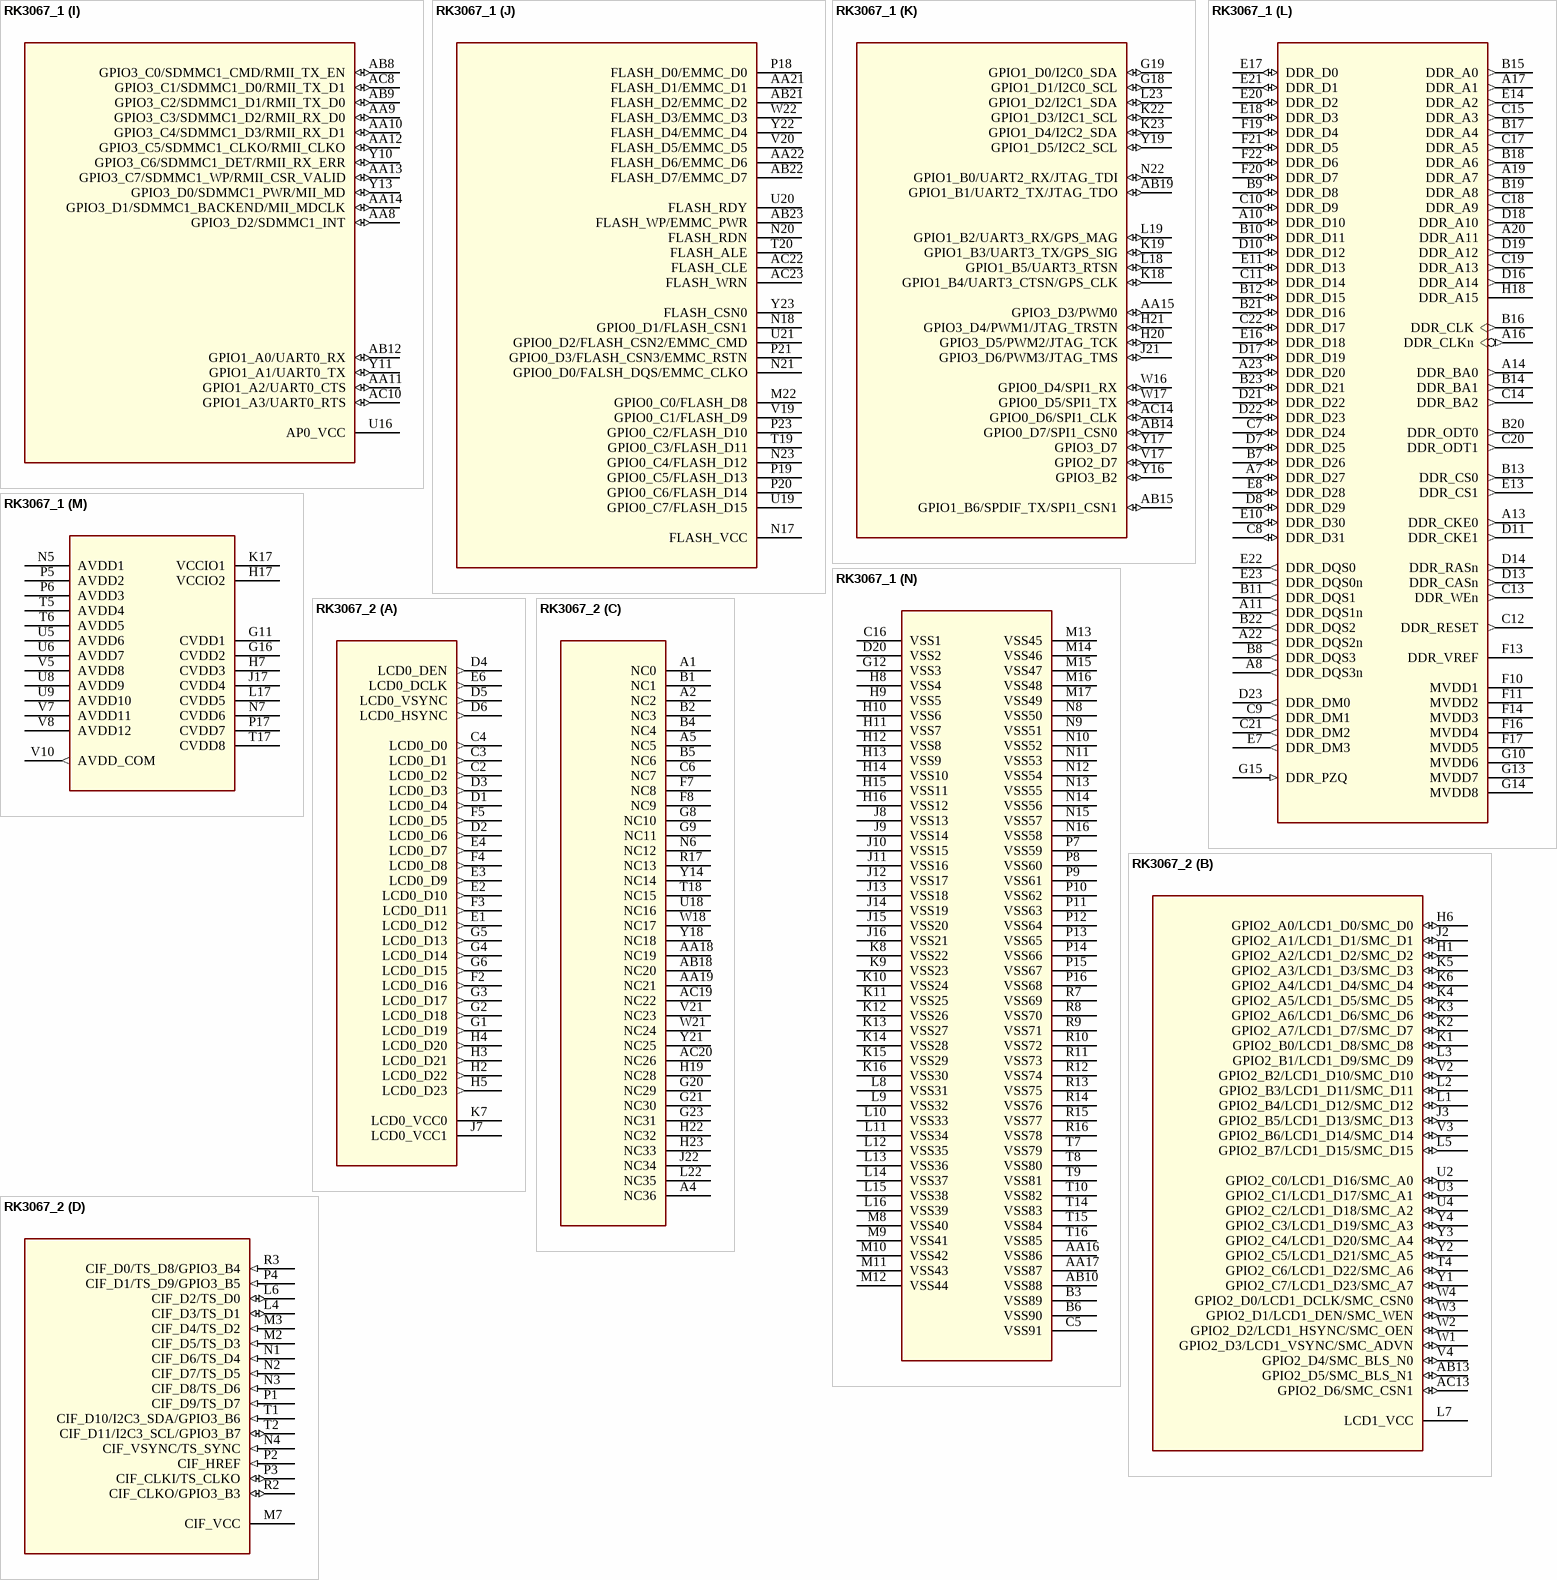
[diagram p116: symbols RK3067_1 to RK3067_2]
## RK3067_1
designator U?
footprint BGA453-19X19
part A pins: C2 LCD0_D2 (out), C3 LCD0_D1 (out), C4 LCD0_D0 (out), D1 LCD0_D4 (out), D2 LCD0_D6 (out), D3 LCD0_D3 (out), D4 LCD0_DEN (out), D5 LCD0_VSYNC (out), D6 LCD0_HSYNC (out), E1 LCD0_D12 (out), E2 LCD0_D10 (out), E3 LCD0_D9 (out), E4 LCD0_D7 (out), E6 LCD0_DCLK (out), F2 LCD0_D16 (out), F3 LCD0_D11 (out), F4 LCD0_D8 (out), F5 LCD0_D5 (out), G1 LCD0_D19 (out), G2 LCD0_D18 (out), G3 LCD0_D17 (out), G4 LCD0_D14 (out), G5 LCD0_D13 (out), G6 LCD0_D15 (out), H2 LCD0_D22 (out), H3 LCD0_D21 (out), H4 LCD0_D20 (out), H5 LCD0_D23 (out), J7 LCD0_VCC1 (power), K7 LCD0_VCC0 (power)
part B pins: AB13 GPIO2_D5/SMC_BLS_N1 (io), AC13 GPIO2_D6/SMC_CSN1 (io), H1 GPIO2_A2/LCD1_D2/SMC_D2 (io), H6 GPIO2_A0/LCD1_D0/SMC_D0 (io), J2 GPIO2_A1/LCD1_D1/SMC_D1 (io), J3 GPIO2_B5/LCD1_D13/SMC_D13 (io), K1 GPIO2_B0/LCD1_D8/SMC_D8 (io), K2 GPIO2_A7/LCD1_D7/SMC_D7 (io), K3 GPIO2_A6/LCD1_D6/SMC_D6 (io), K4 GPIO2_A5/LCD1_D5/SMC_D5 (io), K5 GPIO2_A3/LCD1_D3/SMC_D3 (io), K6 GPIO2_A4/LCD1_D4/SMC_D4 (io), L1 GPIO2_B4/LCD1_D12/SMC_D12 (io), L2 GPIO2_B3/LCD1_D11/SMC_D11 (io), L3 GPIO2_B1/LCD1_D9/SMC_D9 (io), L5 GPIO2_B7/LCD1_D15/SMC_D15 (io), L7 LCD1_VCC (power), T4 GPIO2_C6/LCD1_D22/SMC_A6 (io), U2 GPIO2_C0/LCD1_D16/SMC_A0 (io), U3 GPIO2_C1/LCD1_D17/SMC_A1 (io), U4 GPIO2_C2/LCD1_D18/SMC_A2 (io), V2 GPIO2_B2/LCD1_D10/SMC_D10 (io), V3 GPIO2_B6/LCD1_D14/SMC_D14 (io), V4 GPIO2_D4/SMC_BLS_N0 (io), W1 GPIO2_D3/LCD1_VSYNC/SMC_ADVN (io), W2 GPIO2_D2/LCD1_HSYNC/SMC_OEN (io), W3 GPIO2_D1/LCD1_DEN/SMC_WEN (io), W4 GPIO2_D0/LCD1_DCLK/SMC_CSN0 (io), Y1 GPIO2_C7/LCD1_D23/SMC_A7 (io), Y2 GPIO2_C5/LCD1_D21/SMC_A5 (io), Y3 GPIO2_C4/LCD1_D20/SMC_A4 (io), Y4 GPIO2_C3/LCD1_D19/SMC_A3 (io)
part C pins: A1 NC0, A2 NC2, A4 NC36, A5 NC5, AA18 NC19, AA19 NC21, AB18 NC20, AC19 NC22, AC20 NC26, B1 NC1, B2 NC3, B4 NC4, B5 NC6, C6 NC7, F7 NC8, F8 NC9, G8 NC10, G9 NC11, G20 NC29, G21 NC30, G23 NC31, H19 NC28, H22 NC32, H23 NC33, J22 NC34, L22 NC35, N6 NC12, R17 NC13, T18 NC15, U18 NC16, V21 NC23, W18 NC17, W21 NC24, Y14 NC14, Y18 NC18, Y21 NC25
part D pins: L4 CIF_D3/TS_D1 (io), L6 CIF_D2/TS_D0 (io), M2 CIF_D5/TS_D3 (in), M3 CIF_D4/TS_D2 (in), M7 CIF_VCC (power), N1 CIF_D6/TS_D4 (in), N2 CIF_D7/TS_D5 (in), N3 CIF_D8/TS_D6 (in), N4 CIF_VSYNC/TS_SYNC (in), P1 CIF_D9/TS_D7 (in), P2 CIF_HREF (in), P3 CIF_CLKI/TS_CLKO (io), P4 CIF_D1/TS_D9/GPIO3_B5 (in), R2 CIF_CLKO/GPIO3_B3 (io), R3 CIF_D0/TS_D8/GPIO3_B4 (in), T1 CIF_D10/I2C3_SDA/GPIO3_B6 (in), T2 CIF_D11/I2C3_SCL/GPIO3_B7 (io)
part E pins: AA2 GPIO0_A0, AA3 GPIO0_A3, AA4 CLKIN_32K (in), AA5 GPIO0_A7, AB1 CPU_PWROFF (out), AB2 GPIO0_A1, AB3 GPIO0_A4, AB11 XOUT24M (out), AC1 CORE_PWROFF (out), AC2 GPIO0_A2, AC4 GPIO0_A5, AC11 XIN24M (in), T11 AVSS_APLL (power), T12 AVSS_C/GPLL (power), T13 AVSS_DPLL (power), U10 APLL_1V0 (power), U11 C/GPLL_1V0 (power), U12 DPLL_1V0 (power), U13 PVDD_1V0 (power), V13 PVCC_3V3 (power), W10 GPIO0_B0, W11 GPIO0_B1, W14 EFUSE (in), Y5 GPIO0_B3, Y6 GPIO0_B2, Y7 NPOR (in), Y8 GPIO0_A6
part F pins: AA6 OTG_RKELVIN (out), AB4 OTG_ID (in), AB5 OTG_VBUS (in), AB16 OTG_DM (io), AB17 HOST_DM (io), AC16 OTG_DP (io), AC17 HOST_DP (io), G22 JTAG_SEL (in), U14 USBVDD_1V0 (power), U15 USBVDD_1V8 (power), V11 ADCVDD_1V8 (power), V14 USBVDD_3V3 (power), W6 SARADC_ANI0 (in), W7 SARADC_ANI2 (in), W8 SARADC_ANI1 (in), W13 HOST_RKELVIN (out)
part G pins: AA7 GPIO1_A4/UART1_RX (io), AA20 GPIO0_B6 (io), AB6 GPIO1_A6/UART1_CTSN (io), AB7 GPIO1_A7/UART1_RTSN (io), AB20 GPIO0_B7 (io), AC5 GPIO1_A5/UART1_TX (io), AC7 GPIO1_B7/SPI0_CSN1 (io), K21 GPIO1_C5/I2S_SDO (io), L21 GPIO1_C4/I2S_SDI (io), R21 GPIO1_C3/I2S_LRCK_TX (io), R22 GPIO1_C2/I2S_LRCK_RX (io), T3 GPIO1_D6/I2C4_SDA (io), T22 GPIO1_C0/I2S_CLK (io), T23 GPIO1_C1/I2S_SCLK (io), U1 GPIO1_D7/I2C4_SCL (io), V16 AP1_VCC (power), W20 GPIO0_B4 (io), Y20 GPIO0_B5 (io)
part H pins: K20 GPIO3_A7/SDMMC0_D3 (io), L20 GPIO3_B0/SDMMC0_DET (io), M21 GPIO3_A4/SDMMC0_D0 (io), N19 GPIO3_B1/SDMMC0_WP (io), P22 GPIO3_A3/SDMMC0_CMD (io), T21 GPIO3_A6/SDMMC0_D2 (io), U22 GPIO3_A2/SDMMC0_CLKO (io), U23 GPIO3_A5/SDMMC0_D1 (io), V22 GPIO3_A1/SDMMC0_PWR (io), W23 GPIO3_A0/SDMMC0_RSTN (io)
part I pins: AA8 GPIO3_D2/SDMMC1_INT (io), AA9 GPIO3_C3/SDMMC1_D2/RMII_RX_D0 (io), AA10 GPIO3_C4/SDMMC1_D3/RMII_RX_D1 (io), AA11 GPIO1_A2/UART0_CTS (io), AA12 GPIO3_C5/SDMMC1_CLKO/RMII_CLKO (io), AA13 GPIO3_C7/SDMMC1_WP/RMII_CSR_VALID (io), AA14 GPIO3_D1/SDMMC1_BACKEND/MII_MDCLK (io), AB8 GPIO3_C0/SDMMC1_CMD/RMII_TX_EN (io), AB9 GPIO3_C2/SDMMC1_D1/RMII_TX_D0 (io), AB12 GPIO1_A0/UART0_RX (io), AC8 GPIO3_C1/SDMMC1_D0/RMII_TX_D1 (io), AC10 GPIO1_A3/UART0_RTS (io), U16 AP0_VCC (power), Y10 GPIO3_C6/SDMMC1_DET/RMII_RX_ERR (io), Y11 GPIO1_A1/UART0_TX (io), Y13 GPIO3_D0/SDMMC1_PWR/MII_MD (io)
part J pins: AA21 FLASH_D1/EMMC_D1, AA22 FLASH_D6/EMMC_D6, AB21 FLASH_D2/EMMC_D2, AB22 FLASH_D7/EMMC_D7, AB23 FLASH_WP/EMMC_PWR, AC22 FLASH_CLE, AC23 FLASH_WRN, M22 GPIO0_C0/FLASH_D8, N17 FLASH_VCC, N18 GPIO0_D1/FLASH_CSN1, N20 FLASH_RDN, N21 GPIO0_D0/FALSH_DQS/EMMC_CLKO, N23 GPIO0_C4/FLASH_D12, P18 FLASH_D0/EMMC_D0, P19 GPIO0_C5/FLASH_D13, P20 GPIO0_C6/FLASH_D14, P21 GPIO0_D3/FLASH_CSN3/EMMC_RSTN, P23 GPIO0_C2/FLASH_D10, T19 GPIO0_C3/FLASH_D11, T20 FLASH_ALE, U19 GPIO0_C7/FLASH_D15, U20 FLASH_RDY, U21 GPIO0_D2/FLASH_CSN2/EMMC_CMD, V19 GPIO0_C1/FLASH_D9, V20 FLASH_D5/EMMC_D5, W22 FLASH_D3/EMMC_D3, Y22 FLASH_D4/EMMC_D4, Y23 FLASH_CSN0
part K pins: AA15 GPIO3_D3/PWM0 (io), AB14 GPIO0_D7/SPI1_CSN0 (io), AB15 GPIO1_B6/SPDIF_TX/SPI1_CSN1 (io), AB19 GPIO1_B1/UART2_TX/JTAG_TDO (io), AC14 GPIO0_D6/SPI1_CLK (io), G18 GPIO1_D1/I2C0_SCL (io), G19 GPIO1_D0/I2C0_SDA (io), H20 GPIO3_D5/PWM2/JTAG_TCK (io), H21 GPIO3_D4/PWM1/JTAG_TRSTN (io), J21 GPIO3_D6/PWM3/JTAG_TMS (io), K18 GPIO1_B4/UART3_CTSN/GPS_CLK (io), K19 GPIO1_B3/UART3_TX/GPS_SIG (io), K22 GPIO1_D3/I2C1_SCL (io), K23 GPIO1_D4/I2C2_SDA (io), L18 GPIO1_B5/UART3_RTSN (io), L19 GPIO1_B2/UART3_RX/GPS_MAG (io), L23 GPIO1_D2/I2C1_SDA (io), N22 GPIO1_B0/UART2_RX/JTAG_TDI (io), V17 GPIO2_D7 (io), W16 GPIO0_D4/SPI1_RX (io), W17 GPIO0_D5/SPI1_TX (io), Y16 GPIO3_B2 (io), Y17 GPIO3_D7 (io), Y19 GPIO1_D5/I2C2_SCL (io)
part L pins: A7 DDR_D27 (io), A8 DDR_DQS3n (out), A10 DDR_D10 (io), A11 DDR_DQS1n (out), A13 DDR_CKE0 (out), A14 DDR_BA0 (out), A16 DDR_CLKn (out), A17 DDR_A1 (out), A19 DDR_A7 (out), A20 DDR_A11 (out), A22 DDR_DQS2n (out), A23 DDR_D20 (io), B7 DDR_D26 (io), B8 DDR_DQS3 (out), B9 DDR_D8 (io), B10 DDR_D11 (io), B11 DDR_DQS1 (out), B12 DDR_D15 (io), B13 DDR_CS0 (out), B14 DDR_BA1 (out), B15 DDR_A0 (out), B16 DDR_CLK (out), B17 DDR_A4 (out), B18 DDR_A6 (out), B19 DDR_A8 (out), B20 DDR_ODT0 (out), B21 DDR_D16 (io), B22 DDR_DQS2 (out), B23 DDR_D21 (io), C7 DDR_D24 (io), C8 DDR_D31 (io), C9 DDR_DM1 (out), C10 DDR_D9 (io), C11 DDR_D14 (io), C12 DDR_RESET (out), C13 DDR_WEn (out), C14 DDR_BA2 (out), C15 DDR_A3 (out), C17 DDR_A5 (out), C18 DDR_A9 (out), C19 DDR_A13 (out), C20 DDR_ODT1 (out), C21 DDR_DM2 (out), C22 DDR_D17 (io), D7 DDR_D25 (io), D8 DDR_D29 (io), D10 DDR_D12 (io), D11 DDR_CKE1 (out), D13 DDR_CASn (out), D14 DDR_RASn (out), D16 DDR_A14 (out), D17 DDR_D19 (io), D18 DDR_A10 (out), D19 DDR_A12 (out), D21 DDR_D22 (io), D22 DDR_D23 (io), D23 DDR_DM0 (out), E7 DDR_DM3 (out), E8 DDR_D28 (io), E10 DDR_D30 (io), E11 DDR_D13 (io), E13 DDR_CS1 (out), E14 DDR_A2 (out), E16 DDR_D18 (io), E17 DDR_D0 (io), E18 DDR_D3 (io), E20 DDR_D2 (io), E21 DDR_D1 (io), E22 DDR_DQS0 (out), E23 DDR_DQS0n (out), F10 MVDD1 (power), F11 MVDD2 (power), F13 DDR_VREF (power), F14 MVDD3 (power), F16 MVDD4 (power), F17 MVDD5 (power), F19 DDR_D4 (io), F20 DDR_D7 (io), F21 DDR_D5 (io), F22 DDR_D6 (io), G10 MVDD6 (power), G13 MVDD7 (power), G14 MVDD8 (power), G15 DDR_PZQ (in), H18 DDR_A15
part M pins: G11 CVDD1 (power), G16 CVDD2 (power), H7 CVDD3 (power), H17 VCCIO2 (power), J17 CVDD4 (power), K17 VCCIO1 (power), L17 CVDD5 (power), N5 AVDD1 (power), N7 CVDD6 (power), P5 AVDD2 (power), P6 AVDD3 (power), P17 CVDD7 (power), T5 AVDD4 (power), T6 AVDD5 (power), T17 CVDD8 (power), U5 AVDD6 (power), U6 AVDD7 (power), U8 AVDD9 (power), U9 AVDD10 (power), V5 AVDD8 (power), V7 AVDD11 (power), V8 AVDD12 (power), V10 AVDD_COM (out)
part N pins: AA16 VSS86 (power), AA17 VSS87 (power), AB10 VSS88 (power), B3 VSS89 (power), B6 VSS90 (power), C5 VSS91 (power), C16 VSS1 (power), D20 VSS2 (power), G12 VSS3 (power), H8 VSS4 (power), H9 VSS5 (power), H10 VSS6 (power), H11 VSS7 (power), H12 VSS8 (power), H13 VSS9 (power), H14 VSS10 (power), H15 VSS11 (power), H16 VSS12 (power), J8 VSS13 (power), J9 VSS14 (power), J10 VSS15 (power), J11 VSS16 (power), J12 VSS17 (power), J13 VSS18 (power), J14 VSS19 (power), J15 VSS20 (power), J16 VSS21 (power), K8 VSS22 (power), K9 VSS23 (power), K10 VSS24 (power), K11 VSS25 (power), K12 VSS26 (power), K13 VSS27 (power), K14 VSS28 (power), K15 VSS29 (power), K16 VSS30 (power), L8 VSS31 (power), L9 VSS32 (power), L10 VSS33 (power), L11 VSS34 (power), L12 VSS35 (power), L13 VSS36 (power), L14 VSS37 (power), L15 VSS38 (power), L16 VSS39 (power), M8 VSS40 (power), M9 VSS41 (power), M10 VSS42 (power), M11 VSS43 (power), M12 VSS44 (power), M13 VSS45 (power), M14 VSS46 (power), M15 VSS47 (power), M16 VSS48 (power), M17 VSS49 (power), N8 VSS50 (power), N9 VSS51 (power), N10 VSS52 (power), N11 VSS53 (power), N12 VSS54 (power), N13 VSS55 (power), N14 VSS56 (power), N15 VSS57 (power), N16 VSS58 (power), P7 VSS59 (power), P8 VSS60 (power), P9 VSS61 (power), P10 VSS62 (power), P11 VSS63 (power), P12 VSS64 (power), P13 VSS65 (power), P14 VSS66 (power), P15 VSS67 (power), P16 VSS68 (power), R7 VSS69 (power), R8 VSS70 (power), R9 VSS71 (power), R10 VSS72 (power), R11 VSS73 (power), R12 VSS74 (power), R13 VSS75 (power), R14 VSS76 (power), R15 VSS77 (power), R16 VSS78 (power), T7 VSS79 (power), T8 VSS80 (power), T9 VSS81 (power), T10 VSS82 (power), T14 VSS83 (power), T15 VSS84 (power), T16 VSS85 (power)



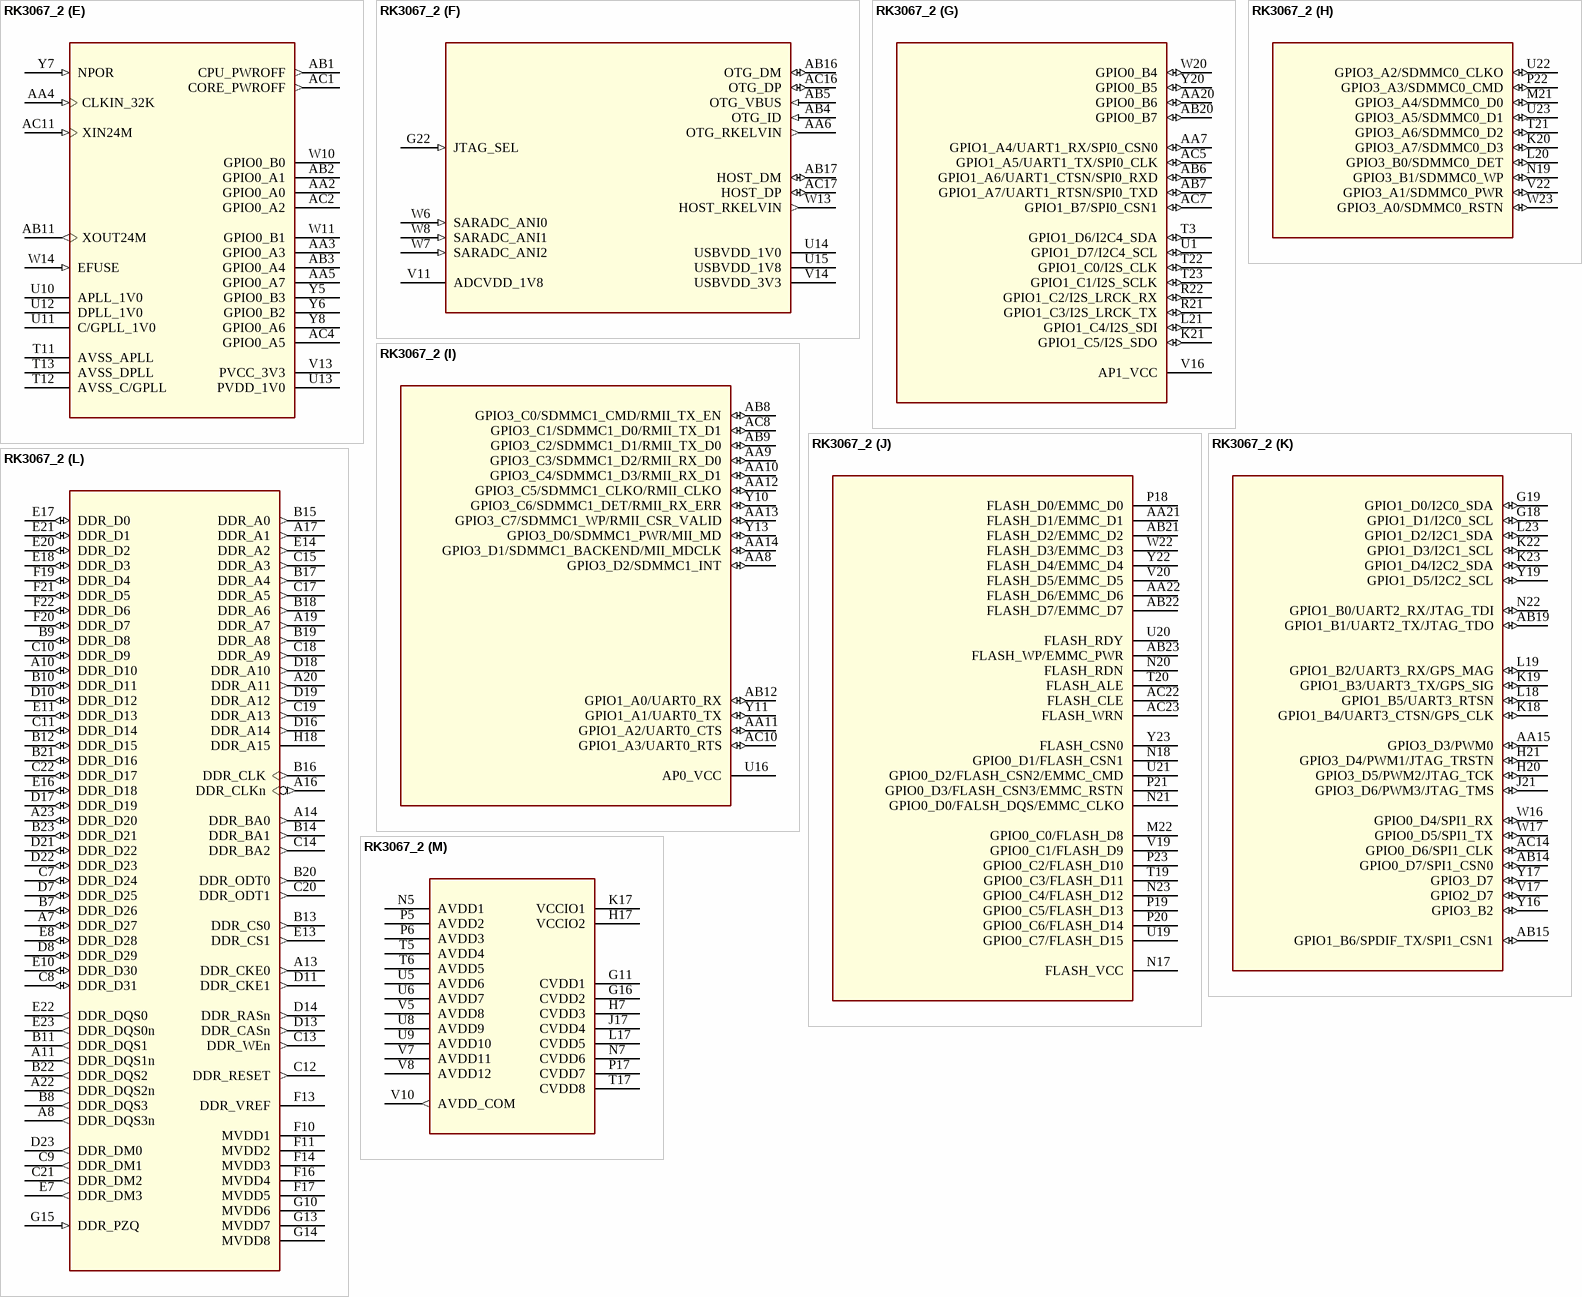
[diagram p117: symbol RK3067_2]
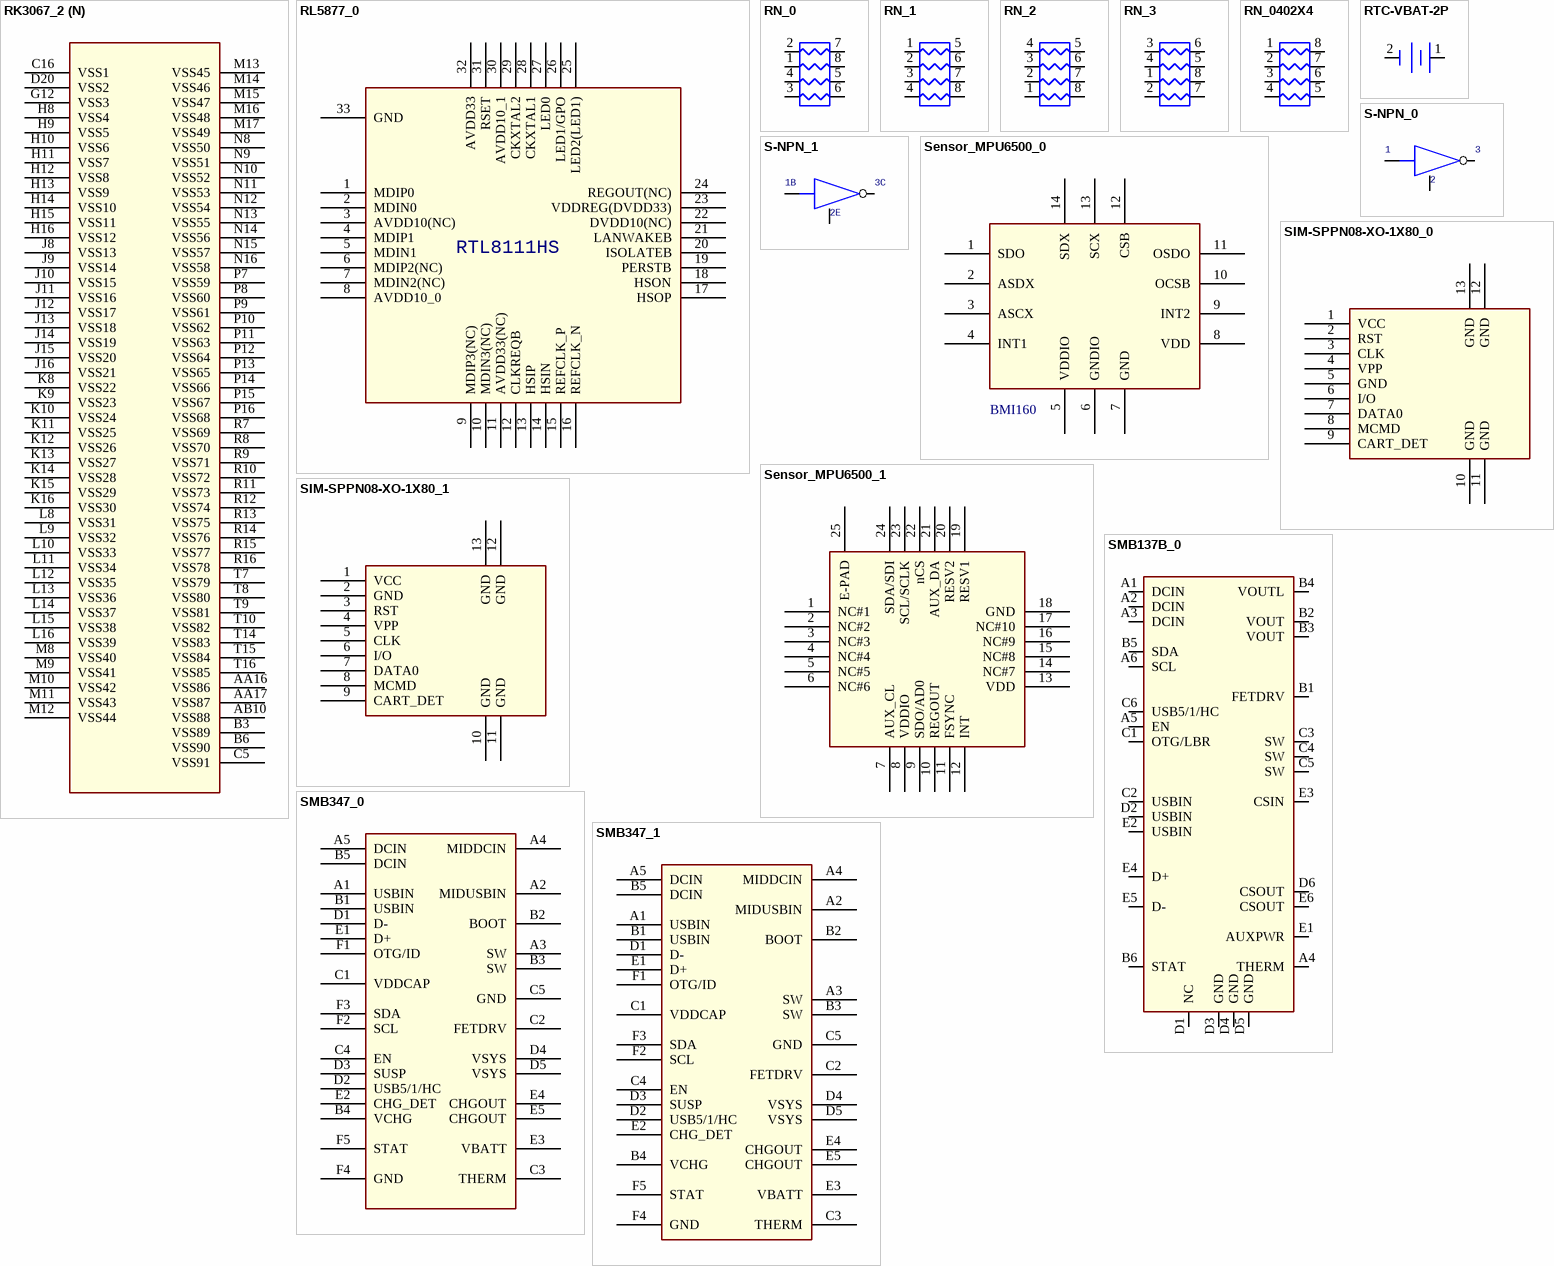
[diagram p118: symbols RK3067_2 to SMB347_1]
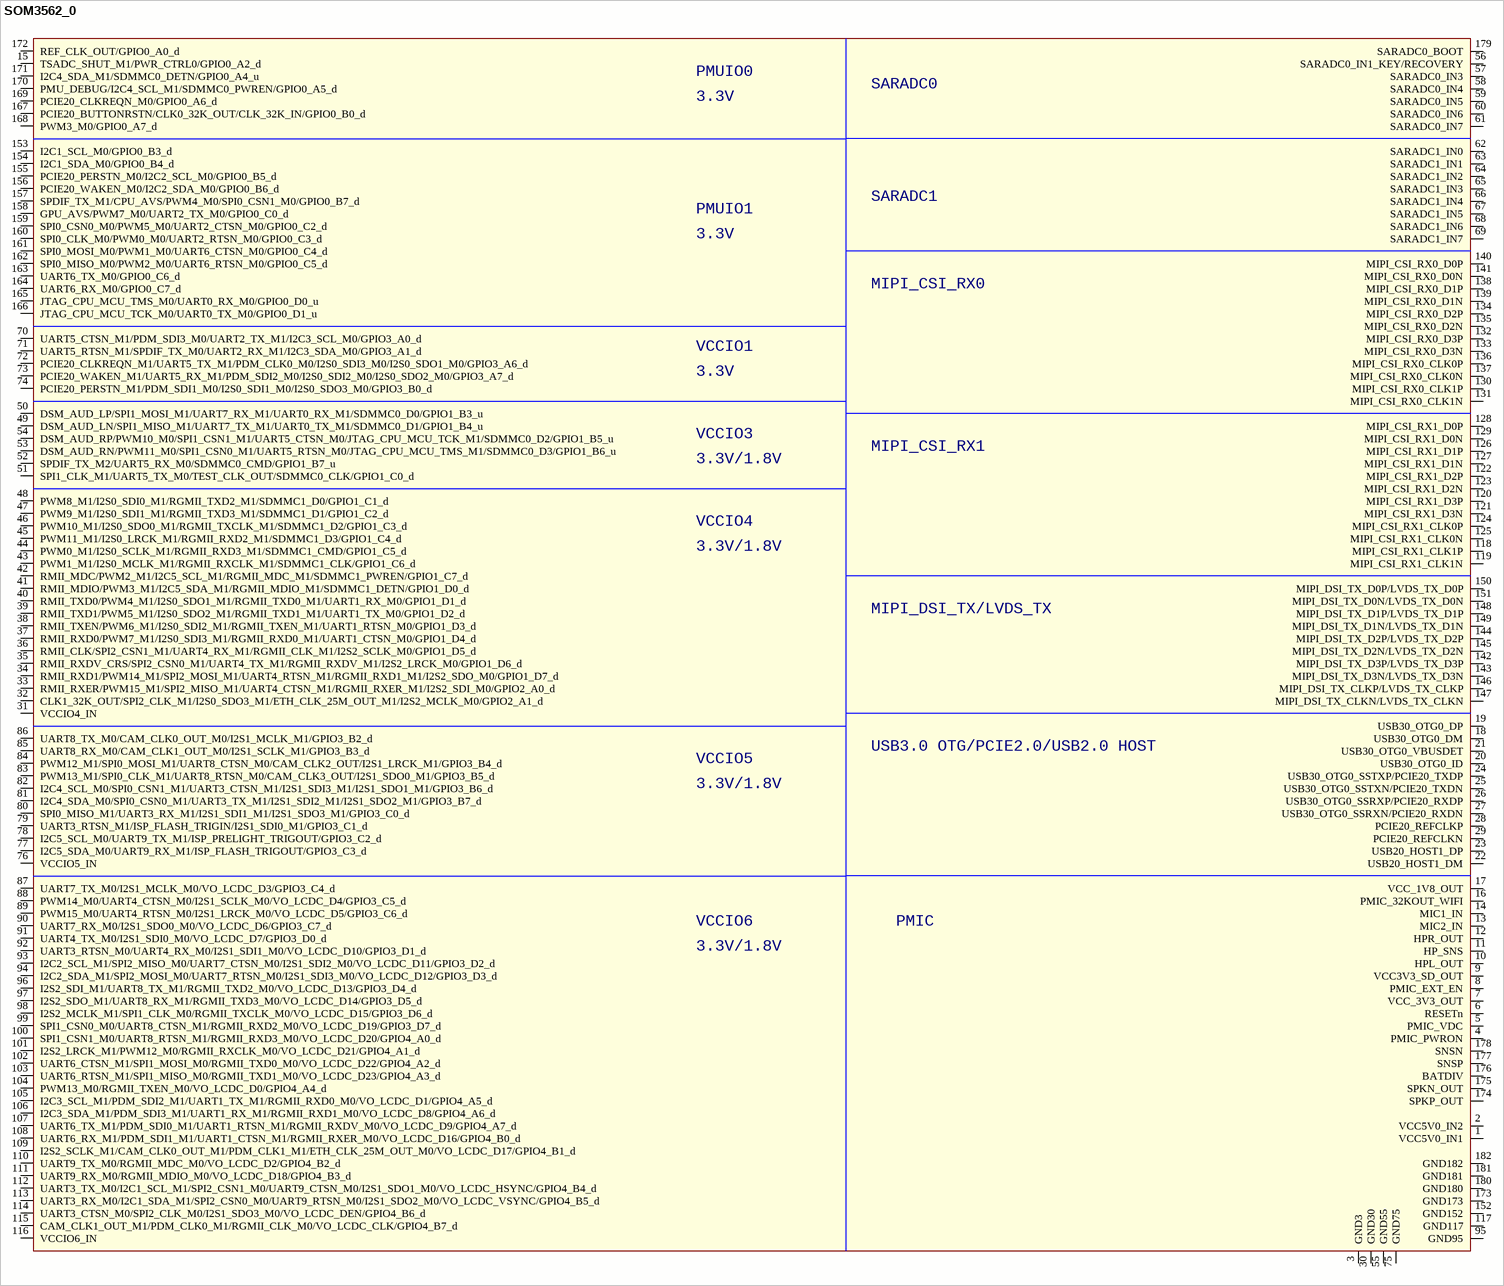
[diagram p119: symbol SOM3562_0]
## RK3067_2
designator U?
footprint BGA453-19X19
part A pins: C2 LCD0_D2 (out), C3 LCD0_D1 (out), C4 LCD0_D0 (out), D1 LCD0_D4 (out), D2 LCD0_D6 (out), D3 LCD0_D3 (out), D4 LCD0_DEN (out), D5 LCD0_VSYNC (out), D6 LCD0_HSYNC (out), E1 LCD0_D12 (out), E2 LCD0_D10 (out), E3 LCD0_D9 (out), E4 LCD0_D7 (out), E6 LCD0_DCLK (out), F2 LCD0_D16 (out), F3 LCD0_D11 (out), F4 LCD0_D8 (out), F5 LCD0_D5 (out), G1 LCD0_D19 (out), G2 LCD0_D18 (out), G3 LCD0_D17 (out), G4 LCD0_D14 (out), G5 LCD0_D13 (out), G6 LCD0_D15 (out), H2 LCD0_D22 (out), H3 LCD0_D21 (out), H4 LCD0_D20 (out), H5 LCD0_D23 (out), J7 LCD0_VCC1 (power), K7 LCD0_VCC0 (power)
part B pins: AB13 GPIO2_D5/SMC_BLS_N1 (io), AC13 GPIO2_D6/SMC_CSN1 (io), H1 GPIO2_A2/LCD1_D2/SMC_D2 (io), H6 GPIO2_A0/LCD1_D0/SMC_D0 (io), J2 GPIO2_A1/LCD1_D1/SMC_D1 (io), J3 GPIO2_B5/LCD1_D13/SMC_D13 (io), K1 GPIO2_B0/LCD1_D8/SMC_D8 (io), K2 GPIO2_A7/LCD1_D7/SMC_D7 (io), K3 GPIO2_A6/LCD1_D6/SMC_D6 (io), K4 GPIO2_A5/LCD1_D5/SMC_D5 (io), K5 GPIO2_A3/LCD1_D3/SMC_D3 (io), K6 GPIO2_A4/LCD1_D4/SMC_D4 (io), L1 GPIO2_B4/LCD1_D12/SMC_D12 (io), L2 GPIO2_B3/LCD1_D11/SMC_D11 (io), L3 GPIO2_B1/LCD1_D9/SMC_D9 (io), L5 GPIO2_B7/LCD1_D15/SMC_D15 (io), L7 LCD1_VCC (power), T4 GPIO2_C6/LCD1_D22/SMC_A6 (io), U2 GPIO2_C0/LCD1_D16/SMC_A0 (io), U3 GPIO2_C1/LCD1_D17/SMC_A1 (io), U4 GPIO2_C2/LCD1_D18/SMC_A2 (io), V2 GPIO2_B2/LCD1_D10/SMC_D10 (io), V3 GPIO2_B6/LCD1_D14/SMC_D14 (io), V4 GPIO2_D4/SMC_BLS_N0 (io), W1 GPIO2_D3/LCD1_VSYNC/SMC_ADVN (io), W2 GPIO2_D2/LCD1_HSYNC/SMC_OEN (io), W3 GPIO2_D1/LCD1_DEN/SMC_WEN (io), W4 GPIO2_D0/LCD1_DCLK/SMC_CSN0 (io), Y1 GPIO2_C7/LCD1_D23/SMC_A7 (io), Y2 GPIO2_C5/LCD1_D21/SMC_A5 (io), Y3 GPIO2_C4/LCD1_D20/SMC_A4 (io), Y4 GPIO2_C3/LCD1_D19/SMC_A3 (io)
part C pins: A1 NC0, A2 NC2, A4 NC36, A5 NC5, AA18 NC19, AA19 NC21, AB18 NC20, AC19 NC22, AC20 NC26, B1 NC1, B2 NC3, B4 NC4, B5 NC6, C6 NC7, F7 NC8, F8 NC9, G8 NC10, G9 NC11, G20 NC29, G21 NC30, G23 NC31, H19 NC28, H22 NC32, H23 NC33, J22 NC34, L22 NC35, N6 NC12, R17 NC13, T18 NC15, U18 NC16, V21 NC23, W18 NC17, W21 NC24, Y14 NC14, Y18 NC18, Y21 NC25
part D pins: L4 CIF_D3/TS_D1 (io), L6 CIF_D2/TS_D0 (io), M2 CIF_D5/TS_D3 (in), M3 CIF_D4/TS_D2 (in), M7 CIF_VCC (power), N1 CIF_D6/TS_D4 (in), N2 CIF_D7/TS_D5 (in), N3 CIF_D8/TS_D6 (in), N4 CIF_VSYNC/TS_SYNC (in), P1 CIF_D9/TS_D7 (in), P2 CIF_HREF (in), P3 CIF_CLKI/TS_CLKO (io), P4 CIF_D1/TS_D9/GPIO3_B5 (in), R2 CIF_CLKO/GPIO3_B3 (io), R3 CIF_D0/TS_D8/GPIO3_B4 (in), T1 CIF_D10/I2C3_SDA/GPIO3_B6 (in), T2 CIF_D11/I2C3_SCL/GPIO3_B7 (io)
part E pins: AA2 GPIO0_A0, AA3 GPIO0_A3, AA4 CLKIN_32K (in), AA5 GPIO0_A7, AB1 CPU_PWROFF (out), AB2 GPIO0_A1, AB3 GPIO0_A4, AB11 XOUT24M (out), AC1 CORE_PWROFF (out), AC2 GPIO0_A2, AC4 GPIO0_A5, AC11 XIN24M (in), T11 AVSS_APLL (power), T12 AVSS_C/GPLL (power), T13 AVSS_DPLL (power), U10 APLL_1V0 (power), U11 C/GPLL_1V0 (power), U12 DPLL_1V0 (power), U13 PVDD_1V0 (power), V13 PVCC_3V3 (power), W10 GPIO0_B0, W11 GPIO0_B1, W14 EFUSE (in), Y5 GPIO0_B3, Y6 GPIO0_B2, Y7 NPOR (in), Y8 GPIO0_A6
part F pins: AA6 OTG_RKELVIN (out), AB4 OTG_ID (in), AB5 OTG_VBUS (in), AB16 OTG_DM (io), AB17 HOST_DM (io), AC16 OTG_DP (io), AC17 HOST_DP (io), G22 JTAG_SEL (in), U14 USBVDD_1V0 (power), U15 USBVDD_1V8 (power), V11 ADCVDD_1V8 (power), V14 USBVDD_3V3 (power), W6 SARADC_ANI0 (in), W7 SARADC_ANI2 (in), W8 SARADC_ANI1 (in), W13 HOST_RKELVIN (out)
part G pins: AA7 GPIO1_A4/UART1_RX/SPI0_CSN0 (io), AA20 GPIO0_B6 (io), AB6 GPIO1_A6/UART1_CTSN/SPI0_RXD (io), AB7 GPIO1_A7/UART1_RTSN/SPI0_TXD (io), AB20 GPIO0_B7 (io), AC5 GPIO1_A5/UART1_TX/SPI0_CLK (io), AC7 GPIO1_B7/SPI0_CSN1 (io), K21 GPIO1_C5/I2S_SDO (io), L21 GPIO1_C4/I2S_SDI (io), R21 GPIO1_C3/I2S_LRCK_TX (io), R22 GPIO1_C2/I2S_LRCK_RX (io), T3 GPIO1_D6/I2C4_SDA (io), T22 GPIO1_C0/I2S_CLK (io), T23 GPIO1_C1/I2S_SCLK (io), U1 GPIO1_D7/I2C4_SCL (io), V16 AP1_VCC (power), W20 GPIO0_B4 (io), Y20 GPIO0_B5 (io)
part H pins: K20 GPIO3_A7/SDMMC0_D3 (io), L20 GPIO3_B0/SDMMC0_DET (io), M21 GPIO3_A4/SDMMC0_D0 (io), N19 GPIO3_B1/SDMMC0_WP (io), P22 GPIO3_A3/SDMMC0_CMD (io), T21 GPIO3_A6/SDMMC0_D2 (io), U22 GPIO3_A2/SDMMC0_CLKO (io), U23 GPIO3_A5/SDMMC0_D1 (io), V22 GPIO3_A1/SDMMC0_PWR (io), W23 GPIO3_A0/SDMMC0_RSTN (io)
part I pins: AA8 GPIO3_D2/SDMMC1_INT (io), AA9 GPIO3_C3/SDMMC1_D2/RMII_RX_D0 (io), AA10 GPIO3_C4/SDMMC1_D3/RMII_RX_D1 (io), AA11 GPIO1_A2/UART0_CTS (io), AA12 GPIO3_C5/SDMMC1_CLKO/RMII_CLKO (io), AA13 GPIO3_C7/SDMMC1_WP/RMII_CSR_VALID (io), AA14 GPIO3_D1/SDMMC1_BACKEND/MII_MDCLK (io), AB8 GPIO3_C0/SDMMC1_CMD/RMII_TX_EN (io), AB9 GPIO3_C2/SDMMC1_D1/RMII_TX_D0 (io), AB12 GPIO1_A0/UART0_RX (io), AC8 GPIO3_C1/SDMMC1_D0/RMII_TX_D1 (io), AC10 GPIO1_A3/UART0_RTS (io), U16 AP0_VCC (power), Y10 GPIO3_C6/SDMMC1_DET/RMII_RX_ERR (io), Y11 GPIO1_A1/UART0_TX (io), Y13 GPIO3_D0/SDMMC1_PWR/MII_MD (io)
part J pins: AA21 FLASH_D1/EMMC_D1, AA22 FLASH_D6/EMMC_D6, AB21 FLASH_D2/EMMC_D2, AB22 FLASH_D7/EMMC_D7, AB23 FLASH_WP/EMMC_PWR, AC22 FLASH_CLE, AC23 FLASH_WRN, M22 GPIO0_C0/FLASH_D8, N17 FLASH_VCC, N18 GPIO0_D1/FLASH_CSN1, N20 FLASH_RDN, N21 GPIO0_D0/FALSH_DQS/EMMC_CLKO, N23 GPIO0_C4/FLASH_D12, P18 FLASH_D0/EMMC_D0, P19 GPIO0_C5/FLASH_D13, P20 GPIO0_C6/FLASH_D14, P21 GPIO0_D3/FLASH_CSN3/EMMC_RSTN, P23 GPIO0_C2/FLASH_D10, T19 GPIO0_C3/FLASH_D11, T20 FLASH_ALE, U19 GPIO0_C7/FLASH_D15, U20 FLASH_RDY, U21 GPIO0_D2/FLASH_CSN2/EMMC_CMD, V19 GPIO0_C1/FLASH_D9, V20 FLASH_D5/EMMC_D5, W22 FLASH_D3/EMMC_D3, Y22 FLASH_D4/EMMC_D4, Y23 FLASH_CSN0
part K pins: AA15 GPIO3_D3/PWM0 (io), AB14 GPIO0_D7/SPI1_CSN0 (io), AB15 GPIO1_B6/SPDIF_TX/SPI1_CSN1 (io), AB19 GPIO1_B1/UART2_TX/JTAG_TDO (io), AC14 GPIO0_D6/SPI1_CLK (io), G18 GPIO1_D1/I2C0_SCL (io), G19 GPIO1_D0/I2C0_SDA (io), H20 GPIO3_D5/PWM2/JTAG_TCK (io), H21 GPIO3_D4/PWM1/JTAG_TRSTN (io), J21 GPIO3_D6/PWM3/JTAG_TMS (io), K18 GPIO1_B4/UART3_CTSN/GPS_CLK (io), K19 GPIO1_B3/UART3_TX/GPS_SIG (io), K22 GPIO1_D3/I2C1_SCL (io), K23 GPIO1_D4/I2C2_SDA (io), L18 GPIO1_B5/UART3_RTSN (io), L19 GPIO1_B2/UART3_RX/GPS_MAG (io), L23 GPIO1_D2/I2C1_SDA (io), N22 GPIO1_B0/UART2_RX/JTAG_TDI (io), V17 GPIO2_D7 (io), W16 GPIO0_D4/SPI1_RX (io), W17 GPIO0_D5/SPI1_TX (io), Y16 GPIO3_B2 (io), Y17 GPIO3_D7 (io), Y19 GPIO1_D5/I2C2_SCL (io)
part L pins: A7 DDR_D27 (io), A8 DDR_DQS3n (out), A10 DDR_D10 (io), A11 DDR_DQS1n (out), A13 DDR_CKE0 (out), A14 DDR_BA0 (out), A16 DDR_CLKn (out), A17 DDR_A1 (out), A19 DDR_A7 (out), A20 DDR_A11 (out), A22 DDR_DQS2n (out), A23 DDR_D20 (io), B7 DDR_D26 (io), B8 DDR_DQS3 (out), B9 DDR_D8 (io), B10 DDR_D11 (io), B11 DDR_DQS1 (out), B12 DDR_D15 (io), B13 DDR_CS0 (out), B14 DDR_BA1 (out), B15 DDR_A0 (out), B16 DDR_CLK (out), B17 DDR_A4 (out), B18 DDR_A6 (out), B19 DDR_A8 (out), B20 DDR_ODT0 (out), B21 DDR_D16 (io), B22 DDR_DQS2 (out), B23 DDR_D21 (io), C7 DDR_D24 (io), C8 DDR_D31 (io), C9 DDR_DM1 (out), C10 DDR_D9 (io), C11 DDR_D14 (io), C12 DDR_RESET (out), C13 DDR_WEn (out), C14 DDR_BA2 (out), C15 DDR_A3 (out), C17 DDR_A5 (out), C18 DDR_A9 (out), C19 DDR_A13 (out), C20 DDR_ODT1 (out), C21 DDR_DM2 (out), C22 DDR_D17 (io), D7 DDR_D25 (io), D8 DDR_D29 (io), D10 DDR_D12 (io), D11 DDR_CKE1 (out), D13 DDR_CASn (out), D14 DDR_RASn (out), D16 DDR_A14 (out), D17 DDR_D19 (io), D18 DDR_A10 (out), D19 DDR_A12 (out), D21 DDR_D22 (io), D22 DDR_D23 (io), D23 DDR_DM0 (out), E7 DDR_DM3 (out), E8 DDR_D28 (io), E10 DDR_D30 (io), E11 DDR_D13 (io), E13 DDR_CS1 (out), E14 DDR_A2 (out), E16 DDR_D18 (io), E17 DDR_D0 (io), E18 DDR_D3 (io), E20 DDR_D2 (io), E21 DDR_D1 (io), E22 DDR_DQS0 (out), E23 DDR_DQS0n (out), F10 MVDD1 (power), F11 MVDD2 (power), F13 DDR_VREF (power), F14 MVDD3 (power), F16 MVDD4 (power), F17 MVDD5 (power), F19 DDR_D4 (io), F20 DDR_D7 (io), F21 DDR_D5 (io), F22 DDR_D6 (io), G10 MVDD6 (power), G13 MVDD7 (power), G14 MVDD8 (power), G15 DDR_PZQ (in), H18 DDR_A15
part M pins: G11 CVDD1 (power), G16 CVDD2 (power), H7 CVDD3 (power), H17 VCCIO2 (power), J17 CVDD4 (power), K17 VCCIO1 (power), L17 CVDD5 (power), N5 AVDD1 (power), N7 CVDD6 (power), P5 AVDD2 (power), P6 AVDD3 (power), P17 CVDD7 (power), T5 AVDD4 (power), T6 AVDD5 (power), T17 CVDD8 (power), U5 AVDD6 (power), U6 AVDD7 (power), U8 AVDD9 (power), U9 AVDD10 (power), V5 AVDD8 (power), V7 AVDD11 (power), V8 AVDD12 (power), V10 AVDD_COM (out)
part N pins: AA16 VSS86 (power), AA17 VSS87 (power), AB10 VSS88 (power), B3 VSS89 (power), B6 VSS90 (power), C5 VSS91 (power), C16 VSS1 (power), D20 VSS2 (power), G12 VSS3 (power), H8 VSS4 (power), H9 VSS5 (power), H10 VSS6 (power), H11 VSS7 (power), H12 VSS8 (power), H13 VSS9 (power), H14 VSS10 (power), H15 VSS11 (power), H16 VSS12 (power), J8 VSS13 (power), J9 VSS14 (power), J10 VSS15 (power), J11 VSS16 (power), J12 VSS17 (power), J13 VSS18 (power), J14 VSS19 (power), J15 VSS20 (power), J16 VSS21 (power), K8 VSS22 (power), K9 VSS23 (power), K10 VSS24 (power), K11 VSS25 (power), K12 VSS26 (power), K13 VSS27 (power), K14 VSS28 (power), K15 VSS29 (power), K16 VSS30 (power), L8 VSS31 (power), L9 VSS32 (power), L10 VSS33 (power), L11 VSS34 (power), L12 VSS35 (power), L13 VSS36 (power), L14 VSS37 (power), L15 VSS38 (power), L16 VSS39 (power), M8 VSS40 (power), M9 VSS41 (power), M10 VSS42 (power), M11 VSS43 (power), M12 VSS44 (power), M13 VSS45 (power), M14 VSS46 (power), M15 VSS47 (power), M16 VSS48 (power), M17 VSS49 (power), N8 VSS50 (power), N9 VSS51 (power), N10 VSS52 (power), N11 VSS53 (power), N12 VSS54 (power), N13 VSS55 (power), N14 VSS56 (power), N15 VSS57 (power), N16 VSS58 (power), P7 VSS59 (power), P8 VSS60 (power), P9 VSS61 (power), P10 VSS62 (power), P11 VSS63 (power), P12 VSS64 (power), P13 VSS65 (power), P14 VSS66 (power), P15 VSS67 (power), P16 VSS68 (power), R7 VSS69 (power), R8 VSS70 (power), R9 VSS71 (power), R10 VSS72 (power), R11 VSS73 (power), R12 VSS74 (power), R13 VSS75 (power), R14 VSS76 (power), R15 VSS77 (power), R16 VSS78 (power), T7 VSS79 (power), T8 VSS80 (power), T9 VSS81 (power), T10 VSS82 (power), T14 VSS83 (power), T15 VSS84 (power), T16 VSS85 (power)

## RL5877_0
designator U?, comment RL5877  (value not drawn)
pins: 1 MDIP0, 2 MDIN0, 3 AVDD10(NC), 4 MDIP1, 5 MDIN1, 6 MDIP2(NC), 7 MDIN2(NC), 8 AVDD10_0, 9 MDIP3(NC), 10 MDIN3(NC), 11 AVDD33(NC), 12 CLKREQB, 13 HSIP (power), 14 HSIN (power), 15 REFCLK_P, 16 REFCLK_N, 17 HSOP, 18 HSON, 19 PERSTB, 20 ISOLATEB, 21 LANWAKEB, 22 DVDD10(NC) (hiz), 23 VDDREG(DVDD33), 24 REGOUT(NC), 25 LED2(LED1), 26 LED1/GPO (hiz), 27 LED0, 28 CKXTAL1, 29 CKXTAL2, 30 AVDD10_1, 31 RSET, 32 AVDD33, 33 GND

## RN_0
designator RN?
pins: 1, 2, 3, 4, 5, 6, 7, 8

## RN_1
designator RN?
pins: 1, 2, 3, 4, 5, 6, 7, 8

## RN_2
designator RN?
pins: 1, 2, 3, 4, 5, 6, 7, 8

## RN_3
designator RN?
pins: 1, 2, 3, 4, 5, 6, 7, 8

## RN_0402X4
designator RN?
pins: 1, 2, 3, 4, 5, 6, 7, 8

## RTC-VBAT-2P
designator J?
pins: 1, 2

## S-NPN_0
designator Q?
pins: 1, 2, 3

## S-NPN_1
designator Q?
pins: 1, 2, 3

## Sensor_MPU6500_0
designator U?, comment BMI160
pins: 1 SDO, 2 ASDX, 3 ASCX, 4 INT1, 5 VDDIO, 6 GNDIO, 7 GND, 8 VDD, 9 INT2, 10 OCSB, 11 OSDO, 12 CSB, 13 SCX, 14 SDX

## Sensor_MPU6500_1
designator U?
pins: 1 NC#1, 2 NC#2, 3 NC#3, 4 NC#4, 5 NC#5, 6 NC#6, 7 AUX_CL, 8 VDDIO, 9 SDO/AD0, 10 REGOUT, 11 FSYNC, 12 INT, 13 VDD, 14 NC#7, 15 NC#8, 16 NC#9, 17 NC#10, 18 GND, 19 RESV1, 20 RESV2, 21 AUX_DA, 22 nCS, 23 SCL/SCLK, 24 SDA/SDI, 25 E-PAD

## SIM-SPPN08-XO-1X80_0
designator J?
footprint SIM-SPPN08-XO-1X80
pins: 1 VCC, 2 RST, 3 CLK, 4 VPP, 5 GND, 6 I/O, 7 DATA0, 8 MCMD, 9 CART_DET, 10 GND, 11 GND, 12 GND, 13 GND

## SIM-SPPN08-XO-1X80_1
designator J?
footprint SIM-SPPN08-XO-1X80
pins: 1 VCC, 2 GND, 3 RST, 4 VPP, 5 CLK, 6 I/O, 7 DATA0, 8 MCMD, 9 CART_DET, 10 GND, 11 GND, 12 GND, 13 GND

## SMB137B_0
designator U?
pins: A1 DCIN, A2 DCIN, A3 DCIN, A4 THERM, A5 EN, A6 SCL, B1 FETDRV, B2 VOUT, B3 VOUT, B4 VOUTL, B5 SDA, B6 STAT, C1 OTG/LBR, C2 USBIN, C3 SW, C4 SW, C5 SW, C6 USB5/1/HC, D1 NC, D2 USBIN, D3 GND, D4 GND, D5 GND, D6 CSOUT, E1 AUXPWR, E2 USBIN, E3 CSIN, E4 D+, E5 D-, E6 CSOUT

## SMB347_0
designator U?
footprint BGA30-3X2.5
pins: A1 USBIN, A2 MIDUSBIN, A3 SW, A4 MIDDCIN, A5 DCIN, B1 USBIN, B2 BOOT, B3 SW, B4 VCHG, B5 DCIN, C1 VDDCAP, C2 FETDRV, C3 THERM, C4 EN, C5 GND, D1 D-, D2 USB5/1/HC, D3 SUSP, D4 VSYS, D5 VSYS, E1 D+, E2 CHG_DET, E3 VBATT, E4 CHGOUT, E5 CHGOUT, F1 OTG/ID, F2 SCL, F3 SDA, F4 GND, F5 STAT

## SMB347_1
designator U?
footprint BGA30-3X2.5
pins: A1 USBIN, A2 MIDUSBIN, A3 SW, A4 MIDDCIN, A5 DCIN, B1 USBIN, B2 BOOT, B3 SW, B4 VCHG, B5 DCIN, C1 VDDCAP, C2 FETDRV, C3 THERM, C4 EN, C5 GND, D1 D-, D2 USB5/1/HC, D3 SUSP, D4 VSYS, D5 VSYS, E1 D+, E2 CHG_DET, E3 VBATT, E4 CHGOUT, E5 CHGOUT, F1 OTG/ID, F2 SCL, F3 SDA, F4 GND, F5 STAT

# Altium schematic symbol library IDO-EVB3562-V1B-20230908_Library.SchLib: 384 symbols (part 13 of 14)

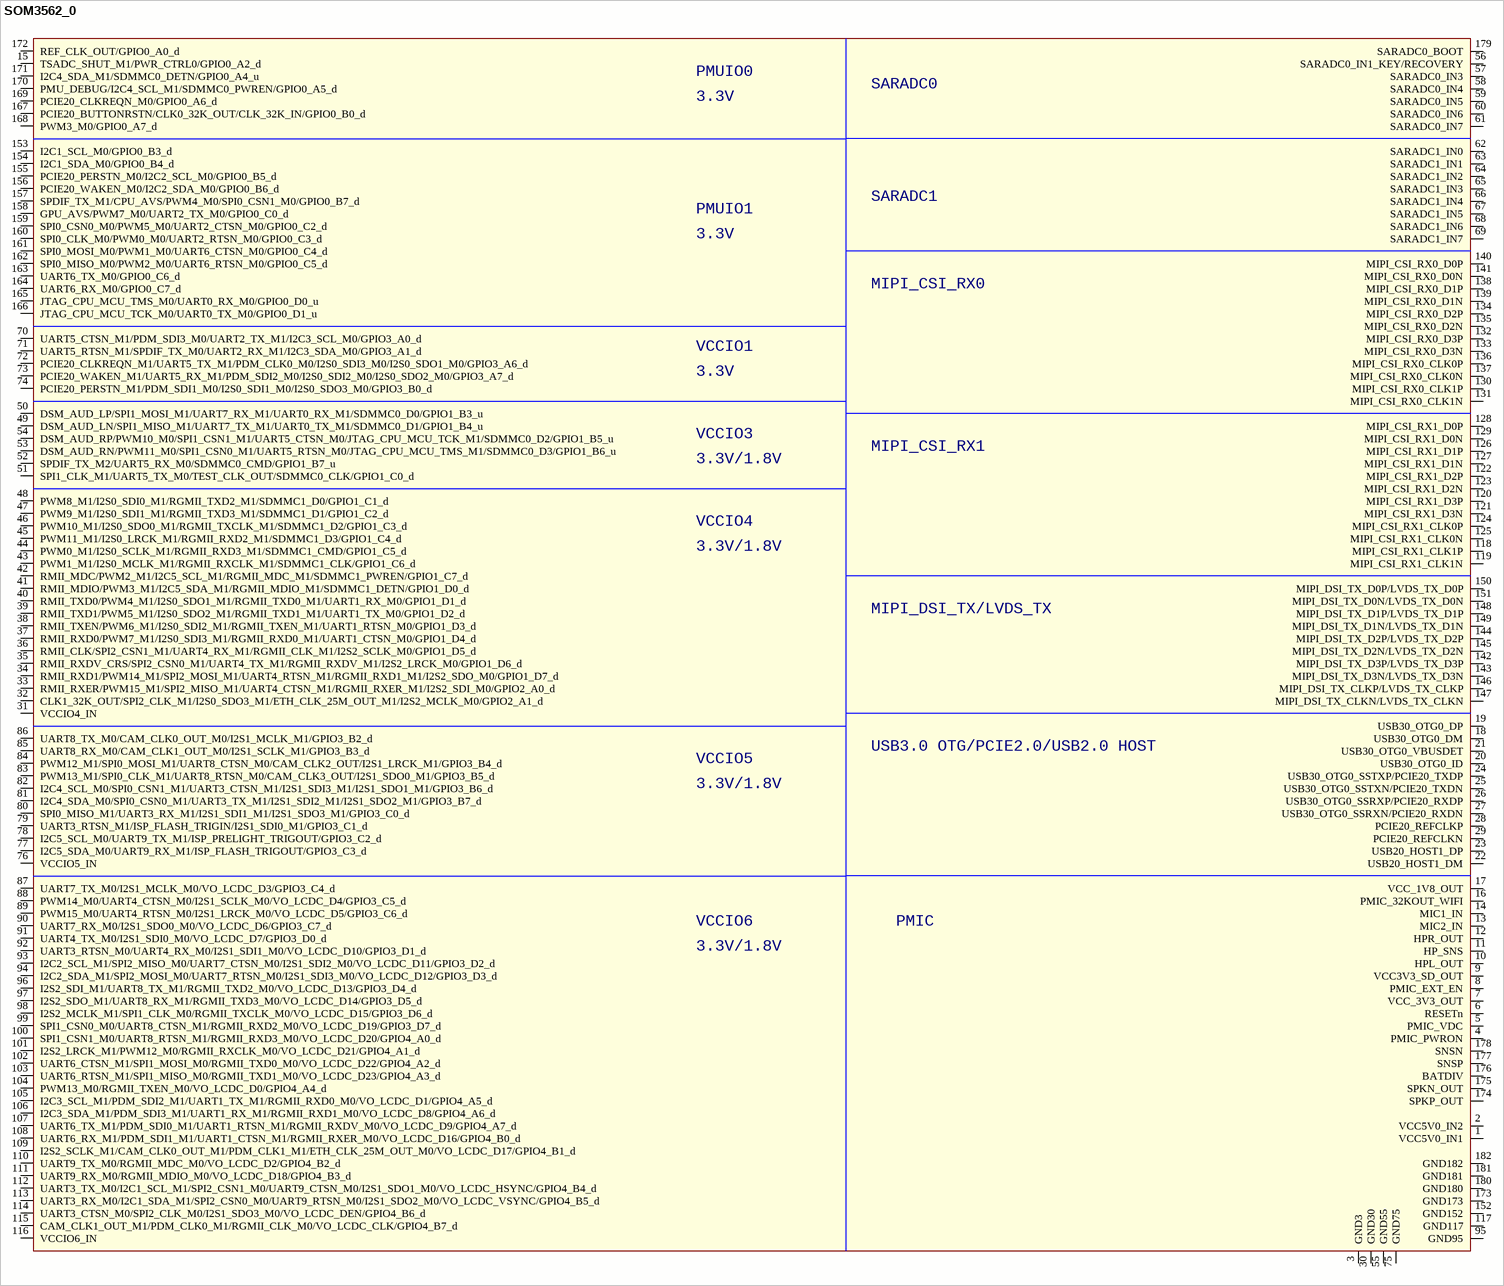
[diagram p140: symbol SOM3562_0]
## SOM3562_0
designator M?
footprint SOM3562-182P
pins: 1 VCC5V0_IN1, 2 VCC5V0_IN2, 3 GND3, 4 PMIC_PWRON, 5 PMIC_VDC, 6 RESETn, 7 VCC_3V3_OUT, 8 PMIC_EXT_EN, 9 VCC3V3_SD_OUT, 10 HPL_OUT, 11 HP_SNS, 12 HPR_OUT, 13 MIC2_IN, 14 MIC1_IN, 15 TSADC_SHUT_M1/PWR_CTRL0/GPIO0_A2_d, 16 PMIC_32KOUT_WIFI, 17 VCC_1V8_OUT, 18 USB30_OTG0_DM, 19 USB30_OTG0_DP, 20 USB30_OTG0_ID, 21 USB30_OTG0_VBUSDET, 22 USB20_HOST1_DM, 23 USB20_HOST1_DP, 24 USB30_OTG0_SSTXP/PCIE20_TXDP, 25 USB30_OTG0_SSTXN/PCIE20_TXDN, 26 USB30_OTG0_SSRXP/PCIE20_RXDP, 27 USB30_OTG0_SSRXN/PCIE20_RXDN, 28 PCIE20_REFCLKP, 29 PCIE20_REFCLKN, 30 GND30, 31 VCCIO4_IN, 32 CLK1_32K_OUT/SPI2_CLK_M1/I2S0_SDO3_M1/ETH_CLK_25M_OUT_M1/I2S2_MCLK_M0/GPIO2_A1_d, 33 RMII_RXER/PWM15_M1/SPI2_MISO_M1/UART4_CTSN_M1/RGMII_RXER_M1/I2S2_SDI_M0/GPIO2_A0_d, 34 RMII_RXD1/PWM14_M1/SPI2_MOSI_M1/UART4_RTSN_M1/RGMII_RXD1_M1/I2S2_SDO_M0/GPIO1_D7_d, 35 RMII_RXDV_CRS/SPI2_CSN0_M1/UART4_TX_M1/RGMII_RXDV_M1/I2S2_LRCK_M0/GPIO1_D6_d, 36 RMII_CLK/SPI2_CSN1_M1/UART4_RX_M1/RGMII_CLK_M1/I2S2_SCLK_M0/GPIO1_D5_d, 37 RMII_RXD0/PWM7_M1/I2S0_SDI3_M1/RGMII_RXD0_M1/UART1_CTSN_M0/GPIO1_D4_d, 38 RMII_TXEN/PWM6_M1/I2S0_SDI2_M1/RGMII_TXEN_M1/UART1_RTSN_M0/GPIO1_D3_d, 39 RMII_TXD1/PWM5_M1/I2S0_SDO2_M1/RGMII_TXD1_M1/UART1_TX_M0/GPIO1_D2_d, 40 RMII_TXD0/PWM4_M1/I2S0_SDO1_M1/RGMII_TXD0_M1/UART1_RX_M0/GPIO1_D1_d, 41 RMII_MDIO/PWM3_M1/I2C5_SDA_M1/RGMII_MDIO_M1/SDMMC1_DETN/GPIO1_D0_d, 42 RMII_MDC/PWM2_M1/I2C5_SCL_M1/RGMII_MDC_M1/SDMMC1_PWREN/GPIO1_C7_d, 43 PWM1_M1/I2S0_MCLK_M1/RGMII_RXCLK_M1/SDMMC1_CLK/GPIO1_C6_d, 44 PWM0_M1/I2S0_SCLK_M1/RGMII_RXD3_M1/SDMMC1_CMD/GPIO1_C5_d, 45 PWM11_M1/I2S0_LRCK_M1/RGMII_RXD2_M1/SDMMC1_D3/GPIO1_C4_d, 46 PWM10_M1/I2S0_SDO0_M1/RGMII_TXCLK_M1/SDMMC1_D2/GPIO1_C3_d, 47 PWM9_M1/I2S0_SDI1_M1/RGMII_TXD3_M1/SDMMC1_D1/GPIO1_C2_d, 48 PWM8_M1/I2S0_SDI0_M1/RGMII_TXD2_M1/SDMMC1_D0/GPIO1_C1_d, 49 DSM_AUD_LN/SPI1_MISO_M1/UART7_TX_M1/UART0_TX_M1/SDMMC0_D1/GPIO1_B4_u, 50 DSM_AUD_LP/SPI1_MOSI_M1/UART7_RX_M1/UART0_RX_M1/SDMMC0_D0/GPIO1_B3_u, 51 SPI1_CLK_M1/UART5_TX_M0/TEST_CLK_OUT/SDMMC0_CLK/GPIO1_C0_d, 52 SPDIF_TX_M2/UART5_RX_M0/SDMMC0_CMD/GPIO1_B7_u, 53 DSM_AUD_RN/PWM11_M0/SPI1_CSN0_M1/UART5_RTSN_M0/JTAG_CPU_MCU_TMS_M1/SDMMC0_D3/GPIO1_B6_u, 54 DSM_AUD_RP/PWM10_M0/SPI1_CSN1_M1/UART5_CTSN_M0/JTAG_CPU_MCU_TCK_M1/SDMMC0_D2/GPIO1_B5_u, 55 GND55, 56 SARADC0_IN1_KEY/RECOVERY, 57 SARADC0_IN3, 58 SARADC0_IN4, 59 SARADC0_IN5, 60 SARADC0_IN6, 61 SARADC0_IN7, 62 SARADC1_IN0, 63 SARADC1_IN1, 64 SARADC1_IN2, 65 SARADC1_IN3, 66 SARADC1_IN4, 67 SARADC1_IN5, 68 SARADC1_IN6, 69 SARADC1_IN7, 70 UART5_CTSN_M1/PDM_SDI3_M0/UART2_TX_M1/I2C3_SCL_M0/GPIO3_A0_d, 71 UART5_RTSN_M1/SPDIF_TX_M0/UART2_RX_M1/I2C3_SDA_M0/GPIO3_A1_d, 72 PCIE20_CLKREQN_M1/UART5_TX_M1/PDM_CLK0_M0/I2S0_SDI3_M0/I2S0_SDO1_M0/GPIO3_A6_d, 73 PCIE20_WAKEN_M1/UART5_RX_M1/PDM_SDI2_M0/I2S0_SDI2_M0/I2S0_SDO2_M0/GPIO3_A7_d, 74 PCIE20_PERSTN_M1/PDM_SDI1_M0/I2S0_SDI1_M0/I2S0_SDO3_M0/GPIO3_B0_d, 75 GND75, 76 VCCIO5_IN, 77 I2C5_SDA_M0/UART9_RX_M1/ISP_FLASH_TRIGOUT/GPIO3_C3_d, 78 I2C5_SCL_M0/UART9_TX_M1/ISP_PRELIGHT_TRIGOUT/GPIO3_C2_d, 79 UART3_RTSN_M1/ISP_FLASH_TRIGIN/I2S1_SDI0_M1/GPIO3_C1_d, 80 SPI0_MISO_M1/UART3_RX_M1/I2S1_SDI1_M1/I2S1_SDO3_M1/GPIO3_C0_d, 81 I2C4_SDA_M0/SPI0_CSN0_M1/UART3_TX_M1/I2S1_SDI2_M1/I2S1_SDO2_M1/GPIO3_B7_d, 82 I2C4_SCL_M0/SPI0_CSN1_M1/UART3_CTSN_M1/I2S1_SDI3_M1/I2S1_SDO1_M1/GPIO3_B6_d, 83 PWM13_M1/SPI0_CLK_M1/UART8_RTSN_M0/CAM_CLK3_OUT/I2S1_SDO0_M1/GPIO3_B5_d, 84 PWM12_M1/SPI0_MOSI_M1/UART8_CTSN_M0/CAM_CLK2_OUT/I2S1_LRCK_M1/GPIO3_B4_d, 85 UART8_RX_M0/CAM_CLK1_OUT_M0/I2S1_SCLK_M1/GPIO3_B3_d, 86 UART8_TX_M0/CAM_CLK0_OUT_M0/I2S1_MCLK_M1/GPIO3_B2_d, 87 UART7_TX_M0/I2S1_MCLK_M0/VO_LCDC_D3/GPIO3_C4_d, 88 PWM14_M0/UART4_CTSN_M0/I2S1_SCLK_M0/VO_LCDC_D4/GPIO3_C5_d, 89 PWM15_M0/UART4_RTSN_M0/I2S1_LRCK_M0/VO_LCDC_D5/GPIO3_C6_d, 90 UART7_RX_M0/I2S1_SDO0_M0/VO_LCDC_D6/GPIO3_C7_d, 91 UART4_TX_M0/I2S1_SDI0_M0/VO_LCDC_D7/GPIO3_D0_d, 92 UART3_RTSN_M0/UART4_RX_M0/I2S1_SDI1_M0/VO_LCDC_D10/GPIO3_D1_d, 93 I2C2_SCL_M1/SPI2_MISO_M0/UART7_CTSN_M0/I2S1_SDI2_M0/VO_LCDC_D11/GPIO3_D2_d, 94 I2C2_SDA_M1/SPI2_MOSI_M0/UART7_RTSN_M0/I2S1_SDI3_M0/VO_LCDC_D12/GPIO3_D3_d, 95 GND95, 96 I2S2_SDI_M1/UART8_TX_M1/RGMII_TXD2_M0/VO_LCDC_D13/GPIO3_D4_d, 97 I2S2_SDO_M1/UART8_RX_M1/RGMII_TXD3_M0/VO_LCDC_D14/GPIO3_D5_d, 98 I2S2_MCLK_M1/SPI1_CLK_M0/RGMII_TXCLK_M0/VO_LCDC_D15/GPIO3_D6_d, 99 SPI1_CSN0_M0/UART8_CTSN_M1/RGMII_RXD2_M0/VO_LCDC_D19/GPIO3_D7_d, 100 SPI1_CSN1_M0/UART8_RTSN_M1/RGMII_RXD3_M0/VO_LCDC_D20/GPIO4_A0_d, 101 I2S2_LRCK_M1/PWM12_M0/RGMII_RXCLK_M0/VO_LCDC_D21/GPIO4_A1_d, 102 UART6_CTSN_M1/SPI1_MOSI_M0/RGMII_TXD0_M0/VO_LCDC_D22/GPIO4_A2_d, 103 UART6_RTSN_M1/SPI1_MISO_M0/RGMII_TXD1_M0/VO_LCDC_D23/GPIO4_A3_d, 104 PWM13_M0/RGMII_TXEN_M0/VO_LCDC_D0/GPIO4_A4_d, 105 I2C3_SCL_M1/PDM_SDI2_M1/UART1_TX_M1/RGMII_RXD0_M0/VO_LCDC_D1/GPIO4_A5_d, 106 I2C3_SDA_M1/PDM_SDI3_M1/UART1_RX_M1/RGMII_RXD1_M0/VO_LCDC_D8/GPIO4_A6_d, 107 UART6_TX_M1/PDM_SDI0_M1/UART1_RTSN_M1/RGMII_RXDV_M0/VO_LCDC_D9/GPIO4_A7_d, 108 UART6_RX_M1/PDM_SDI1_M1/UART1_CTSN_M1/RGMII_RXER_M0/VO_LCDC_D16/GPIO4_B0_d, 109 I2S2_SCLK_M1/CAM_CLK0_OUT_M1/PDM_CLK1_M1/ETH_CLK_25M_OUT_M0/VO_LCDC_D17/GPIO4_B1_d, 110 UART9_TX_M0/RGMII_MDC_M0/VO_LCDC_D2/GPIO4_B2_d, 111 UART9_RX_M0/RGMII_MDIO_M0/VO_LCDC_D18/GPIO4_B3_d, 112 UART3_TX_M0/I2C1_SCL_M1/SPI2_CSN1_M0/UART9_CTSN_M0/I2S1_SDO1_M0/VO_LCDC_HSYNC/GPIO4_B4_d, 113 UART3_RX_M0/I2C1_SDA_M1/SPI2_CSN0_M0/UART9_RTSN_M0/I2S1_SDO2_M0/VO_LCDC_VSYNC/GPIO4_B5_d, 114 UART3_CTSN_M0/SPI2_CLK_M0/I2S1_SDO3_M0/VO_LCDC_DEN/GPIO4_B6_d, 115 CAM_CLK1_OUT_M1/PDM_CLK0_M1/RGMII_CLK_M0/VO_LCDC_CLK/GPIO4_B7_d, 116 VCCIO6_IN, 117 GND117, 118 MIPI_CSI_RX1_CLK1P, 119 MIPI_CSI_RX1_CLK1N, 120 MIPI_CSI_RX1_D3P, 121 MIPI_CSI_RX1_D3N, 122 MIPI_CSI_RX1_D2P, 123 MIPI_CSI_RX1_D2N, 124 MIPI_CSI_RX1_CLK0P, 125 MIPI_CSI_RX1_CLK0N, 126 MIPI_CSI_RX1_D1P, 127 MIPI_CSI_RX1_D1N, 128 MIPI_CSI_RX1_D0P, 129 MIPI_CSI_RX1_D0N, 130 MIPI_CSI_RX0_CLK1P, 131 MIPI_CSI_RX0_CLK1N, 132 MIPI_CSI_RX0_D3P, 133 MIPI_CSI_RX0_D3N, 134 MIPI_CSI_RX0_D2P, 135 MIPI_CSI_RX0_D2N, 136 MIPI_CSI_RX0_CLK0P, 137 MIPI_CSI_RX0_CLK0N, 138 MIPI_CSI_RX0_D1P, 139 MIPI_CSI_RX0_D1N, 140 MIPI_CSI_RX0_D0P, 141 MIPI_CSI_RX0_D0N, 142 MIPI_DSI_TX_D3P/LVDS_TX_D3P, 143 MIPI_DSI_TX_D3N/LVDS_TX_D3N, 144 MIPI_DSI_TX_D2P/LVDS_TX_D2P, 145 MIPI_DSI_TX_D2N/LVDS_TX_D2N, 146 MIPI_DSI_TX_CLKP/LVDS_TX_CLKP, 147 MIPI_DSI_TX_CLKN/LVDS_TX_CLKN, 148 MIPI_DSI_TX_D1P/LVDS_TX_D1P, 149 MIPI_DSI_TX_D1N/LVDS_TX_D1N, 150 MIPI_DSI_TX_D0P/LVDS_TX_D0P, 151 MIPI_DSI_TX_D0N/LVDS_TX_D0N, 152 GND152, 153 I2C1_SCL_M0/GPIO0_B3_d, 154 I2C1_SDA_M0/GPIO0_B4_d, 155 PCIE20_PERSTN_M0/I2C2_SCL_M0/GPIO0_B5_d, 156 PCIE20_WAKEN_M0/I2C2_SDA_M0/GPIO0_B6_d, 157 SPDIF_TX_M1/CPU_AVS/PWM4_M0/SPI0_CSN1_M0/GPIO0_B7_d, 158 GPU_AVS/PWM7_M0/UART2_TX_M0/GPIO0_C0_d, 159 SPI0_CSN0_M0/PWM5_M0/UART2_CTSN_M0/GPIO0_C2_d, 160 SPI0_CLK_M0/PWM0_M0/UART2_RTSN_M0/GPIO0_C3_d, 161 SPI0_MOSI_M0/PWM1_M0/UART6_CTSN_M0/GPIO0_C4_d, 162 SPI0_MISO_M0/PWM2_M0/UART6_RTSN_M0/GPIO0_C5_d, 163 UART6_TX_M0/GPIO0_C6_d, 164 UART6_RX_M0/GPIO0_C7_d, 165 JTAG_CPU_MCU_TMS_M0/UART0_RX_M0/GPIO0_D0_u, 166 JTAG_CPU_MCU_TCK_M0/UART0_TX_M0/GPIO0_D1_u, 167 PCIE20_BUTTONRSTN/CLK0_32K_OUT/CLK_32K_IN/GPIO0_B0_d, 168 PWM3_M0/GPIO0_A7_d, 169 PCIE20_CLKREQN_M0/GPIO0_A6_d, 170 PMU_DEBUG/I2C4_SCL_M1/SDMMC0_PWREN/GPIO0_A5_d, 171 I2C4_SDA_M1/SDMMC0_DETN/GPIO0_A4_u, 172 REF_CLK_OUT/GPIO0_A0_d, 173 GND173, 174 SPKP_OUT, 175 SPKN_OUT, 176 BATDIV, 177 SNSP, 178 SNSN, 179 SARADC0_BOOT, 180 GND180, 181 GND181, 182 GND182


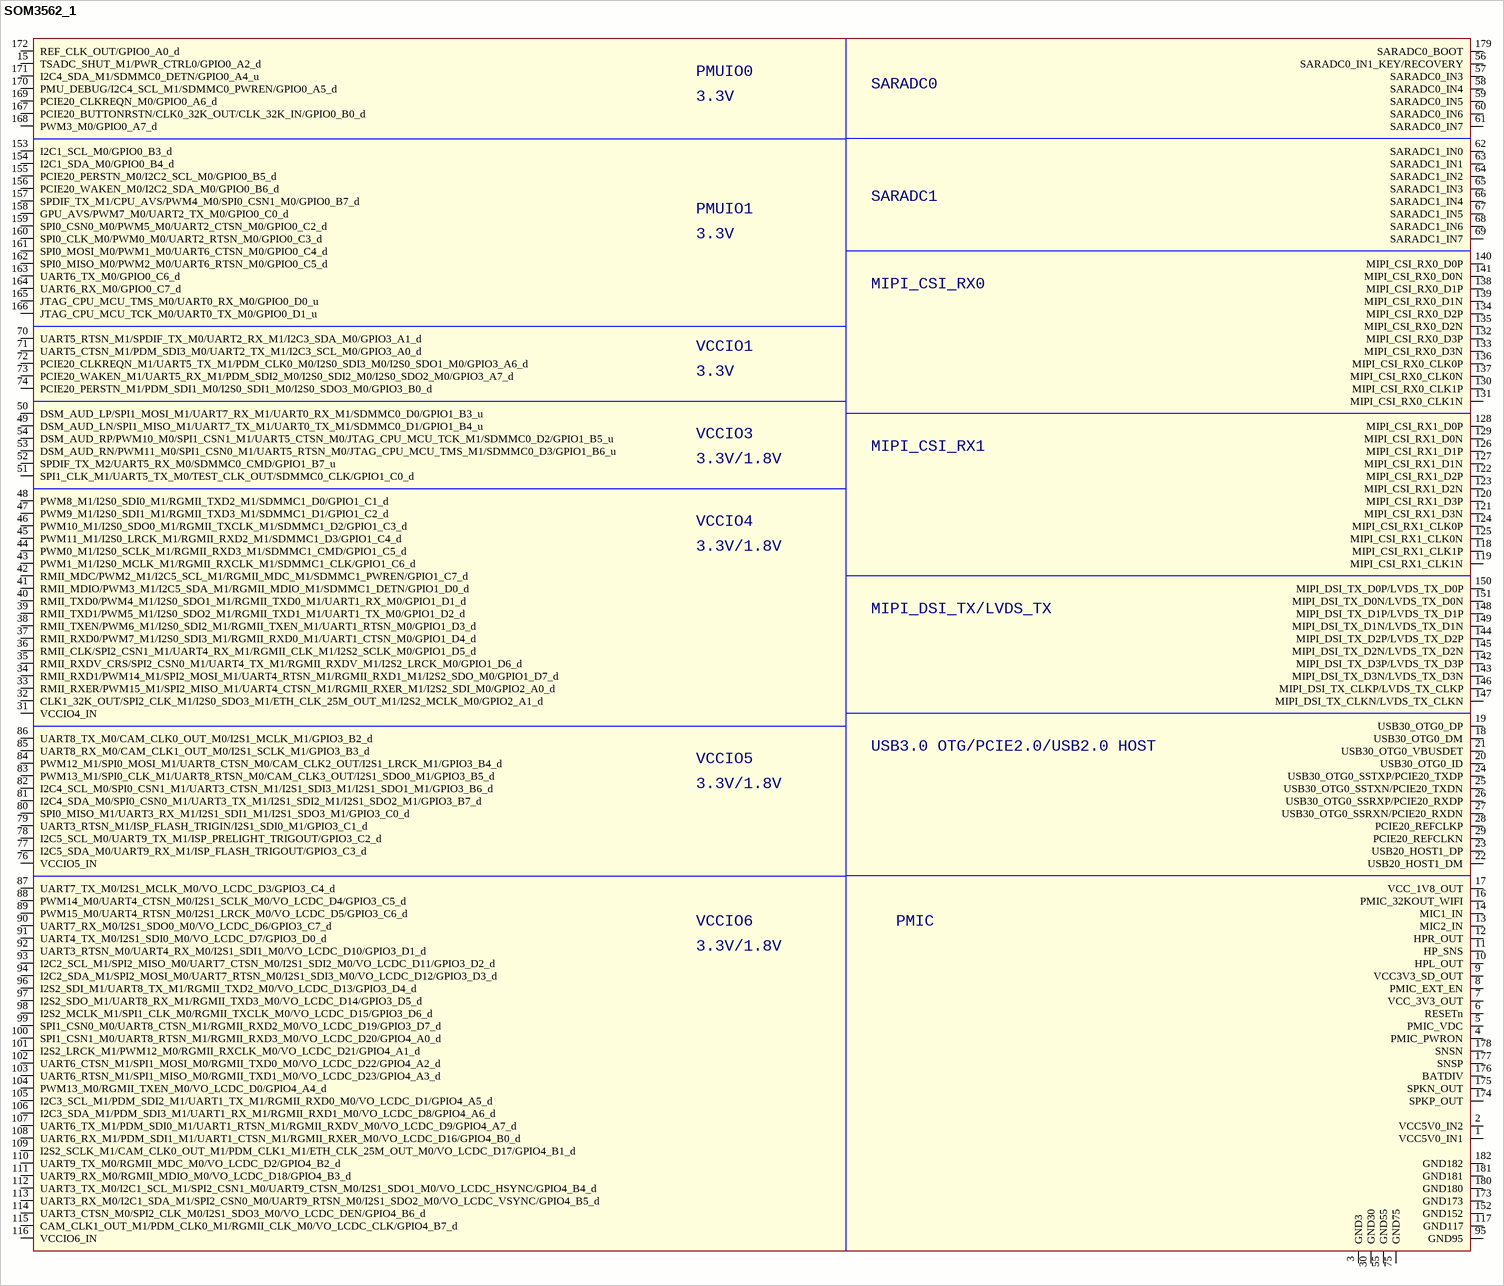
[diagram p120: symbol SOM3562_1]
## SOM3562_1
designator M?
footprint SOM3562-182P
pins: 1 VCC5V0_IN1, 2 VCC5V0_IN2, 3 GND3, 4 PMIC_PWRON, 5 PMIC_VDC, 6 RESETn, 7 VCC_3V3_OUT, 8 PMIC_EXT_EN, 9 VCC3V3_SD_OUT, 10 HPL_OUT, 11 HP_SNS, 12 HPR_OUT, 13 MIC2_IN, 14 MIC1_IN, 15 TSADC_SHUT_M1/PWR_CTRL0/GPIO0_A2_d, 16 PMIC_32KOUT_WIFI, 17 VCC_1V8_OUT, 18 USB30_OTG0_DM, 19 USB30_OTG0_DP, 20 USB30_OTG0_ID, 21 USB30_OTG0_VBUSDET, 22 USB20_HOST1_DM, 23 USB20_HOST1_DP, 24 USB30_OTG0_SSTXP/PCIE20_TXDP, 25 USB30_OTG0_SSTXN/PCIE20_TXDN, 26 USB30_OTG0_SSRXP/PCIE20_RXDP, 27 USB30_OTG0_SSRXN/PCIE20_RXDN, 28 PCIE20_REFCLKP, 29 PCIE20_REFCLKN, 30 GND30, 31 VCCIO4_IN, 32 CLK1_32K_OUT/SPI2_CLK_M1/I2S0_SDO3_M1/ETH_CLK_25M_OUT_M1/I2S2_MCLK_M0/GPIO2_A1_d, 33 RMII_RXER/PWM15_M1/SPI2_MISO_M1/UART4_CTSN_M1/RGMII_RXER_M1/I2S2_SDI_M0/GPIO2_A0_d, 34 RMII_RXD1/PWM14_M1/SPI2_MOSI_M1/UART4_RTSN_M1/RGMII_RXD1_M1/I2S2_SDO_M0/GPIO1_D7_d, 35 RMII_RXDV_CRS/SPI2_CSN0_M1/UART4_TX_M1/RGMII_RXDV_M1/I2S2_LRCK_M0/GPIO1_D6_d, 36 RMII_CLK/SPI2_CSN1_M1/UART4_RX_M1/RGMII_CLK_M1/I2S2_SCLK_M0/GPIO1_D5_d, 37 RMII_RXD0/PWM7_M1/I2S0_SDI3_M1/RGMII_RXD0_M1/UART1_CTSN_M0/GPIO1_D4_d, 38 RMII_TXEN/PWM6_M1/I2S0_SDI2_M1/RGMII_TXEN_M1/UART1_RTSN_M0/GPIO1_D3_d, 39 RMII_TXD1/PWM5_M1/I2S0_SDO2_M1/RGMII_TXD1_M1/UART1_TX_M0/GPIO1_D2_d, 40 RMII_TXD0/PWM4_M1/I2S0_SDO1_M1/RGMII_TXD0_M1/UART1_RX_M0/GPIO1_D1_d, 41 RMII_MDIO/PWM3_M1/I2C5_SDA_M1/RGMII_MDIO_M1/SDMMC1_DETN/GPIO1_D0_d, 42 RMII_MDC/PWM2_M1/I2C5_SCL_M1/RGMII_MDC_M1/SDMMC1_PWREN/GPIO1_C7_d, 43 PWM1_M1/I2S0_MCLK_M1/RGMII_RXCLK_M1/SDMMC1_CLK/GPIO1_C6_d, 44 PWM0_M1/I2S0_SCLK_M1/RGMII_RXD3_M1/SDMMC1_CMD/GPIO1_C5_d, 45 PWM11_M1/I2S0_LRCK_M1/RGMII_RXD2_M1/SDMMC1_D3/GPIO1_C4_d, 46 PWM10_M1/I2S0_SDO0_M1/RGMII_TXCLK_M1/SDMMC1_D2/GPIO1_C3_d, 47 PWM9_M1/I2S0_SDI1_M1/RGMII_TXD3_M1/SDMMC1_D1/GPIO1_C2_d, 48 PWM8_M1/I2S0_SDI0_M1/RGMII_TXD2_M1/SDMMC1_D0/GPIO1_C1_d, 49 DSM_AUD_LN/SPI1_MISO_M1/UART7_TX_M1/UART0_TX_M1/SDMMC0_D1/GPIO1_B4_u, 50 DSM_AUD_LP/SPI1_MOSI_M1/UART7_RX_M1/UART0_RX_M1/SDMMC0_D0/GPIO1_B3_u, 51 SPI1_CLK_M1/UART5_TX_M0/TEST_CLK_OUT/SDMMC0_CLK/GPIO1_C0_d, 52 SPDIF_TX_M2/UART5_RX_M0/SDMMC0_CMD/GPIO1_B7_u, 53 DSM_AUD_RN/PWM11_M0/SPI1_CSN0_M1/UART5_RTSN_M0/JTAG_CPU_MCU_TMS_M1/SDMMC0_D3/GPIO1_B6_u, 54 DSM_AUD_RP/PWM10_M0/SPI1_CSN1_M1/UART5_CTSN_M0/JTAG_CPU_MCU_TCK_M1/SDMMC0_D2/GPIO1_B5_u, 55 GND55, 56 SARADC0_IN1_KEY/RECOVERY, 57 SARADC0_IN3, 58 SARADC0_IN4, 59 SARADC0_IN5, 60 SARADC0_IN6, 61 SARADC0_IN7, 62 SARADC1_IN0, 63 SARADC1_IN1, 64 SARADC1_IN2, 65 SARADC1_IN3, 66 SARADC1_IN4, 67 SARADC1_IN5, 68 SARADC1_IN6, 69 SARADC1_IN7, 70 UART5_RTSN_M1/SPDIF_TX_M0/UART2_RX_M1/I2C3_SDA_M0/GPIO3_A1_d, 71 UART5_CTSN_M1/PDM_SDI3_M0/UART2_TX_M1/I2C3_SCL_M0/GPIO3_A0_d, 72 PCIE20_CLKREQN_M1/UART5_TX_M1/PDM_CLK0_M0/I2S0_SDI3_M0/I2S0_SDO1_M0/GPIO3_A6_d, 73 PCIE20_WAKEN_M1/UART5_RX_M1/PDM_SDI2_M0/I2S0_SDI2_M0/I2S0_SDO2_M0/GPIO3_A7_d, 74 PCIE20_PERSTN_M1/PDM_SDI1_M0/I2S0_SDI1_M0/I2S0_SDO3_M0/GPIO3_B0_d, 75 GND75, 76 VCCIO5_IN, 77 I2C5_SDA_M0/UART9_RX_M1/ISP_FLASH_TRIGOUT/GPIO3_C3_d, 78 I2C5_SCL_M0/UART9_TX_M1/ISP_PRELIGHT_TRIGOUT/GPIO3_C2_d, 79 UART3_RTSN_M1/ISP_FLASH_TRIGIN/I2S1_SDI0_M1/GPIO3_C1_d, 80 SPI0_MISO_M1/UART3_RX_M1/I2S1_SDI1_M1/I2S1_SDO3_M1/GPIO3_C0_d, 81 I2C4_SDA_M0/SPI0_CSN0_M1/UART3_TX_M1/I2S1_SDI2_M1/I2S1_SDO2_M1/GPIO3_B7_d, 82 I2C4_SCL_M0/SPI0_CSN1_M1/UART3_CTSN_M1/I2S1_SDI3_M1/I2S1_SDO1_M1/GPIO3_B6_d, 83 PWM13_M1/SPI0_CLK_M1/UART8_RTSN_M0/CAM_CLK3_OUT/I2S1_SDO0_M1/GPIO3_B5_d, 84 PWM12_M1/SPI0_MOSI_M1/UART8_CTSN_M0/CAM_CLK2_OUT/I2S1_LRCK_M1/GPIO3_B4_d, 85 UART8_RX_M0/CAM_CLK1_OUT_M0/I2S1_SCLK_M1/GPIO3_B3_d, 86 UART8_TX_M0/CAM_CLK0_OUT_M0/I2S1_MCLK_M1/GPIO3_B2_d, 87 UART7_TX_M0/I2S1_MCLK_M0/VO_LCDC_D3/GPIO3_C4_d, 88 PWM14_M0/UART4_CTSN_M0/I2S1_SCLK_M0/VO_LCDC_D4/GPIO3_C5_d, 89 PWM15_M0/UART4_RTSN_M0/I2S1_LRCK_M0/VO_LCDC_D5/GPIO3_C6_d, 90 UART7_RX_M0/I2S1_SDO0_M0/VO_LCDC_D6/GPIO3_C7_d, 91 UART4_TX_M0/I2S1_SDI0_M0/VO_LCDC_D7/GPIO3_D0_d, 92 UART3_RTSN_M0/UART4_RX_M0/I2S1_SDI1_M0/VO_LCDC_D10/GPIO3_D1_d, 93 I2C2_SCL_M1/SPI2_MISO_M0/UART7_CTSN_M0/I2S1_SDI2_M0/VO_LCDC_D11/GPIO3_D2_d, 94 I2C2_SDA_M1/SPI2_MOSI_M0/UART7_RTSN_M0/I2S1_SDI3_M0/VO_LCDC_D12/GPIO3_D3_d, 95 GND95, 96 I2S2_SDI_M1/UART8_TX_M1/RGMII_TXD2_M0/VO_LCDC_D13/GPIO3_D4_d, 97 I2S2_SDO_M1/UART8_RX_M1/RGMII_TXD3_M0/VO_LCDC_D14/GPIO3_D5_d, 98 I2S2_MCLK_M1/SPI1_CLK_M0/RGMII_TXCLK_M0/VO_LCDC_D15/GPIO3_D6_d, 99 SPI1_CSN0_M0/UART8_CTSN_M1/RGMII_RXD2_M0/VO_LCDC_D19/GPIO3_D7_d, 100 SPI1_CSN1_M0/UART8_RTSN_M1/RGMII_RXD3_M0/VO_LCDC_D20/GPIO4_A0_d, 101 I2S2_LRCK_M1/PWM12_M0/RGMII_RXCLK_M0/VO_LCDC_D21/GPIO4_A1_d, 102 UART6_CTSN_M1/SPI1_MOSI_M0/RGMII_TXD0_M0/VO_LCDC_D22/GPIO4_A2_d, 103 UART6_RTSN_M1/SPI1_MISO_M0/RGMII_TXD1_M0/VO_LCDC_D23/GPIO4_A3_d, 104 PWM13_M0/RGMII_TXEN_M0/VO_LCDC_D0/GPIO4_A4_d, 105 I2C3_SCL_M1/PDM_SDI2_M1/UART1_TX_M1/RGMII_RXD0_M0/VO_LCDC_D1/GPIO4_A5_d, 106 I2C3_SDA_M1/PDM_SDI3_M1/UART1_RX_M1/RGMII_RXD1_M0/VO_LCDC_D8/GPIO4_A6_d, 107 UART6_TX_M1/PDM_SDI0_M1/UART1_RTSN_M1/RGMII_RXDV_M0/VO_LCDC_D9/GPIO4_A7_d, 108 UART6_RX_M1/PDM_SDI1_M1/UART1_CTSN_M1/RGMII_RXER_M0/VO_LCDC_D16/GPIO4_B0_d, 109 I2S2_SCLK_M1/CAM_CLK0_OUT_M1/PDM_CLK1_M1/ETH_CLK_25M_OUT_M0/VO_LCDC_D17/GPIO4_B1_d, 110 UART9_TX_M0/RGMII_MDC_M0/VO_LCDC_D2/GPIO4_B2_d, 111 UART9_RX_M0/RGMII_MDIO_M0/VO_LCDC_D18/GPIO4_B3_d, 112 UART3_TX_M0/I2C1_SCL_M1/SPI2_CSN1_M0/UART9_CTSN_M0/I2S1_SDO1_M0/VO_LCDC_HSYNC/GPIO4_B4_d, 113 UART3_RX_M0/I2C1_SDA_M1/SPI2_CSN0_M0/UART9_RTSN_M0/I2S1_SDO2_M0/VO_LCDC_VSYNC/GPIO4_B5_d, 114 UART3_CTSN_M0/SPI2_CLK_M0/I2S1_SDO3_M0/VO_LCDC_DEN/GPIO4_B6_d, 115 CAM_CLK1_OUT_M1/PDM_CLK0_M1/RGMII_CLK_M0/VO_LCDC_CLK/GPIO4_B7_d, 116 VCCIO6_IN, 117 GND117, 118 MIPI_CSI_RX1_CLK1P, 119 MIPI_CSI_RX1_CLK1N, 120 MIPI_CSI_RX1_D3P, 121 MIPI_CSI_RX1_D3N, 122 MIPI_CSI_RX1_D2P, 123 MIPI_CSI_RX1_D2N, 124 MIPI_CSI_RX1_CLK0P, 125 MIPI_CSI_RX1_CLK0N, 126 MIPI_CSI_RX1_D1P, 127 MIPI_CSI_RX1_D1N, 128 MIPI_CSI_RX1_D0P, 129 MIPI_CSI_RX1_D0N, 130 MIPI_CSI_RX0_CLK1P, 131 MIPI_CSI_RX0_CLK1N, 132 MIPI_CSI_RX0_D3P, 133 MIPI_CSI_RX0_D3N, 134 MIPI_CSI_RX0_D2P, 135 MIPI_CSI_RX0_D2N, 136 MIPI_CSI_RX0_CLK0P, 137 MIPI_CSI_RX0_CLK0N, 138 MIPI_CSI_RX0_D1P, 139 MIPI_CSI_RX0_D1N, 140 MIPI_CSI_RX0_D0P, 141 MIPI_CSI_RX0_D0N, 142 MIPI_DSI_TX_D3P/LVDS_TX_D3P, 143 MIPI_DSI_TX_D3N/LVDS_TX_D3N, 144 MIPI_DSI_TX_D2P/LVDS_TX_D2P, 145 MIPI_DSI_TX_D2N/LVDS_TX_D2N, 146 MIPI_DSI_TX_CLKP/LVDS_TX_CLKP, 147 MIPI_DSI_TX_CLKN/LVDS_TX_CLKN, 148 MIPI_DSI_TX_D1P/LVDS_TX_D1P, 149 MIPI_DSI_TX_D1N/LVDS_TX_D1N, 150 MIPI_DSI_TX_D0P/LVDS_TX_D0P, 151 MIPI_DSI_TX_D0N/LVDS_TX_D0N, 152 GND152, 153 I2C1_SCL_M0/GPIO0_B3_d, 154 I2C1_SDA_M0/GPIO0_B4_d, 155 PCIE20_PERSTN_M0/I2C2_SCL_M0/GPIO0_B5_d, 156 PCIE20_WAKEN_M0/I2C2_SDA_M0/GPIO0_B6_d, 157 SPDIF_TX_M1/CPU_AVS/PWM4_M0/SPI0_CSN1_M0/GPIO0_B7_d, 158 GPU_AVS/PWM7_M0/UART2_TX_M0/GPIO0_C0_d, 159 SPI0_CSN0_M0/PWM5_M0/UART2_CTSN_M0/GPIO0_C2_d, 160 SPI0_CLK_M0/PWM0_M0/UART2_RTSN_M0/GPIO0_C3_d, 161 SPI0_MOSI_M0/PWM1_M0/UART6_CTSN_M0/GPIO0_C4_d, 162 SPI0_MISO_M0/PWM2_M0/UART6_RTSN_M0/GPIO0_C5_d, 163 UART6_TX_M0/GPIO0_C6_d, 164 UART6_RX_M0/GPIO0_C7_d, 165 JTAG_CPU_MCU_TMS_M0/UART0_RX_M0/GPIO0_D0_u, 166 JTAG_CPU_MCU_TCK_M0/UART0_TX_M0/GPIO0_D1_u, 167 PCIE20_BUTTONRSTN/CLK0_32K_OUT/CLK_32K_IN/GPIO0_B0_d, 168 PWM3_M0/GPIO0_A7_d, 169 PCIE20_CLKREQN_M0/GPIO0_A6_d, 170 PMU_DEBUG/I2C4_SCL_M1/SDMMC0_PWREN/GPIO0_A5_d, 171 I2C4_SDA_M1/SDMMC0_DETN/GPIO0_A4_u, 172 REF_CLK_OUT/GPIO0_A0_d, 173 GND173, 174 SPKP_OUT, 175 SPKN_OUT, 176 BATDIV, 177 SNSP, 178 SNSN, 179 SARADC0_BOOT, 180 GND180, 181 GND181, 182 GND182


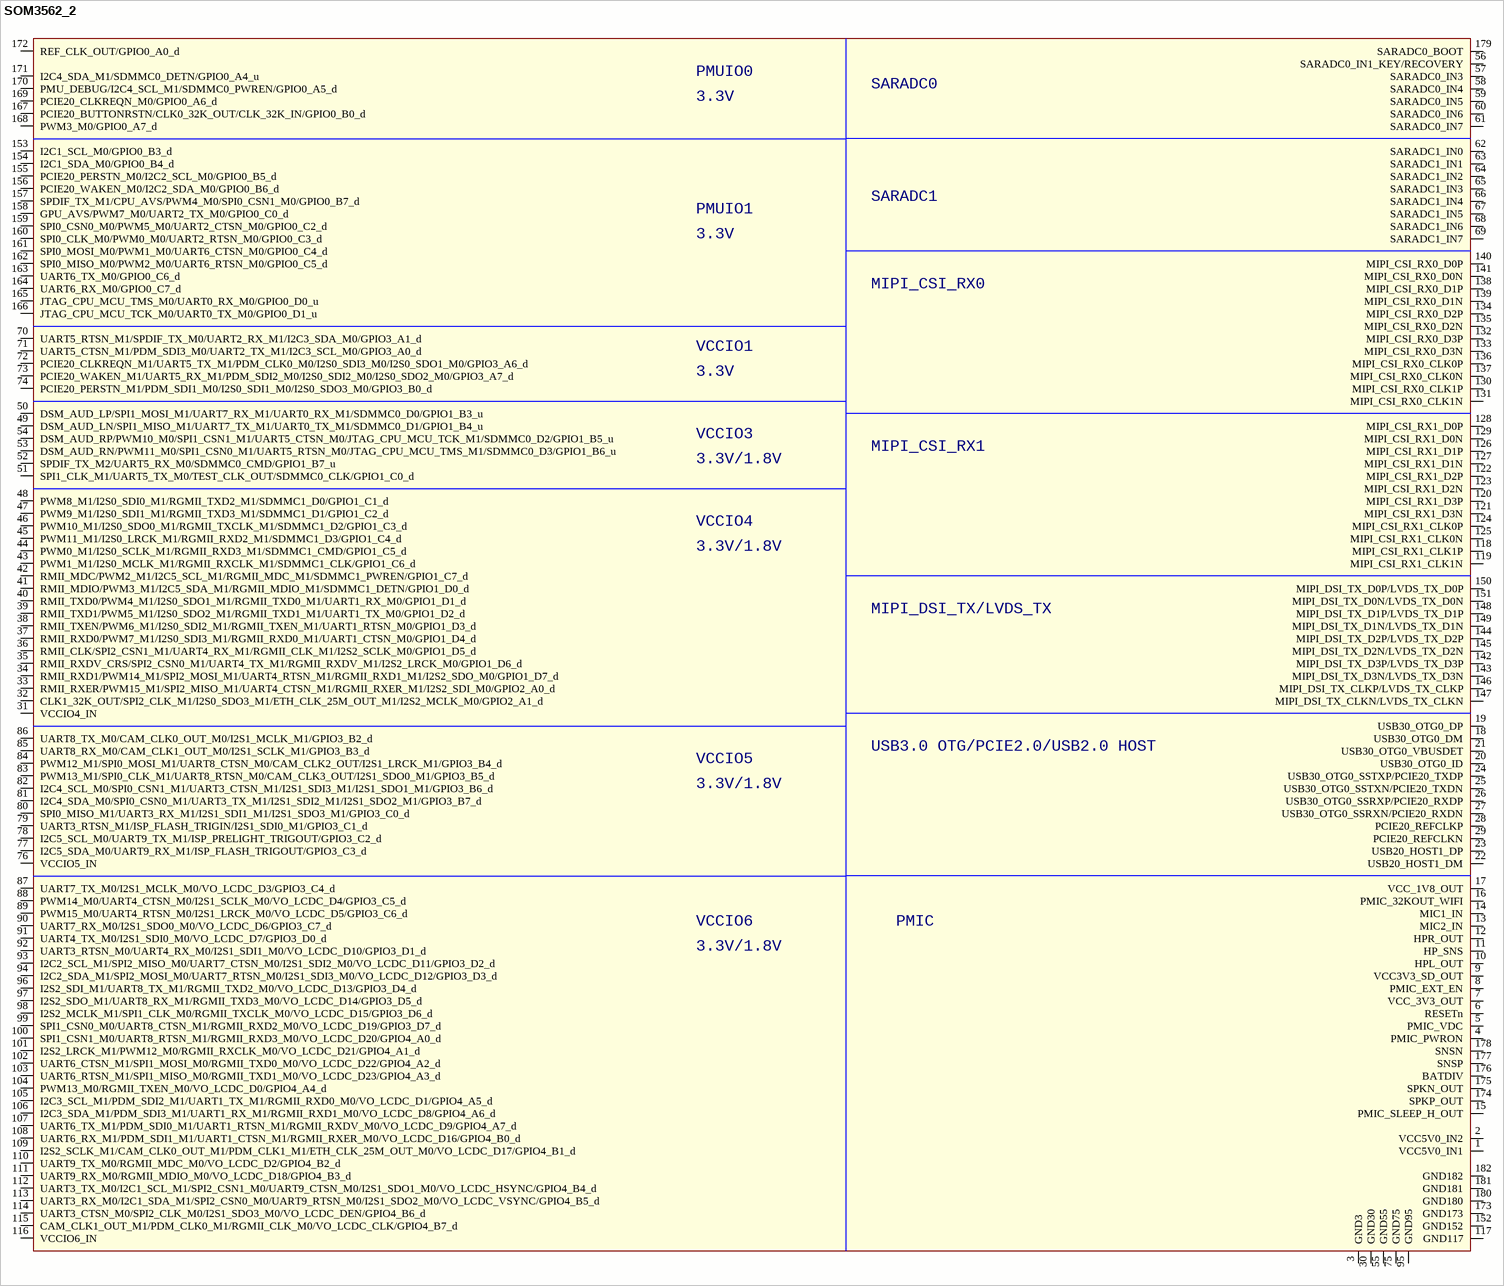
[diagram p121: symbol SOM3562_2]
## SOM3562_2
designator M?
footprint SOM3562-182P
pins: 1 VCC5V0_IN1, 2 VCC5V0_IN2, 3 GND3, 4 PMIC_PWRON, 5 PMIC_VDC, 6 RESETn, 7 VCC_3V3_OUT, 8 PMIC_EXT_EN, 9 VCC3V3_SD_OUT, 10 HPL_OUT, 11 HP_SNS, 12 HPR_OUT, 13 MIC2_IN, 14 MIC1_IN, 15 PMIC_SLEEP_H_OUT, 16 PMIC_32KOUT_WIFI, 17 VCC_1V8_OUT, 18 USB30_OTG0_DM, 19 USB30_OTG0_DP, 20 USB30_OTG0_ID, 21 USB30_OTG0_VBUSDET, 22 USB20_HOST1_DM, 23 USB20_HOST1_DP, 24 USB30_OTG0_SSTXP/PCIE20_TXDP, 25 USB30_OTG0_SSTXN/PCIE20_TXDN, 26 USB30_OTG0_SSRXP/PCIE20_RXDP, 27 USB30_OTG0_SSRXN/PCIE20_RXDN, 28 PCIE20_REFCLKP, 29 PCIE20_REFCLKN, 30 GND30, 31 VCCIO4_IN, 32 CLK1_32K_OUT/SPI2_CLK_M1/I2S0_SDO3_M1/ETH_CLK_25M_OUT_M1/I2S2_MCLK_M0/GPIO2_A1_d, 33 RMII_RXER/PWM15_M1/SPI2_MISO_M1/UART4_CTSN_M1/RGMII_RXER_M1/I2S2_SDI_M0/GPIO2_A0_d, 34 RMII_RXD1/PWM14_M1/SPI2_MOSI_M1/UART4_RTSN_M1/RGMII_RXD1_M1/I2S2_SDO_M0/GPIO1_D7_d, 35 RMII_RXDV_CRS/SPI2_CSN0_M1/UART4_TX_M1/RGMII_RXDV_M1/I2S2_LRCK_M0/GPIO1_D6_d, 36 RMII_CLK/SPI2_CSN1_M1/UART4_RX_M1/RGMII_CLK_M1/I2S2_SCLK_M0/GPIO1_D5_d, 37 RMII_RXD0/PWM7_M1/I2S0_SDI3_M1/RGMII_RXD0_M1/UART1_CTSN_M0/GPIO1_D4_d, 38 RMII_TXEN/PWM6_M1/I2S0_SDI2_M1/RGMII_TXEN_M1/UART1_RTSN_M0/GPIO1_D3_d, 39 RMII_TXD1/PWM5_M1/I2S0_SDO2_M1/RGMII_TXD1_M1/UART1_TX_M0/GPIO1_D2_d, 40 RMII_TXD0/PWM4_M1/I2S0_SDO1_M1/RGMII_TXD0_M1/UART1_RX_M0/GPIO1_D1_d, 41 RMII_MDIO/PWM3_M1/I2C5_SDA_M1/RGMII_MDIO_M1/SDMMC1_DETN/GPIO1_D0_d, 42 RMII_MDC/PWM2_M1/I2C5_SCL_M1/RGMII_MDC_M1/SDMMC1_PWREN/GPIO1_C7_d, 43 PWM1_M1/I2S0_MCLK_M1/RGMII_RXCLK_M1/SDMMC1_CLK/GPIO1_C6_d, 44 PWM0_M1/I2S0_SCLK_M1/RGMII_RXD3_M1/SDMMC1_CMD/GPIO1_C5_d, 45 PWM11_M1/I2S0_LRCK_M1/RGMII_RXD2_M1/SDMMC1_D3/GPIO1_C4_d, 46 PWM10_M1/I2S0_SDO0_M1/RGMII_TXCLK_M1/SDMMC1_D2/GPIO1_C3_d, 47 PWM9_M1/I2S0_SDI1_M1/RGMII_TXD3_M1/SDMMC1_D1/GPIO1_C2_d, 48 PWM8_M1/I2S0_SDI0_M1/RGMII_TXD2_M1/SDMMC1_D0/GPIO1_C1_d, 49 DSM_AUD_LN/SPI1_MISO_M1/UART7_TX_M1/UART0_TX_M1/SDMMC0_D1/GPIO1_B4_u, 50 DSM_AUD_LP/SPI1_MOSI_M1/UART7_RX_M1/UART0_RX_M1/SDMMC0_D0/GPIO1_B3_u, 51 SPI1_CLK_M1/UART5_TX_M0/TEST_CLK_OUT/SDMMC0_CLK/GPIO1_C0_d, 52 SPDIF_TX_M2/UART5_RX_M0/SDMMC0_CMD/GPIO1_B7_u, 53 DSM_AUD_RN/PWM11_M0/SPI1_CSN0_M1/UART5_RTSN_M0/JTAG_CPU_MCU_TMS_M1/SDMMC0_D3/GPIO1_B6_u, 54 DSM_AUD_RP/PWM10_M0/SPI1_CSN1_M1/UART5_CTSN_M0/JTAG_CPU_MCU_TCK_M1/SDMMC0_D2/GPIO1_B5_u, 55 GND55, 56 SARADC0_IN1_KEY/RECOVERY, 57 SARADC0_IN3, 58 SARADC0_IN4, 59 SARADC0_IN5, 60 SARADC0_IN6, 61 SARADC0_IN7, 62 SARADC1_IN0, 63 SARADC1_IN1, 64 SARADC1_IN2, 65 SARADC1_IN3, 66 SARADC1_IN4, 67 SARADC1_IN5, 68 SARADC1_IN6, 69 SARADC1_IN7, 70 UART5_RTSN_M1/SPDIF_TX_M0/UART2_RX_M1/I2C3_SDA_M0/GPIO3_A1_d, 71 UART5_CTSN_M1/PDM_SDI3_M0/UART2_TX_M1/I2C3_SCL_M0/GPIO3_A0_d, 72 PCIE20_CLKREQN_M1/UART5_TX_M1/PDM_CLK0_M0/I2S0_SDI3_M0/I2S0_SDO1_M0/GPIO3_A6_d, 73 PCIE20_WAKEN_M1/UART5_RX_M1/PDM_SDI2_M0/I2S0_SDI2_M0/I2S0_SDO2_M0/GPIO3_A7_d, 74 PCIE20_PERSTN_M1/PDM_SDI1_M0/I2S0_SDI1_M0/I2S0_SDO3_M0/GPIO3_B0_d, 75 GND75, 76 VCCIO5_IN, 77 I2C5_SDA_M0/UART9_RX_M1/ISP_FLASH_TRIGOUT/GPIO3_C3_d, 78 I2C5_SCL_M0/UART9_TX_M1/ISP_PRELIGHT_TRIGOUT/GPIO3_C2_d, 79 UART3_RTSN_M1/ISP_FLASH_TRIGIN/I2S1_SDI0_M1/GPIO3_C1_d, 80 SPI0_MISO_M1/UART3_RX_M1/I2S1_SDI1_M1/I2S1_SDO3_M1/GPIO3_C0_d, 81 I2C4_SDA_M0/SPI0_CSN0_M1/UART3_TX_M1/I2S1_SDI2_M1/I2S1_SDO2_M1/GPIO3_B7_d, 82 I2C4_SCL_M0/SPI0_CSN1_M1/UART3_CTSN_M1/I2S1_SDI3_M1/I2S1_SDO1_M1/GPIO3_B6_d, 83 PWM13_M1/SPI0_CLK_M1/UART8_RTSN_M0/CAM_CLK3_OUT/I2S1_SDO0_M1/GPIO3_B5_d, 84 PWM12_M1/SPI0_MOSI_M1/UART8_CTSN_M0/CAM_CLK2_OUT/I2S1_LRCK_M1/GPIO3_B4_d, 85 UART8_RX_M0/CAM_CLK1_OUT_M0/I2S1_SCLK_M1/GPIO3_B3_d, 86 UART8_TX_M0/CAM_CLK0_OUT_M0/I2S1_MCLK_M1/GPIO3_B2_d, 87 UART7_TX_M0/I2S1_MCLK_M0/VO_LCDC_D3/GPIO3_C4_d, 88 PWM14_M0/UART4_CTSN_M0/I2S1_SCLK_M0/VO_LCDC_D4/GPIO3_C5_d, 89 PWM15_M0/UART4_RTSN_M0/I2S1_LRCK_M0/VO_LCDC_D5/GPIO3_C6_d, 90 UART7_RX_M0/I2S1_SDO0_M0/VO_LCDC_D6/GPIO3_C7_d, 91 UART4_TX_M0/I2S1_SDI0_M0/VO_LCDC_D7/GPIO3_D0_d, 92 UART3_RTSN_M0/UART4_RX_M0/I2S1_SDI1_M0/VO_LCDC_D10/GPIO3_D1_d, 93 I2C2_SCL_M1/SPI2_MISO_M0/UART7_CTSN_M0/I2S1_SDI2_M0/VO_LCDC_D11/GPIO3_D2_d, 94 I2C2_SDA_M1/SPI2_MOSI_M0/UART7_RTSN_M0/I2S1_SDI3_M0/VO_LCDC_D12/GPIO3_D3_d, 95 GND95, 96 I2S2_SDI_M1/UART8_TX_M1/RGMII_TXD2_M0/VO_LCDC_D13/GPIO3_D4_d, 97 I2S2_SDO_M1/UART8_RX_M1/RGMII_TXD3_M0/VO_LCDC_D14/GPIO3_D5_d, 98 I2S2_MCLK_M1/SPI1_CLK_M0/RGMII_TXCLK_M0/VO_LCDC_D15/GPIO3_D6_d, 99 SPI1_CSN0_M0/UART8_CTSN_M1/RGMII_RXD2_M0/VO_LCDC_D19/GPIO3_D7_d, 100 SPI1_CSN1_M0/UART8_RTSN_M1/RGMII_RXD3_M0/VO_LCDC_D20/GPIO4_A0_d, 101 I2S2_LRCK_M1/PWM12_M0/RGMII_RXCLK_M0/VO_LCDC_D21/GPIO4_A1_d, 102 UART6_CTSN_M1/SPI1_MOSI_M0/RGMII_TXD0_M0/VO_LCDC_D22/GPIO4_A2_d, 103 UART6_RTSN_M1/SPI1_MISO_M0/RGMII_TXD1_M0/VO_LCDC_D23/GPIO4_A3_d, 104 PWM13_M0/RGMII_TXEN_M0/VO_LCDC_D0/GPIO4_A4_d, 105 I2C3_SCL_M1/PDM_SDI2_M1/UART1_TX_M1/RGMII_RXD0_M0/VO_LCDC_D1/GPIO4_A5_d, 106 I2C3_SDA_M1/PDM_SDI3_M1/UART1_RX_M1/RGMII_RXD1_M0/VO_LCDC_D8/GPIO4_A6_d, 107 UART6_TX_M1/PDM_SDI0_M1/UART1_RTSN_M1/RGMII_RXDV_M0/VO_LCDC_D9/GPIO4_A7_d, 108 UART6_RX_M1/PDM_SDI1_M1/UART1_CTSN_M1/RGMII_RXER_M0/VO_LCDC_D16/GPIO4_B0_d, 109 I2S2_SCLK_M1/CAM_CLK0_OUT_M1/PDM_CLK1_M1/ETH_CLK_25M_OUT_M0/VO_LCDC_D17/GPIO4_B1_d, 110 UART9_TX_M0/RGMII_MDC_M0/VO_LCDC_D2/GPIO4_B2_d, 111 UART9_RX_M0/RGMII_MDIO_M0/VO_LCDC_D18/GPIO4_B3_d, 112 UART3_TX_M0/I2C1_SCL_M1/SPI2_CSN1_M0/UART9_CTSN_M0/I2S1_SDO1_M0/VO_LCDC_HSYNC/GPIO4_B4_d, 113 UART3_RX_M0/I2C1_SDA_M1/SPI2_CSN0_M0/UART9_RTSN_M0/I2S1_SDO2_M0/VO_LCDC_VSYNC/GPIO4_B5_d, 114 UART3_CTSN_M0/SPI2_CLK_M0/I2S1_SDO3_M0/VO_LCDC_DEN/GPIO4_B6_d, 115 CAM_CLK1_OUT_M1/PDM_CLK0_M1/RGMII_CLK_M0/VO_LCDC_CLK/GPIO4_B7_d, 116 VCCIO6_IN, 117 GND117, 118 MIPI_CSI_RX1_CLK1P, 119 MIPI_CSI_RX1_CLK1N, 120 MIPI_CSI_RX1_D3P, 121 MIPI_CSI_RX1_D3N, 122 MIPI_CSI_RX1_D2P, 123 MIPI_CSI_RX1_D2N, 124 MIPI_CSI_RX1_CLK0P, 125 MIPI_CSI_RX1_CLK0N, 126 MIPI_CSI_RX1_D1P, 127 MIPI_CSI_RX1_D1N, 128 MIPI_CSI_RX1_D0P, 129 MIPI_CSI_RX1_D0N, 130 MIPI_CSI_RX0_CLK1P, 131 MIPI_CSI_RX0_CLK1N, 132 MIPI_CSI_RX0_D3P, 133 MIPI_CSI_RX0_D3N, 134 MIPI_CSI_RX0_D2P, 135 MIPI_CSI_RX0_D2N, 136 MIPI_CSI_RX0_CLK0P, 137 MIPI_CSI_RX0_CLK0N, 138 MIPI_CSI_RX0_D1P, 139 MIPI_CSI_RX0_D1N, 140 MIPI_CSI_RX0_D0P, 141 MIPI_CSI_RX0_D0N, 142 MIPI_DSI_TX_D3P/LVDS_TX_D3P, 143 MIPI_DSI_TX_D3N/LVDS_TX_D3N, 144 MIPI_DSI_TX_D2P/LVDS_TX_D2P, 145 MIPI_DSI_TX_D2N/LVDS_TX_D2N, 146 MIPI_DSI_TX_CLKP/LVDS_TX_CLKP, 147 MIPI_DSI_TX_CLKN/LVDS_TX_CLKN, 148 MIPI_DSI_TX_D1P/LVDS_TX_D1P, 149 MIPI_DSI_TX_D1N/LVDS_TX_D1N, 150 MIPI_DSI_TX_D0P/LVDS_TX_D0P, 151 MIPI_DSI_TX_D0N/LVDS_TX_D0N, 152 GND152, 153 I2C1_SCL_M0/GPIO0_B3_d, 154 I2C1_SDA_M0/GPIO0_B4_d, 155 PCIE20_PERSTN_M0/I2C2_SCL_M0/GPIO0_B5_d, 156 PCIE20_WAKEN_M0/I2C2_SDA_M0/GPIO0_B6_d, 157 SPDIF_TX_M1/CPU_AVS/PWM4_M0/SPI0_CSN1_M0/GPIO0_B7_d, 158 GPU_AVS/PWM7_M0/UART2_TX_M0/GPIO0_C0_d, 159 SPI0_CSN0_M0/PWM5_M0/UART2_CTSN_M0/GPIO0_C2_d, 160 SPI0_CLK_M0/PWM0_M0/UART2_RTSN_M0/GPIO0_C3_d, 161 SPI0_MOSI_M0/PWM1_M0/UART6_CTSN_M0/GPIO0_C4_d, 162 SPI0_MISO_M0/PWM2_M0/UART6_RTSN_M0/GPIO0_C5_d, 163 UART6_TX_M0/GPIO0_C6_d, 164 UART6_RX_M0/GPIO0_C7_d, 165 JTAG_CPU_MCU_TMS_M0/UART0_RX_M0/GPIO0_D0_u, 166 JTAG_CPU_MCU_TCK_M0/UART0_TX_M0/GPIO0_D1_u, 167 PCIE20_BUTTONRSTN/CLK0_32K_OUT/CLK_32K_IN/GPIO0_B0_d, 168 PWM3_M0/GPIO0_A7_d, 169 PCIE20_CLKREQN_M0/GPIO0_A6_d, 170 PMU_DEBUG/I2C4_SCL_M1/SDMMC0_PWREN/GPIO0_A5_d, 171 I2C4_SDA_M1/SDMMC0_DETN/GPIO0_A4_u, 172 REF_CLK_OUT/GPIO0_A0_d, 173 GND173, 174 SPKP_OUT, 175 SPKN_OUT, 176 BATDIV, 177 SNSP, 178 SNSN, 179 SARADC0_BOOT, 180 GND180, 181 GND181, 182 GND182


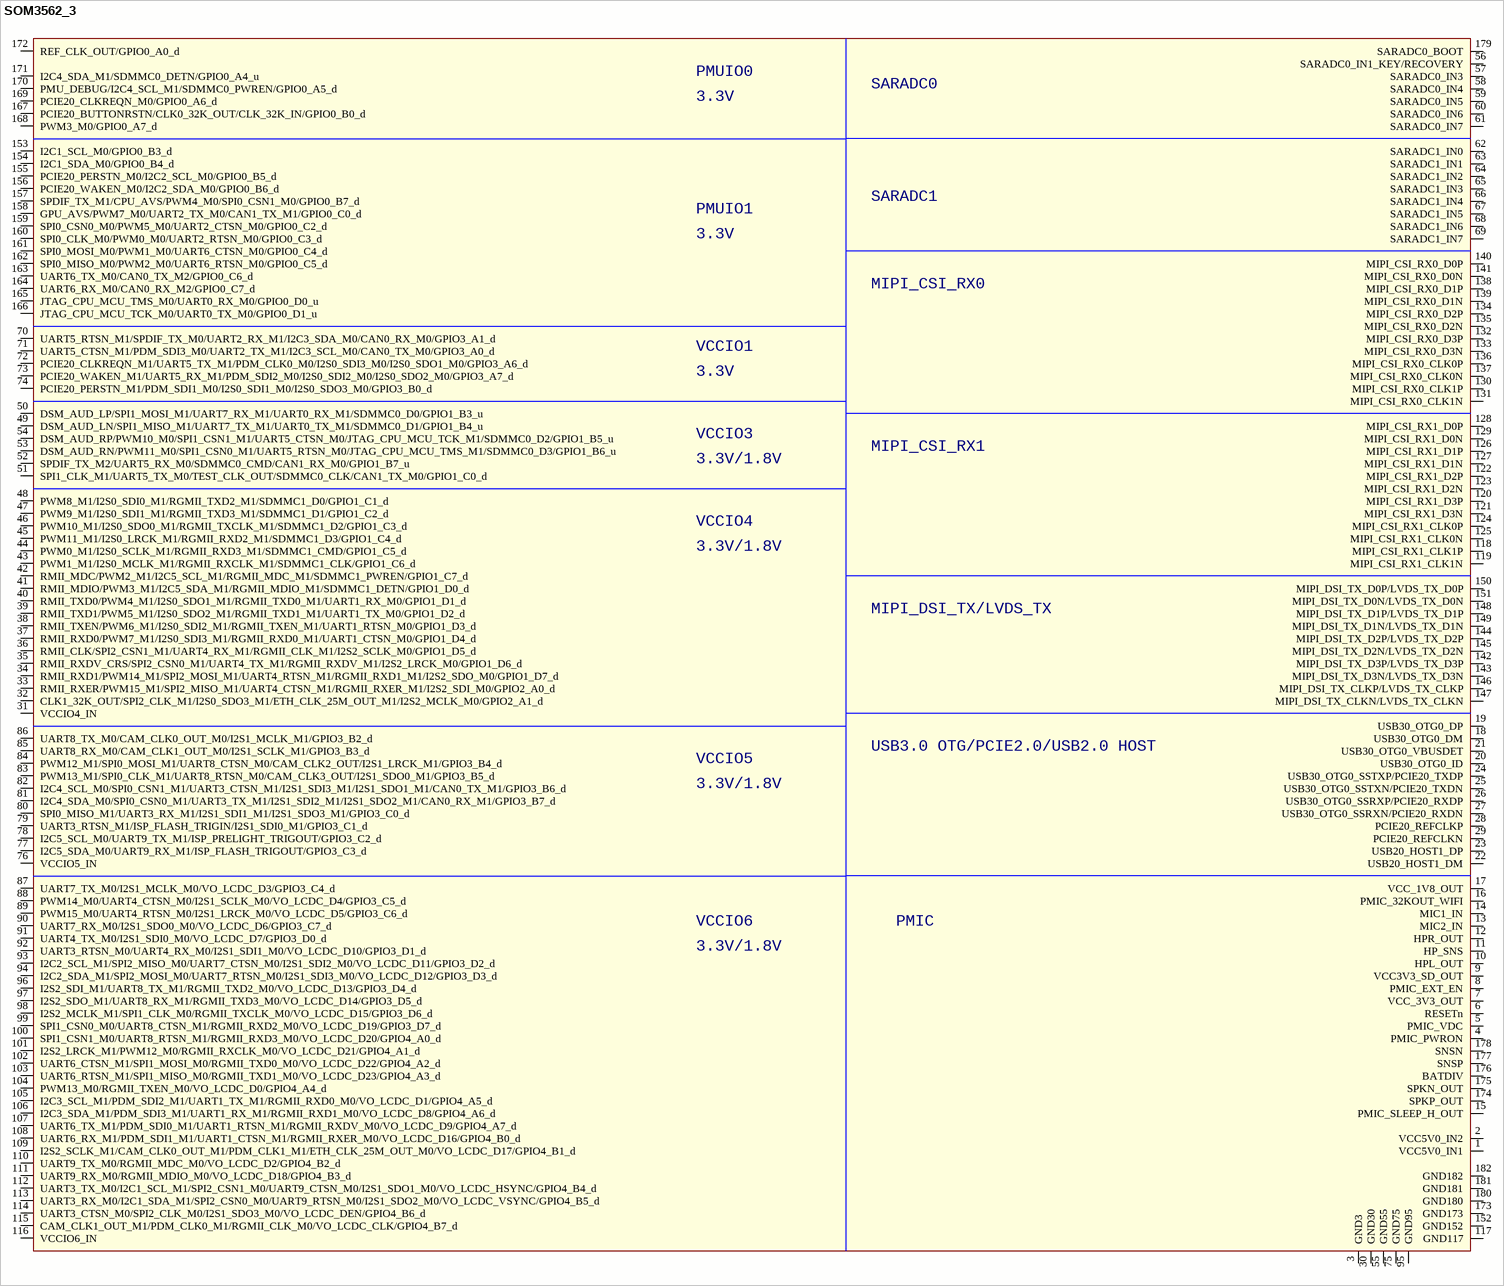
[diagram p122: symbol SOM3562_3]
## SOM3562_3
designator M?
footprint SOM3562-182P
pins: 1 VCC5V0_IN1, 2 VCC5V0_IN2, 3 GND3, 4 PMIC_PWRON, 5 PMIC_VDC, 6 RESETn, 7 VCC_3V3_OUT, 8 PMIC_EXT_EN, 9 VCC3V3_SD_OUT, 10 HPL_OUT, 11 HP_SNS, 12 HPR_OUT, 13 MIC2_IN, 14 MIC1_IN, 15 PMIC_SLEEP_H_OUT, 16 PMIC_32KOUT_WIFI, 17 VCC_1V8_OUT, 18 USB30_OTG0_DM, 19 USB30_OTG0_DP, 20 USB30_OTG0_ID, 21 USB30_OTG0_VBUSDET, 22 USB20_HOST1_DM, 23 USB20_HOST1_DP, 24 USB30_OTG0_SSTXP/PCIE20_TXDP, 25 USB30_OTG0_SSTXN/PCIE20_TXDN, 26 USB30_OTG0_SSRXP/PCIE20_RXDP, 27 USB30_OTG0_SSRXN/PCIE20_RXDN, 28 PCIE20_REFCLKP, 29 PCIE20_REFCLKN, 30 GND30, 31 VCCIO4_IN, 32 CLK1_32K_OUT/SPI2_CLK_M1/I2S0_SDO3_M1/ETH_CLK_25M_OUT_M1/I2S2_MCLK_M0/GPIO2_A1_d, 33 RMII_RXER/PWM15_M1/SPI2_MISO_M1/UART4_CTSN_M1/RGMII_RXER_M1/I2S2_SDI_M0/GPIO2_A0_d, 34 RMII_RXD1/PWM14_M1/SPI2_MOSI_M1/UART4_RTSN_M1/RGMII_RXD1_M1/I2S2_SDO_M0/GPIO1_D7_d, 35 RMII_RXDV_CRS/SPI2_CSN0_M1/UART4_TX_M1/RGMII_RXDV_M1/I2S2_LRCK_M0/GPIO1_D6_d, 36 RMII_CLK/SPI2_CSN1_M1/UART4_RX_M1/RGMII_CLK_M1/I2S2_SCLK_M0/GPIO1_D5_d, 37 RMII_RXD0/PWM7_M1/I2S0_SDI3_M1/RGMII_RXD0_M1/UART1_CTSN_M0/GPIO1_D4_d, 38 RMII_TXEN/PWM6_M1/I2S0_SDI2_M1/RGMII_TXEN_M1/UART1_RTSN_M0/GPIO1_D3_d, 39 RMII_TXD1/PWM5_M1/I2S0_SDO2_M1/RGMII_TXD1_M1/UART1_TX_M0/GPIO1_D2_d, 40 RMII_TXD0/PWM4_M1/I2S0_SDO1_M1/RGMII_TXD0_M1/UART1_RX_M0/GPIO1_D1_d, 41 RMII_MDIO/PWM3_M1/I2C5_SDA_M1/RGMII_MDIO_M1/SDMMC1_DETN/GPIO1_D0_d, 42 RMII_MDC/PWM2_M1/I2C5_SCL_M1/RGMII_MDC_M1/SDMMC1_PWREN/GPIO1_C7_d, 43 PWM1_M1/I2S0_MCLK_M1/RGMII_RXCLK_M1/SDMMC1_CLK/GPIO1_C6_d, 44 PWM0_M1/I2S0_SCLK_M1/RGMII_RXD3_M1/SDMMC1_CMD/GPIO1_C5_d, 45 PWM11_M1/I2S0_LRCK_M1/RGMII_RXD2_M1/SDMMC1_D3/GPIO1_C4_d, 46 PWM10_M1/I2S0_SDO0_M1/RGMII_TXCLK_M1/SDMMC1_D2/GPIO1_C3_d, 47 PWM9_M1/I2S0_SDI1_M1/RGMII_TXD3_M1/SDMMC1_D1/GPIO1_C2_d, 48 PWM8_M1/I2S0_SDI0_M1/RGMII_TXD2_M1/SDMMC1_D0/GPIO1_C1_d, 49 DSM_AUD_LN/SPI1_MISO_M1/UART7_TX_M1/UART0_TX_M1/SDMMC0_D1/GPIO1_B4_u, 50 DSM_AUD_LP/SPI1_MOSI_M1/UART7_RX_M1/UART0_RX_M1/SDMMC0_D0/GPIO1_B3_u, 51 SPI1_CLK_M1/UART5_TX_M0/TEST_CLK_OUT/SDMMC0_CLK/CAN1_TX_M0/GPIO1_C0_d, 52 SPDIF_TX_M2/UART5_RX_M0/SDMMC0_CMD/CAN1_RX_M0/GPIO1_B7_u, 53 DSM_AUD_RN/PWM11_M0/SPI1_CSN0_M1/UART5_RTSN_M0/JTAG_CPU_MCU_TMS_M1/SDMMC0_D3/GPIO1_B6_u, 54 DSM_AUD_RP/PWM10_M0/SPI1_CSN1_M1/UART5_CTSN_M0/JTAG_CPU_MCU_TCK_M1/SDMMC0_D2/GPIO1_B5_u, 55 GND55, 56 SARADC0_IN1_KEY/RECOVERY, 57 SARADC0_IN3, 58 SARADC0_IN4, 59 SARADC0_IN5, 60 SARADC0_IN6, 61 SARADC0_IN7, 62 SARADC1_IN0, 63 SARADC1_IN1, 64 SARADC1_IN2, 65 SARADC1_IN3, 66 SARADC1_IN4, 67 SARADC1_IN5, 68 SARADC1_IN6, 69 SARADC1_IN7, 70 UART5_RTSN_M1/SPDIF_TX_M0/UART2_RX_M1/I2C3_SDA_M0/CAN0_RX_M0/GPIO3_A1_d, 71 UART5_CTSN_M1/PDM_SDI3_M0/UART2_TX_M1/I2C3_SCL_M0/CAN0_TX_M0/GPIO3_A0_d, 72 PCIE20_CLKREQN_M1/UART5_TX_M1/PDM_CLK0_M0/I2S0_SDI3_M0/I2S0_SDO1_M0/GPIO3_A6_d, 73 PCIE20_WAKEN_M1/UART5_RX_M1/PDM_SDI2_M0/I2S0_SDI2_M0/I2S0_SDO2_M0/GPIO3_A7_d, 74 PCIE20_PERSTN_M1/PDM_SDI1_M0/I2S0_SDI1_M0/I2S0_SDO3_M0/GPIO3_B0_d, 75 GND75, 76 VCCIO5_IN, 77 I2C5_SDA_M0/UART9_RX_M1/ISP_FLASH_TRIGOUT/GPIO3_C3_d, 78 I2C5_SCL_M0/UART9_TX_M1/ISP_PRELIGHT_TRIGOUT/GPIO3_C2_d, 79 UART3_RTSN_M1/ISP_FLASH_TRIGIN/I2S1_SDI0_M1/GPIO3_C1_d, 80 SPI0_MISO_M1/UART3_RX_M1/I2S1_SDI1_M1/I2S1_SDO3_M1/GPIO3_C0_d, 81 I2C4_SDA_M0/SPI0_CSN0_M1/UART3_TX_M1/I2S1_SDI2_M1/I2S1_SDO2_M1/CAN0_RX_M1/GPIO3_B7_d, 82 I2C4_SCL_M0/SPI0_CSN1_M1/UART3_CTSN_M1/I2S1_SDI3_M1/I2S1_SDO1_M1/CAN0_TX_M1/GPIO3_B6_d, 83 PWM13_M1/SPI0_CLK_M1/UART8_RTSN_M0/CAM_CLK3_OUT/I2S1_SDO0_M1/GPIO3_B5_d, 84 PWM12_M1/SPI0_MOSI_M1/UART8_CTSN_M0/CAM_CLK2_OUT/I2S1_LRCK_M1/GPIO3_B4_d, 85 UART8_RX_M0/CAM_CLK1_OUT_M0/I2S1_SCLK_M1/GPIO3_B3_d, 86 UART8_TX_M0/CAM_CLK0_OUT_M0/I2S1_MCLK_M1/GPIO3_B2_d, 87 UART7_TX_M0/I2S1_MCLK_M0/VO_LCDC_D3/GPIO3_C4_d, 88 PWM14_M0/UART4_CTSN_M0/I2S1_SCLK_M0/VO_LCDC_D4/GPIO3_C5_d, 89 PWM15_M0/UART4_RTSN_M0/I2S1_LRCK_M0/VO_LCDC_D5/GPIO3_C6_d, 90 UART7_RX_M0/I2S1_SDO0_M0/VO_LCDC_D6/GPIO3_C7_d, 91 UART4_TX_M0/I2S1_SDI0_M0/VO_LCDC_D7/GPIO3_D0_d, 92 UART3_RTSN_M0/UART4_RX_M0/I2S1_SDI1_M0/VO_LCDC_D10/GPIO3_D1_d, 93 I2C2_SCL_M1/SPI2_MISO_M0/UART7_CTSN_M0/I2S1_SDI2_M0/VO_LCDC_D11/GPIO3_D2_d, 94 I2C2_SDA_M1/SPI2_MOSI_M0/UART7_RTSN_M0/I2S1_SDI3_M0/VO_LCDC_D12/GPIO3_D3_d, 95 GND95, 96 I2S2_SDI_M1/UART8_TX_M1/RGMII_TXD2_M0/VO_LCDC_D13/GPIO3_D4_d, 97 I2S2_SDO_M1/UART8_RX_M1/RGMII_TXD3_M0/VO_LCDC_D14/GPIO3_D5_d, 98 I2S2_MCLK_M1/SPI1_CLK_M0/RGMII_TXCLK_M0/VO_LCDC_D15/GPIO3_D6_d, 99 SPI1_CSN0_M0/UART8_CTSN_M1/RGMII_RXD2_M0/VO_LCDC_D19/GPIO3_D7_d, 100 SPI1_CSN1_M0/UART8_RTSN_M1/RGMII_RXD3_M0/VO_LCDC_D20/GPIO4_A0_d, 101 I2S2_LRCK_M1/PWM12_M0/RGMII_RXCLK_M0/VO_LCDC_D21/GPIO4_A1_d, 102 UART6_CTSN_M1/SPI1_MOSI_M0/RGMII_TXD0_M0/VO_LCDC_D22/GPIO4_A2_d, 103 UART6_RTSN_M1/SPI1_MISO_M0/RGMII_TXD1_M0/VO_LCDC_D23/GPIO4_A3_d, 104 PWM13_M0/RGMII_TXEN_M0/VO_LCDC_D0/GPIO4_A4_d, 105 I2C3_SCL_M1/PDM_SDI2_M1/UART1_TX_M1/RGMII_RXD0_M0/VO_LCDC_D1/GPIO4_A5_d, 106 I2C3_SDA_M1/PDM_SDI3_M1/UART1_RX_M1/RGMII_RXD1_M0/VO_LCDC_D8/GPIO4_A6_d, 107 UART6_TX_M1/PDM_SDI0_M1/UART1_RTSN_M1/RGMII_RXDV_M0/VO_LCDC_D9/GPIO4_A7_d, 108 UART6_RX_M1/PDM_SDI1_M1/UART1_CTSN_M1/RGMII_RXER_M0/VO_LCDC_D16/GPIO4_B0_d, 109 I2S2_SCLK_M1/CAM_CLK0_OUT_M1/PDM_CLK1_M1/ETH_CLK_25M_OUT_M0/VO_LCDC_D17/GPIO4_B1_d, 110 UART9_TX_M0/RGMII_MDC_M0/VO_LCDC_D2/GPIO4_B2_d, 111 UART9_RX_M0/RGMII_MDIO_M0/VO_LCDC_D18/GPIO4_B3_d, 112 UART3_TX_M0/I2C1_SCL_M1/SPI2_CSN1_M0/UART9_CTSN_M0/I2S1_SDO1_M0/VO_LCDC_HSYNC/GPIO4_B4_d, 113 UART3_RX_M0/I2C1_SDA_M1/SPI2_CSN0_M0/UART9_RTSN_M0/I2S1_SDO2_M0/VO_LCDC_VSYNC/GPIO4_B5_d, 114 UART3_CTSN_M0/SPI2_CLK_M0/I2S1_SDO3_M0/VO_LCDC_DEN/GPIO4_B6_d, 115 CAM_CLK1_OUT_M1/PDM_CLK0_M1/RGMII_CLK_M0/VO_LCDC_CLK/GPIO4_B7_d, 116 VCCIO6_IN, 117 GND117, 118 MIPI_CSI_RX1_CLK1P, 119 MIPI_CSI_RX1_CLK1N, 120 MIPI_CSI_RX1_D3P, 121 MIPI_CSI_RX1_D3N, 122 MIPI_CSI_RX1_D2P, 123 MIPI_CSI_RX1_D2N, 124 MIPI_CSI_RX1_CLK0P, 125 MIPI_CSI_RX1_CLK0N, 126 MIPI_CSI_RX1_D1P, 127 MIPI_CSI_RX1_D1N, 128 MIPI_CSI_RX1_D0P, 129 MIPI_CSI_RX1_D0N, 130 MIPI_CSI_RX0_CLK1P, 131 MIPI_CSI_RX0_CLK1N, 132 MIPI_CSI_RX0_D3P, 133 MIPI_CSI_RX0_D3N, 134 MIPI_CSI_RX0_D2P, 135 MIPI_CSI_RX0_D2N, 136 MIPI_CSI_RX0_CLK0P, 137 MIPI_CSI_RX0_CLK0N, 138 MIPI_CSI_RX0_D1P, 139 MIPI_CSI_RX0_D1N, 140 MIPI_CSI_RX0_D0P, 141 MIPI_CSI_RX0_D0N, 142 MIPI_DSI_TX_D3P/LVDS_TX_D3P, 143 MIPI_DSI_TX_D3N/LVDS_TX_D3N, 144 MIPI_DSI_TX_D2P/LVDS_TX_D2P, 145 MIPI_DSI_TX_D2N/LVDS_TX_D2N, 146 MIPI_DSI_TX_CLKP/LVDS_TX_CLKP, 147 MIPI_DSI_TX_CLKN/LVDS_TX_CLKN, 148 MIPI_DSI_TX_D1P/LVDS_TX_D1P, 149 MIPI_DSI_TX_D1N/LVDS_TX_D1N, 150 MIPI_DSI_TX_D0P/LVDS_TX_D0P, 151 MIPI_DSI_TX_D0N/LVDS_TX_D0N, 152 GND152, 153 I2C1_SCL_M0/GPIO0_B3_d, 154 I2C1_SDA_M0/GPIO0_B4_d, 155 PCIE20_PERSTN_M0/I2C2_SCL_M0/GPIO0_B5_d, 156 PCIE20_WAKEN_M0/I2C2_SDA_M0/GPIO0_B6_d, 157 SPDIF_TX_M1/CPU_AVS/PWM4_M0/SPI0_CSN1_M0/GPIO0_B7_d, 158 GPU_AVS/PWM7_M0/UART2_TX_M0/CAN1_TX_M1/GPIO0_C0_d, 159 SPI0_CSN0_M0/PWM5_M0/UART2_CTSN_M0/GPIO0_C2_d, 160 SPI0_CLK_M0/PWM0_M0/UART2_RTSN_M0/GPIO0_C3_d, 161 SPI0_MOSI_M0/PWM1_M0/UART6_CTSN_M0/GPIO0_C4_d, 162 SPI0_MISO_M0/PWM2_M0/UART6_RTSN_M0/GPIO0_C5_d, 163 UART6_TX_M0/CAN0_TX_M2/GPIO0_C6_d, 164 UART6_RX_M0/CAN0_RX_M2/GPIO0_C7_d, 165 JTAG_CPU_MCU_TMS_M0/UART0_RX_M0/GPIO0_D0_u, 166 JTAG_CPU_MCU_TCK_M0/UART0_TX_M0/GPIO0_D1_u, 167 PCIE20_BUTTONRSTN/CLK0_32K_OUT/CLK_32K_IN/GPIO0_B0_d, 168 PWM3_M0/GPIO0_A7_d, 169 PCIE20_CLKREQN_M0/GPIO0_A6_d, 170 PMU_DEBUG/I2C4_SCL_M1/SDMMC0_PWREN/GPIO0_A5_d, 171 I2C4_SDA_M1/SDMMC0_DETN/GPIO0_A4_u, 172 REF_CLK_OUT/GPIO0_A0_d, 173 GND173, 174 SPKP_OUT, 175 SPKN_OUT, 176 BATDIV, 177 SNSP, 178 SNSN, 179 SARADC0_BOOT, 180 GND180, 181 GND181, 182 GND182


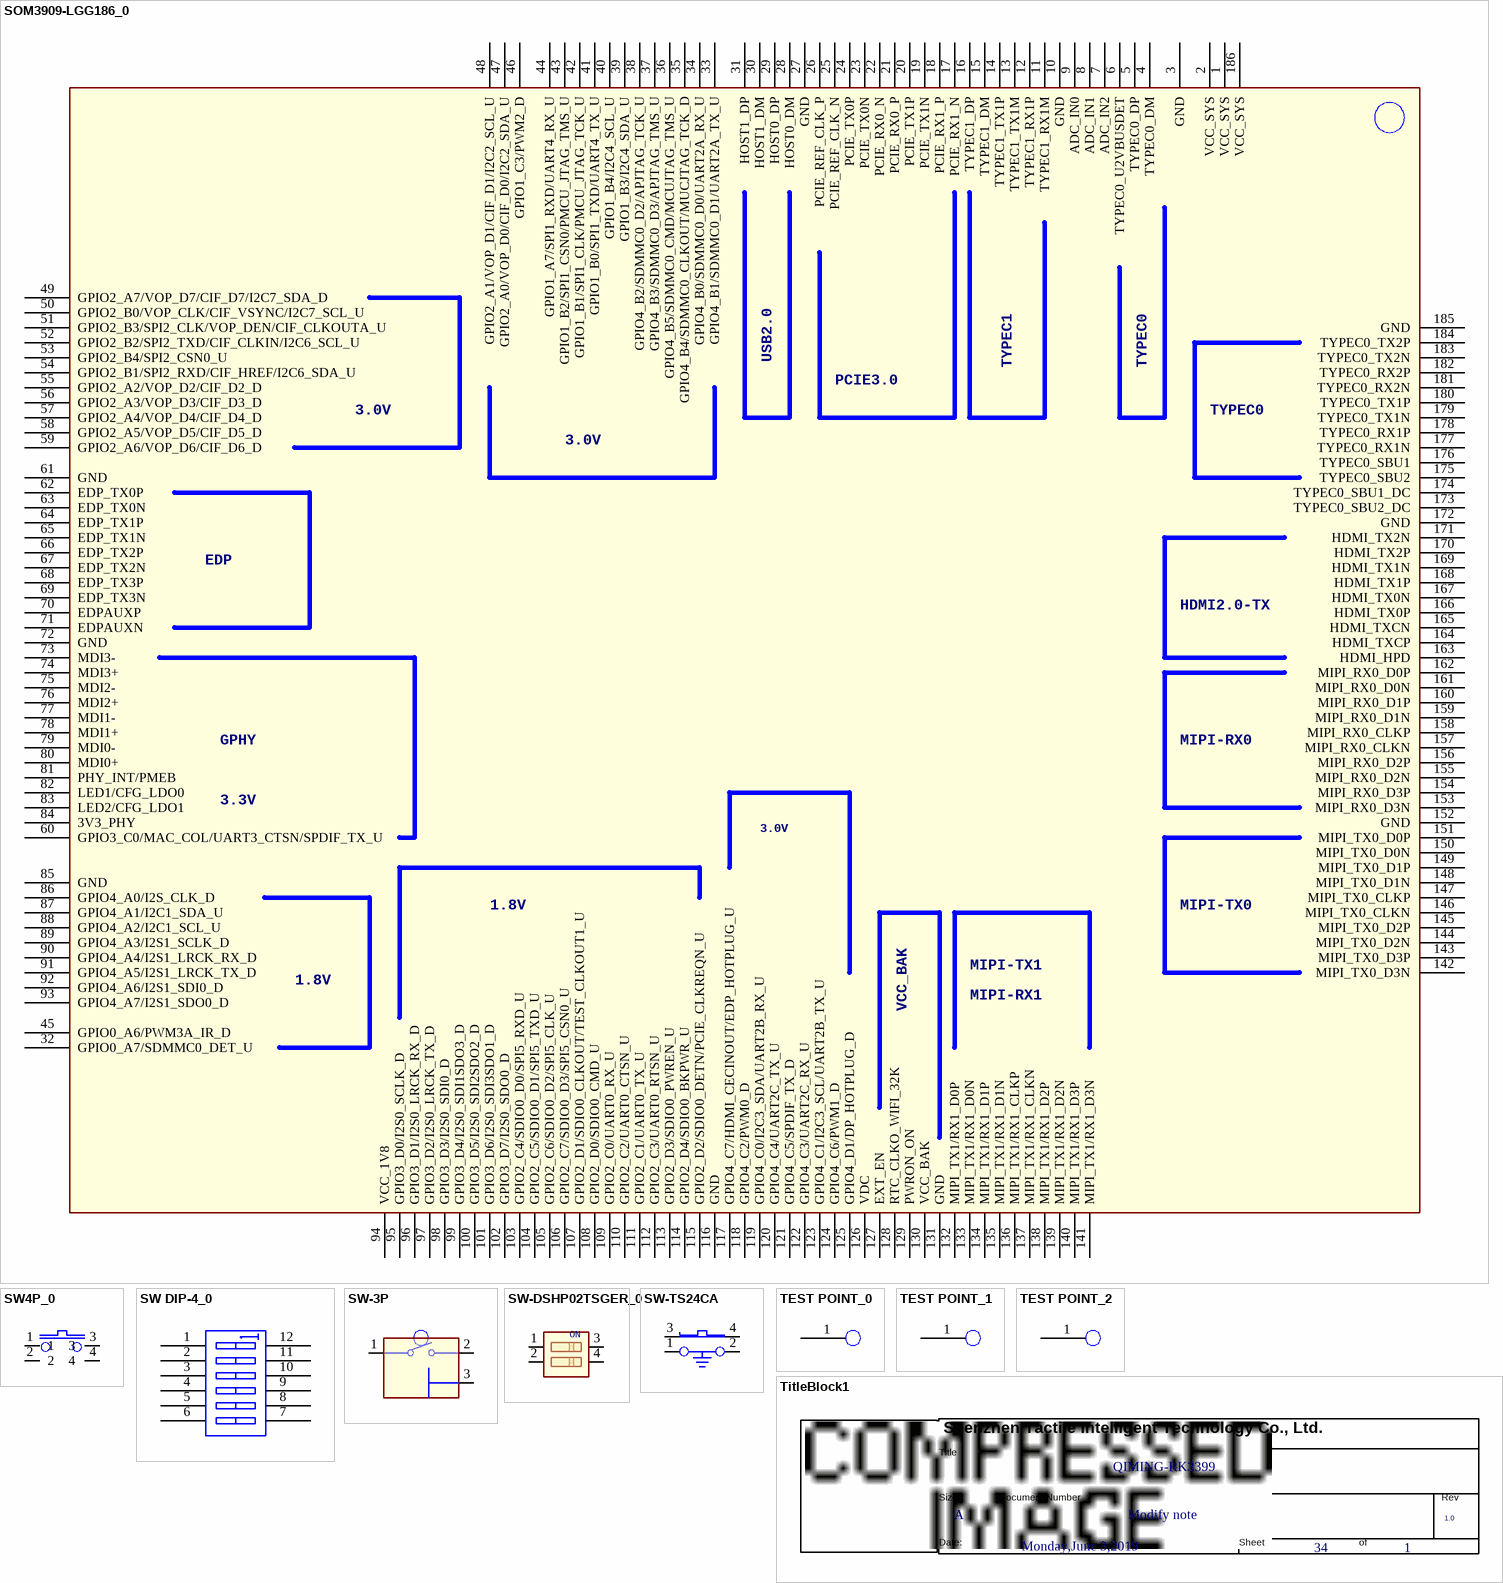
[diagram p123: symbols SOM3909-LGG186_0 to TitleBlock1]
## SOM3909-LGG186_0
designator M?
footprint IDO-SOM3909-LGG186
pins: 1 VCC_SYS (power), 2 VCC_SYS (power), 3 GND (power), 4 TYPEC0_DM, 5 TYPEC0_DP, 6 TYPEC0_U2VBUSDET, 7 ADC_IN2, 8 ADC_IN1, 9 ADC_IN0, 10 GND (power), 11 TYPEC1_RX1M, 12 TYPEC1_RX1P, 13 TYPEC1_TX1M, 14 TYPEC1_TX1P, 15 TYPEC1_DM, 16 TYPEC1_DP, 17 PCIE_RX1_N, 18 PCIE_RX1_P, 19 PCIE_TX1N, 20 PCIE_TX1P, 21 PCIE_RX0_P, 22 PCIE_RX0_N, 23 PCIE_TX0N, 24 PCIE_TX0P, 25 PCIE_REF_CLK_N, 26 PCIE_REF_CLK_P, 27 GND (power), 28 HOST0_DM, 29 HOST0_DP, 30 HOST1_DM, 31 HOST1_DP, 32 GPIO0_A7/SDMMC0_DET_U, 33 GPIO4_B1/SDMMC0_D1/UART2A_TX_U, 34 GPIO4_B0/SDMMC0_D0/UART2A_RX_U, 35 GPIO4_B4/SDMMC0_CLKOUT/MUCJTAG_TCK_D, 36 GPIO4_B5/SDMMC0_CMD/MCUJTAG_TMS_U, 37 GPIO4_B3/SDMMC0_D3/APJTAG_TMS_U, 38 GPIO4_B2/SDMMC0_D2/APJTAG_TCK_U, 39 GPIO1_B3/I2C4_SDA_U, 40 GPIO1_B4/I2C4_SCL_U, 41 GPIO1_B0/SPI1_TXD/UART4_TX_U, 42 GPIO1_B1/SPI1_CLK/PMCU_JTAG_TCK_U, 43 GPIO1_B2/SPI1_CSN0/PMCU_JTAG_TMS_U, 44 GPIO1_A7/SPI1_RXD/UART4_RX_U, 45 GPIO0_A6/PWM3A_IR_D, 46 GPIO1_C3/PWM2_D, 47 GPIO2_A0/VOP_D0/CIF_D0/I2C2_SDA_U, 48 GPIO2_A1/VOP_D1/CIF_D1/I2C2_SCL_U, 49 GPIO2_A7/VOP_D7/CIF_D7/I2C7_SDA_D, 50 GPIO2_B0/VOP_CLK/CIF_VSYNC/I2C7_SCL_U, 51 GPIO2_B3/SPI2_CLK/VOP_DEN/CIF_CLKOUTA_U, 52 GPIO2_B2/SPI2_TXD/CIF_CLKIN/I2C6_SCL_U, 53 GPIO2_B4/SPI2_CSN0_U, 54 GPIO2_B1/SPI2_RXD/CIF_HREF/I2C6_SDA_U, 55 GPIO2_A2/VOP_D2/CIF_D2_D, 56 GPIO2_A3/VOP_D3/CIF_D3_D, 57 GPIO2_A4/VOP_D4/CIF_D4_D, 58 GPIO2_A5/VOP_D5/CIF_D5_D, 59 GPIO2_A6/VOP_D6/CIF_D6_D, 60 GPIO3_C0/MAC_COL/UART3_CTSN/SPDIF_TX_U, 61 GND (power), 62 EDP_TX0P, 63 EDP_TX0N, 64 EDP_TX1P, 65 EDP_TX1N, 66 EDP_TX2P, 67 EDP_TX2N, 68 EDP_TX3P, 69 EDP_TX3N, 70 EDPAUXP, 71 EDPAUXN, 72 GND (power), 73 MDI3-, 74 MDI3+, 75 MDI2-, 76 MDI2+, 77 MDI1-, 78 MDI1+, 79 MDI0-, 80 MDI0+, 81 PHY_INT/PMEB, 82 LED1/CFG_LDO0, 83 LED2/CFG_LDO1, 84 3V3_PHY (power), 85 GND (power), 86 GPIO4_A0/I2S_CLK_D, 87 GPIO4_A1/I2C1_SDA_U, 88 GPIO4_A2/I2C1_SCL_U, 89 GPIO4_A3/I2S1_SCLK_D, 90 GPIO4_A4/I2S1_LRCK_RX_D, 91 GPIO4_A5/I2S1_LRCK_TX_D, 92 GPIO4_A6/I2S1_SDI0_D, 93 GPIO4_A7/I2S1_SDO0_D, 94 VCC_1V8 (power), 95 GPIO3_D0/I2S0_SCLK_D, 96 GPIO3_D1/I2S0_LRCK_RX_D, 97 GPIO3_D2/I2S0_LRCK_TX_D, 98 GPIO3_D3/I2S0_SDI0_D, 99 GPIO3_D4/I2S0_SDI1SDO3_D, 100 GPIO3_D5/I2S0_SDI2SDO2_D, 101 GPIO3_D6/I2S0_SDI3SDO1_D, 102 GPIO3_D7/I2S0_SDO0_D, 103 GPIO2_C4/SDIO0_D0/SPI5_RXD_U, 104 GPIO2_C5/SDIO0_D1/SPI5_TXD_U, 105 GPIO2_C6/SDIO0_D2/SPI5_CLK_U, 106 GPIO2_C7/SDIO0_D3/SPI5_CSN0_U, 107 GPIO2_D1/SDIO0_CLKOUT/TEST_CLKOUT1_U, 108 GPIO2_D0/SDIO0_CMD_U, 109 GPIO2_C0/UART0_RX_U, 110 GPIO2_C2/UART0_CTSN_U, 111 GPIO2_C1/UART0_TX_U, 112 GPIO2_C3/UART0_RTSN_U, 113 GPIO2_D3/SDIO0_PWREN_U, 114 GPIO2_D4/SDIO0_BKPWR_U, 115 GPIO2_D2/SDIO0_DETN/PCIE_CLKREQN_U, 116 GND (power), 117 GPIO4_C7/HDMI_CECINOUT/EDP_HOTPLUG_U, 118 GPIO4_C2/PWM0_D, 119 GPIO4_C0/I2C3_SDA/UART2B_RX_U, 120 GPIO4_C4/UART2C_TX_U, 121 GPIO4_C5/SPDIF_TX_D, 122 GPIO4_C3/UART2C_RX_U, 123 GPIO4_C1/I2C3_SCL/UART2B_TX_U, 124 GPIO4_C6/PWM1_D, 125 GPIO4_D1/DP_HOTPLUG_D, 126 VDC, 127 EXT_EN, 128 RTC_CLKO_WIFI_32K, 129 PWRON_ON, 130 VCC_BAK (power), 131 GND (power), 132 MIPI_TX1/RX1_D0P, 133 MIPI_TX1/RX1_D0N, 134 MIPI_TX1/RX1_D1P, 135 MIPI_TX1/RX1_D1N, 136 MIPI_TX1/RX1_CLKP, 137 MIPI_TX1/RX1_CLKN, 138 MIPI_TX1/RX1_D2P, 139 MIPI_TX1/RX1_D2N, 140 MIPI_TX1/RX1_D3P, 141 MIPI_TX1/RX1_D3N, 142 MIPI_TX0_D3N, 143 MIPI_TX0_D3P, 144 MIPI_TX0_D2N, 145 MIPI_TX0_D2P, 146 MIPI_TX0_CLKN, 147 MIPI_TX0_CLKP, 148 MIPI_TX0_D1N, 149 MIPI_TX0_D1P, 150 MIPI_TX0_D0N, 151 MIPI_TX0_D0P, 152 GND (power), 153 MIPI_RX0_D3N, 154 MIPI_RX0_D3P, 155 MIPI_RX0_D2N, 156 MIPI_RX0_D2P, 157 MIPI_RX0_CLKN, 158 MIPI_RX0_CLKP, 159 MIPI_RX0_D1N, 160 MIPI_RX0_D1P, 161 MIPI_RX0_D0N, 162 MIPI_RX0_D0P, 163 HDMI_HPD, 164 HDMI_TXCP, 165 HDMI_TXCN, 166 HDMI_TX0P, 167 HDMI_TX0N, 168 HDMI_TX1P, 169 HDMI_TX1N, 170 HDMI_TX2P, 171 HDMI_TX2N, 172 GND (power), 173 TYPEC0_SBU2_DC, 174 TYPEC0_SBU1_DC, 175 TYPEC0_SBU2, 176 TYPEC0_SBU1, 177 TYPEC0_RX1N, 178 TYPEC0_RX1P, 179 TYPEC0_TX1N, 180 TYPEC0_TX1P, 181 TYPEC0_RX2N, 182 TYPEC0_RX2P, 183 TYPEC0_TX2N, 184 TYPEC0_TX2P, 185 GND (power), 186 VCC_SYS (power)

## SW4P_0
designator SW?
pins: 1, 2, 3, 4

## SW DIP-4_0
designator S?
pins: 1 A1, 2 A2, 3 A3, 4 A4, 5 A5, 6 A6, 7 B6, 8 B5, 9 B4, 10 B3, 11 B2, 12 B1

## SW-3P
designator SW?
pins: 1, 2, 3

## SW-DSHP02TSGER_0
designator SW?
pins: 1, 2, 3, 4

## SW-TS24CA
designator SW?
pins: 1, 2, 3, 4

## TEST POINT_0
designator TP?
pins: 1

## TEST POINT_1
designator TP?
pins: 1

## TEST POINT_2
designator TP?
pins: 1

## TitleBlock1
designator *  Page Count: 1  Page Number: 34  Page Size: A  Title: QIMING-RK3399  RevCode: 1.0  Doc: Modify note  Page Modify Date: Monday,June 3,2019  (hidden comment: *)  (graphical)


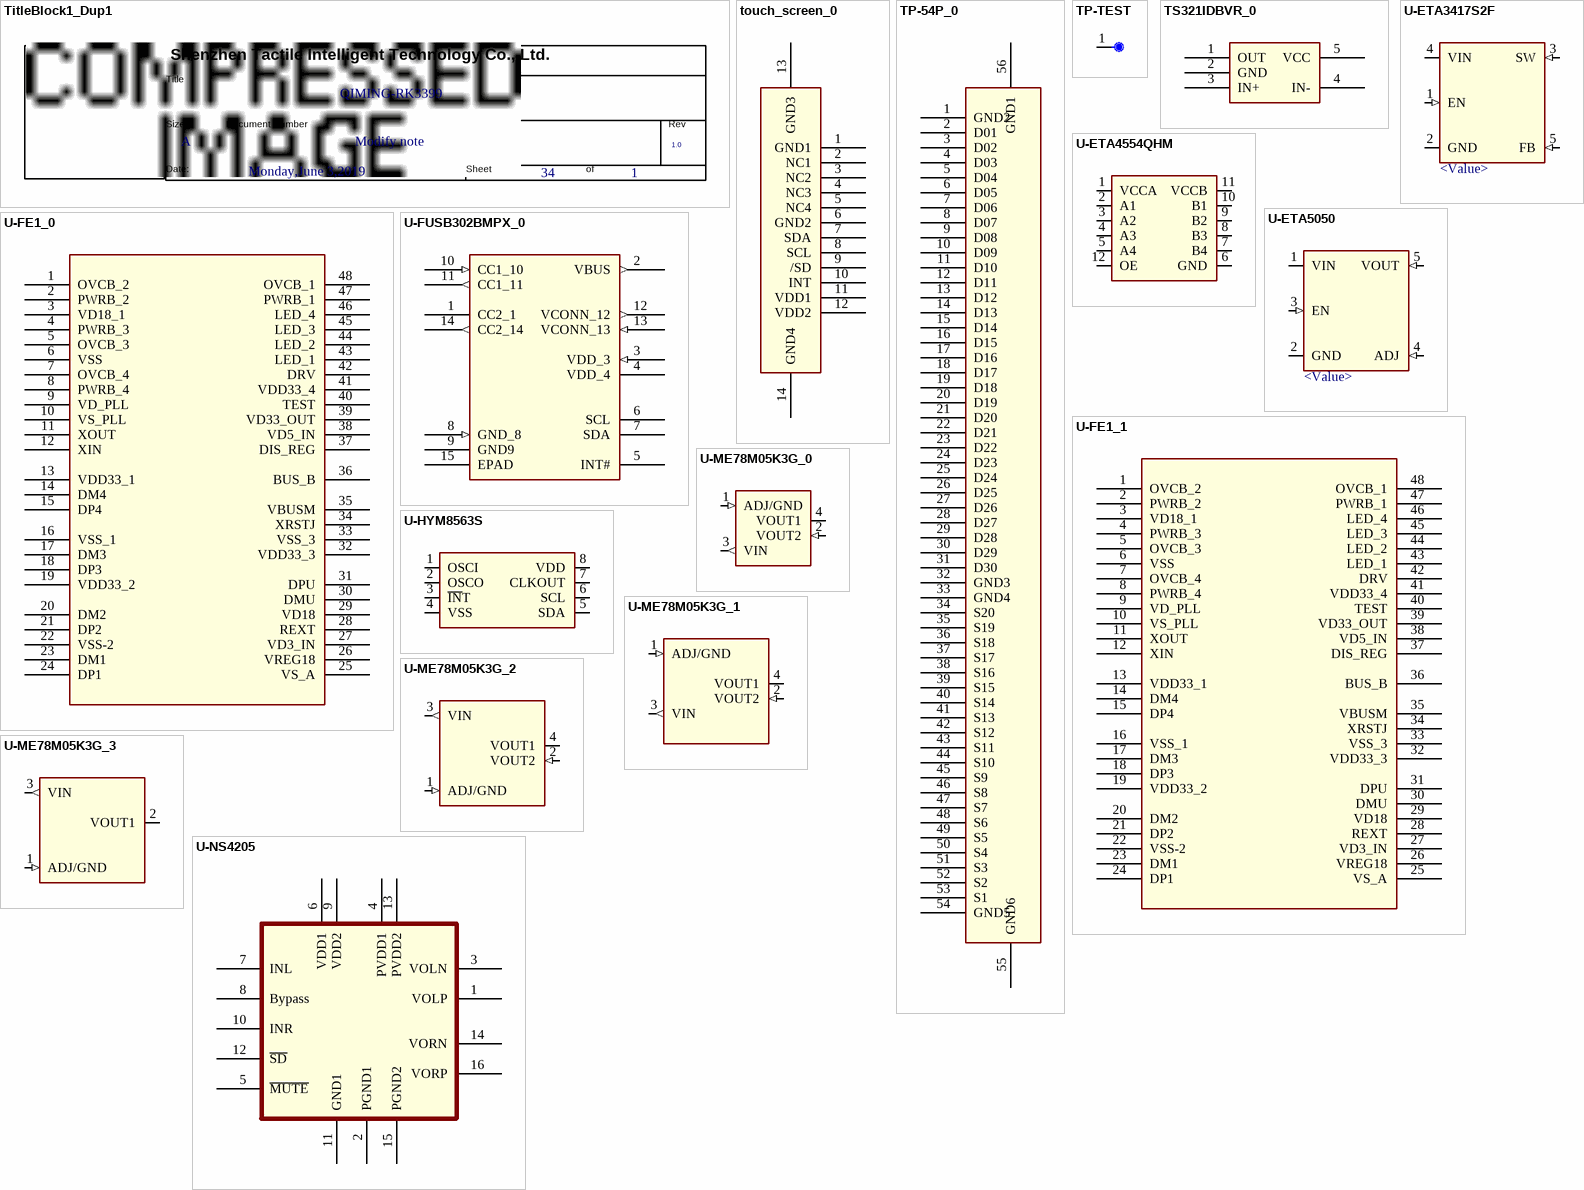
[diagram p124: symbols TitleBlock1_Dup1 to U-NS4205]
## TitleBlock1_Dup1
designator *  Page Modify Date: Monday,June 3,2019  Doc: Modify note  RevCode: 1.0  Title: QIMING-RK3399  Page Size: A  Page Number: 34  Page Count: 1  (hidden comment: *)  (graphical)

## touch_screen_0
designator J?
pins: 1 GND1, 2 NC1, 3 NC2, 4 NC3, 5 NC4, 6 GND2, 7 SDA, 8 SCL, 9 /SD, 10 INT, 11 VDD1, 12 VDD2, 13 GND3, 14 GND4

## TP-54P_0
designator U?
pins: 1 GND2, 2 D01, 3 D02, 4 D03, 5 D04, 6 D05, 7 D06, 8 D07, 9 D08, 10 D09, 11 D10, 12 D11, 13 D12, 14 D13, 15 D14, 16 D15, 17 D16, 18 D17, 19 D18, 20 D19, 21 D20, 22 D21, 23 D22, 24 D23, 25 D24, 26 D25, 27 D26, 28 D27, 29 D28, 30 D29, 31 D30, 32 GND3, 33 GND4, 34 S20, 35 S19, 36 S18, 37 S17, 38 S16, 39 S15, 40 S14, 41 S13, 42 S12, 43 S11, 44 S10, 45 S9, 46 S8, 47 S7, 48 S6, 49 S5, 50 S4, 51 S3, 52 S2, 53 S1, 54 GND5, 55 GND6, 56 GND1

## TP-TEST
designator TP?
Part Number: CAD
footprint smd_tp_1mm
pins: 1

## TS321IDBVR_0
designator U?
footprint SOT25
pins: 1 OUT, 2 GND, 3 IN+, 4 IN-, 5 VCC

## U-ETA3417S2F
designator U?, comment <Value>
pins: 1 EN (in), 2 GND (power), 3 SW (in), 4 VIN (power), 5 FB (in)

## U-ETA4554QHM
designator U?
pins: 1 VCCA, 2 A1, 3 A2, 4 A3, 5 A4, 6 GND, 7 B4, 8 B3, 9 B2, 10 B1, 11 VCCB, 12 OE

## U-ETA5050
designator U?, comment <Value>
pins: 1 VIN (power), 2 GND (power), 3 EN (in), 4 ADJ (in), 5 VOUT (in)

## U-FE1_0
designator U?
pins: 1 OVCB_2, 2 PWRB_2, 3 VD18_1, 4 PWRB_3, 5 OVCB_3, 6 VSS (power), 7 OVCB_4, 8 PWRB_4, 9 VD_PLL, 10 VS_PLL, 11 XOUT, 12 XIN, 13 VDD33_1, 14 DM4, 15 DP4 (power), 16 VSS_1, 17 DM3, 18 DP3, 19 VDD33_2, 20 DM2 (power), 21 DP2, 22 VSS-2, 23 DM1, 24 DP1, 25 VS_A, 26 VREG18 (power), 27 VD3_IN, 28 REXT (power), 29 VD18, 30 DMU, 31 DPU (power), 32 VDD33_3, 33 VSS_3, 34 XRSTJ, 35 VBUSM, 36 BUS_B (power), 37 DIS_REG, 38 VD5_IN, 39 VD33_OUT, 40 TEST, 41 VDD33_4, 42 DRV, 43 LED_1, 44 LED_2, 45 LED_3, 46 LED_4, 47 PWRB_1, 48 OVCB_1

## U-FE1_1
designator U?
pins: 1 OVCB_2, 2 PWRB_2, 3 VD18_1, 4 PWRB_3, 5 OVCB_3, 6 VSS (power), 7 OVCB_4, 8 PWRB_4, 9 VD_PLL, 10 VS_PLL, 11 XOUT, 12 XIN, 13 VDD33_1, 14 DM4, 15 DP4 (power), 16 VSS_1, 17 DM3, 18 DP3, 19 VDD33_2, 20 DM2 (power), 21 DP2, 22 VSS-2, 23 DM1, 24 DP1, 25 VS_A, 26 VREG18 (power), 27 VD3_IN, 28 REXT (power), 29 VD18, 30 DMU, 31 DPU (power), 32 VDD33_3, 33 VSS_3, 34 XRSTJ, 35 VBUSM, 36 BUS_B (power), 37 DIS_REG, 38 VD5_IN, 39 VD33_OUT, 40 TEST, 41 VDD33_4, 42 DRV, 43 LED_1, 44 LED_2, 45 LED_3, 46 LED_4, 47 PWRB_1, 48 OVCB_1

## U-FUSB302BMPX_0
designator U?
pins: 1 CC2_1, 2 VBUS (out), 3 VDD_3 (in), 4 VDD_4, 5 INT#, 6 SCL, 7 SDA, 8 GND_8 (in), 9 GND9, 10 CC1_10 (in), 11 CC1_11 (out), 12 VCONN_12 (out), 13 VCONN_13 (in), 14 CC2_14 (out), 15 EPAD

## U-HYM8563S
designator U?
pins: 1 OSCI, 2 OSCO, 3 ~{IN}T, 4 VSS, 5 SDA, 6 SCL, 7 CLKOUT, 8 VDD

## U-ME78M05K3G_0
designator U?
pins: 1 ADJ/GND (in), 2 VOUT2 (in), 3 VIN (out), 4 VOUT1

## U-ME78M05K3G_1
designator U?
pins: 1 ADJ/GND (in), 2 VOUT2 (in), 3 VIN (out), 4 VOUT1

## U-ME78M05K3G_2
designator U?
pins: 1 ADJ/GND (in), 2 VOUT2 (in), 3 VIN (out), 4 VOUT1

## U-ME78M05K3G_3
designator U?
pins: 1 ADJ/GND (in), 2 VOUT1, 3 VIN (out)

## U-NS4205
designator U?
pins: 1 VOLP, 2 PGND1, 3 VOLN, 4 PVDD1, 5 ~{MUTE}, 6 VDD1, 7 INL, 8 Bypass, 9 VDD2, 10 INR, 11 GND1, 12 ~{SD}, 13 PVDD2, 14 VORN, 15 PGND2, 16 VORP


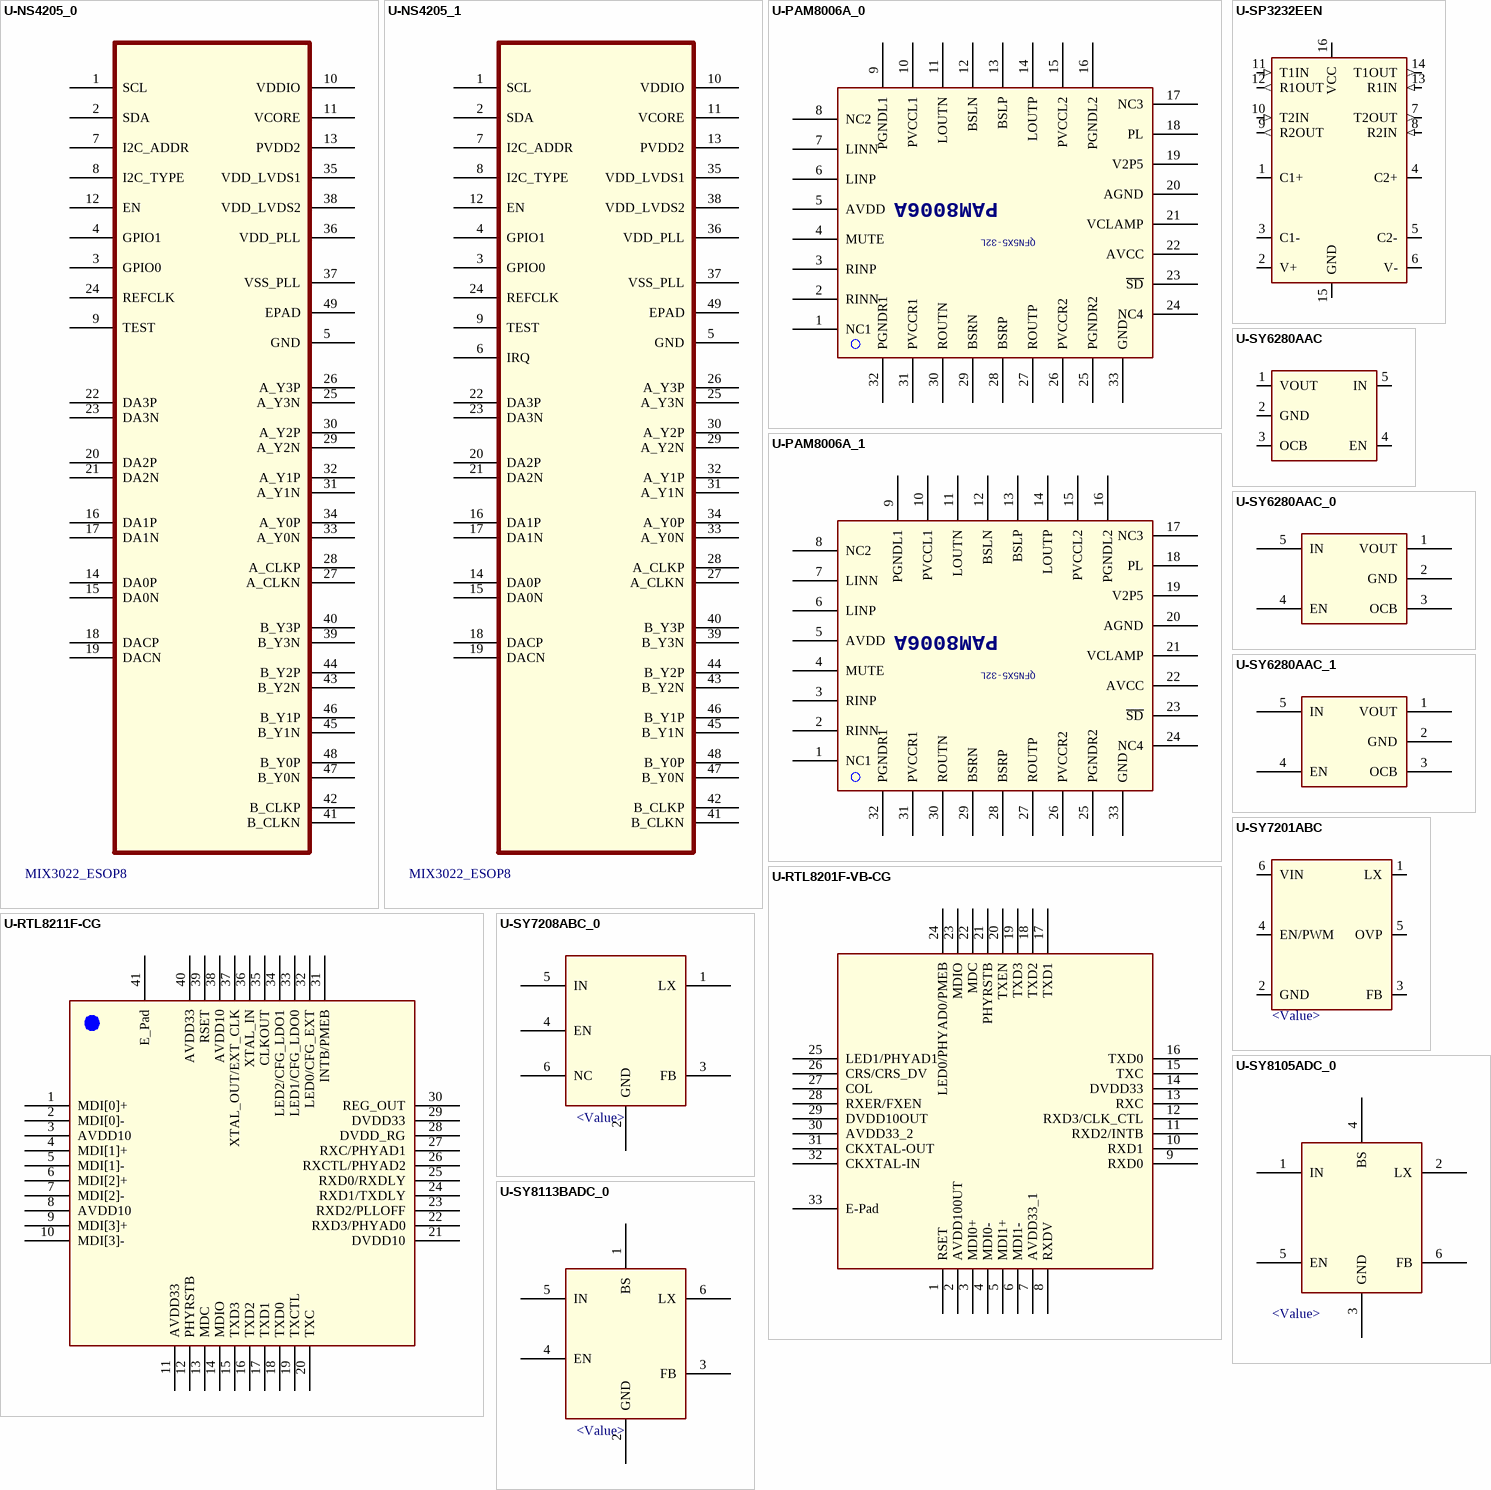
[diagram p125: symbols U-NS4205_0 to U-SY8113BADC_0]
## U-NS4205_0
designator U?, comment MIX3022_ESOP8
pins: 1 SCL, 2 SDA, 3 GPIO0, 4 GPIO1, 5 GND, 7 I2C_ADDR, 8 I2C_TYPE, 9 TEST, 10 VDDIO, 11 VCORE, 12 EN, 13 PVDD2, 14 DA0P, 15 DA0N, 16 DA1P, 17 DA1N, 18 DACP, 19 DACN, 20 DA2P, 21 DA2N, 22 DA3P, 23 DA3N, 24 REFCLK, 25 A_Y3N, 26 A_Y3P, 27 A_CLKN, 28 A_CLKP, 29 A_Y2N, 30 A_Y2P, 31 A_Y1N, 32 A_Y1P, 33 A_Y0N, 34 A_Y0P, 35 VDD_LVDS1, 36 VDD_PLL, 37 VSS_PLL, 38 VDD_LVDS2, 39 B_Y3N, 40 B_Y3P, 41 B_CLKN, 42 B_CLKP, 43 B_Y2N, 44 B_Y2P, 45 B_Y1N, 46 B_Y1P, 47 B_Y0N, 48 B_Y0P, 49 EPAD

## U-NS4205_1
designator U?, comment MIX3022_ESOP8
pins: 1 SCL, 2 SDA, 3 GPIO0, 4 GPIO1, 5 GND, 6 IRQ, 7 I2C_ADDR, 8 I2C_TYPE, 9 TEST, 10 VDDIO, 11 VCORE, 12 EN, 13 PVDD2, 14 DA0P, 15 DA0N, 16 DA1P, 17 DA1N, 18 DACP, 19 DACN, 20 DA2P, 21 DA2N, 22 DA3P, 23 DA3N, 24 REFCLK, 25 A_Y3N, 26 A_Y3P, 27 A_CLKN, 28 A_CLKP, 29 A_Y2N, 30 A_Y2P, 31 A_Y1N, 32 A_Y1P, 33 A_Y0N, 34 A_Y0P, 35 VDD_LVDS1, 36 VDD_PLL, 37 VSS_PLL, 38 VDD_LVDS2, 39 B_Y3N, 40 B_Y3P, 41 B_CLKN, 42 B_CLKP, 43 B_Y2N, 44 B_Y2P, 45 B_Y1N, 46 B_Y1P, 47 B_Y0N, 48 B_Y0P, 49 EPAD

## U-PAM8006A_0
designator U?
pins: 1 NC1, 2 RINN, 3 RINP, 4 MUTE, 5 AVDD, 6 LINP, 7 LINN, 8 NC2, 9 PGNDL1, 10 PVCCL1, 11 LOUTN, 12 BSLN, 13 BSLP, 14 LOUTP, 15 PVCCL2, 16 PGNDL2, 17 NC3, 18 PL, 19 V2P5, 20 AGND, 21 VCLAMP, 22 AVCC, 23 ~{SD}, 24 NC4, 25 PGNDR2, 26 PVCCR2, 27 ROUTP, 28 BSRP, 29 BSRN, 30 ROUTN, 31 PVCCR1, 32 PGNDR1, 33 GND

## U-PAM8006A_1
designator U?
pins: 1 NC1, 2 RINN, 3 RINP, 4 MUTE, 5 AVDD, 6 LINP, 7 LINN, 8 NC2, 9 PGNDL1, 10 PVCCL1, 11 LOUTN, 12 BSLN, 13 BSLP, 14 LOUTP, 15 PVCCL2, 16 PGNDL2, 17 NC3, 18 PL, 19 V2P5, 20 AGND, 21 VCLAMP, 22 AVCC, 23 ~{SD}, 24 NC4, 25 PGNDR2, 26 PVCCR2, 27 ROUTP, 28 BSRP, 29 BSRN, 30 ROUTN, 31 PVCCR1, 32 PGNDR1, 33 GND

## U-RTL8201F-VB-CG
designator U?
footprint QFN32-5X5
pins: 1 RSET, 2 AVDD100UT, 3 MDI0+, 4 MDI0-, 5 MDI1+, 6 MDI1-, 7 AVDD33_1, 8 RXDV, 9 RXD0, 10 RXD1, 11 RXD2/INTB, 12 RXD3/CLK_CTL, 13 RXC, 14 DVDD33, 15 TXC, 16 TXD0, 17 TXD1, 18 TXD2, 19 TXD3, 20 TXEN, 21 PHYRSTB, 22 MDC, 23 MDIO, 24 LED0/PHYAD0/PMEB, 25 LED1/PHYAD1, 26 CRS/CRS_DV, 27 COL, 28 RXER/FXEN, 29 DVDD10OUT, 30 AVDD33_2, 31 CKXTAL-OUT, 32 CKXTAL-IN, 33 E-Pad

## U-RTL8211F-CG
designator U?
pins: 1 MDI[0]+, 2 MDI[0]-, 3 AVDD10 (power), 4 MDI[1]+, 5 MDI[1]-, 6 MDI[2]+, 7 MDI[2]-, 8 AVDD10 (power), 9 MDI[3]+, 10 MDI[3]-, 11 AVDD33 (power), 12 PHYRSTB, 13 MDC, 14 MDIO, 15 TXD3, 16 TXD2, 17 TXD1, 18 TXD0, 19 TXCTL, 20 TXC, 21 DVDD10 (power), 22 RXD3/PHYAD0, 23 RXD2/PLLOFF, 24 RXD1/TXDLY, 25 RXD0/RXDLY, 26 RXCTL/PHYAD2, 27 RXC/PHYAD1, 28 DVDD_RG, 29 DVDD33 (power), 30 REG_OUT, 31 INTB/PMEB, 32 LED0/CFG_EXT, 33 LED1/CFG_LDO0, 34 LED2/CFG_LDO1, 35 CLKOUT, 36 XTAL_IN, 37 XTAL_OUT/EXT_CLK, 38 AVDD10 (power), 39 RSET, 40 AVDD33 (power), 41 E_Pad

## U-SP3232EEN
designator U?
pins: 1 C1+, 2 V+, 3 C1-, 4 C2+, 5 C2-, 6 V-, 7 T2OUT (out), 8 R2IN (in), 9 R2OUT (out), 10 T2IN (in), 11 T1IN (in), 12 R1OUT (out), 13 R1IN (in), 14 T1OUT (out), 15 GND (power), 16 VCC (power)

## U-SY6280AAC
designator U?
pins: 1 VOUT, 2 GND, 3 OCB, 4 EN, 5 IN

## U-SY6280AAC_0
designator U?
pins: 1 VOUT, 2 GND, 3 OCB, 4 EN, 5 IN

## U-SY6280AAC_1
designator U?
pins: 1 VOUT, 2 GND, 3 OCB, 4 EN, 5 IN

## U-SY7201ABC
designator U?, comment <Value>
pins: 1 LX, 2 GND, 3 FB, 4 EN/PWM, 5 OVP, 6 VIN

## U-SY7208ABC_0
designator U?, comment <Value>
pins: 1 LX, 2 GND, 3 FB, 4 EN, 5 IN, 6 NC

## U-SY8105ADC_0
designator U?, comment <Value>
pins: 1 IN, 2 LX, 3 GND, 4 BS, 5 EN, 6 FB

## U-SY8113BADC_0
designator U?, comment <Value>
pins: 1 BS, 2 GND, 3 FB, 4 EN, 5 IN, 6 LX


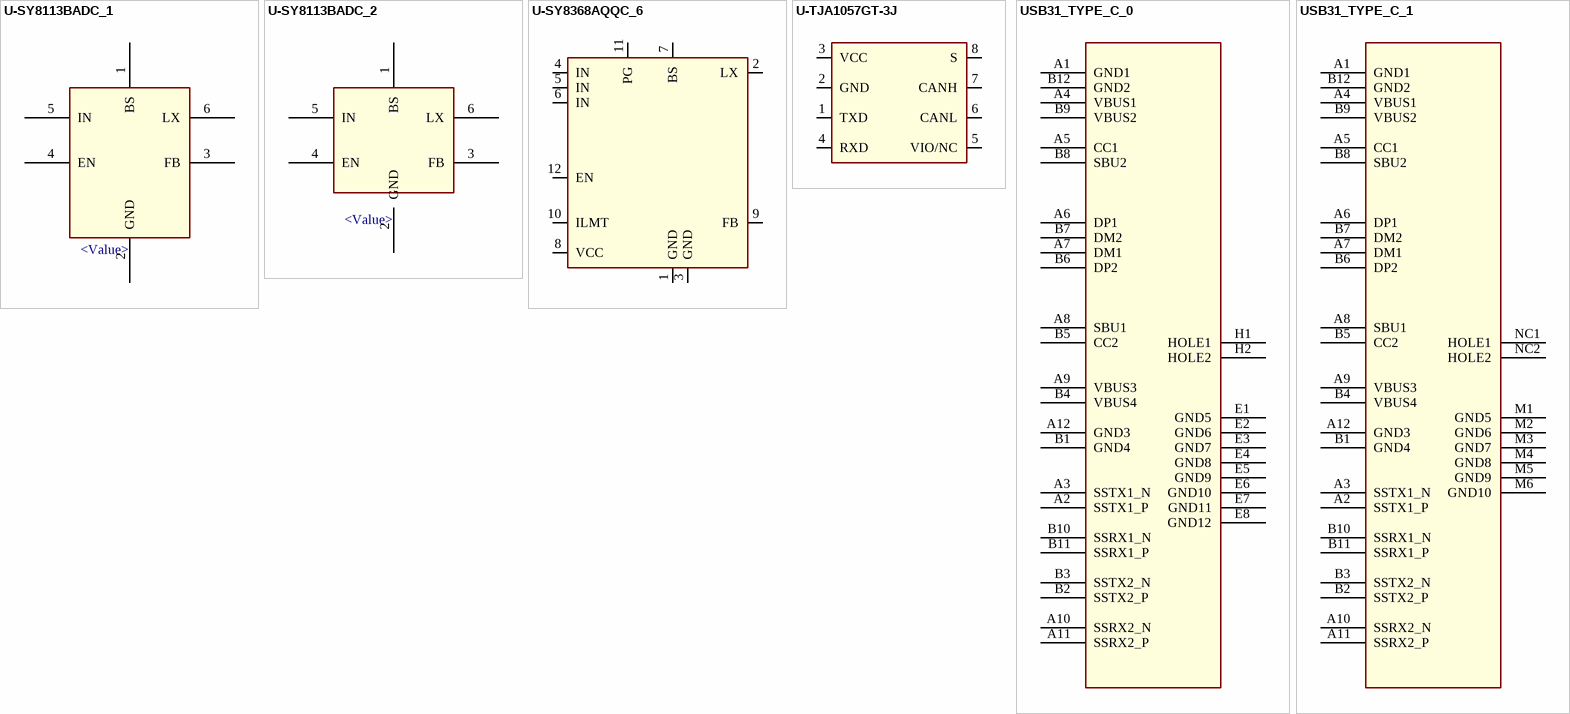
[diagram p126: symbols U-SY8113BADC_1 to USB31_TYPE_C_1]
## U-SY8113BADC_1
designator U?, comment <Value>
pins: 1 BS, 2 GND, 3 FB, 4 EN, 5 IN, 6 LX

## U-SY8113BADC_2
designator U?, comment <Value>
pins: 1 BS, 2 GND, 3 FB, 4 EN, 5 IN, 6 LX

## U-SY8368AQQC_6
designator U?
pins: 1 GND (power), 2 LX, 3 GND (power), 4 IN (power), 5 IN (power), 6 IN (power), 7 BS, 8 VCC, 9 FB, 10 ILMT, 11 PG, 12 EN

## U-TJA1057GT-3J
designator U?
pins: 1 TXD, 2 GND (power), 3 VCC (power), 4 RXD, 5 VIO/NC, 6 CANL, 7 CANH, 8 S

## USB31_TYPE_C_0
designator J?
pins: A1 GND1, A2 SSTX1_P, A3 SSTX1_N, A4 VBUS1, A5 CC1, A6 DP1, A7 DM1, A8 SBU1, A9 VBUS3, A10 SSRX2_N, A11 SSRX2_P, A12 GND3, B1 GND4, B2 SSTX2_P, B3 SSTX2_N, B4 VBUS4, B5 CC2, B6 DP2, B7 DM2, B8 SBU2, B9 VBUS2, B10 SSRX1_N, B11 SSRX1_P, B12 GND2, E1 GND5, E2 GND6, E3 GND7, E4 GND8, E5 GND9, E6 GND10, E7 GND11, E8 GND12, H1 HOLE1, H2 HOLE2

## USB31_TYPE_C_1
designator J?
pins: A1 GND1, A2 SSTX1_P, A3 SSTX1_N, A4 VBUS1, A5 CC1, A6 DP1, A7 DM1, A8 SBU1, A9 VBUS3, A10 SSRX2_N, A11 SSRX2_P, A12 GND3, B1 GND4, B2 SSTX2_P, B3 SSTX2_N, B4 VBUS4, B5 CC2, B6 DP2, B7 DM2, B8 SBU2, B9 VBUS2, B10 SSRX1_N, B11 SSRX1_P, B12 GND2, M1 GND5, M2 GND6, M3 GND7, M4 GND8, M5 GND9, M6 GND10, NC1 HOLE1, NC2 HOLE2


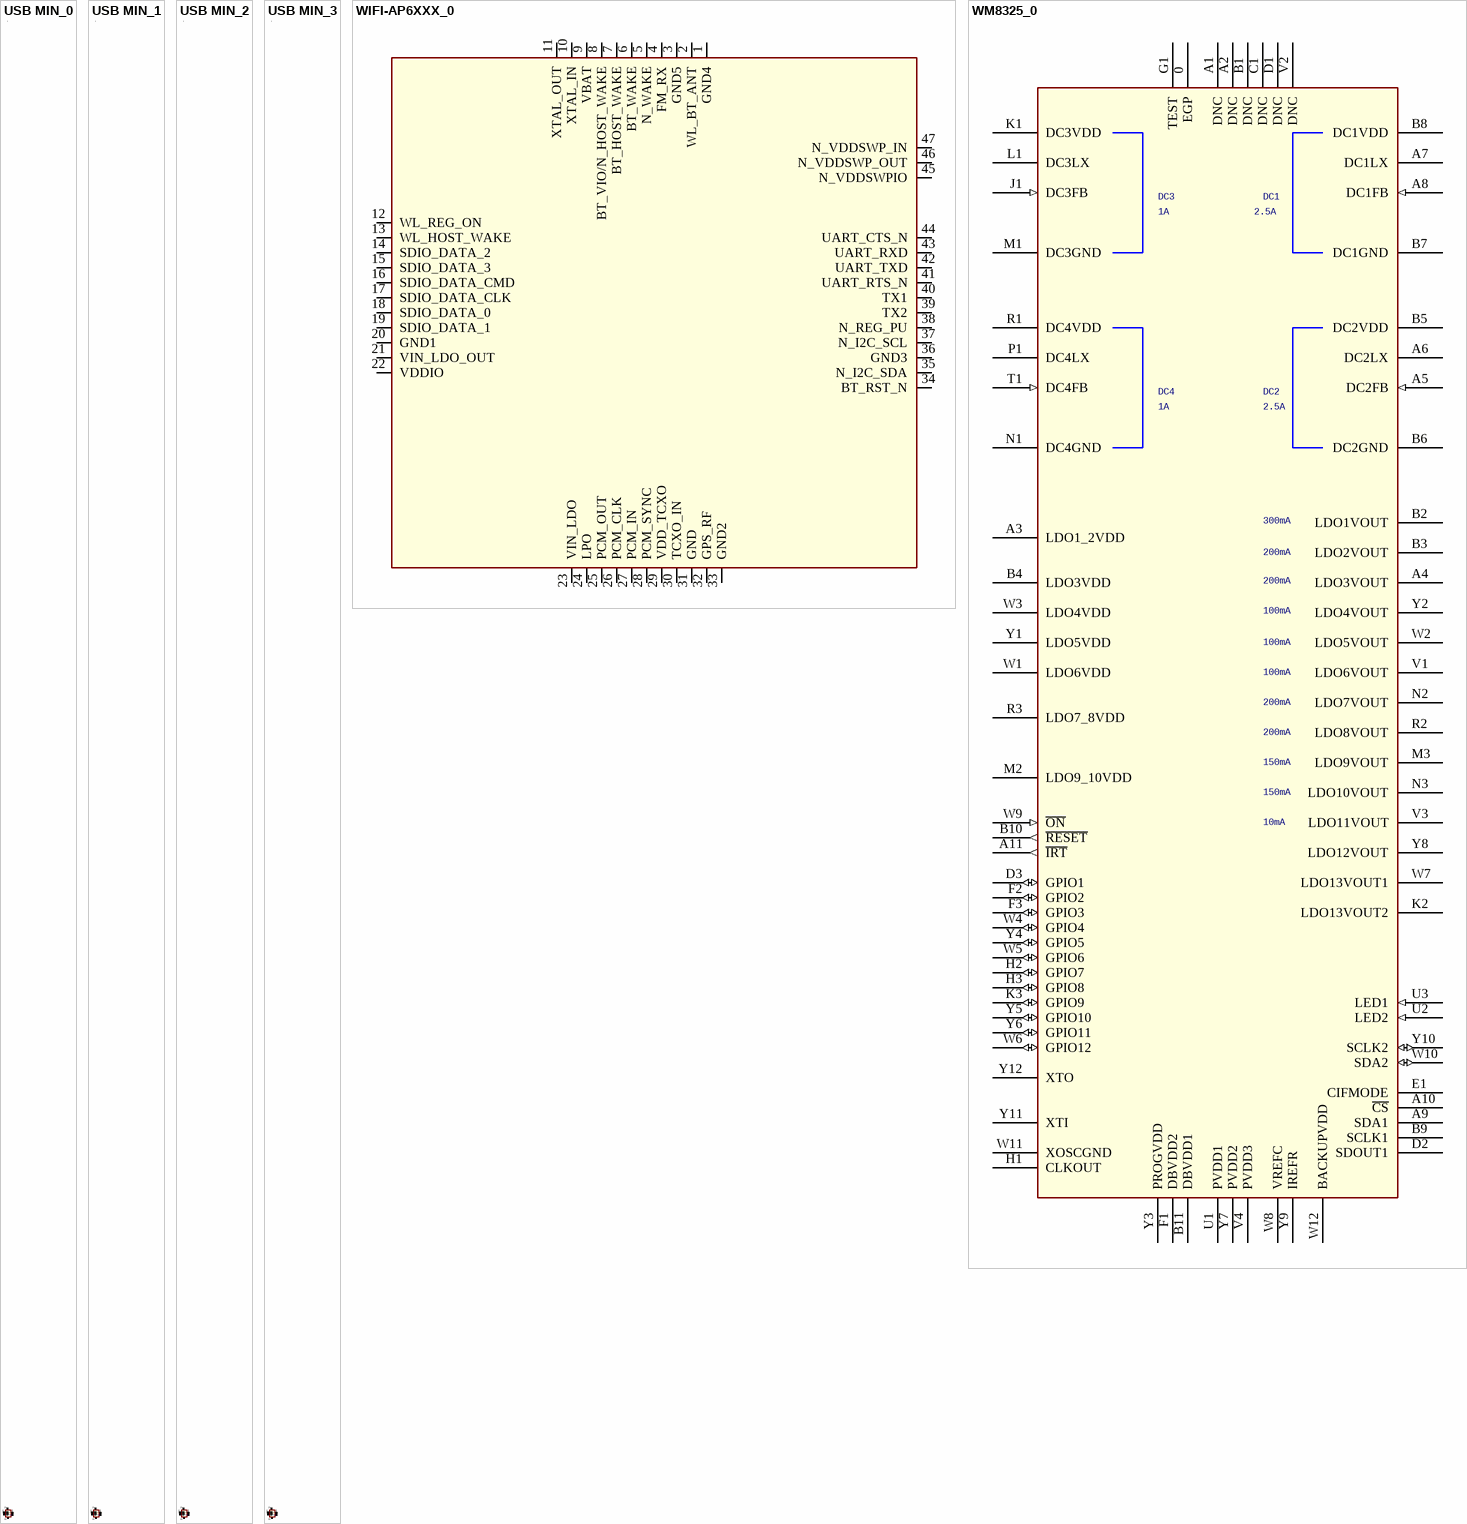
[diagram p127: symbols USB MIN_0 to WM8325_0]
## USB MIN_0
designator J?, comment USBmin
pins: 1 NC, 2 VBUS, 3 TD_DM, 4 DM, 5 NC (power), 6 DP, 7 NC, 8 ID, 9 NC, 10 GND, 11 GND, 12 GND, 13 GND, 14 GND

## USB MIN_1
designator J?, comment USBmin
pins: 1 NC, 2 VBUS, 3 TD_DM, 4 DM, 5 NC (power), 6 DP, 7 NC, 8 ID, 9 NC, 10 GND, 11 GND, 12 GND, 13 GND, 14 GND

## USB MIN_2
designator J?, comment USBmin
pins: 1 NC, 2 VBUS, 3 TD_DM, 4 DM, 5 NC, 6 DP, 7 NC, 8 ID, 9 NC, 10 GND, 11 GND, 12 GND, 13 GND, 14 GND

## USB MIN_3
designator J?, comment USBmin
pins: 1 NC, 2 VBUS, 3 TD_DM, 4 DM, 5 NC, 6 DP, 7 NC, 8 ID, 9 NC, 10 GND, 11 GND, 12 GND, 13 GND, 14 GND

## WIFI-AP6XXX_0
designator U?
pins: 1 GND4, 2 WL_BT_ANT, 3 GND5, 4 FM_RX, 5 N_WAKE, 6 BT_WAKE, 7 BT_HOST_WAKE, 8 BT_VIO/N_HOST_WAKE, 9 VBAT, 10 XTAL_IN, 11 XTAL_OUT, 12 WL_REG_ON, 13 WL_HOST_WAKE, 14 SDIO_DATA_2, 15 SDIO_DATA_3, 16 SDIO_DATA_CMD, 17 SDIO_DATA_CLK, 18 SDIO_DATA_0, 19 SDIO_DATA_1, 20 GND1, 21 VIN_LDO_OUT, 22 VDDIO, 23 VIN_LDO, 24 LPO, 25 PCM_OUT, 26 PCM_CLK, 27 PCM_IN, 28 PCM_SYNC, 29 VDD_TCXO, 30 TCXO_IN, 31 GND, 32 GPS_RF, 33 GND2, 34 BT_RST_N, 35 N_I2C_SDA, 36 GND3, 37 N_I2C_SCL, 38 N_REG_PU, 39 TX2, 40 TX1, 41 UART_RTS_N, 42 UART_TXD, 43 UART_RXD, 44 UART_CTS_N, 45 N_VDDSWPIO, 46 N_VDDSWP_OUT, 47 N_VDDSWP_IN

## WM8325_0
designator U?
footprint QFN81-8X8
pins: 0 EGP, A1 DNC, A2 DNC, A3 LDO1_2VDD (power), A4 LDO3VOUT (power), A5 DC2FB (in), A6 DC2LX (power), A7 DC1LX (power), A8 DC1FB (in), A9 SDA1, A10 ~{CS}, A11 ~{IRT} (out), B1 DNC, B2 LDO1VOUT (power), B3 LDO2VOUT (power), B4 LDO3VDD (power), B5 DC2VDD (power), B6 DC2GND (power), B7 DC1GND (power), B8 DC1VDD (power), B9 SCLK1, B10 ~{RESET} (out), B11 DBVDD1, C1 DNC, D1 DNC, D2 SDOUT1, D3 GPIO1 (io), E1 CIFMODE, F1 DBVDD2, F2 GPIO2 (io), F3 GPIO3 (io), G1 TEST, H1 CLKOUT, H2 GPIO7 (io), H3 GPIO8 (io), J1 DC3FB (in), K1 DC3VDD (power), K2 LDO13VOUT2 (power), K3 GPIO9 (io), L1 DC3LX (power), M1 DC3GND (power), M2 LDO9_10VDD (power), M3 LDO9VOUT (power), N1 DC4GND (power), N2 LDO7VOUT (power), N3 LDO10VOUT (power), P1 DC4LX (power), R1 DC4VDD (power), R2 LDO8VOUT (power), R3 LDO7_8VDD (power), T1 DC4FB (in), U1 PVDD1, U2 LED2 (in), U3 LED1 (in), V1 LDO6VOUT (power), V2 DNC, V3 LDO11VOUT (power), V4 PVDD3, W1 LDO6VDD (power), W2 LDO5VOUT (power), W3 LDO4VDD (power), W4 GPIO4 (io), W5 GPIO6 (io), W6 GPIO12 (io), W7 LDO13VOUT1 (power), W8 VREFC, W9 ~{ON} (in), W10 SDA2 (io), W11 XOSCGND, W12 BACKUPVDD, Y1 LDO5VDD (power), Y2 LDO4VOUT (power), Y3 PROGVDD, Y4 GPIO5 (io), Y5 GPIO10 (io), Y6 GPIO11 (io), Y7 PVDD2, Y8 LDO12VOUT (power), Y9 IREFR, Y10 SCLK2 (io), Y11 XTI, Y12 XTO


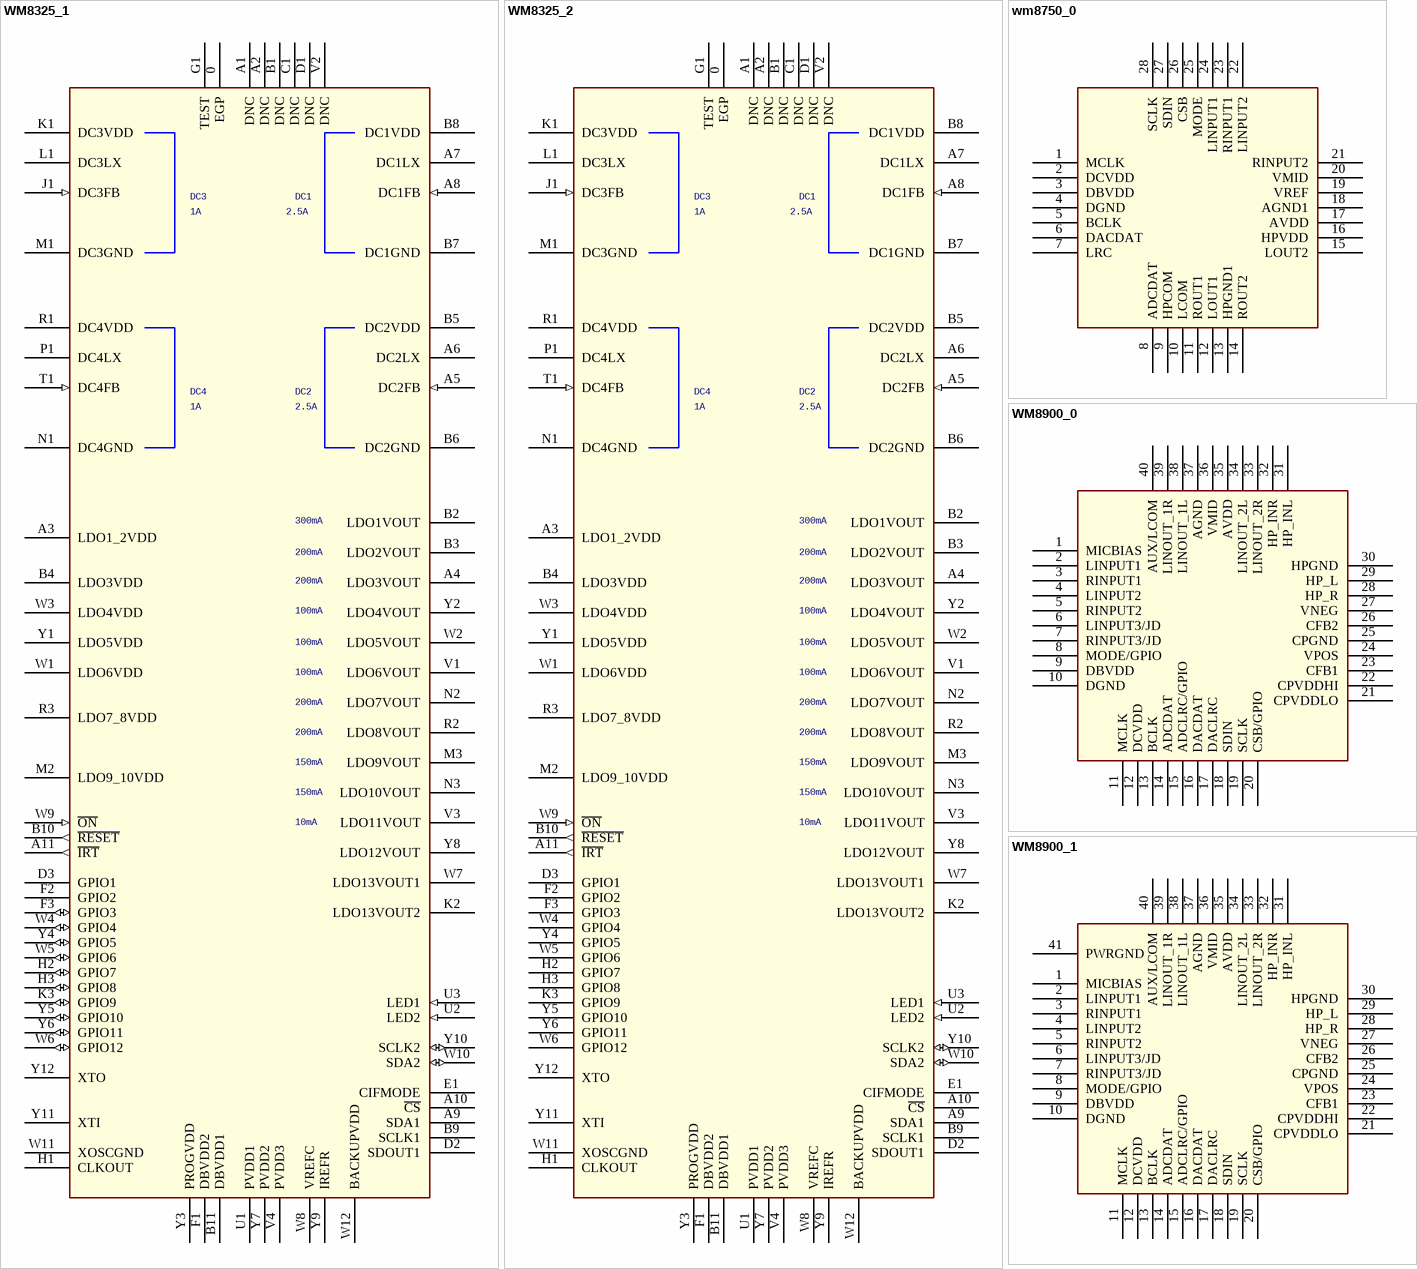
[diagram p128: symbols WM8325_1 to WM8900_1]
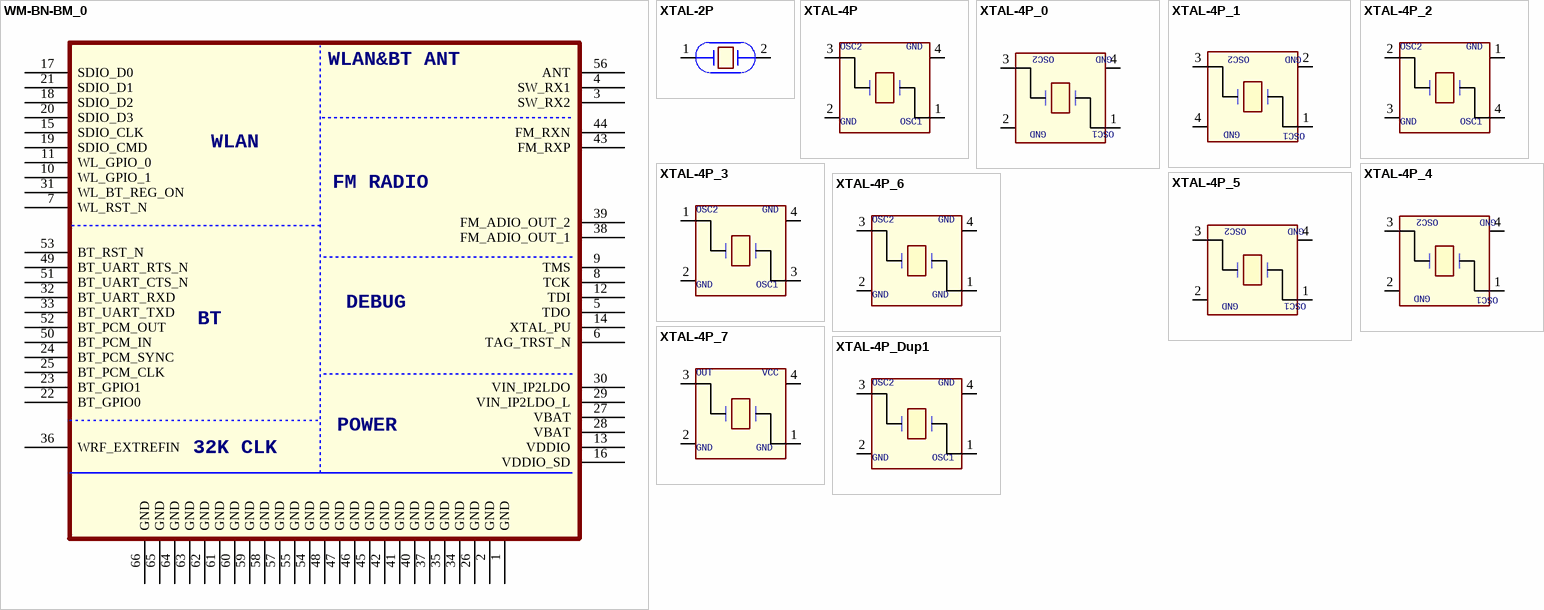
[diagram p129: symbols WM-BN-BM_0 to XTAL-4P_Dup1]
## WM8325_1
designator U?
footprint QFN81-8X8
pins: 0 EGP, A1 DNC, A2 DNC, A3 LDO1_2VDD (power), A4 LDO3VOUT (power), A5 DC2FB (in), A6 DC2LX (power), A7 DC1LX (power), A8 DC1FB (in), A9 SDA1, A10 ~{CS}, A11 ~{IRT} (out), B1 DNC, B2 LDO1VOUT (power), B3 LDO2VOUT (power), B4 LDO3VDD (power), B5 DC2VDD (power), B6 DC2GND (power), B7 DC1GND (power), B8 DC1VDD (power), B9 SCLK1, B10 ~{RESET} (out), B11 DBVDD1, C1 DNC, D1 DNC, D2 SDOUT1, D3 GPIO1, E1 CIFMODE, F1 DBVDD2, F2 GPIO2, F3 GPIO3 (io), G1 TEST, H1 CLKOUT, H2 GPIO7 (io), H3 GPIO8 (io), J1 DC3FB (in), K1 DC3VDD (power), K2 LDO13VOUT2 (power), K3 GPIO9 (io), L1 DC3LX (power), M1 DC3GND (power), M2 LDO9_10VDD (power), M3 LDO9VOUT (power), N1 DC4GND (power), N2 LDO7VOUT (power), N3 LDO10VOUT (power), P1 DC4LX (power), R1 DC4VDD (power), R2 LDO8VOUT (power), R3 LDO7_8VDD (power), T1 DC4FB (in), U1 PVDD1, U2 LED2 (in), U3 LED1 (in), V1 LDO6VOUT (power), V2 DNC, V3 LDO11VOUT (power), V4 PVDD3, W1 LDO6VDD (power), W2 LDO5VOUT (power), W3 LDO4VDD (power), W4 GPIO4 (io), W5 GPIO6 (io), W6 GPIO12 (io), W7 LDO13VOUT1 (power), W8 VREFC, W9 ~{ON} (in), W10 SDA2 (io), W11 XOSCGND, W12 BACKUPVDD, Y1 LDO5VDD (power), Y2 LDO4VOUT (power), Y3 PROGVDD, Y4 GPIO5 (io), Y5 GPIO10 (io), Y6 GPIO11 (io), Y7 PVDD2, Y8 LDO12VOUT (power), Y9 IREFR, Y10 SCLK2 (io), Y11 XTI, Y12 XTO

## WM8325_2
designator U?
footprint QFN81-8X8
pins: 0 EGP, A1 DNC, A2 DNC, A3 LDO1_2VDD (power), A4 LDO3VOUT (power), A5 DC2FB (in), A6 DC2LX (power), A7 DC1LX (power), A8 DC1FB (in), A9 SDA1, A10 ~{CS}, A11 ~{IRT} (out), B1 DNC, B2 LDO1VOUT (power), B3 LDO2VOUT (power), B4 LDO3VDD (power), B5 DC2VDD (power), B6 DC2GND (power), B7 DC1GND (power), B8 DC1VDD (power), B9 SCLK1, B10 ~{RESET} (out), B11 DBVDD1, C1 DNC, D1 DNC, D2 SDOUT1, D3 GPIO1, E1 CIFMODE, F1 DBVDD2, F2 GPIO2, F3 GPIO3, G1 TEST, H1 CLKOUT, H2 GPIO7, H3 GPIO8, J1 DC3FB (in), K1 DC3VDD (power), K2 LDO13VOUT2 (power), K3 GPIO9, L1 DC3LX (power), M1 DC3GND (power), M2 LDO9_10VDD (power), M3 LDO9VOUT (power), N1 DC4GND (power), N2 LDO7VOUT (power), N3 LDO10VOUT (power), P1 DC4LX (power), R1 DC4VDD (power), R2 LDO8VOUT (power), R3 LDO7_8VDD (power), T1 DC4FB (in), U1 PVDD1, U2 LED2 (in), U3 LED1 (in), V1 LDO6VOUT (power), V2 DNC, V3 LDO11VOUT (power), V4 PVDD3, W1 LDO6VDD (power), W2 LDO5VOUT (power), W3 LDO4VDD (power), W4 GPIO4, W5 GPIO6, W6 GPIO12, W7 LDO13VOUT1 (power), W8 VREFC, W9 ~{ON} (in), W10 SDA2 (io), W11 XOSCGND, W12 BACKUPVDD, Y1 LDO5VDD (power), Y2 LDO4VOUT (power), Y3 PROGVDD, Y4 GPIO5, Y5 GPIO10, Y6 GPIO11, Y7 PVDD2, Y8 LDO12VOUT (power), Y9 IREFR, Y10 SCLK2 (io), Y11 XTI, Y12 XTO

## wm8750_0
designator U?
pins: 1 MCLK, 2 DCVDD, 3 DBVDD, 4 DGND, 5 BCLK, 6 DACDAT, 7 LRC, 8 ADCDAT, 9 HPCOM, 10 LCOM, 11 ROUT1, 12 LOUT1, 13 HPGND1, 14 ROUT2, 15 LOUT2, 16 HPVDD, 17 AVDD, 18 AGND1, 19 VREF, 20 VMID, 21 RINPUT2, 22 LINPUT2, 23 RINPUT1, 24 LINPUT1, 25 MODE, 26 CSB, 27 SDIN, 28 SCLK

## WM8900_0
designator U?
footprint QFN40
pins: 1 MICBIAS, 2 LINPUT1, 3 RINPUT1, 4 LINPUT2, 5 RINPUT2, 6 LINPUT3/JD, 7 RINPUT3/JD, 8 MODE/GPIO, 9 DBVDD, 10 DGND, 11 MCLK, 12 DCVDD, 13 BCLK, 14 ADCDAT, 15 ADCLRC/GPIO, 16 DACDAT, 17 DACLRC, 18 SDIN, 19 SCLK, 20 CSB/GPIO, 21 CPVDDLO, 22 CPVDDHI, 23 CFB1, 24 VPOS, 25 CPGND, 26 CFB2, 27 VNEG, 28 HP_R, 29 HP_L, 30 HPGND, 31 HP_INL, 32 HP_INR, 33 LINOUT_2R, 34 LINOUT_2L, 35 AVDD, 36 VMID, 37 AGND, 38 LINOUT_1L, 39 LINOUT_1R, 40 AUX/LCOM

## WM8900_1
designator U?
footprint QFN40
pins: 1 MICBIAS, 2 LINPUT1, 3 RINPUT1, 4 LINPUT2, 5 RINPUT2, 6 LINPUT3/JD, 7 RINPUT3/JD, 8 MODE/GPIO, 9 DBVDD, 10 DGND, 11 MCLK, 12 DCVDD, 13 BCLK, 14 ADCDAT, 15 ADCLRC/GPIO, 16 DACDAT, 17 DACLRC, 18 SDIN, 19 SCLK, 20 CSB/GPIO, 21 CPVDDLO, 22 CPVDDHI, 23 CFB1, 24 VPOS, 25 CPGND, 26 CFB2, 27 VNEG, 28 HP_R, 29 HP_L, 30 HPGND, 31 HP_INL, 32 HP_INR, 33 LINOUT_2R, 34 LINOUT_2L, 35 AVDD, 36 VMID, 37 AGND, 38 LINOUT_1L, 39 LINOUT_1R, 40 AUX/LCOM, 41 PWRGND

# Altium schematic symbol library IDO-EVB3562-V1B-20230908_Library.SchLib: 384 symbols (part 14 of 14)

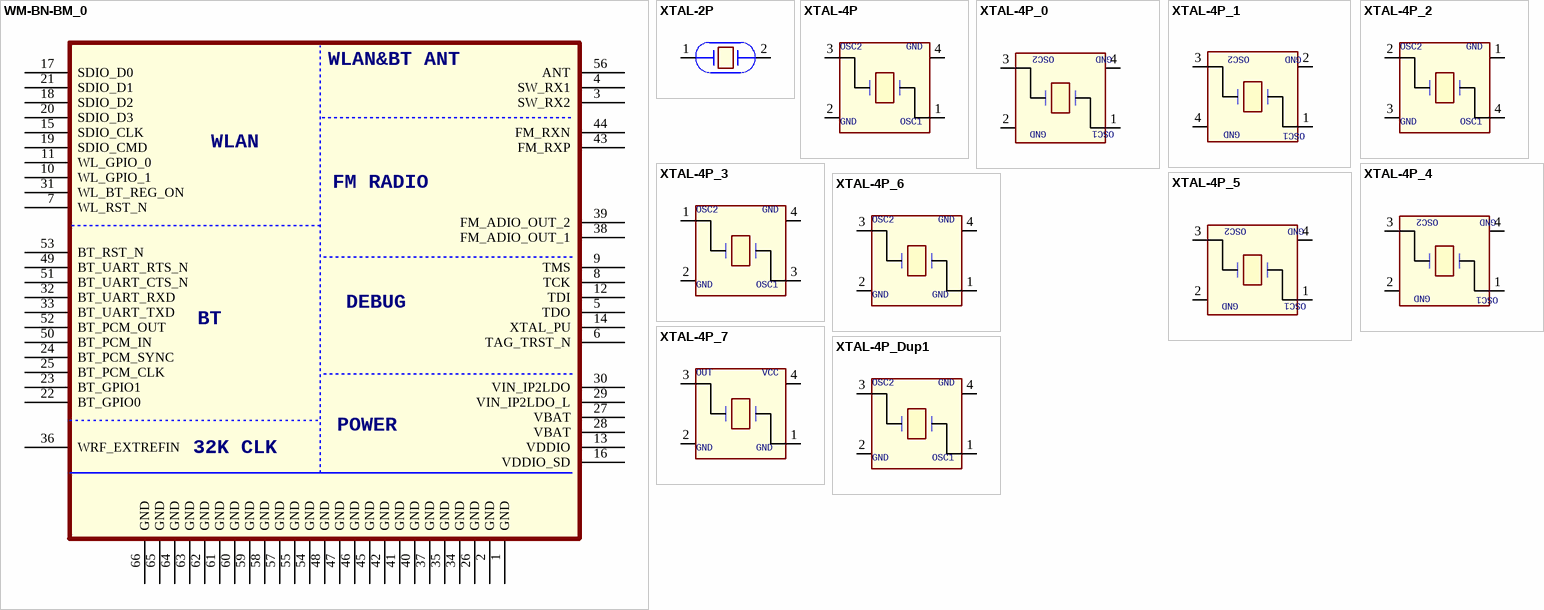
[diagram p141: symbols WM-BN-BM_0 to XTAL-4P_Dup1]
## WM-BN-BM_0
designator U?
footprint LGA66
pins: 1 GND, 2 GND, 3 SW_RX2, 4 SW_RX1, 5 TDO, 6 TAG_TRST_N, 7 WL_RST_N, 8 TCK, 9 TMS, 10 WL_GPIO_1, 11 WL_GPIO_0, 12 TDI, 13 VDDIO, 14 XTAL_PU, 15 SDIO_CLK, 16 VDDIO_SD, 17 SDIO_D0, 18 SDIO_D2, 19 SDIO_CMD, 20 SDIO_D3, 21 SDIO_D1, 22 BT_GPIO0, 23 BT_GPIO1, 24 BT_PCM_SYNC, 25 BT_PCM_CLK, 26 GND, 27 VBAT, 28 VBAT, 29 VIN_IP2LDO_L, 30 VIN_IP2LDO, 31 WL_BT_REG_ON, 32 BT_UART_RXD, 33 BT_UART_TXD, 34 GND, 35 GND, 36 WRF_EXTREFIN, 37 GND, 38 FM_ADIO_OUT_1, 39 FM_ADIO_OUT_2, 40 GND, 41 GND, 42 GND, 43 FM_RXP, 44 FM_RXN, 45 GND, 46 GND, 47 GND, 48 GND, 49 BT_UART_RTS_N, 50 BT_PCM_IN, 51 BT_UART_CTS_N, 52 BT_PCM_OUT, 53 BT_RST_N, 54 GND, 55 GND, 56 ANT, 57 GND, 58 GND, 59 GND, 60 GND, 61 GND, 62 GND, 63 GND, 64 GND, 65 GND, 66 GND

## XTAL-2P
designator XT?
CLASS: IC
pins: 1, 2

## XTAL-4P
designator XT?
CLASS: IC
pins: 1, 2, 3, 4

## XTAL-4P_0
designator XT?
CLASS: IC
pins: 1, 2, 3, 4

## XTAL-4P_1
designator XT?
CLASS: IC
pins: 1, 2, 3, 4

## XTAL-4P_2
designator XT?
CLASS: IC
pins: 1, 2, 3, 4

## XTAL-4P_3
designator XT?
CLASS: IC
pins: 1, 2, 3, 4

## XTAL-4P_4
designator XT?
CLASS: IC
pins: 1, 2, 3, 4

## XTAL-4P_5
designator XT?
CLASS: IC
pins: 1, 2, 3, 4

## XTAL-4P_6
designator XT?
CLASS: IC
pins: 1, 2, 3 OUT, 4

## XTAL-4P_7
designator XT?
CLASS: IC
pins: 1, 2, 3, 4

## XTAL-4P_Dup1
designator XT?
CLASS: IC
pins: 1, 2, 3, 4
